VERSION 5.8 ;
BUSBITCHARS "[]" ;
DIVIDERCHAR "/" ;
UNITS
    DATABASE MICRONS 1000 ;
END UNITS

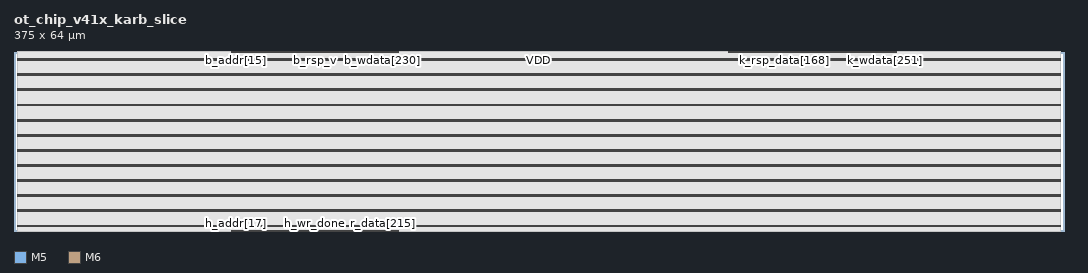
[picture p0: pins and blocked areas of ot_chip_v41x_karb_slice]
MACRO ot_chip_v41x_karb_slice
  FOREIGN ot_chip_v41x_karb_slice 0 0 ;
  CLASS BLOCK ;
  SIZE 375 BY 64 ;
  PIN b_addr[0]
    DIRECTION INPUT ;
    USE SIGNAL ;
    PORT
      LAYER M5 ;
        RECT  77.856 63.916 77.88 64 ;
    END
  END b_addr[0]
  PIN b_addr[10]
    DIRECTION INPUT ;
    USE SIGNAL ;
    PORT
      LAYER M5 ;
        RECT  78.816 63.916 78.84 64 ;
    END
  END b_addr[10]
  PIN b_addr[11]
    DIRECTION INPUT ;
    USE SIGNAL ;
    PORT
      LAYER M5 ;
        RECT  78.912 63.916 78.936 64 ;
    END
  END b_addr[11]
  PIN b_addr[12]
    DIRECTION INPUT ;
    USE SIGNAL ;
    PORT
      LAYER M5 ;
        RECT  79.008 63.916 79.032 64 ;
    END
  END b_addr[12]
  PIN b_addr[13]
    DIRECTION INPUT ;
    USE SIGNAL ;
    PORT
      LAYER M5 ;
        RECT  79.104 63.916 79.128 64 ;
    END
  END b_addr[13]
  PIN b_addr[14]
    DIRECTION INPUT ;
    USE SIGNAL ;
    PORT
      LAYER M5 ;
        RECT  79.2 63.916 79.224 64 ;
    END
  END b_addr[14]
  PIN b_addr[15]
    DIRECTION INPUT ;
    USE SIGNAL ;
    PORT
      LAYER M5 ;
        RECT  79.296 63.916 79.32 64 ;
    END
  END b_addr[15]
  PIN b_addr[16]
    DIRECTION INPUT ;
    USE SIGNAL ;
    PORT
      LAYER M5 ;
        RECT  79.392 63.916 79.416 64 ;
    END
  END b_addr[16]
  PIN b_addr[17]
    DIRECTION INPUT ;
    USE SIGNAL ;
    PORT
      LAYER M5 ;
        RECT  79.488 63.916 79.512 64 ;
    END
  END b_addr[17]
  PIN b_addr[18]
    DIRECTION INPUT ;
    USE SIGNAL ;
    PORT
      LAYER M5 ;
        RECT  79.584 63.916 79.608 64 ;
    END
  END b_addr[18]
  PIN b_addr[19]
    DIRECTION INPUT ;
    USE SIGNAL ;
    PORT
      LAYER M5 ;
        RECT  79.68 63.916 79.704 64 ;
    END
  END b_addr[19]
  PIN b_addr[1]
    DIRECTION INPUT ;
    USE SIGNAL ;
    PORT
      LAYER M5 ;
        RECT  77.952 63.916 77.976 64 ;
    END
  END b_addr[1]
  PIN b_addr[20]
    DIRECTION INPUT ;
    USE SIGNAL ;
    PORT
      LAYER M5 ;
        RECT  79.776 63.916 79.8 64 ;
    END
  END b_addr[20]
  PIN b_addr[21]
    DIRECTION INPUT ;
    USE SIGNAL ;
    PORT
      LAYER M5 ;
        RECT  79.872 63.916 79.896 64 ;
    END
  END b_addr[21]
  PIN b_addr[22]
    DIRECTION INPUT ;
    USE SIGNAL ;
    PORT
      LAYER M5 ;
        RECT  79.968 63.916 79.992 64 ;
    END
  END b_addr[22]
  PIN b_addr[23]
    DIRECTION INPUT ;
    USE SIGNAL ;
    PORT
      LAYER M5 ;
        RECT  80.064 63.916 80.088 64 ;
    END
  END b_addr[23]
  PIN b_addr[24]
    DIRECTION INPUT ;
    USE SIGNAL ;
    PORT
      LAYER M5 ;
        RECT  80.16 63.916 80.184 64 ;
    END
  END b_addr[24]
  PIN b_addr[25]
    DIRECTION INPUT ;
    USE SIGNAL ;
    PORT
      LAYER M5 ;
        RECT  80.256 63.916 80.28 64 ;
    END
  END b_addr[25]
  PIN b_addr[26]
    DIRECTION INPUT ;
    USE SIGNAL ;
    PORT
      LAYER M5 ;
        RECT  80.352 63.916 80.376 64 ;
    END
  END b_addr[26]
  PIN b_addr[27]
    DIRECTION INPUT ;
    USE SIGNAL ;
    PORT
      LAYER M5 ;
        RECT  80.448 63.916 80.472 64 ;
    END
  END b_addr[27]
  PIN b_addr[28]
    DIRECTION INPUT ;
    USE SIGNAL ;
    PORT
      LAYER M5 ;
        RECT  80.544 63.916 80.568 64 ;
    END
  END b_addr[28]
  PIN b_addr[29]
    DIRECTION INPUT ;
    USE SIGNAL ;
    PORT
      LAYER M5 ;
        RECT  80.64 63.916 80.664 64 ;
    END
  END b_addr[29]
  PIN b_addr[2]
    DIRECTION INPUT ;
    USE SIGNAL ;
    PORT
      LAYER M5 ;
        RECT  78.048 63.916 78.072 64 ;
    END
  END b_addr[2]
  PIN b_addr[3]
    DIRECTION INPUT ;
    USE SIGNAL ;
    PORT
      LAYER M5 ;
        RECT  78.144 63.916 78.168 64 ;
    END
  END b_addr[3]
  PIN b_addr[4]
    DIRECTION INPUT ;
    USE SIGNAL ;
    PORT
      LAYER M5 ;
        RECT  78.24 63.916 78.264 64 ;
    END
  END b_addr[4]
  PIN b_addr[5]
    DIRECTION INPUT ;
    USE SIGNAL ;
    PORT
      LAYER M5 ;
        RECT  78.336 63.916 78.36 64 ;
    END
  END b_addr[5]
  PIN b_addr[6]
    DIRECTION INPUT ;
    USE SIGNAL ;
    PORT
      LAYER M5 ;
        RECT  78.432 63.916 78.456 64 ;
    END
  END b_addr[6]
  PIN b_addr[7]
    DIRECTION INPUT ;
    USE SIGNAL ;
    PORT
      LAYER M5 ;
        RECT  78.528 63.916 78.552 64 ;
    END
  END b_addr[7]
  PIN b_addr[8]
    DIRECTION INPUT ;
    USE SIGNAL ;
    PORT
      LAYER M5 ;
        RECT  78.624 63.916 78.648 64 ;
    END
  END b_addr[8]
  PIN b_addr[9]
    DIRECTION INPUT ;
    USE SIGNAL ;
    PORT
      LAYER M5 ;
        RECT  78.72 63.916 78.744 64 ;
    END
  END b_addr[9]
  PIN b_grant
    DIRECTION OUTPUT ;
    USE SIGNAL ;
    PORT
      LAYER M5 ;
        RECT  255.168 63.916 255.192 64 ;
    END
  END b_grant
  PIN b_len[0]
    DIRECTION INPUT ;
    USE SIGNAL ;
    PORT
      LAYER M5 ;
        RECT  80.736 63.916 80.76 64 ;
    END
  END b_len[0]
  PIN b_len[1]
    DIRECTION INPUT ;
    USE SIGNAL ;
    PORT
      LAYER M5 ;
        RECT  80.832 63.916 80.856 64 ;
    END
  END b_len[1]
  PIN b_len[2]
    DIRECTION INPUT ;
    USE SIGNAL ;
    PORT
      LAYER M5 ;
        RECT  80.928 63.916 80.952 64 ;
    END
  END b_len[2]
  PIN b_len[3]
    DIRECTION INPUT ;
    USE SIGNAL ;
    PORT
      LAYER M5 ;
        RECT  81.024 63.916 81.048 64 ;
    END
  END b_len[3]
  PIN b_rdy
    DIRECTION OUTPUT ;
    USE SIGNAL ;
    PORT
      LAYER M5 ;
        RECT  81.12 63.916 81.144 64 ;
    END
  END b_rdy
  PIN b_rsp_beat[0]
    DIRECTION OUTPUT ;
    USE SIGNAL ;
    PORT
      LAYER M5 ;
        RECT  81.216 63.916 81.24 64 ;
    END
  END b_rsp_beat[0]
  PIN b_rsp_beat[1]
    DIRECTION OUTPUT ;
    USE SIGNAL ;
    PORT
      LAYER M5 ;
        RECT  81.312 63.916 81.336 64 ;
    END
  END b_rsp_beat[1]
  PIN b_rsp_beat[2]
    DIRECTION OUTPUT ;
    USE SIGNAL ;
    PORT
      LAYER M5 ;
        RECT  81.408 63.916 81.432 64 ;
    END
  END b_rsp_beat[2]
  PIN b_rsp_beat[3]
    DIRECTION OUTPUT ;
    USE SIGNAL ;
    PORT
      LAYER M5 ;
        RECT  81.504 63.916 81.528 64 ;
    END
  END b_rsp_beat[3]
  PIN b_rsp_data[0]
    DIRECTION OUTPUT ;
    USE SIGNAL ;
    PORT
      LAYER M5 ;
        RECT  81.6 63.916 81.624 64 ;
    END
  END b_rsp_data[0]
  PIN b_rsp_data[100]
    DIRECTION OUTPUT ;
    USE SIGNAL ;
    PORT
      LAYER M5 ;
        RECT  91.2 63.916 91.224 64 ;
    END
  END b_rsp_data[100]
  PIN b_rsp_data[101]
    DIRECTION OUTPUT ;
    USE SIGNAL ;
    PORT
      LAYER M5 ;
        RECT  91.296 63.916 91.32 64 ;
    END
  END b_rsp_data[101]
  PIN b_rsp_data[102]
    DIRECTION OUTPUT ;
    USE SIGNAL ;
    PORT
      LAYER M5 ;
        RECT  91.392 63.916 91.416 64 ;
    END
  END b_rsp_data[102]
  PIN b_rsp_data[103]
    DIRECTION OUTPUT ;
    USE SIGNAL ;
    PORT
      LAYER M5 ;
        RECT  91.488 63.916 91.512 64 ;
    END
  END b_rsp_data[103]
  PIN b_rsp_data[104]
    DIRECTION OUTPUT ;
    USE SIGNAL ;
    PORT
      LAYER M5 ;
        RECT  91.584 63.916 91.608 64 ;
    END
  END b_rsp_data[104]
  PIN b_rsp_data[105]
    DIRECTION OUTPUT ;
    USE SIGNAL ;
    PORT
      LAYER M5 ;
        RECT  91.68 63.916 91.704 64 ;
    END
  END b_rsp_data[105]
  PIN b_rsp_data[106]
    DIRECTION OUTPUT ;
    USE SIGNAL ;
    PORT
      LAYER M5 ;
        RECT  91.776 63.916 91.8 64 ;
    END
  END b_rsp_data[106]
  PIN b_rsp_data[107]
    DIRECTION OUTPUT ;
    USE SIGNAL ;
    PORT
      LAYER M5 ;
        RECT  91.872 63.916 91.896 64 ;
    END
  END b_rsp_data[107]
  PIN b_rsp_data[108]
    DIRECTION OUTPUT ;
    USE SIGNAL ;
    PORT
      LAYER M5 ;
        RECT  91.968 63.916 91.992 64 ;
    END
  END b_rsp_data[108]
  PIN b_rsp_data[109]
    DIRECTION OUTPUT ;
    USE SIGNAL ;
    PORT
      LAYER M5 ;
        RECT  92.064 63.916 92.088 64 ;
    END
  END b_rsp_data[109]
  PIN b_rsp_data[10]
    DIRECTION OUTPUT ;
    USE SIGNAL ;
    PORT
      LAYER M5 ;
        RECT  82.56 63.916 82.584 64 ;
    END
  END b_rsp_data[10]
  PIN b_rsp_data[110]
    DIRECTION OUTPUT ;
    USE SIGNAL ;
    PORT
      LAYER M5 ;
        RECT  92.16 63.916 92.184 64 ;
    END
  END b_rsp_data[110]
  PIN b_rsp_data[111]
    DIRECTION OUTPUT ;
    USE SIGNAL ;
    PORT
      LAYER M5 ;
        RECT  92.256 63.916 92.28 64 ;
    END
  END b_rsp_data[111]
  PIN b_rsp_data[112]
    DIRECTION OUTPUT ;
    USE SIGNAL ;
    PORT
      LAYER M5 ;
        RECT  92.352 63.916 92.376 64 ;
    END
  END b_rsp_data[112]
  PIN b_rsp_data[113]
    DIRECTION OUTPUT ;
    USE SIGNAL ;
    PORT
      LAYER M5 ;
        RECT  92.448 63.916 92.472 64 ;
    END
  END b_rsp_data[113]
  PIN b_rsp_data[114]
    DIRECTION OUTPUT ;
    USE SIGNAL ;
    PORT
      LAYER M5 ;
        RECT  92.544 63.916 92.568 64 ;
    END
  END b_rsp_data[114]
  PIN b_rsp_data[115]
    DIRECTION OUTPUT ;
    USE SIGNAL ;
    PORT
      LAYER M5 ;
        RECT  92.64 63.916 92.664 64 ;
    END
  END b_rsp_data[115]
  PIN b_rsp_data[116]
    DIRECTION OUTPUT ;
    USE SIGNAL ;
    PORT
      LAYER M5 ;
        RECT  92.736 63.916 92.76 64 ;
    END
  END b_rsp_data[116]
  PIN b_rsp_data[117]
    DIRECTION OUTPUT ;
    USE SIGNAL ;
    PORT
      LAYER M5 ;
        RECT  92.832 63.916 92.856 64 ;
    END
  END b_rsp_data[117]
  PIN b_rsp_data[118]
    DIRECTION OUTPUT ;
    USE SIGNAL ;
    PORT
      LAYER M5 ;
        RECT  92.928 63.916 92.952 64 ;
    END
  END b_rsp_data[118]
  PIN b_rsp_data[119]
    DIRECTION OUTPUT ;
    USE SIGNAL ;
    PORT
      LAYER M5 ;
        RECT  93.024 63.916 93.048 64 ;
    END
  END b_rsp_data[119]
  PIN b_rsp_data[11]
    DIRECTION OUTPUT ;
    USE SIGNAL ;
    PORT
      LAYER M5 ;
        RECT  82.656 63.916 82.68 64 ;
    END
  END b_rsp_data[11]
  PIN b_rsp_data[120]
    DIRECTION OUTPUT ;
    USE SIGNAL ;
    PORT
      LAYER M5 ;
        RECT  93.12 63.916 93.144 64 ;
    END
  END b_rsp_data[120]
  PIN b_rsp_data[121]
    DIRECTION OUTPUT ;
    USE SIGNAL ;
    PORT
      LAYER M5 ;
        RECT  93.216 63.916 93.24 64 ;
    END
  END b_rsp_data[121]
  PIN b_rsp_data[122]
    DIRECTION OUTPUT ;
    USE SIGNAL ;
    PORT
      LAYER M5 ;
        RECT  93.312 63.916 93.336 64 ;
    END
  END b_rsp_data[122]
  PIN b_rsp_data[123]
    DIRECTION OUTPUT ;
    USE SIGNAL ;
    PORT
      LAYER M5 ;
        RECT  93.408 63.916 93.432 64 ;
    END
  END b_rsp_data[123]
  PIN b_rsp_data[124]
    DIRECTION OUTPUT ;
    USE SIGNAL ;
    PORT
      LAYER M5 ;
        RECT  93.504 63.916 93.528 64 ;
    END
  END b_rsp_data[124]
  PIN b_rsp_data[125]
    DIRECTION OUTPUT ;
    USE SIGNAL ;
    PORT
      LAYER M5 ;
        RECT  93.6 63.916 93.624 64 ;
    END
  END b_rsp_data[125]
  PIN b_rsp_data[126]
    DIRECTION OUTPUT ;
    USE SIGNAL ;
    PORT
      LAYER M5 ;
        RECT  93.696 63.916 93.72 64 ;
    END
  END b_rsp_data[126]
  PIN b_rsp_data[127]
    DIRECTION OUTPUT ;
    USE SIGNAL ;
    PORT
      LAYER M5 ;
        RECT  93.792 63.916 93.816 64 ;
    END
  END b_rsp_data[127]
  PIN b_rsp_data[128]
    DIRECTION OUTPUT ;
    USE SIGNAL ;
    PORT
      LAYER M5 ;
        RECT  93.888 63.916 93.912 64 ;
    END
  END b_rsp_data[128]
  PIN b_rsp_data[129]
    DIRECTION OUTPUT ;
    USE SIGNAL ;
    PORT
      LAYER M5 ;
        RECT  93.984 63.916 94.008 64 ;
    END
  END b_rsp_data[129]
  PIN b_rsp_data[12]
    DIRECTION OUTPUT ;
    USE SIGNAL ;
    PORT
      LAYER M5 ;
        RECT  82.752 63.916 82.776 64 ;
    END
  END b_rsp_data[12]
  PIN b_rsp_data[130]
    DIRECTION OUTPUT ;
    USE SIGNAL ;
    PORT
      LAYER M5 ;
        RECT  94.08 63.916 94.104 64 ;
    END
  END b_rsp_data[130]
  PIN b_rsp_data[131]
    DIRECTION OUTPUT ;
    USE SIGNAL ;
    PORT
      LAYER M5 ;
        RECT  94.176 63.916 94.2 64 ;
    END
  END b_rsp_data[131]
  PIN b_rsp_data[132]
    DIRECTION OUTPUT ;
    USE SIGNAL ;
    PORT
      LAYER M5 ;
        RECT  94.272 63.916 94.296 64 ;
    END
  END b_rsp_data[132]
  PIN b_rsp_data[133]
    DIRECTION OUTPUT ;
    USE SIGNAL ;
    PORT
      LAYER M5 ;
        RECT  94.368 63.916 94.392 64 ;
    END
  END b_rsp_data[133]
  PIN b_rsp_data[134]
    DIRECTION OUTPUT ;
    USE SIGNAL ;
    PORT
      LAYER M5 ;
        RECT  94.464 63.916 94.488 64 ;
    END
  END b_rsp_data[134]
  PIN b_rsp_data[135]
    DIRECTION OUTPUT ;
    USE SIGNAL ;
    PORT
      LAYER M5 ;
        RECT  94.56 63.916 94.584 64 ;
    END
  END b_rsp_data[135]
  PIN b_rsp_data[136]
    DIRECTION OUTPUT ;
    USE SIGNAL ;
    PORT
      LAYER M5 ;
        RECT  94.656 63.916 94.68 64 ;
    END
  END b_rsp_data[136]
  PIN b_rsp_data[137]
    DIRECTION OUTPUT ;
    USE SIGNAL ;
    PORT
      LAYER M5 ;
        RECT  94.752 63.916 94.776 64 ;
    END
  END b_rsp_data[137]
  PIN b_rsp_data[138]
    DIRECTION OUTPUT ;
    USE SIGNAL ;
    PORT
      LAYER M5 ;
        RECT  94.848 63.916 94.872 64 ;
    END
  END b_rsp_data[138]
  PIN b_rsp_data[139]
    DIRECTION OUTPUT ;
    USE SIGNAL ;
    PORT
      LAYER M5 ;
        RECT  94.944 63.916 94.968 64 ;
    END
  END b_rsp_data[139]
  PIN b_rsp_data[13]
    DIRECTION OUTPUT ;
    USE SIGNAL ;
    PORT
      LAYER M5 ;
        RECT  82.848 63.916 82.872 64 ;
    END
  END b_rsp_data[13]
  PIN b_rsp_data[140]
    DIRECTION OUTPUT ;
    USE SIGNAL ;
    PORT
      LAYER M5 ;
        RECT  95.04 63.916 95.064 64 ;
    END
  END b_rsp_data[140]
  PIN b_rsp_data[141]
    DIRECTION OUTPUT ;
    USE SIGNAL ;
    PORT
      LAYER M5 ;
        RECT  95.136 63.916 95.16 64 ;
    END
  END b_rsp_data[141]
  PIN b_rsp_data[142]
    DIRECTION OUTPUT ;
    USE SIGNAL ;
    PORT
      LAYER M5 ;
        RECT  95.232 63.916 95.256 64 ;
    END
  END b_rsp_data[142]
  PIN b_rsp_data[143]
    DIRECTION OUTPUT ;
    USE SIGNAL ;
    PORT
      LAYER M5 ;
        RECT  95.328 63.916 95.352 64 ;
    END
  END b_rsp_data[143]
  PIN b_rsp_data[144]
    DIRECTION OUTPUT ;
    USE SIGNAL ;
    PORT
      LAYER M5 ;
        RECT  95.424 63.916 95.448 64 ;
    END
  END b_rsp_data[144]
  PIN b_rsp_data[145]
    DIRECTION OUTPUT ;
    USE SIGNAL ;
    PORT
      LAYER M5 ;
        RECT  95.52 63.916 95.544 64 ;
    END
  END b_rsp_data[145]
  PIN b_rsp_data[146]
    DIRECTION OUTPUT ;
    USE SIGNAL ;
    PORT
      LAYER M5 ;
        RECT  95.616 63.916 95.64 64 ;
    END
  END b_rsp_data[146]
  PIN b_rsp_data[147]
    DIRECTION OUTPUT ;
    USE SIGNAL ;
    PORT
      LAYER M5 ;
        RECT  95.712 63.916 95.736 64 ;
    END
  END b_rsp_data[147]
  PIN b_rsp_data[148]
    DIRECTION OUTPUT ;
    USE SIGNAL ;
    PORT
      LAYER M5 ;
        RECT  95.808 63.916 95.832 64 ;
    END
  END b_rsp_data[148]
  PIN b_rsp_data[149]
    DIRECTION OUTPUT ;
    USE SIGNAL ;
    PORT
      LAYER M5 ;
        RECT  95.904 63.916 95.928 64 ;
    END
  END b_rsp_data[149]
  PIN b_rsp_data[14]
    DIRECTION OUTPUT ;
    USE SIGNAL ;
    PORT
      LAYER M5 ;
        RECT  82.944 63.916 82.968 64 ;
    END
  END b_rsp_data[14]
  PIN b_rsp_data[150]
    DIRECTION OUTPUT ;
    USE SIGNAL ;
    PORT
      LAYER M5 ;
        RECT  96 63.916 96.024 64 ;
    END
  END b_rsp_data[150]
  PIN b_rsp_data[151]
    DIRECTION OUTPUT ;
    USE SIGNAL ;
    PORT
      LAYER M5 ;
        RECT  96.096 63.916 96.12 64 ;
    END
  END b_rsp_data[151]
  PIN b_rsp_data[152]
    DIRECTION OUTPUT ;
    USE SIGNAL ;
    PORT
      LAYER M5 ;
        RECT  96.192 63.916 96.216 64 ;
    END
  END b_rsp_data[152]
  PIN b_rsp_data[153]
    DIRECTION OUTPUT ;
    USE SIGNAL ;
    PORT
      LAYER M5 ;
        RECT  96.288 63.916 96.312 64 ;
    END
  END b_rsp_data[153]
  PIN b_rsp_data[154]
    DIRECTION OUTPUT ;
    USE SIGNAL ;
    PORT
      LAYER M5 ;
        RECT  96.384 63.916 96.408 64 ;
    END
  END b_rsp_data[154]
  PIN b_rsp_data[155]
    DIRECTION OUTPUT ;
    USE SIGNAL ;
    PORT
      LAYER M5 ;
        RECT  96.48 63.916 96.504 64 ;
    END
  END b_rsp_data[155]
  PIN b_rsp_data[156]
    DIRECTION OUTPUT ;
    USE SIGNAL ;
    PORT
      LAYER M5 ;
        RECT  96.576 63.916 96.6 64 ;
    END
  END b_rsp_data[156]
  PIN b_rsp_data[157]
    DIRECTION OUTPUT ;
    USE SIGNAL ;
    PORT
      LAYER M5 ;
        RECT  96.672 63.916 96.696 64 ;
    END
  END b_rsp_data[157]
  PIN b_rsp_data[158]
    DIRECTION OUTPUT ;
    USE SIGNAL ;
    PORT
      LAYER M5 ;
        RECT  96.768 63.916 96.792 64 ;
    END
  END b_rsp_data[158]
  PIN b_rsp_data[159]
    DIRECTION OUTPUT ;
    USE SIGNAL ;
    PORT
      LAYER M5 ;
        RECT  96.864 63.916 96.888 64 ;
    END
  END b_rsp_data[159]
  PIN b_rsp_data[15]
    DIRECTION OUTPUT ;
    USE SIGNAL ;
    PORT
      LAYER M5 ;
        RECT  83.04 63.916 83.064 64 ;
    END
  END b_rsp_data[15]
  PIN b_rsp_data[160]
    DIRECTION OUTPUT ;
    USE SIGNAL ;
    PORT
      LAYER M5 ;
        RECT  96.96 63.916 96.984 64 ;
    END
  END b_rsp_data[160]
  PIN b_rsp_data[161]
    DIRECTION OUTPUT ;
    USE SIGNAL ;
    PORT
      LAYER M5 ;
        RECT  97.056 63.916 97.08 64 ;
    END
  END b_rsp_data[161]
  PIN b_rsp_data[162]
    DIRECTION OUTPUT ;
    USE SIGNAL ;
    PORT
      LAYER M5 ;
        RECT  97.152 63.916 97.176 64 ;
    END
  END b_rsp_data[162]
  PIN b_rsp_data[163]
    DIRECTION OUTPUT ;
    USE SIGNAL ;
    PORT
      LAYER M5 ;
        RECT  97.248 63.916 97.272 64 ;
    END
  END b_rsp_data[163]
  PIN b_rsp_data[164]
    DIRECTION OUTPUT ;
    USE SIGNAL ;
    PORT
      LAYER M5 ;
        RECT  97.344 63.916 97.368 64 ;
    END
  END b_rsp_data[164]
  PIN b_rsp_data[165]
    DIRECTION OUTPUT ;
    USE SIGNAL ;
    PORT
      LAYER M5 ;
        RECT  97.44 63.916 97.464 64 ;
    END
  END b_rsp_data[165]
  PIN b_rsp_data[166]
    DIRECTION OUTPUT ;
    USE SIGNAL ;
    PORT
      LAYER M5 ;
        RECT  97.536 63.916 97.56 64 ;
    END
  END b_rsp_data[166]
  PIN b_rsp_data[167]
    DIRECTION OUTPUT ;
    USE SIGNAL ;
    PORT
      LAYER M5 ;
        RECT  97.632 63.916 97.656 64 ;
    END
  END b_rsp_data[167]
  PIN b_rsp_data[168]
    DIRECTION OUTPUT ;
    USE SIGNAL ;
    PORT
      LAYER M5 ;
        RECT  97.728 63.916 97.752 64 ;
    END
  END b_rsp_data[168]
  PIN b_rsp_data[169]
    DIRECTION OUTPUT ;
    USE SIGNAL ;
    PORT
      LAYER M5 ;
        RECT  97.824 63.916 97.848 64 ;
    END
  END b_rsp_data[169]
  PIN b_rsp_data[16]
    DIRECTION OUTPUT ;
    USE SIGNAL ;
    PORT
      LAYER M5 ;
        RECT  83.136 63.916 83.16 64 ;
    END
  END b_rsp_data[16]
  PIN b_rsp_data[170]
    DIRECTION OUTPUT ;
    USE SIGNAL ;
    PORT
      LAYER M5 ;
        RECT  97.92 63.916 97.944 64 ;
    END
  END b_rsp_data[170]
  PIN b_rsp_data[171]
    DIRECTION OUTPUT ;
    USE SIGNAL ;
    PORT
      LAYER M5 ;
        RECT  98.016 63.916 98.04 64 ;
    END
  END b_rsp_data[171]
  PIN b_rsp_data[172]
    DIRECTION OUTPUT ;
    USE SIGNAL ;
    PORT
      LAYER M5 ;
        RECT  98.112 63.916 98.136 64 ;
    END
  END b_rsp_data[172]
  PIN b_rsp_data[173]
    DIRECTION OUTPUT ;
    USE SIGNAL ;
    PORT
      LAYER M5 ;
        RECT  98.208 63.916 98.232 64 ;
    END
  END b_rsp_data[173]
  PIN b_rsp_data[174]
    DIRECTION OUTPUT ;
    USE SIGNAL ;
    PORT
      LAYER M5 ;
        RECT  98.304 63.916 98.328 64 ;
    END
  END b_rsp_data[174]
  PIN b_rsp_data[175]
    DIRECTION OUTPUT ;
    USE SIGNAL ;
    PORT
      LAYER M5 ;
        RECT  98.4 63.916 98.424 64 ;
    END
  END b_rsp_data[175]
  PIN b_rsp_data[176]
    DIRECTION OUTPUT ;
    USE SIGNAL ;
    PORT
      LAYER M5 ;
        RECT  98.496 63.916 98.52 64 ;
    END
  END b_rsp_data[176]
  PIN b_rsp_data[177]
    DIRECTION OUTPUT ;
    USE SIGNAL ;
    PORT
      LAYER M5 ;
        RECT  98.592 63.916 98.616 64 ;
    END
  END b_rsp_data[177]
  PIN b_rsp_data[178]
    DIRECTION OUTPUT ;
    USE SIGNAL ;
    PORT
      LAYER M5 ;
        RECT  98.688 63.916 98.712 64 ;
    END
  END b_rsp_data[178]
  PIN b_rsp_data[179]
    DIRECTION OUTPUT ;
    USE SIGNAL ;
    PORT
      LAYER M5 ;
        RECT  98.784 63.916 98.808 64 ;
    END
  END b_rsp_data[179]
  PIN b_rsp_data[17]
    DIRECTION OUTPUT ;
    USE SIGNAL ;
    PORT
      LAYER M5 ;
        RECT  83.232 63.916 83.256 64 ;
    END
  END b_rsp_data[17]
  PIN b_rsp_data[180]
    DIRECTION OUTPUT ;
    USE SIGNAL ;
    PORT
      LAYER M5 ;
        RECT  98.88 63.916 98.904 64 ;
    END
  END b_rsp_data[180]
  PIN b_rsp_data[181]
    DIRECTION OUTPUT ;
    USE SIGNAL ;
    PORT
      LAYER M5 ;
        RECT  98.976 63.916 99 64 ;
    END
  END b_rsp_data[181]
  PIN b_rsp_data[182]
    DIRECTION OUTPUT ;
    USE SIGNAL ;
    PORT
      LAYER M5 ;
        RECT  99.072 63.916 99.096 64 ;
    END
  END b_rsp_data[182]
  PIN b_rsp_data[183]
    DIRECTION OUTPUT ;
    USE SIGNAL ;
    PORT
      LAYER M5 ;
        RECT  99.168 63.916 99.192 64 ;
    END
  END b_rsp_data[183]
  PIN b_rsp_data[184]
    DIRECTION OUTPUT ;
    USE SIGNAL ;
    PORT
      LAYER M5 ;
        RECT  99.264 63.916 99.288 64 ;
    END
  END b_rsp_data[184]
  PIN b_rsp_data[185]
    DIRECTION OUTPUT ;
    USE SIGNAL ;
    PORT
      LAYER M5 ;
        RECT  99.36 63.916 99.384 64 ;
    END
  END b_rsp_data[185]
  PIN b_rsp_data[186]
    DIRECTION OUTPUT ;
    USE SIGNAL ;
    PORT
      LAYER M5 ;
        RECT  99.456 63.916 99.48 64 ;
    END
  END b_rsp_data[186]
  PIN b_rsp_data[187]
    DIRECTION OUTPUT ;
    USE SIGNAL ;
    PORT
      LAYER M5 ;
        RECT  99.552 63.916 99.576 64 ;
    END
  END b_rsp_data[187]
  PIN b_rsp_data[188]
    DIRECTION OUTPUT ;
    USE SIGNAL ;
    PORT
      LAYER M5 ;
        RECT  99.648 63.916 99.672 64 ;
    END
  END b_rsp_data[188]
  PIN b_rsp_data[189]
    DIRECTION OUTPUT ;
    USE SIGNAL ;
    PORT
      LAYER M5 ;
        RECT  99.744 63.916 99.768 64 ;
    END
  END b_rsp_data[189]
  PIN b_rsp_data[18]
    DIRECTION OUTPUT ;
    USE SIGNAL ;
    PORT
      LAYER M5 ;
        RECT  83.328 63.916 83.352 64 ;
    END
  END b_rsp_data[18]
  PIN b_rsp_data[190]
    DIRECTION OUTPUT ;
    USE SIGNAL ;
    PORT
      LAYER M5 ;
        RECT  99.84 63.916 99.864 64 ;
    END
  END b_rsp_data[190]
  PIN b_rsp_data[191]
    DIRECTION OUTPUT ;
    USE SIGNAL ;
    PORT
      LAYER M5 ;
        RECT  99.936 63.916 99.96 64 ;
    END
  END b_rsp_data[191]
  PIN b_rsp_data[192]
    DIRECTION OUTPUT ;
    USE SIGNAL ;
    PORT
      LAYER M5 ;
        RECT  100.032 63.916 100.056 64 ;
    END
  END b_rsp_data[192]
  PIN b_rsp_data[193]
    DIRECTION OUTPUT ;
    USE SIGNAL ;
    PORT
      LAYER M5 ;
        RECT  100.128 63.916 100.152 64 ;
    END
  END b_rsp_data[193]
  PIN b_rsp_data[194]
    DIRECTION OUTPUT ;
    USE SIGNAL ;
    PORT
      LAYER M5 ;
        RECT  100.224 63.916 100.248 64 ;
    END
  END b_rsp_data[194]
  PIN b_rsp_data[195]
    DIRECTION OUTPUT ;
    USE SIGNAL ;
    PORT
      LAYER M5 ;
        RECT  100.32 63.916 100.344 64 ;
    END
  END b_rsp_data[195]
  PIN b_rsp_data[196]
    DIRECTION OUTPUT ;
    USE SIGNAL ;
    PORT
      LAYER M5 ;
        RECT  100.416 63.916 100.44 64 ;
    END
  END b_rsp_data[196]
  PIN b_rsp_data[197]
    DIRECTION OUTPUT ;
    USE SIGNAL ;
    PORT
      LAYER M5 ;
        RECT  100.512 63.916 100.536 64 ;
    END
  END b_rsp_data[197]
  PIN b_rsp_data[198]
    DIRECTION OUTPUT ;
    USE SIGNAL ;
    PORT
      LAYER M5 ;
        RECT  100.608 63.916 100.632 64 ;
    END
  END b_rsp_data[198]
  PIN b_rsp_data[199]
    DIRECTION OUTPUT ;
    USE SIGNAL ;
    PORT
      LAYER M5 ;
        RECT  100.704 63.916 100.728 64 ;
    END
  END b_rsp_data[199]
  PIN b_rsp_data[19]
    DIRECTION OUTPUT ;
    USE SIGNAL ;
    PORT
      LAYER M5 ;
        RECT  83.424 63.916 83.448 64 ;
    END
  END b_rsp_data[19]
  PIN b_rsp_data[1]
    DIRECTION OUTPUT ;
    USE SIGNAL ;
    PORT
      LAYER M5 ;
        RECT  81.696 63.916 81.72 64 ;
    END
  END b_rsp_data[1]
  PIN b_rsp_data[200]
    DIRECTION OUTPUT ;
    USE SIGNAL ;
    PORT
      LAYER M5 ;
        RECT  100.8 63.916 100.824 64 ;
    END
  END b_rsp_data[200]
  PIN b_rsp_data[201]
    DIRECTION OUTPUT ;
    USE SIGNAL ;
    PORT
      LAYER M5 ;
        RECT  100.896 63.916 100.92 64 ;
    END
  END b_rsp_data[201]
  PIN b_rsp_data[202]
    DIRECTION OUTPUT ;
    USE SIGNAL ;
    PORT
      LAYER M5 ;
        RECT  100.992 63.916 101.016 64 ;
    END
  END b_rsp_data[202]
  PIN b_rsp_data[203]
    DIRECTION OUTPUT ;
    USE SIGNAL ;
    PORT
      LAYER M5 ;
        RECT  101.088 63.916 101.112 64 ;
    END
  END b_rsp_data[203]
  PIN b_rsp_data[204]
    DIRECTION OUTPUT ;
    USE SIGNAL ;
    PORT
      LAYER M5 ;
        RECT  101.184 63.916 101.208 64 ;
    END
  END b_rsp_data[204]
  PIN b_rsp_data[205]
    DIRECTION OUTPUT ;
    USE SIGNAL ;
    PORT
      LAYER M5 ;
        RECT  101.28 63.916 101.304 64 ;
    END
  END b_rsp_data[205]
  PIN b_rsp_data[206]
    DIRECTION OUTPUT ;
    USE SIGNAL ;
    PORT
      LAYER M5 ;
        RECT  101.376 63.916 101.4 64 ;
    END
  END b_rsp_data[206]
  PIN b_rsp_data[207]
    DIRECTION OUTPUT ;
    USE SIGNAL ;
    PORT
      LAYER M5 ;
        RECT  101.472 63.916 101.496 64 ;
    END
  END b_rsp_data[207]
  PIN b_rsp_data[208]
    DIRECTION OUTPUT ;
    USE SIGNAL ;
    PORT
      LAYER M5 ;
        RECT  101.568 63.916 101.592 64 ;
    END
  END b_rsp_data[208]
  PIN b_rsp_data[209]
    DIRECTION OUTPUT ;
    USE SIGNAL ;
    PORT
      LAYER M5 ;
        RECT  101.664 63.916 101.688 64 ;
    END
  END b_rsp_data[209]
  PIN b_rsp_data[20]
    DIRECTION OUTPUT ;
    USE SIGNAL ;
    PORT
      LAYER M5 ;
        RECT  83.52 63.916 83.544 64 ;
    END
  END b_rsp_data[20]
  PIN b_rsp_data[210]
    DIRECTION OUTPUT ;
    USE SIGNAL ;
    PORT
      LAYER M5 ;
        RECT  101.76 63.916 101.784 64 ;
    END
  END b_rsp_data[210]
  PIN b_rsp_data[211]
    DIRECTION OUTPUT ;
    USE SIGNAL ;
    PORT
      LAYER M5 ;
        RECT  101.856 63.916 101.88 64 ;
    END
  END b_rsp_data[211]
  PIN b_rsp_data[212]
    DIRECTION OUTPUT ;
    USE SIGNAL ;
    PORT
      LAYER M5 ;
        RECT  101.952 63.916 101.976 64 ;
    END
  END b_rsp_data[212]
  PIN b_rsp_data[213]
    DIRECTION OUTPUT ;
    USE SIGNAL ;
    PORT
      LAYER M5 ;
        RECT  102.048 63.916 102.072 64 ;
    END
  END b_rsp_data[213]
  PIN b_rsp_data[214]
    DIRECTION OUTPUT ;
    USE SIGNAL ;
    PORT
      LAYER M5 ;
        RECT  102.144 63.916 102.168 64 ;
    END
  END b_rsp_data[214]
  PIN b_rsp_data[215]
    DIRECTION OUTPUT ;
    USE SIGNAL ;
    PORT
      LAYER M5 ;
        RECT  102.24 63.916 102.264 64 ;
    END
  END b_rsp_data[215]
  PIN b_rsp_data[216]
    DIRECTION OUTPUT ;
    USE SIGNAL ;
    PORT
      LAYER M5 ;
        RECT  102.336 63.916 102.36 64 ;
    END
  END b_rsp_data[216]
  PIN b_rsp_data[217]
    DIRECTION OUTPUT ;
    USE SIGNAL ;
    PORT
      LAYER M5 ;
        RECT  102.432 63.916 102.456 64 ;
    END
  END b_rsp_data[217]
  PIN b_rsp_data[218]
    DIRECTION OUTPUT ;
    USE SIGNAL ;
    PORT
      LAYER M5 ;
        RECT  102.528 63.916 102.552 64 ;
    END
  END b_rsp_data[218]
  PIN b_rsp_data[219]
    DIRECTION OUTPUT ;
    USE SIGNAL ;
    PORT
      LAYER M5 ;
        RECT  102.624 63.916 102.648 64 ;
    END
  END b_rsp_data[219]
  PIN b_rsp_data[21]
    DIRECTION OUTPUT ;
    USE SIGNAL ;
    PORT
      LAYER M5 ;
        RECT  83.616 63.916 83.64 64 ;
    END
  END b_rsp_data[21]
  PIN b_rsp_data[220]
    DIRECTION OUTPUT ;
    USE SIGNAL ;
    PORT
      LAYER M5 ;
        RECT  102.72 63.916 102.744 64 ;
    END
  END b_rsp_data[220]
  PIN b_rsp_data[221]
    DIRECTION OUTPUT ;
    USE SIGNAL ;
    PORT
      LAYER M5 ;
        RECT  102.816 63.916 102.84 64 ;
    END
  END b_rsp_data[221]
  PIN b_rsp_data[222]
    DIRECTION OUTPUT ;
    USE SIGNAL ;
    PORT
      LAYER M5 ;
        RECT  102.912 63.916 102.936 64 ;
    END
  END b_rsp_data[222]
  PIN b_rsp_data[223]
    DIRECTION OUTPUT ;
    USE SIGNAL ;
    PORT
      LAYER M5 ;
        RECT  103.008 63.916 103.032 64 ;
    END
  END b_rsp_data[223]
  PIN b_rsp_data[224]
    DIRECTION OUTPUT ;
    USE SIGNAL ;
    PORT
      LAYER M5 ;
        RECT  103.104 63.916 103.128 64 ;
    END
  END b_rsp_data[224]
  PIN b_rsp_data[225]
    DIRECTION OUTPUT ;
    USE SIGNAL ;
    PORT
      LAYER M5 ;
        RECT  103.2 63.916 103.224 64 ;
    END
  END b_rsp_data[225]
  PIN b_rsp_data[226]
    DIRECTION OUTPUT ;
    USE SIGNAL ;
    PORT
      LAYER M5 ;
        RECT  103.296 63.916 103.32 64 ;
    END
  END b_rsp_data[226]
  PIN b_rsp_data[227]
    DIRECTION OUTPUT ;
    USE SIGNAL ;
    PORT
      LAYER M5 ;
        RECT  103.392 63.916 103.416 64 ;
    END
  END b_rsp_data[227]
  PIN b_rsp_data[228]
    DIRECTION OUTPUT ;
    USE SIGNAL ;
    PORT
      LAYER M5 ;
        RECT  103.488 63.916 103.512 64 ;
    END
  END b_rsp_data[228]
  PIN b_rsp_data[229]
    DIRECTION OUTPUT ;
    USE SIGNAL ;
    PORT
      LAYER M5 ;
        RECT  103.584 63.916 103.608 64 ;
    END
  END b_rsp_data[229]
  PIN b_rsp_data[22]
    DIRECTION OUTPUT ;
    USE SIGNAL ;
    PORT
      LAYER M5 ;
        RECT  83.712 63.916 83.736 64 ;
    END
  END b_rsp_data[22]
  PIN b_rsp_data[230]
    DIRECTION OUTPUT ;
    USE SIGNAL ;
    PORT
      LAYER M5 ;
        RECT  103.68 63.916 103.704 64 ;
    END
  END b_rsp_data[230]
  PIN b_rsp_data[231]
    DIRECTION OUTPUT ;
    USE SIGNAL ;
    PORT
      LAYER M5 ;
        RECT  103.776 63.916 103.8 64 ;
    END
  END b_rsp_data[231]
  PIN b_rsp_data[232]
    DIRECTION OUTPUT ;
    USE SIGNAL ;
    PORT
      LAYER M5 ;
        RECT  103.872 63.916 103.896 64 ;
    END
  END b_rsp_data[232]
  PIN b_rsp_data[233]
    DIRECTION OUTPUT ;
    USE SIGNAL ;
    PORT
      LAYER M5 ;
        RECT  103.968 63.916 103.992 64 ;
    END
  END b_rsp_data[233]
  PIN b_rsp_data[234]
    DIRECTION OUTPUT ;
    USE SIGNAL ;
    PORT
      LAYER M5 ;
        RECT  104.064 63.916 104.088 64 ;
    END
  END b_rsp_data[234]
  PIN b_rsp_data[235]
    DIRECTION OUTPUT ;
    USE SIGNAL ;
    PORT
      LAYER M5 ;
        RECT  104.16 63.916 104.184 64 ;
    END
  END b_rsp_data[235]
  PIN b_rsp_data[236]
    DIRECTION OUTPUT ;
    USE SIGNAL ;
    PORT
      LAYER M5 ;
        RECT  104.256 63.916 104.28 64 ;
    END
  END b_rsp_data[236]
  PIN b_rsp_data[237]
    DIRECTION OUTPUT ;
    USE SIGNAL ;
    PORT
      LAYER M5 ;
        RECT  104.352 63.916 104.376 64 ;
    END
  END b_rsp_data[237]
  PIN b_rsp_data[238]
    DIRECTION OUTPUT ;
    USE SIGNAL ;
    PORT
      LAYER M5 ;
        RECT  104.448 63.916 104.472 64 ;
    END
  END b_rsp_data[238]
  PIN b_rsp_data[239]
    DIRECTION OUTPUT ;
    USE SIGNAL ;
    PORT
      LAYER M5 ;
        RECT  104.544 63.916 104.568 64 ;
    END
  END b_rsp_data[239]
  PIN b_rsp_data[23]
    DIRECTION OUTPUT ;
    USE SIGNAL ;
    PORT
      LAYER M5 ;
        RECT  83.808 63.916 83.832 64 ;
    END
  END b_rsp_data[23]
  PIN b_rsp_data[240]
    DIRECTION OUTPUT ;
    USE SIGNAL ;
    PORT
      LAYER M5 ;
        RECT  104.64 63.916 104.664 64 ;
    END
  END b_rsp_data[240]
  PIN b_rsp_data[241]
    DIRECTION OUTPUT ;
    USE SIGNAL ;
    PORT
      LAYER M5 ;
        RECT  104.736 63.916 104.76 64 ;
    END
  END b_rsp_data[241]
  PIN b_rsp_data[242]
    DIRECTION OUTPUT ;
    USE SIGNAL ;
    PORT
      LAYER M5 ;
        RECT  104.832 63.916 104.856 64 ;
    END
  END b_rsp_data[242]
  PIN b_rsp_data[243]
    DIRECTION OUTPUT ;
    USE SIGNAL ;
    PORT
      LAYER M5 ;
        RECT  104.928 63.916 104.952 64 ;
    END
  END b_rsp_data[243]
  PIN b_rsp_data[244]
    DIRECTION OUTPUT ;
    USE SIGNAL ;
    PORT
      LAYER M5 ;
        RECT  105.024 63.916 105.048 64 ;
    END
  END b_rsp_data[244]
  PIN b_rsp_data[245]
    DIRECTION OUTPUT ;
    USE SIGNAL ;
    PORT
      LAYER M5 ;
        RECT  105.12 63.916 105.144 64 ;
    END
  END b_rsp_data[245]
  PIN b_rsp_data[246]
    DIRECTION OUTPUT ;
    USE SIGNAL ;
    PORT
      LAYER M5 ;
        RECT  105.216 63.916 105.24 64 ;
    END
  END b_rsp_data[246]
  PIN b_rsp_data[247]
    DIRECTION OUTPUT ;
    USE SIGNAL ;
    PORT
      LAYER M5 ;
        RECT  105.312 63.916 105.336 64 ;
    END
  END b_rsp_data[247]
  PIN b_rsp_data[248]
    DIRECTION OUTPUT ;
    USE SIGNAL ;
    PORT
      LAYER M5 ;
        RECT  105.408 63.916 105.432 64 ;
    END
  END b_rsp_data[248]
  PIN b_rsp_data[249]
    DIRECTION OUTPUT ;
    USE SIGNAL ;
    PORT
      LAYER M5 ;
        RECT  105.504 63.916 105.528 64 ;
    END
  END b_rsp_data[249]
  PIN b_rsp_data[24]
    DIRECTION OUTPUT ;
    USE SIGNAL ;
    PORT
      LAYER M5 ;
        RECT  83.904 63.916 83.928 64 ;
    END
  END b_rsp_data[24]
  PIN b_rsp_data[250]
    DIRECTION OUTPUT ;
    USE SIGNAL ;
    PORT
      LAYER M5 ;
        RECT  105.6 63.916 105.624 64 ;
    END
  END b_rsp_data[250]
  PIN b_rsp_data[251]
    DIRECTION OUTPUT ;
    USE SIGNAL ;
    PORT
      LAYER M5 ;
        RECT  105.696 63.916 105.72 64 ;
    END
  END b_rsp_data[251]
  PIN b_rsp_data[252]
    DIRECTION OUTPUT ;
    USE SIGNAL ;
    PORT
      LAYER M5 ;
        RECT  105.792 63.916 105.816 64 ;
    END
  END b_rsp_data[252]
  PIN b_rsp_data[253]
    DIRECTION OUTPUT ;
    USE SIGNAL ;
    PORT
      LAYER M5 ;
        RECT  105.888 63.916 105.912 64 ;
    END
  END b_rsp_data[253]
  PIN b_rsp_data[254]
    DIRECTION OUTPUT ;
    USE SIGNAL ;
    PORT
      LAYER M5 ;
        RECT  105.984 63.916 106.008 64 ;
    END
  END b_rsp_data[254]
  PIN b_rsp_data[255]
    DIRECTION OUTPUT ;
    USE SIGNAL ;
    PORT
      LAYER M5 ;
        RECT  106.08 63.916 106.104 64 ;
    END
  END b_rsp_data[255]
  PIN b_rsp_data[25]
    DIRECTION OUTPUT ;
    USE SIGNAL ;
    PORT
      LAYER M5 ;
        RECT  84 63.916 84.024 64 ;
    END
  END b_rsp_data[25]
  PIN b_rsp_data[26]
    DIRECTION OUTPUT ;
    USE SIGNAL ;
    PORT
      LAYER M5 ;
        RECT  84.096 63.916 84.12 64 ;
    END
  END b_rsp_data[26]
  PIN b_rsp_data[27]
    DIRECTION OUTPUT ;
    USE SIGNAL ;
    PORT
      LAYER M5 ;
        RECT  84.192 63.916 84.216 64 ;
    END
  END b_rsp_data[27]
  PIN b_rsp_data[28]
    DIRECTION OUTPUT ;
    USE SIGNAL ;
    PORT
      LAYER M5 ;
        RECT  84.288 63.916 84.312 64 ;
    END
  END b_rsp_data[28]
  PIN b_rsp_data[29]
    DIRECTION OUTPUT ;
    USE SIGNAL ;
    PORT
      LAYER M5 ;
        RECT  84.384 63.916 84.408 64 ;
    END
  END b_rsp_data[29]
  PIN b_rsp_data[2]
    DIRECTION OUTPUT ;
    USE SIGNAL ;
    PORT
      LAYER M5 ;
        RECT  81.792 63.916 81.816 64 ;
    END
  END b_rsp_data[2]
  PIN b_rsp_data[30]
    DIRECTION OUTPUT ;
    USE SIGNAL ;
    PORT
      LAYER M5 ;
        RECT  84.48 63.916 84.504 64 ;
    END
  END b_rsp_data[30]
  PIN b_rsp_data[31]
    DIRECTION OUTPUT ;
    USE SIGNAL ;
    PORT
      LAYER M5 ;
        RECT  84.576 63.916 84.6 64 ;
    END
  END b_rsp_data[31]
  PIN b_rsp_data[32]
    DIRECTION OUTPUT ;
    USE SIGNAL ;
    PORT
      LAYER M5 ;
        RECT  84.672 63.916 84.696 64 ;
    END
  END b_rsp_data[32]
  PIN b_rsp_data[33]
    DIRECTION OUTPUT ;
    USE SIGNAL ;
    PORT
      LAYER M5 ;
        RECT  84.768 63.916 84.792 64 ;
    END
  END b_rsp_data[33]
  PIN b_rsp_data[34]
    DIRECTION OUTPUT ;
    USE SIGNAL ;
    PORT
      LAYER M5 ;
        RECT  84.864 63.916 84.888 64 ;
    END
  END b_rsp_data[34]
  PIN b_rsp_data[35]
    DIRECTION OUTPUT ;
    USE SIGNAL ;
    PORT
      LAYER M5 ;
        RECT  84.96 63.916 84.984 64 ;
    END
  END b_rsp_data[35]
  PIN b_rsp_data[36]
    DIRECTION OUTPUT ;
    USE SIGNAL ;
    PORT
      LAYER M5 ;
        RECT  85.056 63.916 85.08 64 ;
    END
  END b_rsp_data[36]
  PIN b_rsp_data[37]
    DIRECTION OUTPUT ;
    USE SIGNAL ;
    PORT
      LAYER M5 ;
        RECT  85.152 63.916 85.176 64 ;
    END
  END b_rsp_data[37]
  PIN b_rsp_data[38]
    DIRECTION OUTPUT ;
    USE SIGNAL ;
    PORT
      LAYER M5 ;
        RECT  85.248 63.916 85.272 64 ;
    END
  END b_rsp_data[38]
  PIN b_rsp_data[39]
    DIRECTION OUTPUT ;
    USE SIGNAL ;
    PORT
      LAYER M5 ;
        RECT  85.344 63.916 85.368 64 ;
    END
  END b_rsp_data[39]
  PIN b_rsp_data[3]
    DIRECTION OUTPUT ;
    USE SIGNAL ;
    PORT
      LAYER M5 ;
        RECT  81.888 63.916 81.912 64 ;
    END
  END b_rsp_data[3]
  PIN b_rsp_data[40]
    DIRECTION OUTPUT ;
    USE SIGNAL ;
    PORT
      LAYER M5 ;
        RECT  85.44 63.916 85.464 64 ;
    END
  END b_rsp_data[40]
  PIN b_rsp_data[41]
    DIRECTION OUTPUT ;
    USE SIGNAL ;
    PORT
      LAYER M5 ;
        RECT  85.536 63.916 85.56 64 ;
    END
  END b_rsp_data[41]
  PIN b_rsp_data[42]
    DIRECTION OUTPUT ;
    USE SIGNAL ;
    PORT
      LAYER M5 ;
        RECT  85.632 63.916 85.656 64 ;
    END
  END b_rsp_data[42]
  PIN b_rsp_data[43]
    DIRECTION OUTPUT ;
    USE SIGNAL ;
    PORT
      LAYER M5 ;
        RECT  85.728 63.916 85.752 64 ;
    END
  END b_rsp_data[43]
  PIN b_rsp_data[44]
    DIRECTION OUTPUT ;
    USE SIGNAL ;
    PORT
      LAYER M5 ;
        RECT  85.824 63.916 85.848 64 ;
    END
  END b_rsp_data[44]
  PIN b_rsp_data[45]
    DIRECTION OUTPUT ;
    USE SIGNAL ;
    PORT
      LAYER M5 ;
        RECT  85.92 63.916 85.944 64 ;
    END
  END b_rsp_data[45]
  PIN b_rsp_data[46]
    DIRECTION OUTPUT ;
    USE SIGNAL ;
    PORT
      LAYER M5 ;
        RECT  86.016 63.916 86.04 64 ;
    END
  END b_rsp_data[46]
  PIN b_rsp_data[47]
    DIRECTION OUTPUT ;
    USE SIGNAL ;
    PORT
      LAYER M5 ;
        RECT  86.112 63.916 86.136 64 ;
    END
  END b_rsp_data[47]
  PIN b_rsp_data[48]
    DIRECTION OUTPUT ;
    USE SIGNAL ;
    PORT
      LAYER M5 ;
        RECT  86.208 63.916 86.232 64 ;
    END
  END b_rsp_data[48]
  PIN b_rsp_data[49]
    DIRECTION OUTPUT ;
    USE SIGNAL ;
    PORT
      LAYER M5 ;
        RECT  86.304 63.916 86.328 64 ;
    END
  END b_rsp_data[49]
  PIN b_rsp_data[4]
    DIRECTION OUTPUT ;
    USE SIGNAL ;
    PORT
      LAYER M5 ;
        RECT  81.984 63.916 82.008 64 ;
    END
  END b_rsp_data[4]
  PIN b_rsp_data[50]
    DIRECTION OUTPUT ;
    USE SIGNAL ;
    PORT
      LAYER M5 ;
        RECT  86.4 63.916 86.424 64 ;
    END
  END b_rsp_data[50]
  PIN b_rsp_data[51]
    DIRECTION OUTPUT ;
    USE SIGNAL ;
    PORT
      LAYER M5 ;
        RECT  86.496 63.916 86.52 64 ;
    END
  END b_rsp_data[51]
  PIN b_rsp_data[52]
    DIRECTION OUTPUT ;
    USE SIGNAL ;
    PORT
      LAYER M5 ;
        RECT  86.592 63.916 86.616 64 ;
    END
  END b_rsp_data[52]
  PIN b_rsp_data[53]
    DIRECTION OUTPUT ;
    USE SIGNAL ;
    PORT
      LAYER M5 ;
        RECT  86.688 63.916 86.712 64 ;
    END
  END b_rsp_data[53]
  PIN b_rsp_data[54]
    DIRECTION OUTPUT ;
    USE SIGNAL ;
    PORT
      LAYER M5 ;
        RECT  86.784 63.916 86.808 64 ;
    END
  END b_rsp_data[54]
  PIN b_rsp_data[55]
    DIRECTION OUTPUT ;
    USE SIGNAL ;
    PORT
      LAYER M5 ;
        RECT  86.88 63.916 86.904 64 ;
    END
  END b_rsp_data[55]
  PIN b_rsp_data[56]
    DIRECTION OUTPUT ;
    USE SIGNAL ;
    PORT
      LAYER M5 ;
        RECT  86.976 63.916 87 64 ;
    END
  END b_rsp_data[56]
  PIN b_rsp_data[57]
    DIRECTION OUTPUT ;
    USE SIGNAL ;
    PORT
      LAYER M5 ;
        RECT  87.072 63.916 87.096 64 ;
    END
  END b_rsp_data[57]
  PIN b_rsp_data[58]
    DIRECTION OUTPUT ;
    USE SIGNAL ;
    PORT
      LAYER M5 ;
        RECT  87.168 63.916 87.192 64 ;
    END
  END b_rsp_data[58]
  PIN b_rsp_data[59]
    DIRECTION OUTPUT ;
    USE SIGNAL ;
    PORT
      LAYER M5 ;
        RECT  87.264 63.916 87.288 64 ;
    END
  END b_rsp_data[59]
  PIN b_rsp_data[5]
    DIRECTION OUTPUT ;
    USE SIGNAL ;
    PORT
      LAYER M5 ;
        RECT  82.08 63.916 82.104 64 ;
    END
  END b_rsp_data[5]
  PIN b_rsp_data[60]
    DIRECTION OUTPUT ;
    USE SIGNAL ;
    PORT
      LAYER M5 ;
        RECT  87.36 63.916 87.384 64 ;
    END
  END b_rsp_data[60]
  PIN b_rsp_data[61]
    DIRECTION OUTPUT ;
    USE SIGNAL ;
    PORT
      LAYER M5 ;
        RECT  87.456 63.916 87.48 64 ;
    END
  END b_rsp_data[61]
  PIN b_rsp_data[62]
    DIRECTION OUTPUT ;
    USE SIGNAL ;
    PORT
      LAYER M5 ;
        RECT  87.552 63.916 87.576 64 ;
    END
  END b_rsp_data[62]
  PIN b_rsp_data[63]
    DIRECTION OUTPUT ;
    USE SIGNAL ;
    PORT
      LAYER M5 ;
        RECT  87.648 63.916 87.672 64 ;
    END
  END b_rsp_data[63]
  PIN b_rsp_data[64]
    DIRECTION OUTPUT ;
    USE SIGNAL ;
    PORT
      LAYER M5 ;
        RECT  87.744 63.916 87.768 64 ;
    END
  END b_rsp_data[64]
  PIN b_rsp_data[65]
    DIRECTION OUTPUT ;
    USE SIGNAL ;
    PORT
      LAYER M5 ;
        RECT  87.84 63.916 87.864 64 ;
    END
  END b_rsp_data[65]
  PIN b_rsp_data[66]
    DIRECTION OUTPUT ;
    USE SIGNAL ;
    PORT
      LAYER M5 ;
        RECT  87.936 63.916 87.96 64 ;
    END
  END b_rsp_data[66]
  PIN b_rsp_data[67]
    DIRECTION OUTPUT ;
    USE SIGNAL ;
    PORT
      LAYER M5 ;
        RECT  88.032 63.916 88.056 64 ;
    END
  END b_rsp_data[67]
  PIN b_rsp_data[68]
    DIRECTION OUTPUT ;
    USE SIGNAL ;
    PORT
      LAYER M5 ;
        RECT  88.128 63.916 88.152 64 ;
    END
  END b_rsp_data[68]
  PIN b_rsp_data[69]
    DIRECTION OUTPUT ;
    USE SIGNAL ;
    PORT
      LAYER M5 ;
        RECT  88.224 63.916 88.248 64 ;
    END
  END b_rsp_data[69]
  PIN b_rsp_data[6]
    DIRECTION OUTPUT ;
    USE SIGNAL ;
    PORT
      LAYER M5 ;
        RECT  82.176 63.916 82.2 64 ;
    END
  END b_rsp_data[6]
  PIN b_rsp_data[70]
    DIRECTION OUTPUT ;
    USE SIGNAL ;
    PORT
      LAYER M5 ;
        RECT  88.32 63.916 88.344 64 ;
    END
  END b_rsp_data[70]
  PIN b_rsp_data[71]
    DIRECTION OUTPUT ;
    USE SIGNAL ;
    PORT
      LAYER M5 ;
        RECT  88.416 63.916 88.44 64 ;
    END
  END b_rsp_data[71]
  PIN b_rsp_data[72]
    DIRECTION OUTPUT ;
    USE SIGNAL ;
    PORT
      LAYER M5 ;
        RECT  88.512 63.916 88.536 64 ;
    END
  END b_rsp_data[72]
  PIN b_rsp_data[73]
    DIRECTION OUTPUT ;
    USE SIGNAL ;
    PORT
      LAYER M5 ;
        RECT  88.608 63.916 88.632 64 ;
    END
  END b_rsp_data[73]
  PIN b_rsp_data[74]
    DIRECTION OUTPUT ;
    USE SIGNAL ;
    PORT
      LAYER M5 ;
        RECT  88.704 63.916 88.728 64 ;
    END
  END b_rsp_data[74]
  PIN b_rsp_data[75]
    DIRECTION OUTPUT ;
    USE SIGNAL ;
    PORT
      LAYER M5 ;
        RECT  88.8 63.916 88.824 64 ;
    END
  END b_rsp_data[75]
  PIN b_rsp_data[76]
    DIRECTION OUTPUT ;
    USE SIGNAL ;
    PORT
      LAYER M5 ;
        RECT  88.896 63.916 88.92 64 ;
    END
  END b_rsp_data[76]
  PIN b_rsp_data[77]
    DIRECTION OUTPUT ;
    USE SIGNAL ;
    PORT
      LAYER M5 ;
        RECT  88.992 63.916 89.016 64 ;
    END
  END b_rsp_data[77]
  PIN b_rsp_data[78]
    DIRECTION OUTPUT ;
    USE SIGNAL ;
    PORT
      LAYER M5 ;
        RECT  89.088 63.916 89.112 64 ;
    END
  END b_rsp_data[78]
  PIN b_rsp_data[79]
    DIRECTION OUTPUT ;
    USE SIGNAL ;
    PORT
      LAYER M5 ;
        RECT  89.184 63.916 89.208 64 ;
    END
  END b_rsp_data[79]
  PIN b_rsp_data[7]
    DIRECTION OUTPUT ;
    USE SIGNAL ;
    PORT
      LAYER M5 ;
        RECT  82.272 63.916 82.296 64 ;
    END
  END b_rsp_data[7]
  PIN b_rsp_data[80]
    DIRECTION OUTPUT ;
    USE SIGNAL ;
    PORT
      LAYER M5 ;
        RECT  89.28 63.916 89.304 64 ;
    END
  END b_rsp_data[80]
  PIN b_rsp_data[81]
    DIRECTION OUTPUT ;
    USE SIGNAL ;
    PORT
      LAYER M5 ;
        RECT  89.376 63.916 89.4 64 ;
    END
  END b_rsp_data[81]
  PIN b_rsp_data[82]
    DIRECTION OUTPUT ;
    USE SIGNAL ;
    PORT
      LAYER M5 ;
        RECT  89.472 63.916 89.496 64 ;
    END
  END b_rsp_data[82]
  PIN b_rsp_data[83]
    DIRECTION OUTPUT ;
    USE SIGNAL ;
    PORT
      LAYER M5 ;
        RECT  89.568 63.916 89.592 64 ;
    END
  END b_rsp_data[83]
  PIN b_rsp_data[84]
    DIRECTION OUTPUT ;
    USE SIGNAL ;
    PORT
      LAYER M5 ;
        RECT  89.664 63.916 89.688 64 ;
    END
  END b_rsp_data[84]
  PIN b_rsp_data[85]
    DIRECTION OUTPUT ;
    USE SIGNAL ;
    PORT
      LAYER M5 ;
        RECT  89.76 63.916 89.784 64 ;
    END
  END b_rsp_data[85]
  PIN b_rsp_data[86]
    DIRECTION OUTPUT ;
    USE SIGNAL ;
    PORT
      LAYER M5 ;
        RECT  89.856 63.916 89.88 64 ;
    END
  END b_rsp_data[86]
  PIN b_rsp_data[87]
    DIRECTION OUTPUT ;
    USE SIGNAL ;
    PORT
      LAYER M5 ;
        RECT  89.952 63.916 89.976 64 ;
    END
  END b_rsp_data[87]
  PIN b_rsp_data[88]
    DIRECTION OUTPUT ;
    USE SIGNAL ;
    PORT
      LAYER M5 ;
        RECT  90.048 63.916 90.072 64 ;
    END
  END b_rsp_data[88]
  PIN b_rsp_data[89]
    DIRECTION OUTPUT ;
    USE SIGNAL ;
    PORT
      LAYER M5 ;
        RECT  90.144 63.916 90.168 64 ;
    END
  END b_rsp_data[89]
  PIN b_rsp_data[8]
    DIRECTION OUTPUT ;
    USE SIGNAL ;
    PORT
      LAYER M5 ;
        RECT  82.368 63.916 82.392 64 ;
    END
  END b_rsp_data[8]
  PIN b_rsp_data[90]
    DIRECTION OUTPUT ;
    USE SIGNAL ;
    PORT
      LAYER M5 ;
        RECT  90.24 63.916 90.264 64 ;
    END
  END b_rsp_data[90]
  PIN b_rsp_data[91]
    DIRECTION OUTPUT ;
    USE SIGNAL ;
    PORT
      LAYER M5 ;
        RECT  90.336 63.916 90.36 64 ;
    END
  END b_rsp_data[91]
  PIN b_rsp_data[92]
    DIRECTION OUTPUT ;
    USE SIGNAL ;
    PORT
      LAYER M5 ;
        RECT  90.432 63.916 90.456 64 ;
    END
  END b_rsp_data[92]
  PIN b_rsp_data[93]
    DIRECTION OUTPUT ;
    USE SIGNAL ;
    PORT
      LAYER M5 ;
        RECT  90.528 63.916 90.552 64 ;
    END
  END b_rsp_data[93]
  PIN b_rsp_data[94]
    DIRECTION OUTPUT ;
    USE SIGNAL ;
    PORT
      LAYER M5 ;
        RECT  90.624 63.916 90.648 64 ;
    END
  END b_rsp_data[94]
  PIN b_rsp_data[95]
    DIRECTION OUTPUT ;
    USE SIGNAL ;
    PORT
      LAYER M5 ;
        RECT  90.72 63.916 90.744 64 ;
    END
  END b_rsp_data[95]
  PIN b_rsp_data[96]
    DIRECTION OUTPUT ;
    USE SIGNAL ;
    PORT
      LAYER M5 ;
        RECT  90.816 63.916 90.84 64 ;
    END
  END b_rsp_data[96]
  PIN b_rsp_data[97]
    DIRECTION OUTPUT ;
    USE SIGNAL ;
    PORT
      LAYER M5 ;
        RECT  90.912 63.916 90.936 64 ;
    END
  END b_rsp_data[97]
  PIN b_rsp_data[98]
    DIRECTION OUTPUT ;
    USE SIGNAL ;
    PORT
      LAYER M5 ;
        RECT  91.008 63.916 91.032 64 ;
    END
  END b_rsp_data[98]
  PIN b_rsp_data[99]
    DIRECTION OUTPUT ;
    USE SIGNAL ;
    PORT
      LAYER M5 ;
        RECT  91.104 63.916 91.128 64 ;
    END
  END b_rsp_data[99]
  PIN b_rsp_data[9]
    DIRECTION OUTPUT ;
    USE SIGNAL ;
    PORT
      LAYER M5 ;
        RECT  82.464 63.916 82.488 64 ;
    END
  END b_rsp_data[9]
  PIN b_rsp_rdy
    DIRECTION INPUT ;
    USE SIGNAL ;
    PORT
      LAYER M5 ;
        RECT  106.176 63.916 106.2 64 ;
    END
  END b_rsp_rdy
  PIN b_rsp_tag[0]
    DIRECTION OUTPUT ;
    USE SIGNAL ;
    PORT
      LAYER M5 ;
        RECT  106.272 63.916 106.296 64 ;
    END
  END b_rsp_tag[0]
  PIN b_rsp_tag[10]
    DIRECTION OUTPUT ;
    USE SIGNAL ;
    PORT
      LAYER M5 ;
        RECT  107.232 63.916 107.256 64 ;
    END
  END b_rsp_tag[10]
  PIN b_rsp_tag[11]
    DIRECTION OUTPUT ;
    USE SIGNAL ;
    PORT
      LAYER M5 ;
        RECT  107.328 63.916 107.352 64 ;
    END
  END b_rsp_tag[11]
  PIN b_rsp_tag[12]
    DIRECTION OUTPUT ;
    USE SIGNAL ;
    PORT
      LAYER M5 ;
        RECT  107.424 63.916 107.448 64 ;
    END
  END b_rsp_tag[12]
  PIN b_rsp_tag[13]
    DIRECTION OUTPUT ;
    USE SIGNAL ;
    PORT
      LAYER M5 ;
        RECT  107.52 63.916 107.544 64 ;
    END
  END b_rsp_tag[13]
  PIN b_rsp_tag[14]
    DIRECTION OUTPUT ;
    USE SIGNAL ;
    PORT
      LAYER M5 ;
        RECT  107.616 63.916 107.64 64 ;
    END
  END b_rsp_tag[14]
  PIN b_rsp_tag[15]
    DIRECTION OUTPUT ;
    USE SIGNAL ;
    PORT
      LAYER M5 ;
        RECT  107.712 63.916 107.736 64 ;
    END
  END b_rsp_tag[15]
  PIN b_rsp_tag[1]
    DIRECTION OUTPUT ;
    USE SIGNAL ;
    PORT
      LAYER M5 ;
        RECT  106.368 63.916 106.392 64 ;
    END
  END b_rsp_tag[1]
  PIN b_rsp_tag[2]
    DIRECTION OUTPUT ;
    USE SIGNAL ;
    PORT
      LAYER M5 ;
        RECT  106.464 63.916 106.488 64 ;
    END
  END b_rsp_tag[2]
  PIN b_rsp_tag[3]
    DIRECTION OUTPUT ;
    USE SIGNAL ;
    PORT
      LAYER M5 ;
        RECT  106.56 63.916 106.584 64 ;
    END
  END b_rsp_tag[3]
  PIN b_rsp_tag[4]
    DIRECTION OUTPUT ;
    USE SIGNAL ;
    PORT
      LAYER M5 ;
        RECT  106.656 63.916 106.68 64 ;
    END
  END b_rsp_tag[4]
  PIN b_rsp_tag[5]
    DIRECTION OUTPUT ;
    USE SIGNAL ;
    PORT
      LAYER M5 ;
        RECT  106.752 63.916 106.776 64 ;
    END
  END b_rsp_tag[5]
  PIN b_rsp_tag[6]
    DIRECTION OUTPUT ;
    USE SIGNAL ;
    PORT
      LAYER M5 ;
        RECT  106.848 63.916 106.872 64 ;
    END
  END b_rsp_tag[6]
  PIN b_rsp_tag[7]
    DIRECTION OUTPUT ;
    USE SIGNAL ;
    PORT
      LAYER M5 ;
        RECT  106.944 63.916 106.968 64 ;
    END
  END b_rsp_tag[7]
  PIN b_rsp_tag[8]
    DIRECTION OUTPUT ;
    USE SIGNAL ;
    PORT
      LAYER M5 ;
        RECT  107.04 63.916 107.064 64 ;
    END
  END b_rsp_tag[8]
  PIN b_rsp_tag[9]
    DIRECTION OUTPUT ;
    USE SIGNAL ;
    PORT
      LAYER M5 ;
        RECT  107.136 63.916 107.16 64 ;
    END
  END b_rsp_tag[9]
  PIN b_rsp_v
    DIRECTION OUTPUT ;
    USE SIGNAL ;
    PORT
      LAYER M5 ;
        RECT  107.808 63.916 107.832 64 ;
    END
  END b_rsp_v
  PIN b_tag[0]
    DIRECTION INPUT ;
    USE SIGNAL ;
    PORT
      LAYER M5 ;
        RECT  107.904 63.916 107.928 64 ;
    END
  END b_tag[0]
  PIN b_tag[10]
    DIRECTION INPUT ;
    USE SIGNAL ;
    PORT
      LAYER M5 ;
        RECT  108.864 63.916 108.888 64 ;
    END
  END b_tag[10]
  PIN b_tag[11]
    DIRECTION INPUT ;
    USE SIGNAL ;
    PORT
      LAYER M5 ;
        RECT  108.96 63.916 108.984 64 ;
    END
  END b_tag[11]
  PIN b_tag[12]
    DIRECTION INPUT ;
    USE SIGNAL ;
    PORT
      LAYER M5 ;
        RECT  109.056 63.916 109.08 64 ;
    END
  END b_tag[12]
  PIN b_tag[13]
    DIRECTION INPUT ;
    USE SIGNAL ;
    PORT
      LAYER M5 ;
        RECT  109.152 63.916 109.176 64 ;
    END
  END b_tag[13]
  PIN b_tag[14]
    DIRECTION INPUT ;
    USE SIGNAL ;
    PORT
      LAYER M5 ;
        RECT  109.248 63.916 109.272 64 ;
    END
  END b_tag[14]
  PIN b_tag[15]
    DIRECTION INPUT ;
    USE SIGNAL ;
    PORT
      LAYER M5 ;
        RECT  109.344 63.916 109.368 64 ;
    END
  END b_tag[15]
  PIN b_tag[1]
    DIRECTION INPUT ;
    USE SIGNAL ;
    PORT
      LAYER M5 ;
        RECT  108 63.916 108.024 64 ;
    END
  END b_tag[1]
  PIN b_tag[2]
    DIRECTION INPUT ;
    USE SIGNAL ;
    PORT
      LAYER M5 ;
        RECT  108.096 63.916 108.12 64 ;
    END
  END b_tag[2]
  PIN b_tag[3]
    DIRECTION INPUT ;
    USE SIGNAL ;
    PORT
      LAYER M5 ;
        RECT  108.192 63.916 108.216 64 ;
    END
  END b_tag[3]
  PIN b_tag[4]
    DIRECTION INPUT ;
    USE SIGNAL ;
    PORT
      LAYER M5 ;
        RECT  108.288 63.916 108.312 64 ;
    END
  END b_tag[4]
  PIN b_tag[5]
    DIRECTION INPUT ;
    USE SIGNAL ;
    PORT
      LAYER M5 ;
        RECT  108.384 63.916 108.408 64 ;
    END
  END b_tag[5]
  PIN b_tag[6]
    DIRECTION INPUT ;
    USE SIGNAL ;
    PORT
      LAYER M5 ;
        RECT  108.48 63.916 108.504 64 ;
    END
  END b_tag[6]
  PIN b_tag[7]
    DIRECTION INPUT ;
    USE SIGNAL ;
    PORT
      LAYER M5 ;
        RECT  108.576 63.916 108.6 64 ;
    END
  END b_tag[7]
  PIN b_tag[8]
    DIRECTION INPUT ;
    USE SIGNAL ;
    PORT
      LAYER M5 ;
        RECT  108.672 63.916 108.696 64 ;
    END
  END b_tag[8]
  PIN b_tag[9]
    DIRECTION INPUT ;
    USE SIGNAL ;
    PORT
      LAYER M5 ;
        RECT  108.768 63.916 108.792 64 ;
    END
  END b_tag[9]
  PIN b_v
    DIRECTION INPUT ;
    USE SIGNAL ;
    PORT
      LAYER M5 ;
        RECT  109.44 63.916 109.464 64 ;
    END
  END b_v
  PIN b_wdata[0]
    DIRECTION INPUT ;
    USE SIGNAL ;
    PORT
      LAYER M5 ;
        RECT  109.536 63.916 109.56 64 ;
    END
  END b_wdata[0]
  PIN b_wdata[100]
    DIRECTION INPUT ;
    USE SIGNAL ;
    PORT
      LAYER M5 ;
        RECT  119.136 63.916 119.16 64 ;
    END
  END b_wdata[100]
  PIN b_wdata[101]
    DIRECTION INPUT ;
    USE SIGNAL ;
    PORT
      LAYER M5 ;
        RECT  119.232 63.916 119.256 64 ;
    END
  END b_wdata[101]
  PIN b_wdata[102]
    DIRECTION INPUT ;
    USE SIGNAL ;
    PORT
      LAYER M5 ;
        RECT  119.328 63.916 119.352 64 ;
    END
  END b_wdata[102]
  PIN b_wdata[103]
    DIRECTION INPUT ;
    USE SIGNAL ;
    PORT
      LAYER M5 ;
        RECT  119.424 63.916 119.448 64 ;
    END
  END b_wdata[103]
  PIN b_wdata[104]
    DIRECTION INPUT ;
    USE SIGNAL ;
    PORT
      LAYER M5 ;
        RECT  119.52 63.916 119.544 64 ;
    END
  END b_wdata[104]
  PIN b_wdata[105]
    DIRECTION INPUT ;
    USE SIGNAL ;
    PORT
      LAYER M5 ;
        RECT  119.616 63.916 119.64 64 ;
    END
  END b_wdata[105]
  PIN b_wdata[106]
    DIRECTION INPUT ;
    USE SIGNAL ;
    PORT
      LAYER M5 ;
        RECT  119.712 63.916 119.736 64 ;
    END
  END b_wdata[106]
  PIN b_wdata[107]
    DIRECTION INPUT ;
    USE SIGNAL ;
    PORT
      LAYER M5 ;
        RECT  119.808 63.916 119.832 64 ;
    END
  END b_wdata[107]
  PIN b_wdata[108]
    DIRECTION INPUT ;
    USE SIGNAL ;
    PORT
      LAYER M5 ;
        RECT  119.904 63.916 119.928 64 ;
    END
  END b_wdata[108]
  PIN b_wdata[109]
    DIRECTION INPUT ;
    USE SIGNAL ;
    PORT
      LAYER M5 ;
        RECT  120 63.916 120.024 64 ;
    END
  END b_wdata[109]
  PIN b_wdata[10]
    DIRECTION INPUT ;
    USE SIGNAL ;
    PORT
      LAYER M5 ;
        RECT  110.496 63.916 110.52 64 ;
    END
  END b_wdata[10]
  PIN b_wdata[110]
    DIRECTION INPUT ;
    USE SIGNAL ;
    PORT
      LAYER M5 ;
        RECT  120.096 63.916 120.12 64 ;
    END
  END b_wdata[110]
  PIN b_wdata[111]
    DIRECTION INPUT ;
    USE SIGNAL ;
    PORT
      LAYER M5 ;
        RECT  120.192 63.916 120.216 64 ;
    END
  END b_wdata[111]
  PIN b_wdata[112]
    DIRECTION INPUT ;
    USE SIGNAL ;
    PORT
      LAYER M5 ;
        RECT  120.288 63.916 120.312 64 ;
    END
  END b_wdata[112]
  PIN b_wdata[113]
    DIRECTION INPUT ;
    USE SIGNAL ;
    PORT
      LAYER M5 ;
        RECT  120.384 63.916 120.408 64 ;
    END
  END b_wdata[113]
  PIN b_wdata[114]
    DIRECTION INPUT ;
    USE SIGNAL ;
    PORT
      LAYER M5 ;
        RECT  120.48 63.916 120.504 64 ;
    END
  END b_wdata[114]
  PIN b_wdata[115]
    DIRECTION INPUT ;
    USE SIGNAL ;
    PORT
      LAYER M5 ;
        RECT  120.576 63.916 120.6 64 ;
    END
  END b_wdata[115]
  PIN b_wdata[116]
    DIRECTION INPUT ;
    USE SIGNAL ;
    PORT
      LAYER M5 ;
        RECT  120.672 63.916 120.696 64 ;
    END
  END b_wdata[116]
  PIN b_wdata[117]
    DIRECTION INPUT ;
    USE SIGNAL ;
    PORT
      LAYER M5 ;
        RECT  120.768 63.916 120.792 64 ;
    END
  END b_wdata[117]
  PIN b_wdata[118]
    DIRECTION INPUT ;
    USE SIGNAL ;
    PORT
      LAYER M5 ;
        RECT  120.864 63.916 120.888 64 ;
    END
  END b_wdata[118]
  PIN b_wdata[119]
    DIRECTION INPUT ;
    USE SIGNAL ;
    PORT
      LAYER M5 ;
        RECT  120.96 63.916 120.984 64 ;
    END
  END b_wdata[119]
  PIN b_wdata[11]
    DIRECTION INPUT ;
    USE SIGNAL ;
    PORT
      LAYER M5 ;
        RECT  110.592 63.916 110.616 64 ;
    END
  END b_wdata[11]
  PIN b_wdata[120]
    DIRECTION INPUT ;
    USE SIGNAL ;
    PORT
      LAYER M5 ;
        RECT  121.056 63.916 121.08 64 ;
    END
  END b_wdata[120]
  PIN b_wdata[121]
    DIRECTION INPUT ;
    USE SIGNAL ;
    PORT
      LAYER M5 ;
        RECT  121.152 63.916 121.176 64 ;
    END
  END b_wdata[121]
  PIN b_wdata[122]
    DIRECTION INPUT ;
    USE SIGNAL ;
    PORT
      LAYER M5 ;
        RECT  121.248 63.916 121.272 64 ;
    END
  END b_wdata[122]
  PIN b_wdata[123]
    DIRECTION INPUT ;
    USE SIGNAL ;
    PORT
      LAYER M5 ;
        RECT  121.344 63.916 121.368 64 ;
    END
  END b_wdata[123]
  PIN b_wdata[124]
    DIRECTION INPUT ;
    USE SIGNAL ;
    PORT
      LAYER M5 ;
        RECT  121.44 63.916 121.464 64 ;
    END
  END b_wdata[124]
  PIN b_wdata[125]
    DIRECTION INPUT ;
    USE SIGNAL ;
    PORT
      LAYER M5 ;
        RECT  121.536 63.916 121.56 64 ;
    END
  END b_wdata[125]
  PIN b_wdata[126]
    DIRECTION INPUT ;
    USE SIGNAL ;
    PORT
      LAYER M5 ;
        RECT  121.632 63.916 121.656 64 ;
    END
  END b_wdata[126]
  PIN b_wdata[127]
    DIRECTION INPUT ;
    USE SIGNAL ;
    PORT
      LAYER M5 ;
        RECT  121.728 63.916 121.752 64 ;
    END
  END b_wdata[127]
  PIN b_wdata[128]
    DIRECTION INPUT ;
    USE SIGNAL ;
    PORT
      LAYER M5 ;
        RECT  121.824 63.916 121.848 64 ;
    END
  END b_wdata[128]
  PIN b_wdata[129]
    DIRECTION INPUT ;
    USE SIGNAL ;
    PORT
      LAYER M5 ;
        RECT  121.92 63.916 121.944 64 ;
    END
  END b_wdata[129]
  PIN b_wdata[12]
    DIRECTION INPUT ;
    USE SIGNAL ;
    PORT
      LAYER M5 ;
        RECT  110.688 63.916 110.712 64 ;
    END
  END b_wdata[12]
  PIN b_wdata[130]
    DIRECTION INPUT ;
    USE SIGNAL ;
    PORT
      LAYER M5 ;
        RECT  122.016 63.916 122.04 64 ;
    END
  END b_wdata[130]
  PIN b_wdata[131]
    DIRECTION INPUT ;
    USE SIGNAL ;
    PORT
      LAYER M5 ;
        RECT  122.112 63.916 122.136 64 ;
    END
  END b_wdata[131]
  PIN b_wdata[132]
    DIRECTION INPUT ;
    USE SIGNAL ;
    PORT
      LAYER M5 ;
        RECT  122.208 63.916 122.232 64 ;
    END
  END b_wdata[132]
  PIN b_wdata[133]
    DIRECTION INPUT ;
    USE SIGNAL ;
    PORT
      LAYER M5 ;
        RECT  122.304 63.916 122.328 64 ;
    END
  END b_wdata[133]
  PIN b_wdata[134]
    DIRECTION INPUT ;
    USE SIGNAL ;
    PORT
      LAYER M5 ;
        RECT  122.4 63.916 122.424 64 ;
    END
  END b_wdata[134]
  PIN b_wdata[135]
    DIRECTION INPUT ;
    USE SIGNAL ;
    PORT
      LAYER M5 ;
        RECT  122.496 63.916 122.52 64 ;
    END
  END b_wdata[135]
  PIN b_wdata[136]
    DIRECTION INPUT ;
    USE SIGNAL ;
    PORT
      LAYER M5 ;
        RECT  122.592 63.916 122.616 64 ;
    END
  END b_wdata[136]
  PIN b_wdata[137]
    DIRECTION INPUT ;
    USE SIGNAL ;
    PORT
      LAYER M5 ;
        RECT  122.688 63.916 122.712 64 ;
    END
  END b_wdata[137]
  PIN b_wdata[138]
    DIRECTION INPUT ;
    USE SIGNAL ;
    PORT
      LAYER M5 ;
        RECT  122.784 63.916 122.808 64 ;
    END
  END b_wdata[138]
  PIN b_wdata[139]
    DIRECTION INPUT ;
    USE SIGNAL ;
    PORT
      LAYER M5 ;
        RECT  122.88 63.916 122.904 64 ;
    END
  END b_wdata[139]
  PIN b_wdata[13]
    DIRECTION INPUT ;
    USE SIGNAL ;
    PORT
      LAYER M5 ;
        RECT  110.784 63.916 110.808 64 ;
    END
  END b_wdata[13]
  PIN b_wdata[140]
    DIRECTION INPUT ;
    USE SIGNAL ;
    PORT
      LAYER M5 ;
        RECT  122.976 63.916 123 64 ;
    END
  END b_wdata[140]
  PIN b_wdata[141]
    DIRECTION INPUT ;
    USE SIGNAL ;
    PORT
      LAYER M5 ;
        RECT  123.072 63.916 123.096 64 ;
    END
  END b_wdata[141]
  PIN b_wdata[142]
    DIRECTION INPUT ;
    USE SIGNAL ;
    PORT
      LAYER M5 ;
        RECT  123.168 63.916 123.192 64 ;
    END
  END b_wdata[142]
  PIN b_wdata[143]
    DIRECTION INPUT ;
    USE SIGNAL ;
    PORT
      LAYER M5 ;
        RECT  123.264 63.916 123.288 64 ;
    END
  END b_wdata[143]
  PIN b_wdata[144]
    DIRECTION INPUT ;
    USE SIGNAL ;
    PORT
      LAYER M5 ;
        RECT  123.36 63.916 123.384 64 ;
    END
  END b_wdata[144]
  PIN b_wdata[145]
    DIRECTION INPUT ;
    USE SIGNAL ;
    PORT
      LAYER M5 ;
        RECT  123.456 63.916 123.48 64 ;
    END
  END b_wdata[145]
  PIN b_wdata[146]
    DIRECTION INPUT ;
    USE SIGNAL ;
    PORT
      LAYER M5 ;
        RECT  123.552 63.916 123.576 64 ;
    END
  END b_wdata[146]
  PIN b_wdata[147]
    DIRECTION INPUT ;
    USE SIGNAL ;
    PORT
      LAYER M5 ;
        RECT  123.648 63.916 123.672 64 ;
    END
  END b_wdata[147]
  PIN b_wdata[148]
    DIRECTION INPUT ;
    USE SIGNAL ;
    PORT
      LAYER M5 ;
        RECT  123.744 63.916 123.768 64 ;
    END
  END b_wdata[148]
  PIN b_wdata[149]
    DIRECTION INPUT ;
    USE SIGNAL ;
    PORT
      LAYER M5 ;
        RECT  123.84 63.916 123.864 64 ;
    END
  END b_wdata[149]
  PIN b_wdata[14]
    DIRECTION INPUT ;
    USE SIGNAL ;
    PORT
      LAYER M5 ;
        RECT  110.88 63.916 110.904 64 ;
    END
  END b_wdata[14]
  PIN b_wdata[150]
    DIRECTION INPUT ;
    USE SIGNAL ;
    PORT
      LAYER M5 ;
        RECT  123.936 63.916 123.96 64 ;
    END
  END b_wdata[150]
  PIN b_wdata[151]
    DIRECTION INPUT ;
    USE SIGNAL ;
    PORT
      LAYER M5 ;
        RECT  124.032 63.916 124.056 64 ;
    END
  END b_wdata[151]
  PIN b_wdata[152]
    DIRECTION INPUT ;
    USE SIGNAL ;
    PORT
      LAYER M5 ;
        RECT  124.128 63.916 124.152 64 ;
    END
  END b_wdata[152]
  PIN b_wdata[153]
    DIRECTION INPUT ;
    USE SIGNAL ;
    PORT
      LAYER M5 ;
        RECT  124.224 63.916 124.248 64 ;
    END
  END b_wdata[153]
  PIN b_wdata[154]
    DIRECTION INPUT ;
    USE SIGNAL ;
    PORT
      LAYER M5 ;
        RECT  124.32 63.916 124.344 64 ;
    END
  END b_wdata[154]
  PIN b_wdata[155]
    DIRECTION INPUT ;
    USE SIGNAL ;
    PORT
      LAYER M5 ;
        RECT  124.416 63.916 124.44 64 ;
    END
  END b_wdata[155]
  PIN b_wdata[156]
    DIRECTION INPUT ;
    USE SIGNAL ;
    PORT
      LAYER M5 ;
        RECT  124.512 63.916 124.536 64 ;
    END
  END b_wdata[156]
  PIN b_wdata[157]
    DIRECTION INPUT ;
    USE SIGNAL ;
    PORT
      LAYER M5 ;
        RECT  124.608 63.916 124.632 64 ;
    END
  END b_wdata[157]
  PIN b_wdata[158]
    DIRECTION INPUT ;
    USE SIGNAL ;
    PORT
      LAYER M5 ;
        RECT  124.704 63.916 124.728 64 ;
    END
  END b_wdata[158]
  PIN b_wdata[159]
    DIRECTION INPUT ;
    USE SIGNAL ;
    PORT
      LAYER M5 ;
        RECT  124.8 63.916 124.824 64 ;
    END
  END b_wdata[159]
  PIN b_wdata[15]
    DIRECTION INPUT ;
    USE SIGNAL ;
    PORT
      LAYER M5 ;
        RECT  110.976 63.916 111 64 ;
    END
  END b_wdata[15]
  PIN b_wdata[160]
    DIRECTION INPUT ;
    USE SIGNAL ;
    PORT
      LAYER M5 ;
        RECT  124.896 63.916 124.92 64 ;
    END
  END b_wdata[160]
  PIN b_wdata[161]
    DIRECTION INPUT ;
    USE SIGNAL ;
    PORT
      LAYER M5 ;
        RECT  124.992 63.916 125.016 64 ;
    END
  END b_wdata[161]
  PIN b_wdata[162]
    DIRECTION INPUT ;
    USE SIGNAL ;
    PORT
      LAYER M5 ;
        RECT  125.088 63.916 125.112 64 ;
    END
  END b_wdata[162]
  PIN b_wdata[163]
    DIRECTION INPUT ;
    USE SIGNAL ;
    PORT
      LAYER M5 ;
        RECT  125.184 63.916 125.208 64 ;
    END
  END b_wdata[163]
  PIN b_wdata[164]
    DIRECTION INPUT ;
    USE SIGNAL ;
    PORT
      LAYER M5 ;
        RECT  125.28 63.916 125.304 64 ;
    END
  END b_wdata[164]
  PIN b_wdata[165]
    DIRECTION INPUT ;
    USE SIGNAL ;
    PORT
      LAYER M5 ;
        RECT  125.376 63.916 125.4 64 ;
    END
  END b_wdata[165]
  PIN b_wdata[166]
    DIRECTION INPUT ;
    USE SIGNAL ;
    PORT
      LAYER M5 ;
        RECT  125.472 63.916 125.496 64 ;
    END
  END b_wdata[166]
  PIN b_wdata[167]
    DIRECTION INPUT ;
    USE SIGNAL ;
    PORT
      LAYER M5 ;
        RECT  125.568 63.916 125.592 64 ;
    END
  END b_wdata[167]
  PIN b_wdata[168]
    DIRECTION INPUT ;
    USE SIGNAL ;
    PORT
      LAYER M5 ;
        RECT  125.664 63.916 125.688 64 ;
    END
  END b_wdata[168]
  PIN b_wdata[169]
    DIRECTION INPUT ;
    USE SIGNAL ;
    PORT
      LAYER M5 ;
        RECT  125.76 63.916 125.784 64 ;
    END
  END b_wdata[169]
  PIN b_wdata[16]
    DIRECTION INPUT ;
    USE SIGNAL ;
    PORT
      LAYER M5 ;
        RECT  111.072 63.916 111.096 64 ;
    END
  END b_wdata[16]
  PIN b_wdata[170]
    DIRECTION INPUT ;
    USE SIGNAL ;
    PORT
      LAYER M5 ;
        RECT  125.856 63.916 125.88 64 ;
    END
  END b_wdata[170]
  PIN b_wdata[171]
    DIRECTION INPUT ;
    USE SIGNAL ;
    PORT
      LAYER M5 ;
        RECT  125.952 63.916 125.976 64 ;
    END
  END b_wdata[171]
  PIN b_wdata[172]
    DIRECTION INPUT ;
    USE SIGNAL ;
    PORT
      LAYER M5 ;
        RECT  126.048 63.916 126.072 64 ;
    END
  END b_wdata[172]
  PIN b_wdata[173]
    DIRECTION INPUT ;
    USE SIGNAL ;
    PORT
      LAYER M5 ;
        RECT  126.144 63.916 126.168 64 ;
    END
  END b_wdata[173]
  PIN b_wdata[174]
    DIRECTION INPUT ;
    USE SIGNAL ;
    PORT
      LAYER M5 ;
        RECT  126.24 63.916 126.264 64 ;
    END
  END b_wdata[174]
  PIN b_wdata[175]
    DIRECTION INPUT ;
    USE SIGNAL ;
    PORT
      LAYER M5 ;
        RECT  126.336 63.916 126.36 64 ;
    END
  END b_wdata[175]
  PIN b_wdata[176]
    DIRECTION INPUT ;
    USE SIGNAL ;
    PORT
      LAYER M5 ;
        RECT  126.432 63.916 126.456 64 ;
    END
  END b_wdata[176]
  PIN b_wdata[177]
    DIRECTION INPUT ;
    USE SIGNAL ;
    PORT
      LAYER M5 ;
        RECT  126.528 63.916 126.552 64 ;
    END
  END b_wdata[177]
  PIN b_wdata[178]
    DIRECTION INPUT ;
    USE SIGNAL ;
    PORT
      LAYER M5 ;
        RECT  126.624 63.916 126.648 64 ;
    END
  END b_wdata[178]
  PIN b_wdata[179]
    DIRECTION INPUT ;
    USE SIGNAL ;
    PORT
      LAYER M5 ;
        RECT  126.72 63.916 126.744 64 ;
    END
  END b_wdata[179]
  PIN b_wdata[17]
    DIRECTION INPUT ;
    USE SIGNAL ;
    PORT
      LAYER M5 ;
        RECT  111.168 63.916 111.192 64 ;
    END
  END b_wdata[17]
  PIN b_wdata[180]
    DIRECTION INPUT ;
    USE SIGNAL ;
    PORT
      LAYER M5 ;
        RECT  126.816 63.916 126.84 64 ;
    END
  END b_wdata[180]
  PIN b_wdata[181]
    DIRECTION INPUT ;
    USE SIGNAL ;
    PORT
      LAYER M5 ;
        RECT  126.912 63.916 126.936 64 ;
    END
  END b_wdata[181]
  PIN b_wdata[182]
    DIRECTION INPUT ;
    USE SIGNAL ;
    PORT
      LAYER M5 ;
        RECT  127.008 63.916 127.032 64 ;
    END
  END b_wdata[182]
  PIN b_wdata[183]
    DIRECTION INPUT ;
    USE SIGNAL ;
    PORT
      LAYER M5 ;
        RECT  127.104 63.916 127.128 64 ;
    END
  END b_wdata[183]
  PIN b_wdata[184]
    DIRECTION INPUT ;
    USE SIGNAL ;
    PORT
      LAYER M5 ;
        RECT  127.2 63.916 127.224 64 ;
    END
  END b_wdata[184]
  PIN b_wdata[185]
    DIRECTION INPUT ;
    USE SIGNAL ;
    PORT
      LAYER M5 ;
        RECT  127.296 63.916 127.32 64 ;
    END
  END b_wdata[185]
  PIN b_wdata[186]
    DIRECTION INPUT ;
    USE SIGNAL ;
    PORT
      LAYER M5 ;
        RECT  127.392 63.916 127.416 64 ;
    END
  END b_wdata[186]
  PIN b_wdata[187]
    DIRECTION INPUT ;
    USE SIGNAL ;
    PORT
      LAYER M5 ;
        RECT  127.488 63.916 127.512 64 ;
    END
  END b_wdata[187]
  PIN b_wdata[188]
    DIRECTION INPUT ;
    USE SIGNAL ;
    PORT
      LAYER M5 ;
        RECT  127.584 63.916 127.608 64 ;
    END
  END b_wdata[188]
  PIN b_wdata[189]
    DIRECTION INPUT ;
    USE SIGNAL ;
    PORT
      LAYER M5 ;
        RECT  127.68 63.916 127.704 64 ;
    END
  END b_wdata[189]
  PIN b_wdata[18]
    DIRECTION INPUT ;
    USE SIGNAL ;
    PORT
      LAYER M5 ;
        RECT  111.264 63.916 111.288 64 ;
    END
  END b_wdata[18]
  PIN b_wdata[190]
    DIRECTION INPUT ;
    USE SIGNAL ;
    PORT
      LAYER M5 ;
        RECT  127.776 63.916 127.8 64 ;
    END
  END b_wdata[190]
  PIN b_wdata[191]
    DIRECTION INPUT ;
    USE SIGNAL ;
    PORT
      LAYER M5 ;
        RECT  127.872 63.916 127.896 64 ;
    END
  END b_wdata[191]
  PIN b_wdata[192]
    DIRECTION INPUT ;
    USE SIGNAL ;
    PORT
      LAYER M5 ;
        RECT  127.968 63.916 127.992 64 ;
    END
  END b_wdata[192]
  PIN b_wdata[193]
    DIRECTION INPUT ;
    USE SIGNAL ;
    PORT
      LAYER M5 ;
        RECT  128.064 63.916 128.088 64 ;
    END
  END b_wdata[193]
  PIN b_wdata[194]
    DIRECTION INPUT ;
    USE SIGNAL ;
    PORT
      LAYER M5 ;
        RECT  128.16 63.916 128.184 64 ;
    END
  END b_wdata[194]
  PIN b_wdata[195]
    DIRECTION INPUT ;
    USE SIGNAL ;
    PORT
      LAYER M5 ;
        RECT  128.256 63.916 128.28 64 ;
    END
  END b_wdata[195]
  PIN b_wdata[196]
    DIRECTION INPUT ;
    USE SIGNAL ;
    PORT
      LAYER M5 ;
        RECT  128.352 63.916 128.376 64 ;
    END
  END b_wdata[196]
  PIN b_wdata[197]
    DIRECTION INPUT ;
    USE SIGNAL ;
    PORT
      LAYER M5 ;
        RECT  128.448 63.916 128.472 64 ;
    END
  END b_wdata[197]
  PIN b_wdata[198]
    DIRECTION INPUT ;
    USE SIGNAL ;
    PORT
      LAYER M5 ;
        RECT  128.544 63.916 128.568 64 ;
    END
  END b_wdata[198]
  PIN b_wdata[199]
    DIRECTION INPUT ;
    USE SIGNAL ;
    PORT
      LAYER M5 ;
        RECT  128.64 63.916 128.664 64 ;
    END
  END b_wdata[199]
  PIN b_wdata[19]
    DIRECTION INPUT ;
    USE SIGNAL ;
    PORT
      LAYER M5 ;
        RECT  111.36 63.916 111.384 64 ;
    END
  END b_wdata[19]
  PIN b_wdata[1]
    DIRECTION INPUT ;
    USE SIGNAL ;
    PORT
      LAYER M5 ;
        RECT  109.632 63.916 109.656 64 ;
    END
  END b_wdata[1]
  PIN b_wdata[200]
    DIRECTION INPUT ;
    USE SIGNAL ;
    PORT
      LAYER M5 ;
        RECT  128.736 63.916 128.76 64 ;
    END
  END b_wdata[200]
  PIN b_wdata[201]
    DIRECTION INPUT ;
    USE SIGNAL ;
    PORT
      LAYER M5 ;
        RECT  128.832 63.916 128.856 64 ;
    END
  END b_wdata[201]
  PIN b_wdata[202]
    DIRECTION INPUT ;
    USE SIGNAL ;
    PORT
      LAYER M5 ;
        RECT  128.928 63.916 128.952 64 ;
    END
  END b_wdata[202]
  PIN b_wdata[203]
    DIRECTION INPUT ;
    USE SIGNAL ;
    PORT
      LAYER M5 ;
        RECT  129.024 63.916 129.048 64 ;
    END
  END b_wdata[203]
  PIN b_wdata[204]
    DIRECTION INPUT ;
    USE SIGNAL ;
    PORT
      LAYER M5 ;
        RECT  129.12 63.916 129.144 64 ;
    END
  END b_wdata[204]
  PIN b_wdata[205]
    DIRECTION INPUT ;
    USE SIGNAL ;
    PORT
      LAYER M5 ;
        RECT  129.216 63.916 129.24 64 ;
    END
  END b_wdata[205]
  PIN b_wdata[206]
    DIRECTION INPUT ;
    USE SIGNAL ;
    PORT
      LAYER M5 ;
        RECT  129.312 63.916 129.336 64 ;
    END
  END b_wdata[206]
  PIN b_wdata[207]
    DIRECTION INPUT ;
    USE SIGNAL ;
    PORT
      LAYER M5 ;
        RECT  129.408 63.916 129.432 64 ;
    END
  END b_wdata[207]
  PIN b_wdata[208]
    DIRECTION INPUT ;
    USE SIGNAL ;
    PORT
      LAYER M5 ;
        RECT  129.504 63.916 129.528 64 ;
    END
  END b_wdata[208]
  PIN b_wdata[209]
    DIRECTION INPUT ;
    USE SIGNAL ;
    PORT
      LAYER M5 ;
        RECT  129.6 63.916 129.624 64 ;
    END
  END b_wdata[209]
  PIN b_wdata[20]
    DIRECTION INPUT ;
    USE SIGNAL ;
    PORT
      LAYER M5 ;
        RECT  111.456 63.916 111.48 64 ;
    END
  END b_wdata[20]
  PIN b_wdata[210]
    DIRECTION INPUT ;
    USE SIGNAL ;
    PORT
      LAYER M5 ;
        RECT  129.696 63.916 129.72 64 ;
    END
  END b_wdata[210]
  PIN b_wdata[211]
    DIRECTION INPUT ;
    USE SIGNAL ;
    PORT
      LAYER M5 ;
        RECT  129.792 63.916 129.816 64 ;
    END
  END b_wdata[211]
  PIN b_wdata[212]
    DIRECTION INPUT ;
    USE SIGNAL ;
    PORT
      LAYER M5 ;
        RECT  129.888 63.916 129.912 64 ;
    END
  END b_wdata[212]
  PIN b_wdata[213]
    DIRECTION INPUT ;
    USE SIGNAL ;
    PORT
      LAYER M5 ;
        RECT  129.984 63.916 130.008 64 ;
    END
  END b_wdata[213]
  PIN b_wdata[214]
    DIRECTION INPUT ;
    USE SIGNAL ;
    PORT
      LAYER M5 ;
        RECT  130.08 63.916 130.104 64 ;
    END
  END b_wdata[214]
  PIN b_wdata[215]
    DIRECTION INPUT ;
    USE SIGNAL ;
    PORT
      LAYER M5 ;
        RECT  130.176 63.916 130.2 64 ;
    END
  END b_wdata[215]
  PIN b_wdata[216]
    DIRECTION INPUT ;
    USE SIGNAL ;
    PORT
      LAYER M5 ;
        RECT  130.272 63.916 130.296 64 ;
    END
  END b_wdata[216]
  PIN b_wdata[217]
    DIRECTION INPUT ;
    USE SIGNAL ;
    PORT
      LAYER M5 ;
        RECT  130.368 63.916 130.392 64 ;
    END
  END b_wdata[217]
  PIN b_wdata[218]
    DIRECTION INPUT ;
    USE SIGNAL ;
    PORT
      LAYER M5 ;
        RECT  130.464 63.916 130.488 64 ;
    END
  END b_wdata[218]
  PIN b_wdata[219]
    DIRECTION INPUT ;
    USE SIGNAL ;
    PORT
      LAYER M5 ;
        RECT  130.56 63.916 130.584 64 ;
    END
  END b_wdata[219]
  PIN b_wdata[21]
    DIRECTION INPUT ;
    USE SIGNAL ;
    PORT
      LAYER M5 ;
        RECT  111.552 63.916 111.576 64 ;
    END
  END b_wdata[21]
  PIN b_wdata[220]
    DIRECTION INPUT ;
    USE SIGNAL ;
    PORT
      LAYER M5 ;
        RECT  130.656 63.916 130.68 64 ;
    END
  END b_wdata[220]
  PIN b_wdata[221]
    DIRECTION INPUT ;
    USE SIGNAL ;
    PORT
      LAYER M5 ;
        RECT  130.752 63.916 130.776 64 ;
    END
  END b_wdata[221]
  PIN b_wdata[222]
    DIRECTION INPUT ;
    USE SIGNAL ;
    PORT
      LAYER M5 ;
        RECT  130.848 63.916 130.872 64 ;
    END
  END b_wdata[222]
  PIN b_wdata[223]
    DIRECTION INPUT ;
    USE SIGNAL ;
    PORT
      LAYER M5 ;
        RECT  130.944 63.916 130.968 64 ;
    END
  END b_wdata[223]
  PIN b_wdata[224]
    DIRECTION INPUT ;
    USE SIGNAL ;
    PORT
      LAYER M5 ;
        RECT  131.04 63.916 131.064 64 ;
    END
  END b_wdata[224]
  PIN b_wdata[225]
    DIRECTION INPUT ;
    USE SIGNAL ;
    PORT
      LAYER M5 ;
        RECT  131.136 63.916 131.16 64 ;
    END
  END b_wdata[225]
  PIN b_wdata[226]
    DIRECTION INPUT ;
    USE SIGNAL ;
    PORT
      LAYER M5 ;
        RECT  131.232 63.916 131.256 64 ;
    END
  END b_wdata[226]
  PIN b_wdata[227]
    DIRECTION INPUT ;
    USE SIGNAL ;
    PORT
      LAYER M5 ;
        RECT  131.328 63.916 131.352 64 ;
    END
  END b_wdata[227]
  PIN b_wdata[228]
    DIRECTION INPUT ;
    USE SIGNAL ;
    PORT
      LAYER M5 ;
        RECT  131.424 63.916 131.448 64 ;
    END
  END b_wdata[228]
  PIN b_wdata[229]
    DIRECTION INPUT ;
    USE SIGNAL ;
    PORT
      LAYER M5 ;
        RECT  131.52 63.916 131.544 64 ;
    END
  END b_wdata[229]
  PIN b_wdata[22]
    DIRECTION INPUT ;
    USE SIGNAL ;
    PORT
      LAYER M5 ;
        RECT  111.648 63.916 111.672 64 ;
    END
  END b_wdata[22]
  PIN b_wdata[230]
    DIRECTION INPUT ;
    USE SIGNAL ;
    PORT
      LAYER M5 ;
        RECT  131.616 63.916 131.64 64 ;
    END
  END b_wdata[230]
  PIN b_wdata[231]
    DIRECTION INPUT ;
    USE SIGNAL ;
    PORT
      LAYER M5 ;
        RECT  131.712 63.916 131.736 64 ;
    END
  END b_wdata[231]
  PIN b_wdata[232]
    DIRECTION INPUT ;
    USE SIGNAL ;
    PORT
      LAYER M5 ;
        RECT  131.808 63.916 131.832 64 ;
    END
  END b_wdata[232]
  PIN b_wdata[233]
    DIRECTION INPUT ;
    USE SIGNAL ;
    PORT
      LAYER M5 ;
        RECT  131.904 63.916 131.928 64 ;
    END
  END b_wdata[233]
  PIN b_wdata[234]
    DIRECTION INPUT ;
    USE SIGNAL ;
    PORT
      LAYER M5 ;
        RECT  132 63.916 132.024 64 ;
    END
  END b_wdata[234]
  PIN b_wdata[235]
    DIRECTION INPUT ;
    USE SIGNAL ;
    PORT
      LAYER M5 ;
        RECT  132.096 63.916 132.12 64 ;
    END
  END b_wdata[235]
  PIN b_wdata[236]
    DIRECTION INPUT ;
    USE SIGNAL ;
    PORT
      LAYER M5 ;
        RECT  132.192 63.916 132.216 64 ;
    END
  END b_wdata[236]
  PIN b_wdata[237]
    DIRECTION INPUT ;
    USE SIGNAL ;
    PORT
      LAYER M5 ;
        RECT  132.288 63.916 132.312 64 ;
    END
  END b_wdata[237]
  PIN b_wdata[238]
    DIRECTION INPUT ;
    USE SIGNAL ;
    PORT
      LAYER M5 ;
        RECT  132.384 63.916 132.408 64 ;
    END
  END b_wdata[238]
  PIN b_wdata[239]
    DIRECTION INPUT ;
    USE SIGNAL ;
    PORT
      LAYER M5 ;
        RECT  132.48 63.916 132.504 64 ;
    END
  END b_wdata[239]
  PIN b_wdata[23]
    DIRECTION INPUT ;
    USE SIGNAL ;
    PORT
      LAYER M5 ;
        RECT  111.744 63.916 111.768 64 ;
    END
  END b_wdata[23]
  PIN b_wdata[240]
    DIRECTION INPUT ;
    USE SIGNAL ;
    PORT
      LAYER M5 ;
        RECT  132.576 63.916 132.6 64 ;
    END
  END b_wdata[240]
  PIN b_wdata[241]
    DIRECTION INPUT ;
    USE SIGNAL ;
    PORT
      LAYER M5 ;
        RECT  132.672 63.916 132.696 64 ;
    END
  END b_wdata[241]
  PIN b_wdata[242]
    DIRECTION INPUT ;
    USE SIGNAL ;
    PORT
      LAYER M5 ;
        RECT  132.768 63.916 132.792 64 ;
    END
  END b_wdata[242]
  PIN b_wdata[243]
    DIRECTION INPUT ;
    USE SIGNAL ;
    PORT
      LAYER M5 ;
        RECT  132.864 63.916 132.888 64 ;
    END
  END b_wdata[243]
  PIN b_wdata[244]
    DIRECTION INPUT ;
    USE SIGNAL ;
    PORT
      LAYER M5 ;
        RECT  132.96 63.916 132.984 64 ;
    END
  END b_wdata[244]
  PIN b_wdata[245]
    DIRECTION INPUT ;
    USE SIGNAL ;
    PORT
      LAYER M5 ;
        RECT  133.056 63.916 133.08 64 ;
    END
  END b_wdata[245]
  PIN b_wdata[246]
    DIRECTION INPUT ;
    USE SIGNAL ;
    PORT
      LAYER M5 ;
        RECT  133.152 63.916 133.176 64 ;
    END
  END b_wdata[246]
  PIN b_wdata[247]
    DIRECTION INPUT ;
    USE SIGNAL ;
    PORT
      LAYER M5 ;
        RECT  133.248 63.916 133.272 64 ;
    END
  END b_wdata[247]
  PIN b_wdata[248]
    DIRECTION INPUT ;
    USE SIGNAL ;
    PORT
      LAYER M5 ;
        RECT  133.344 63.916 133.368 64 ;
    END
  END b_wdata[248]
  PIN b_wdata[249]
    DIRECTION INPUT ;
    USE SIGNAL ;
    PORT
      LAYER M5 ;
        RECT  133.44 63.916 133.464 64 ;
    END
  END b_wdata[249]
  PIN b_wdata[24]
    DIRECTION INPUT ;
    USE SIGNAL ;
    PORT
      LAYER M5 ;
        RECT  111.84 63.916 111.864 64 ;
    END
  END b_wdata[24]
  PIN b_wdata[250]
    DIRECTION INPUT ;
    USE SIGNAL ;
    PORT
      LAYER M5 ;
        RECT  133.536 63.916 133.56 64 ;
    END
  END b_wdata[250]
  PIN b_wdata[251]
    DIRECTION INPUT ;
    USE SIGNAL ;
    PORT
      LAYER M5 ;
        RECT  133.632 63.916 133.656 64 ;
    END
  END b_wdata[251]
  PIN b_wdata[252]
    DIRECTION INPUT ;
    USE SIGNAL ;
    PORT
      LAYER M5 ;
        RECT  133.728 63.916 133.752 64 ;
    END
  END b_wdata[252]
  PIN b_wdata[253]
    DIRECTION INPUT ;
    USE SIGNAL ;
    PORT
      LAYER M5 ;
        RECT  133.824 63.916 133.848 64 ;
    END
  END b_wdata[253]
  PIN b_wdata[254]
    DIRECTION INPUT ;
    USE SIGNAL ;
    PORT
      LAYER M5 ;
        RECT  133.92 63.916 133.944 64 ;
    END
  END b_wdata[254]
  PIN b_wdata[255]
    DIRECTION INPUT ;
    USE SIGNAL ;
    PORT
      LAYER M5 ;
        RECT  134.016 63.916 134.04 64 ;
    END
  END b_wdata[255]
  PIN b_wdata[25]
    DIRECTION INPUT ;
    USE SIGNAL ;
    PORT
      LAYER M5 ;
        RECT  111.936 63.916 111.96 64 ;
    END
  END b_wdata[25]
  PIN b_wdata[26]
    DIRECTION INPUT ;
    USE SIGNAL ;
    PORT
      LAYER M5 ;
        RECT  112.032 63.916 112.056 64 ;
    END
  END b_wdata[26]
  PIN b_wdata[27]
    DIRECTION INPUT ;
    USE SIGNAL ;
    PORT
      LAYER M5 ;
        RECT  112.128 63.916 112.152 64 ;
    END
  END b_wdata[27]
  PIN b_wdata[28]
    DIRECTION INPUT ;
    USE SIGNAL ;
    PORT
      LAYER M5 ;
        RECT  112.224 63.916 112.248 64 ;
    END
  END b_wdata[28]
  PIN b_wdata[29]
    DIRECTION INPUT ;
    USE SIGNAL ;
    PORT
      LAYER M5 ;
        RECT  112.32 63.916 112.344 64 ;
    END
  END b_wdata[29]
  PIN b_wdata[2]
    DIRECTION INPUT ;
    USE SIGNAL ;
    PORT
      LAYER M5 ;
        RECT  109.728 63.916 109.752 64 ;
    END
  END b_wdata[2]
  PIN b_wdata[30]
    DIRECTION INPUT ;
    USE SIGNAL ;
    PORT
      LAYER M5 ;
        RECT  112.416 63.916 112.44 64 ;
    END
  END b_wdata[30]
  PIN b_wdata[31]
    DIRECTION INPUT ;
    USE SIGNAL ;
    PORT
      LAYER M5 ;
        RECT  112.512 63.916 112.536 64 ;
    END
  END b_wdata[31]
  PIN b_wdata[32]
    DIRECTION INPUT ;
    USE SIGNAL ;
    PORT
      LAYER M5 ;
        RECT  112.608 63.916 112.632 64 ;
    END
  END b_wdata[32]
  PIN b_wdata[33]
    DIRECTION INPUT ;
    USE SIGNAL ;
    PORT
      LAYER M5 ;
        RECT  112.704 63.916 112.728 64 ;
    END
  END b_wdata[33]
  PIN b_wdata[34]
    DIRECTION INPUT ;
    USE SIGNAL ;
    PORT
      LAYER M5 ;
        RECT  112.8 63.916 112.824 64 ;
    END
  END b_wdata[34]
  PIN b_wdata[35]
    DIRECTION INPUT ;
    USE SIGNAL ;
    PORT
      LAYER M5 ;
        RECT  112.896 63.916 112.92 64 ;
    END
  END b_wdata[35]
  PIN b_wdata[36]
    DIRECTION INPUT ;
    USE SIGNAL ;
    PORT
      LAYER M5 ;
        RECT  112.992 63.916 113.016 64 ;
    END
  END b_wdata[36]
  PIN b_wdata[37]
    DIRECTION INPUT ;
    USE SIGNAL ;
    PORT
      LAYER M5 ;
        RECT  113.088 63.916 113.112 64 ;
    END
  END b_wdata[37]
  PIN b_wdata[38]
    DIRECTION INPUT ;
    USE SIGNAL ;
    PORT
      LAYER M5 ;
        RECT  113.184 63.916 113.208 64 ;
    END
  END b_wdata[38]
  PIN b_wdata[39]
    DIRECTION INPUT ;
    USE SIGNAL ;
    PORT
      LAYER M5 ;
        RECT  113.28 63.916 113.304 64 ;
    END
  END b_wdata[39]
  PIN b_wdata[3]
    DIRECTION INPUT ;
    USE SIGNAL ;
    PORT
      LAYER M5 ;
        RECT  109.824 63.916 109.848 64 ;
    END
  END b_wdata[3]
  PIN b_wdata[40]
    DIRECTION INPUT ;
    USE SIGNAL ;
    PORT
      LAYER M5 ;
        RECT  113.376 63.916 113.4 64 ;
    END
  END b_wdata[40]
  PIN b_wdata[41]
    DIRECTION INPUT ;
    USE SIGNAL ;
    PORT
      LAYER M5 ;
        RECT  113.472 63.916 113.496 64 ;
    END
  END b_wdata[41]
  PIN b_wdata[42]
    DIRECTION INPUT ;
    USE SIGNAL ;
    PORT
      LAYER M5 ;
        RECT  113.568 63.916 113.592 64 ;
    END
  END b_wdata[42]
  PIN b_wdata[43]
    DIRECTION INPUT ;
    USE SIGNAL ;
    PORT
      LAYER M5 ;
        RECT  113.664 63.916 113.688 64 ;
    END
  END b_wdata[43]
  PIN b_wdata[44]
    DIRECTION INPUT ;
    USE SIGNAL ;
    PORT
      LAYER M5 ;
        RECT  113.76 63.916 113.784 64 ;
    END
  END b_wdata[44]
  PIN b_wdata[45]
    DIRECTION INPUT ;
    USE SIGNAL ;
    PORT
      LAYER M5 ;
        RECT  113.856 63.916 113.88 64 ;
    END
  END b_wdata[45]
  PIN b_wdata[46]
    DIRECTION INPUT ;
    USE SIGNAL ;
    PORT
      LAYER M5 ;
        RECT  113.952 63.916 113.976 64 ;
    END
  END b_wdata[46]
  PIN b_wdata[47]
    DIRECTION INPUT ;
    USE SIGNAL ;
    PORT
      LAYER M5 ;
        RECT  114.048 63.916 114.072 64 ;
    END
  END b_wdata[47]
  PIN b_wdata[48]
    DIRECTION INPUT ;
    USE SIGNAL ;
    PORT
      LAYER M5 ;
        RECT  114.144 63.916 114.168 64 ;
    END
  END b_wdata[48]
  PIN b_wdata[49]
    DIRECTION INPUT ;
    USE SIGNAL ;
    PORT
      LAYER M5 ;
        RECT  114.24 63.916 114.264 64 ;
    END
  END b_wdata[49]
  PIN b_wdata[4]
    DIRECTION INPUT ;
    USE SIGNAL ;
    PORT
      LAYER M5 ;
        RECT  109.92 63.916 109.944 64 ;
    END
  END b_wdata[4]
  PIN b_wdata[50]
    DIRECTION INPUT ;
    USE SIGNAL ;
    PORT
      LAYER M5 ;
        RECT  114.336 63.916 114.36 64 ;
    END
  END b_wdata[50]
  PIN b_wdata[51]
    DIRECTION INPUT ;
    USE SIGNAL ;
    PORT
      LAYER M5 ;
        RECT  114.432 63.916 114.456 64 ;
    END
  END b_wdata[51]
  PIN b_wdata[52]
    DIRECTION INPUT ;
    USE SIGNAL ;
    PORT
      LAYER M5 ;
        RECT  114.528 63.916 114.552 64 ;
    END
  END b_wdata[52]
  PIN b_wdata[53]
    DIRECTION INPUT ;
    USE SIGNAL ;
    PORT
      LAYER M5 ;
        RECT  114.624 63.916 114.648 64 ;
    END
  END b_wdata[53]
  PIN b_wdata[54]
    DIRECTION INPUT ;
    USE SIGNAL ;
    PORT
      LAYER M5 ;
        RECT  114.72 63.916 114.744 64 ;
    END
  END b_wdata[54]
  PIN b_wdata[55]
    DIRECTION INPUT ;
    USE SIGNAL ;
    PORT
      LAYER M5 ;
        RECT  114.816 63.916 114.84 64 ;
    END
  END b_wdata[55]
  PIN b_wdata[56]
    DIRECTION INPUT ;
    USE SIGNAL ;
    PORT
      LAYER M5 ;
        RECT  114.912 63.916 114.936 64 ;
    END
  END b_wdata[56]
  PIN b_wdata[57]
    DIRECTION INPUT ;
    USE SIGNAL ;
    PORT
      LAYER M5 ;
        RECT  115.008 63.916 115.032 64 ;
    END
  END b_wdata[57]
  PIN b_wdata[58]
    DIRECTION INPUT ;
    USE SIGNAL ;
    PORT
      LAYER M5 ;
        RECT  115.104 63.916 115.128 64 ;
    END
  END b_wdata[58]
  PIN b_wdata[59]
    DIRECTION INPUT ;
    USE SIGNAL ;
    PORT
      LAYER M5 ;
        RECT  115.2 63.916 115.224 64 ;
    END
  END b_wdata[59]
  PIN b_wdata[5]
    DIRECTION INPUT ;
    USE SIGNAL ;
    PORT
      LAYER M5 ;
        RECT  110.016 63.916 110.04 64 ;
    END
  END b_wdata[5]
  PIN b_wdata[60]
    DIRECTION INPUT ;
    USE SIGNAL ;
    PORT
      LAYER M5 ;
        RECT  115.296 63.916 115.32 64 ;
    END
  END b_wdata[60]
  PIN b_wdata[61]
    DIRECTION INPUT ;
    USE SIGNAL ;
    PORT
      LAYER M5 ;
        RECT  115.392 63.916 115.416 64 ;
    END
  END b_wdata[61]
  PIN b_wdata[62]
    DIRECTION INPUT ;
    USE SIGNAL ;
    PORT
      LAYER M5 ;
        RECT  115.488 63.916 115.512 64 ;
    END
  END b_wdata[62]
  PIN b_wdata[63]
    DIRECTION INPUT ;
    USE SIGNAL ;
    PORT
      LAYER M5 ;
        RECT  115.584 63.916 115.608 64 ;
    END
  END b_wdata[63]
  PIN b_wdata[64]
    DIRECTION INPUT ;
    USE SIGNAL ;
    PORT
      LAYER M5 ;
        RECT  115.68 63.916 115.704 64 ;
    END
  END b_wdata[64]
  PIN b_wdata[65]
    DIRECTION INPUT ;
    USE SIGNAL ;
    PORT
      LAYER M5 ;
        RECT  115.776 63.916 115.8 64 ;
    END
  END b_wdata[65]
  PIN b_wdata[66]
    DIRECTION INPUT ;
    USE SIGNAL ;
    PORT
      LAYER M5 ;
        RECT  115.872 63.916 115.896 64 ;
    END
  END b_wdata[66]
  PIN b_wdata[67]
    DIRECTION INPUT ;
    USE SIGNAL ;
    PORT
      LAYER M5 ;
        RECT  115.968 63.916 115.992 64 ;
    END
  END b_wdata[67]
  PIN b_wdata[68]
    DIRECTION INPUT ;
    USE SIGNAL ;
    PORT
      LAYER M5 ;
        RECT  116.064 63.916 116.088 64 ;
    END
  END b_wdata[68]
  PIN b_wdata[69]
    DIRECTION INPUT ;
    USE SIGNAL ;
    PORT
      LAYER M5 ;
        RECT  116.16 63.916 116.184 64 ;
    END
  END b_wdata[69]
  PIN b_wdata[6]
    DIRECTION INPUT ;
    USE SIGNAL ;
    PORT
      LAYER M5 ;
        RECT  110.112 63.916 110.136 64 ;
    END
  END b_wdata[6]
  PIN b_wdata[70]
    DIRECTION INPUT ;
    USE SIGNAL ;
    PORT
      LAYER M5 ;
        RECT  116.256 63.916 116.28 64 ;
    END
  END b_wdata[70]
  PIN b_wdata[71]
    DIRECTION INPUT ;
    USE SIGNAL ;
    PORT
      LAYER M5 ;
        RECT  116.352 63.916 116.376 64 ;
    END
  END b_wdata[71]
  PIN b_wdata[72]
    DIRECTION INPUT ;
    USE SIGNAL ;
    PORT
      LAYER M5 ;
        RECT  116.448 63.916 116.472 64 ;
    END
  END b_wdata[72]
  PIN b_wdata[73]
    DIRECTION INPUT ;
    USE SIGNAL ;
    PORT
      LAYER M5 ;
        RECT  116.544 63.916 116.568 64 ;
    END
  END b_wdata[73]
  PIN b_wdata[74]
    DIRECTION INPUT ;
    USE SIGNAL ;
    PORT
      LAYER M5 ;
        RECT  116.64 63.916 116.664 64 ;
    END
  END b_wdata[74]
  PIN b_wdata[75]
    DIRECTION INPUT ;
    USE SIGNAL ;
    PORT
      LAYER M5 ;
        RECT  116.736 63.916 116.76 64 ;
    END
  END b_wdata[75]
  PIN b_wdata[76]
    DIRECTION INPUT ;
    USE SIGNAL ;
    PORT
      LAYER M5 ;
        RECT  116.832 63.916 116.856 64 ;
    END
  END b_wdata[76]
  PIN b_wdata[77]
    DIRECTION INPUT ;
    USE SIGNAL ;
    PORT
      LAYER M5 ;
        RECT  116.928 63.916 116.952 64 ;
    END
  END b_wdata[77]
  PIN b_wdata[78]
    DIRECTION INPUT ;
    USE SIGNAL ;
    PORT
      LAYER M5 ;
        RECT  117.024 63.916 117.048 64 ;
    END
  END b_wdata[78]
  PIN b_wdata[79]
    DIRECTION INPUT ;
    USE SIGNAL ;
    PORT
      LAYER M5 ;
        RECT  117.12 63.916 117.144 64 ;
    END
  END b_wdata[79]
  PIN b_wdata[7]
    DIRECTION INPUT ;
    USE SIGNAL ;
    PORT
      LAYER M5 ;
        RECT  110.208 63.916 110.232 64 ;
    END
  END b_wdata[7]
  PIN b_wdata[80]
    DIRECTION INPUT ;
    USE SIGNAL ;
    PORT
      LAYER M5 ;
        RECT  117.216 63.916 117.24 64 ;
    END
  END b_wdata[80]
  PIN b_wdata[81]
    DIRECTION INPUT ;
    USE SIGNAL ;
    PORT
      LAYER M5 ;
        RECT  117.312 63.916 117.336 64 ;
    END
  END b_wdata[81]
  PIN b_wdata[82]
    DIRECTION INPUT ;
    USE SIGNAL ;
    PORT
      LAYER M5 ;
        RECT  117.408 63.916 117.432 64 ;
    END
  END b_wdata[82]
  PIN b_wdata[83]
    DIRECTION INPUT ;
    USE SIGNAL ;
    PORT
      LAYER M5 ;
        RECT  117.504 63.916 117.528 64 ;
    END
  END b_wdata[83]
  PIN b_wdata[84]
    DIRECTION INPUT ;
    USE SIGNAL ;
    PORT
      LAYER M5 ;
        RECT  117.6 63.916 117.624 64 ;
    END
  END b_wdata[84]
  PIN b_wdata[85]
    DIRECTION INPUT ;
    USE SIGNAL ;
    PORT
      LAYER M5 ;
        RECT  117.696 63.916 117.72 64 ;
    END
  END b_wdata[85]
  PIN b_wdata[86]
    DIRECTION INPUT ;
    USE SIGNAL ;
    PORT
      LAYER M5 ;
        RECT  117.792 63.916 117.816 64 ;
    END
  END b_wdata[86]
  PIN b_wdata[87]
    DIRECTION INPUT ;
    USE SIGNAL ;
    PORT
      LAYER M5 ;
        RECT  117.888 63.916 117.912 64 ;
    END
  END b_wdata[87]
  PIN b_wdata[88]
    DIRECTION INPUT ;
    USE SIGNAL ;
    PORT
      LAYER M5 ;
        RECT  117.984 63.916 118.008 64 ;
    END
  END b_wdata[88]
  PIN b_wdata[89]
    DIRECTION INPUT ;
    USE SIGNAL ;
    PORT
      LAYER M5 ;
        RECT  118.08 63.916 118.104 64 ;
    END
  END b_wdata[89]
  PIN b_wdata[8]
    DIRECTION INPUT ;
    USE SIGNAL ;
    PORT
      LAYER M5 ;
        RECT  110.304 63.916 110.328 64 ;
    END
  END b_wdata[8]
  PIN b_wdata[90]
    DIRECTION INPUT ;
    USE SIGNAL ;
    PORT
      LAYER M5 ;
        RECT  118.176 63.916 118.2 64 ;
    END
  END b_wdata[90]
  PIN b_wdata[91]
    DIRECTION INPUT ;
    USE SIGNAL ;
    PORT
      LAYER M5 ;
        RECT  118.272 63.916 118.296 64 ;
    END
  END b_wdata[91]
  PIN b_wdata[92]
    DIRECTION INPUT ;
    USE SIGNAL ;
    PORT
      LAYER M5 ;
        RECT  118.368 63.916 118.392 64 ;
    END
  END b_wdata[92]
  PIN b_wdata[93]
    DIRECTION INPUT ;
    USE SIGNAL ;
    PORT
      LAYER M5 ;
        RECT  118.464 63.916 118.488 64 ;
    END
  END b_wdata[93]
  PIN b_wdata[94]
    DIRECTION INPUT ;
    USE SIGNAL ;
    PORT
      LAYER M5 ;
        RECT  118.56 63.916 118.584 64 ;
    END
  END b_wdata[94]
  PIN b_wdata[95]
    DIRECTION INPUT ;
    USE SIGNAL ;
    PORT
      LAYER M5 ;
        RECT  118.656 63.916 118.68 64 ;
    END
  END b_wdata[95]
  PIN b_wdata[96]
    DIRECTION INPUT ;
    USE SIGNAL ;
    PORT
      LAYER M5 ;
        RECT  118.752 63.916 118.776 64 ;
    END
  END b_wdata[96]
  PIN b_wdata[97]
    DIRECTION INPUT ;
    USE SIGNAL ;
    PORT
      LAYER M5 ;
        RECT  118.848 63.916 118.872 64 ;
    END
  END b_wdata[97]
  PIN b_wdata[98]
    DIRECTION INPUT ;
    USE SIGNAL ;
    PORT
      LAYER M5 ;
        RECT  118.944 63.916 118.968 64 ;
    END
  END b_wdata[98]
  PIN b_wdata[99]
    DIRECTION INPUT ;
    USE SIGNAL ;
    PORT
      LAYER M5 ;
        RECT  119.04 63.916 119.064 64 ;
    END
  END b_wdata[99]
  PIN b_wdata[9]
    DIRECTION INPUT ;
    USE SIGNAL ;
    PORT
      LAYER M5 ;
        RECT  110.4 63.916 110.424 64 ;
    END
  END b_wdata[9]
  PIN b_we
    DIRECTION INPUT ;
    USE SIGNAL ;
    PORT
      LAYER M5 ;
        RECT  134.112 63.916 134.136 64 ;
    END
  END b_we
  PIN b_wr_done
    DIRECTION OUTPUT ;
    USE SIGNAL ;
    PORT
      LAYER M5 ;
        RECT  134.208 63.916 134.232 64 ;
    END
  END b_wr_done
  PIN b_wstrb[0]
    DIRECTION INPUT ;
    USE SIGNAL ;
    PORT
      LAYER M5 ;
        RECT  134.304 63.916 134.328 64 ;
    END
  END b_wstrb[0]
  PIN b_wstrb[10]
    DIRECTION INPUT ;
    USE SIGNAL ;
    PORT
      LAYER M5 ;
        RECT  135.264 63.916 135.288 64 ;
    END
  END b_wstrb[10]
  PIN b_wstrb[11]
    DIRECTION INPUT ;
    USE SIGNAL ;
    PORT
      LAYER M5 ;
        RECT  135.36 63.916 135.384 64 ;
    END
  END b_wstrb[11]
  PIN b_wstrb[12]
    DIRECTION INPUT ;
    USE SIGNAL ;
    PORT
      LAYER M5 ;
        RECT  135.456 63.916 135.48 64 ;
    END
  END b_wstrb[12]
  PIN b_wstrb[13]
    DIRECTION INPUT ;
    USE SIGNAL ;
    PORT
      LAYER M5 ;
        RECT  135.552 63.916 135.576 64 ;
    END
  END b_wstrb[13]
  PIN b_wstrb[14]
    DIRECTION INPUT ;
    USE SIGNAL ;
    PORT
      LAYER M5 ;
        RECT  135.648 63.916 135.672 64 ;
    END
  END b_wstrb[14]
  PIN b_wstrb[15]
    DIRECTION INPUT ;
    USE SIGNAL ;
    PORT
      LAYER M5 ;
        RECT  135.744 63.916 135.768 64 ;
    END
  END b_wstrb[15]
  PIN b_wstrb[16]
    DIRECTION INPUT ;
    USE SIGNAL ;
    PORT
      LAYER M5 ;
        RECT  135.84 63.916 135.864 64 ;
    END
  END b_wstrb[16]
  PIN b_wstrb[17]
    DIRECTION INPUT ;
    USE SIGNAL ;
    PORT
      LAYER M5 ;
        RECT  135.936 63.916 135.96 64 ;
    END
  END b_wstrb[17]
  PIN b_wstrb[18]
    DIRECTION INPUT ;
    USE SIGNAL ;
    PORT
      LAYER M5 ;
        RECT  136.032 63.916 136.056 64 ;
    END
  END b_wstrb[18]
  PIN b_wstrb[19]
    DIRECTION INPUT ;
    USE SIGNAL ;
    PORT
      LAYER M5 ;
        RECT  136.128 63.916 136.152 64 ;
    END
  END b_wstrb[19]
  PIN b_wstrb[1]
    DIRECTION INPUT ;
    USE SIGNAL ;
    PORT
      LAYER M5 ;
        RECT  134.4 63.916 134.424 64 ;
    END
  END b_wstrb[1]
  PIN b_wstrb[20]
    DIRECTION INPUT ;
    USE SIGNAL ;
    PORT
      LAYER M5 ;
        RECT  136.224 63.916 136.248 64 ;
    END
  END b_wstrb[20]
  PIN b_wstrb[21]
    DIRECTION INPUT ;
    USE SIGNAL ;
    PORT
      LAYER M5 ;
        RECT  136.32 63.916 136.344 64 ;
    END
  END b_wstrb[21]
  PIN b_wstrb[22]
    DIRECTION INPUT ;
    USE SIGNAL ;
    PORT
      LAYER M5 ;
        RECT  136.416 63.916 136.44 64 ;
    END
  END b_wstrb[22]
  PIN b_wstrb[23]
    DIRECTION INPUT ;
    USE SIGNAL ;
    PORT
      LAYER M5 ;
        RECT  136.512 63.916 136.536 64 ;
    END
  END b_wstrb[23]
  PIN b_wstrb[24]
    DIRECTION INPUT ;
    USE SIGNAL ;
    PORT
      LAYER M5 ;
        RECT  136.608 63.916 136.632 64 ;
    END
  END b_wstrb[24]
  PIN b_wstrb[25]
    DIRECTION INPUT ;
    USE SIGNAL ;
    PORT
      LAYER M5 ;
        RECT  136.704 63.916 136.728 64 ;
    END
  END b_wstrb[25]
  PIN b_wstrb[26]
    DIRECTION INPUT ;
    USE SIGNAL ;
    PORT
      LAYER M5 ;
        RECT  136.8 63.916 136.824 64 ;
    END
  END b_wstrb[26]
  PIN b_wstrb[27]
    DIRECTION INPUT ;
    USE SIGNAL ;
    PORT
      LAYER M5 ;
        RECT  136.896 63.916 136.92 64 ;
    END
  END b_wstrb[27]
  PIN b_wstrb[28]
    DIRECTION INPUT ;
    USE SIGNAL ;
    PORT
      LAYER M5 ;
        RECT  136.992 63.916 137.016 64 ;
    END
  END b_wstrb[28]
  PIN b_wstrb[29]
    DIRECTION INPUT ;
    USE SIGNAL ;
    PORT
      LAYER M5 ;
        RECT  137.088 63.916 137.112 64 ;
    END
  END b_wstrb[29]
  PIN b_wstrb[2]
    DIRECTION INPUT ;
    USE SIGNAL ;
    PORT
      LAYER M5 ;
        RECT  134.496 63.916 134.52 64 ;
    END
  END b_wstrb[2]
  PIN b_wstrb[30]
    DIRECTION INPUT ;
    USE SIGNAL ;
    PORT
      LAYER M5 ;
        RECT  137.184 63.916 137.208 64 ;
    END
  END b_wstrb[30]
  PIN b_wstrb[31]
    DIRECTION INPUT ;
    USE SIGNAL ;
    PORT
      LAYER M5 ;
        RECT  137.28 63.916 137.304 64 ;
    END
  END b_wstrb[31]
  PIN b_wstrb[3]
    DIRECTION INPUT ;
    USE SIGNAL ;
    PORT
      LAYER M5 ;
        RECT  134.592 63.916 134.616 64 ;
    END
  END b_wstrb[3]
  PIN b_wstrb[4]
    DIRECTION INPUT ;
    USE SIGNAL ;
    PORT
      LAYER M5 ;
        RECT  134.688 63.916 134.712 64 ;
    END
  END b_wstrb[4]
  PIN b_wstrb[5]
    DIRECTION INPUT ;
    USE SIGNAL ;
    PORT
      LAYER M5 ;
        RECT  134.784 63.916 134.808 64 ;
    END
  END b_wstrb[5]
  PIN b_wstrb[6]
    DIRECTION INPUT ;
    USE SIGNAL ;
    PORT
      LAYER M5 ;
        RECT  134.88 63.916 134.904 64 ;
    END
  END b_wstrb[6]
  PIN b_wstrb[7]
    DIRECTION INPUT ;
    USE SIGNAL ;
    PORT
      LAYER M5 ;
        RECT  134.976 63.916 135 64 ;
    END
  END b_wstrb[7]
  PIN b_wstrb[8]
    DIRECTION INPUT ;
    USE SIGNAL ;
    PORT
      LAYER M5 ;
        RECT  135.072 63.916 135.096 64 ;
    END
  END b_wstrb[8]
  PIN b_wstrb[9]
    DIRECTION INPUT ;
    USE SIGNAL ;
    PORT
      LAYER M5 ;
        RECT  135.168 63.916 135.192 64 ;
    END
  END b_wstrb[9]
  PIN clk
    DIRECTION INPUT ;
    USE SIGNAL ;
    PORT
      LAYER M5 ;
        RECT  255.264 63.916 255.288 64 ;
    END
  END clk
  PIN contend
    DIRECTION OUTPUT ;
    USE SIGNAL ;
    PORT
      LAYER M5 ;
        RECT  255.36 63.916 255.384 64 ;
    END
  END contend
  PIN h_addr[0]
    DIRECTION OUTPUT ;
    USE SIGNAL ;
    PORT
      LAYER M5 ;
        RECT  77.664 0 77.688 0.084 ;
    END
  END h_addr[0]
  PIN h_addr[10]
    DIRECTION OUTPUT ;
    USE SIGNAL ;
    PORT
      LAYER M5 ;
        RECT  78.624 0 78.648 0.084 ;
    END
  END h_addr[10]
  PIN h_addr[11]
    DIRECTION OUTPUT ;
    USE SIGNAL ;
    PORT
      LAYER M5 ;
        RECT  78.72 0 78.744 0.084 ;
    END
  END h_addr[11]
  PIN h_addr[12]
    DIRECTION OUTPUT ;
    USE SIGNAL ;
    PORT
      LAYER M5 ;
        RECT  78.816 0 78.84 0.084 ;
    END
  END h_addr[12]
  PIN h_addr[13]
    DIRECTION OUTPUT ;
    USE SIGNAL ;
    PORT
      LAYER M5 ;
        RECT  78.912 0 78.936 0.084 ;
    END
  END h_addr[13]
  PIN h_addr[14]
    DIRECTION OUTPUT ;
    USE SIGNAL ;
    PORT
      LAYER M5 ;
        RECT  79.008 0 79.032 0.084 ;
    END
  END h_addr[14]
  PIN h_addr[15]
    DIRECTION OUTPUT ;
    USE SIGNAL ;
    PORT
      LAYER M5 ;
        RECT  79.104 0 79.128 0.084 ;
    END
  END h_addr[15]
  PIN h_addr[16]
    DIRECTION OUTPUT ;
    USE SIGNAL ;
    PORT
      LAYER M5 ;
        RECT  79.2 0 79.224 0.084 ;
    END
  END h_addr[16]
  PIN h_addr[17]
    DIRECTION OUTPUT ;
    USE SIGNAL ;
    PORT
      LAYER M5 ;
        RECT  79.296 0 79.32 0.084 ;
    END
  END h_addr[17]
  PIN h_addr[18]
    DIRECTION OUTPUT ;
    USE SIGNAL ;
    PORT
      LAYER M5 ;
        RECT  79.392 0 79.416 0.084 ;
    END
  END h_addr[18]
  PIN h_addr[19]
    DIRECTION OUTPUT ;
    USE SIGNAL ;
    PORT
      LAYER M5 ;
        RECT  79.488 0 79.512 0.084 ;
    END
  END h_addr[19]
  PIN h_addr[1]
    DIRECTION OUTPUT ;
    USE SIGNAL ;
    PORT
      LAYER M5 ;
        RECT  77.76 0 77.784 0.084 ;
    END
  END h_addr[1]
  PIN h_addr[20]
    DIRECTION OUTPUT ;
    USE SIGNAL ;
    PORT
      LAYER M5 ;
        RECT  79.584 0 79.608 0.084 ;
    END
  END h_addr[20]
  PIN h_addr[21]
    DIRECTION OUTPUT ;
    USE SIGNAL ;
    PORT
      LAYER M5 ;
        RECT  79.68 0 79.704 0.084 ;
    END
  END h_addr[21]
  PIN h_addr[22]
    DIRECTION OUTPUT ;
    USE SIGNAL ;
    PORT
      LAYER M5 ;
        RECT  79.776 0 79.8 0.084 ;
    END
  END h_addr[22]
  PIN h_addr[23]
    DIRECTION OUTPUT ;
    USE SIGNAL ;
    PORT
      LAYER M5 ;
        RECT  79.872 0 79.896 0.084 ;
    END
  END h_addr[23]
  PIN h_addr[24]
    DIRECTION OUTPUT ;
    USE SIGNAL ;
    PORT
      LAYER M5 ;
        RECT  79.968 0 79.992 0.084 ;
    END
  END h_addr[24]
  PIN h_addr[25]
    DIRECTION OUTPUT ;
    USE SIGNAL ;
    PORT
      LAYER M5 ;
        RECT  80.064 0 80.088 0.084 ;
    END
  END h_addr[25]
  PIN h_addr[26]
    DIRECTION OUTPUT ;
    USE SIGNAL ;
    PORT
      LAYER M5 ;
        RECT  80.16 0 80.184 0.084 ;
    END
  END h_addr[26]
  PIN h_addr[27]
    DIRECTION OUTPUT ;
    USE SIGNAL ;
    PORT
      LAYER M5 ;
        RECT  80.256 0 80.28 0.084 ;
    END
  END h_addr[27]
  PIN h_addr[28]
    DIRECTION OUTPUT ;
    USE SIGNAL ;
    PORT
      LAYER M5 ;
        RECT  80.352 0 80.376 0.084 ;
    END
  END h_addr[28]
  PIN h_addr[29]
    DIRECTION OUTPUT ;
    USE SIGNAL ;
    PORT
      LAYER M5 ;
        RECT  80.448 0 80.472 0.084 ;
    END
  END h_addr[29]
  PIN h_addr[2]
    DIRECTION OUTPUT ;
    USE SIGNAL ;
    PORT
      LAYER M5 ;
        RECT  77.856 0 77.88 0.084 ;
    END
  END h_addr[2]
  PIN h_addr[3]
    DIRECTION OUTPUT ;
    USE SIGNAL ;
    PORT
      LAYER M5 ;
        RECT  77.952 0 77.976 0.084 ;
    END
  END h_addr[3]
  PIN h_addr[4]
    DIRECTION OUTPUT ;
    USE SIGNAL ;
    PORT
      LAYER M5 ;
        RECT  78.048 0 78.072 0.084 ;
    END
  END h_addr[4]
  PIN h_addr[5]
    DIRECTION OUTPUT ;
    USE SIGNAL ;
    PORT
      LAYER M5 ;
        RECT  78.144 0 78.168 0.084 ;
    END
  END h_addr[5]
  PIN h_addr[6]
    DIRECTION OUTPUT ;
    USE SIGNAL ;
    PORT
      LAYER M5 ;
        RECT  78.24 0 78.264 0.084 ;
    END
  END h_addr[6]
  PIN h_addr[7]
    DIRECTION OUTPUT ;
    USE SIGNAL ;
    PORT
      LAYER M5 ;
        RECT  78.336 0 78.36 0.084 ;
    END
  END h_addr[7]
  PIN h_addr[8]
    DIRECTION OUTPUT ;
    USE SIGNAL ;
    PORT
      LAYER M5 ;
        RECT  78.432 0 78.456 0.084 ;
    END
  END h_addr[8]
  PIN h_addr[9]
    DIRECTION OUTPUT ;
    USE SIGNAL ;
    PORT
      LAYER M5 ;
        RECT  78.528 0 78.552 0.084 ;
    END
  END h_addr[9]
  PIN h_len[0]
    DIRECTION OUTPUT ;
    USE SIGNAL ;
    PORT
      LAYER M5 ;
        RECT  80.544 0 80.568 0.084 ;
    END
  END h_len[0]
  PIN h_len[1]
    DIRECTION OUTPUT ;
    USE SIGNAL ;
    PORT
      LAYER M5 ;
        RECT  80.64 0 80.664 0.084 ;
    END
  END h_len[1]
  PIN h_len[2]
    DIRECTION OUTPUT ;
    USE SIGNAL ;
    PORT
      LAYER M5 ;
        RECT  80.736 0 80.76 0.084 ;
    END
  END h_len[2]
  PIN h_len[3]
    DIRECTION OUTPUT ;
    USE SIGNAL ;
    PORT
      LAYER M5 ;
        RECT  80.832 0 80.856 0.084 ;
    END
  END h_len[3]
  PIN h_rdy
    DIRECTION INPUT ;
    USE SIGNAL ;
    PORT
      LAYER M5 ;
        RECT  80.928 0 80.952 0.084 ;
    END
  END h_rdy
  PIN h_tag[0]
    DIRECTION OUTPUT ;
    USE SIGNAL ;
    PORT
      LAYER M5 ;
        RECT  81.024 0 81.048 0.084 ;
    END
  END h_tag[0]
  PIN h_tag[10]
    DIRECTION OUTPUT ;
    USE SIGNAL ;
    PORT
      LAYER M5 ;
        RECT  81.984 0 82.008 0.084 ;
    END
  END h_tag[10]
  PIN h_tag[11]
    DIRECTION OUTPUT ;
    USE SIGNAL ;
    PORT
      LAYER M5 ;
        RECT  82.08 0 82.104 0.084 ;
    END
  END h_tag[11]
  PIN h_tag[12]
    DIRECTION OUTPUT ;
    USE SIGNAL ;
    PORT
      LAYER M5 ;
        RECT  82.176 0 82.2 0.084 ;
    END
  END h_tag[12]
  PIN h_tag[13]
    DIRECTION OUTPUT ;
    USE SIGNAL ;
    PORT
      LAYER M5 ;
        RECT  82.272 0 82.296 0.084 ;
    END
  END h_tag[13]
  PIN h_tag[14]
    DIRECTION OUTPUT ;
    USE SIGNAL ;
    PORT
      LAYER M5 ;
        RECT  82.368 0 82.392 0.084 ;
    END
  END h_tag[14]
  PIN h_tag[15]
    DIRECTION OUTPUT ;
    USE SIGNAL ;
    PORT
      LAYER M5 ;
        RECT  82.464 0 82.488 0.084 ;
    END
  END h_tag[15]
  PIN h_tag[16]
    DIRECTION OUTPUT ;
    USE SIGNAL ;
    PORT
      LAYER M5 ;
        RECT  82.56 0 82.584 0.084 ;
    END
  END h_tag[16]
  PIN h_tag[1]
    DIRECTION OUTPUT ;
    USE SIGNAL ;
    PORT
      LAYER M5 ;
        RECT  81.12 0 81.144 0.084 ;
    END
  END h_tag[1]
  PIN h_tag[2]
    DIRECTION OUTPUT ;
    USE SIGNAL ;
    PORT
      LAYER M5 ;
        RECT  81.216 0 81.24 0.084 ;
    END
  END h_tag[2]
  PIN h_tag[3]
    DIRECTION OUTPUT ;
    USE SIGNAL ;
    PORT
      LAYER M5 ;
        RECT  81.312 0 81.336 0.084 ;
    END
  END h_tag[3]
  PIN h_tag[4]
    DIRECTION OUTPUT ;
    USE SIGNAL ;
    PORT
      LAYER M5 ;
        RECT  81.408 0 81.432 0.084 ;
    END
  END h_tag[4]
  PIN h_tag[5]
    DIRECTION OUTPUT ;
    USE SIGNAL ;
    PORT
      LAYER M5 ;
        RECT  81.504 0 81.528 0.084 ;
    END
  END h_tag[5]
  PIN h_tag[6]
    DIRECTION OUTPUT ;
    USE SIGNAL ;
    PORT
      LAYER M5 ;
        RECT  81.6 0 81.624 0.084 ;
    END
  END h_tag[6]
  PIN h_tag[7]
    DIRECTION OUTPUT ;
    USE SIGNAL ;
    PORT
      LAYER M5 ;
        RECT  81.696 0 81.72 0.084 ;
    END
  END h_tag[7]
  PIN h_tag[8]
    DIRECTION OUTPUT ;
    USE SIGNAL ;
    PORT
      LAYER M5 ;
        RECT  81.792 0 81.816 0.084 ;
    END
  END h_tag[8]
  PIN h_tag[9]
    DIRECTION OUTPUT ;
    USE SIGNAL ;
    PORT
      LAYER M5 ;
        RECT  81.888 0 81.912 0.084 ;
    END
  END h_tag[9]
  PIN h_v
    DIRECTION OUTPUT ;
    USE SIGNAL ;
    PORT
      LAYER M5 ;
        RECT  82.656 0 82.68 0.084 ;
    END
  END h_v
  PIN h_wdata[0]
    DIRECTION OUTPUT ;
    USE SIGNAL ;
    PORT
      LAYER M5 ;
        RECT  82.752 0 82.776 0.084 ;
    END
  END h_wdata[0]
  PIN h_wdata[100]
    DIRECTION OUTPUT ;
    USE SIGNAL ;
    PORT
      LAYER M5 ;
        RECT  92.352 0 92.376 0.084 ;
    END
  END h_wdata[100]
  PIN h_wdata[101]
    DIRECTION OUTPUT ;
    USE SIGNAL ;
    PORT
      LAYER M5 ;
        RECT  92.448 0 92.472 0.084 ;
    END
  END h_wdata[101]
  PIN h_wdata[102]
    DIRECTION OUTPUT ;
    USE SIGNAL ;
    PORT
      LAYER M5 ;
        RECT  92.544 0 92.568 0.084 ;
    END
  END h_wdata[102]
  PIN h_wdata[103]
    DIRECTION OUTPUT ;
    USE SIGNAL ;
    PORT
      LAYER M5 ;
        RECT  92.64 0 92.664 0.084 ;
    END
  END h_wdata[103]
  PIN h_wdata[104]
    DIRECTION OUTPUT ;
    USE SIGNAL ;
    PORT
      LAYER M5 ;
        RECT  92.736 0 92.76 0.084 ;
    END
  END h_wdata[104]
  PIN h_wdata[105]
    DIRECTION OUTPUT ;
    USE SIGNAL ;
    PORT
      LAYER M5 ;
        RECT  92.832 0 92.856 0.084 ;
    END
  END h_wdata[105]
  PIN h_wdata[106]
    DIRECTION OUTPUT ;
    USE SIGNAL ;
    PORT
      LAYER M5 ;
        RECT  92.928 0 92.952 0.084 ;
    END
  END h_wdata[106]
  PIN h_wdata[107]
    DIRECTION OUTPUT ;
    USE SIGNAL ;
    PORT
      LAYER M5 ;
        RECT  93.024 0 93.048 0.084 ;
    END
  END h_wdata[107]
  PIN h_wdata[108]
    DIRECTION OUTPUT ;
    USE SIGNAL ;
    PORT
      LAYER M5 ;
        RECT  93.12 0 93.144 0.084 ;
    END
  END h_wdata[108]
  PIN h_wdata[109]
    DIRECTION OUTPUT ;
    USE SIGNAL ;
    PORT
      LAYER M5 ;
        RECT  93.216 0 93.24 0.084 ;
    END
  END h_wdata[109]
  PIN h_wdata[10]
    DIRECTION OUTPUT ;
    USE SIGNAL ;
    PORT
      LAYER M5 ;
        RECT  83.712 0 83.736 0.084 ;
    END
  END h_wdata[10]
  PIN h_wdata[110]
    DIRECTION OUTPUT ;
    USE SIGNAL ;
    PORT
      LAYER M5 ;
        RECT  93.312 0 93.336 0.084 ;
    END
  END h_wdata[110]
  PIN h_wdata[111]
    DIRECTION OUTPUT ;
    USE SIGNAL ;
    PORT
      LAYER M5 ;
        RECT  93.408 0 93.432 0.084 ;
    END
  END h_wdata[111]
  PIN h_wdata[112]
    DIRECTION OUTPUT ;
    USE SIGNAL ;
    PORT
      LAYER M5 ;
        RECT  93.504 0 93.528 0.084 ;
    END
  END h_wdata[112]
  PIN h_wdata[113]
    DIRECTION OUTPUT ;
    USE SIGNAL ;
    PORT
      LAYER M5 ;
        RECT  93.6 0 93.624 0.084 ;
    END
  END h_wdata[113]
  PIN h_wdata[114]
    DIRECTION OUTPUT ;
    USE SIGNAL ;
    PORT
      LAYER M5 ;
        RECT  93.696 0 93.72 0.084 ;
    END
  END h_wdata[114]
  PIN h_wdata[115]
    DIRECTION OUTPUT ;
    USE SIGNAL ;
    PORT
      LAYER M5 ;
        RECT  93.792 0 93.816 0.084 ;
    END
  END h_wdata[115]
  PIN h_wdata[116]
    DIRECTION OUTPUT ;
    USE SIGNAL ;
    PORT
      LAYER M5 ;
        RECT  93.888 0 93.912 0.084 ;
    END
  END h_wdata[116]
  PIN h_wdata[117]
    DIRECTION OUTPUT ;
    USE SIGNAL ;
    PORT
      LAYER M5 ;
        RECT  93.984 0 94.008 0.084 ;
    END
  END h_wdata[117]
  PIN h_wdata[118]
    DIRECTION OUTPUT ;
    USE SIGNAL ;
    PORT
      LAYER M5 ;
        RECT  94.08 0 94.104 0.084 ;
    END
  END h_wdata[118]
  PIN h_wdata[119]
    DIRECTION OUTPUT ;
    USE SIGNAL ;
    PORT
      LAYER M5 ;
        RECT  94.176 0 94.2 0.084 ;
    END
  END h_wdata[119]
  PIN h_wdata[11]
    DIRECTION OUTPUT ;
    USE SIGNAL ;
    PORT
      LAYER M5 ;
        RECT  83.808 0 83.832 0.084 ;
    END
  END h_wdata[11]
  PIN h_wdata[120]
    DIRECTION OUTPUT ;
    USE SIGNAL ;
    PORT
      LAYER M5 ;
        RECT  94.272 0 94.296 0.084 ;
    END
  END h_wdata[120]
  PIN h_wdata[121]
    DIRECTION OUTPUT ;
    USE SIGNAL ;
    PORT
      LAYER M5 ;
        RECT  94.368 0 94.392 0.084 ;
    END
  END h_wdata[121]
  PIN h_wdata[122]
    DIRECTION OUTPUT ;
    USE SIGNAL ;
    PORT
      LAYER M5 ;
        RECT  94.464 0 94.488 0.084 ;
    END
  END h_wdata[122]
  PIN h_wdata[123]
    DIRECTION OUTPUT ;
    USE SIGNAL ;
    PORT
      LAYER M5 ;
        RECT  94.56 0 94.584 0.084 ;
    END
  END h_wdata[123]
  PIN h_wdata[124]
    DIRECTION OUTPUT ;
    USE SIGNAL ;
    PORT
      LAYER M5 ;
        RECT  94.656 0 94.68 0.084 ;
    END
  END h_wdata[124]
  PIN h_wdata[125]
    DIRECTION OUTPUT ;
    USE SIGNAL ;
    PORT
      LAYER M5 ;
        RECT  94.752 0 94.776 0.084 ;
    END
  END h_wdata[125]
  PIN h_wdata[126]
    DIRECTION OUTPUT ;
    USE SIGNAL ;
    PORT
      LAYER M5 ;
        RECT  94.848 0 94.872 0.084 ;
    END
  END h_wdata[126]
  PIN h_wdata[127]
    DIRECTION OUTPUT ;
    USE SIGNAL ;
    PORT
      LAYER M5 ;
        RECT  94.944 0 94.968 0.084 ;
    END
  END h_wdata[127]
  PIN h_wdata[128]
    DIRECTION OUTPUT ;
    USE SIGNAL ;
    PORT
      LAYER M5 ;
        RECT  95.04 0 95.064 0.084 ;
    END
  END h_wdata[128]
  PIN h_wdata[129]
    DIRECTION OUTPUT ;
    USE SIGNAL ;
    PORT
      LAYER M5 ;
        RECT  95.136 0 95.16 0.084 ;
    END
  END h_wdata[129]
  PIN h_wdata[12]
    DIRECTION OUTPUT ;
    USE SIGNAL ;
    PORT
      LAYER M5 ;
        RECT  83.904 0 83.928 0.084 ;
    END
  END h_wdata[12]
  PIN h_wdata[130]
    DIRECTION OUTPUT ;
    USE SIGNAL ;
    PORT
      LAYER M5 ;
        RECT  95.232 0 95.256 0.084 ;
    END
  END h_wdata[130]
  PIN h_wdata[131]
    DIRECTION OUTPUT ;
    USE SIGNAL ;
    PORT
      LAYER M5 ;
        RECT  95.328 0 95.352 0.084 ;
    END
  END h_wdata[131]
  PIN h_wdata[132]
    DIRECTION OUTPUT ;
    USE SIGNAL ;
    PORT
      LAYER M5 ;
        RECT  95.424 0 95.448 0.084 ;
    END
  END h_wdata[132]
  PIN h_wdata[133]
    DIRECTION OUTPUT ;
    USE SIGNAL ;
    PORT
      LAYER M5 ;
        RECT  95.52 0 95.544 0.084 ;
    END
  END h_wdata[133]
  PIN h_wdata[134]
    DIRECTION OUTPUT ;
    USE SIGNAL ;
    PORT
      LAYER M5 ;
        RECT  95.616 0 95.64 0.084 ;
    END
  END h_wdata[134]
  PIN h_wdata[135]
    DIRECTION OUTPUT ;
    USE SIGNAL ;
    PORT
      LAYER M5 ;
        RECT  95.712 0 95.736 0.084 ;
    END
  END h_wdata[135]
  PIN h_wdata[136]
    DIRECTION OUTPUT ;
    USE SIGNAL ;
    PORT
      LAYER M5 ;
        RECT  95.808 0 95.832 0.084 ;
    END
  END h_wdata[136]
  PIN h_wdata[137]
    DIRECTION OUTPUT ;
    USE SIGNAL ;
    PORT
      LAYER M5 ;
        RECT  95.904 0 95.928 0.084 ;
    END
  END h_wdata[137]
  PIN h_wdata[138]
    DIRECTION OUTPUT ;
    USE SIGNAL ;
    PORT
      LAYER M5 ;
        RECT  96 0 96.024 0.084 ;
    END
  END h_wdata[138]
  PIN h_wdata[139]
    DIRECTION OUTPUT ;
    USE SIGNAL ;
    PORT
      LAYER M5 ;
        RECT  96.096 0 96.12 0.084 ;
    END
  END h_wdata[139]
  PIN h_wdata[13]
    DIRECTION OUTPUT ;
    USE SIGNAL ;
    PORT
      LAYER M5 ;
        RECT  84 0 84.024 0.084 ;
    END
  END h_wdata[13]
  PIN h_wdata[140]
    DIRECTION OUTPUT ;
    USE SIGNAL ;
    PORT
      LAYER M5 ;
        RECT  96.192 0 96.216 0.084 ;
    END
  END h_wdata[140]
  PIN h_wdata[141]
    DIRECTION OUTPUT ;
    USE SIGNAL ;
    PORT
      LAYER M5 ;
        RECT  96.288 0 96.312 0.084 ;
    END
  END h_wdata[141]
  PIN h_wdata[142]
    DIRECTION OUTPUT ;
    USE SIGNAL ;
    PORT
      LAYER M5 ;
        RECT  96.384 0 96.408 0.084 ;
    END
  END h_wdata[142]
  PIN h_wdata[143]
    DIRECTION OUTPUT ;
    USE SIGNAL ;
    PORT
      LAYER M5 ;
        RECT  96.48 0 96.504 0.084 ;
    END
  END h_wdata[143]
  PIN h_wdata[144]
    DIRECTION OUTPUT ;
    USE SIGNAL ;
    PORT
      LAYER M5 ;
        RECT  96.576 0 96.6 0.084 ;
    END
  END h_wdata[144]
  PIN h_wdata[145]
    DIRECTION OUTPUT ;
    USE SIGNAL ;
    PORT
      LAYER M5 ;
        RECT  96.672 0 96.696 0.084 ;
    END
  END h_wdata[145]
  PIN h_wdata[146]
    DIRECTION OUTPUT ;
    USE SIGNAL ;
    PORT
      LAYER M5 ;
        RECT  96.768 0 96.792 0.084 ;
    END
  END h_wdata[146]
  PIN h_wdata[147]
    DIRECTION OUTPUT ;
    USE SIGNAL ;
    PORT
      LAYER M5 ;
        RECT  96.864 0 96.888 0.084 ;
    END
  END h_wdata[147]
  PIN h_wdata[148]
    DIRECTION OUTPUT ;
    USE SIGNAL ;
    PORT
      LAYER M5 ;
        RECT  96.96 0 96.984 0.084 ;
    END
  END h_wdata[148]
  PIN h_wdata[149]
    DIRECTION OUTPUT ;
    USE SIGNAL ;
    PORT
      LAYER M5 ;
        RECT  97.056 0 97.08 0.084 ;
    END
  END h_wdata[149]
  PIN h_wdata[14]
    DIRECTION OUTPUT ;
    USE SIGNAL ;
    PORT
      LAYER M5 ;
        RECT  84.096 0 84.12 0.084 ;
    END
  END h_wdata[14]
  PIN h_wdata[150]
    DIRECTION OUTPUT ;
    USE SIGNAL ;
    PORT
      LAYER M5 ;
        RECT  97.152 0 97.176 0.084 ;
    END
  END h_wdata[150]
  PIN h_wdata[151]
    DIRECTION OUTPUT ;
    USE SIGNAL ;
    PORT
      LAYER M5 ;
        RECT  97.248 0 97.272 0.084 ;
    END
  END h_wdata[151]
  PIN h_wdata[152]
    DIRECTION OUTPUT ;
    USE SIGNAL ;
    PORT
      LAYER M5 ;
        RECT  97.344 0 97.368 0.084 ;
    END
  END h_wdata[152]
  PIN h_wdata[153]
    DIRECTION OUTPUT ;
    USE SIGNAL ;
    PORT
      LAYER M5 ;
        RECT  97.44 0 97.464 0.084 ;
    END
  END h_wdata[153]
  PIN h_wdata[154]
    DIRECTION OUTPUT ;
    USE SIGNAL ;
    PORT
      LAYER M5 ;
        RECT  97.536 0 97.56 0.084 ;
    END
  END h_wdata[154]
  PIN h_wdata[155]
    DIRECTION OUTPUT ;
    USE SIGNAL ;
    PORT
      LAYER M5 ;
        RECT  97.632 0 97.656 0.084 ;
    END
  END h_wdata[155]
  PIN h_wdata[156]
    DIRECTION OUTPUT ;
    USE SIGNAL ;
    PORT
      LAYER M5 ;
        RECT  97.728 0 97.752 0.084 ;
    END
  END h_wdata[156]
  PIN h_wdata[157]
    DIRECTION OUTPUT ;
    USE SIGNAL ;
    PORT
      LAYER M5 ;
        RECT  97.824 0 97.848 0.084 ;
    END
  END h_wdata[157]
  PIN h_wdata[158]
    DIRECTION OUTPUT ;
    USE SIGNAL ;
    PORT
      LAYER M5 ;
        RECT  97.92 0 97.944 0.084 ;
    END
  END h_wdata[158]
  PIN h_wdata[159]
    DIRECTION OUTPUT ;
    USE SIGNAL ;
    PORT
      LAYER M5 ;
        RECT  98.016 0 98.04 0.084 ;
    END
  END h_wdata[159]
  PIN h_wdata[15]
    DIRECTION OUTPUT ;
    USE SIGNAL ;
    PORT
      LAYER M5 ;
        RECT  84.192 0 84.216 0.084 ;
    END
  END h_wdata[15]
  PIN h_wdata[160]
    DIRECTION OUTPUT ;
    USE SIGNAL ;
    PORT
      LAYER M5 ;
        RECT  98.112 0 98.136 0.084 ;
    END
  END h_wdata[160]
  PIN h_wdata[161]
    DIRECTION OUTPUT ;
    USE SIGNAL ;
    PORT
      LAYER M5 ;
        RECT  98.208 0 98.232 0.084 ;
    END
  END h_wdata[161]
  PIN h_wdata[162]
    DIRECTION OUTPUT ;
    USE SIGNAL ;
    PORT
      LAYER M5 ;
        RECT  98.304 0 98.328 0.084 ;
    END
  END h_wdata[162]
  PIN h_wdata[163]
    DIRECTION OUTPUT ;
    USE SIGNAL ;
    PORT
      LAYER M5 ;
        RECT  98.4 0 98.424 0.084 ;
    END
  END h_wdata[163]
  PIN h_wdata[164]
    DIRECTION OUTPUT ;
    USE SIGNAL ;
    PORT
      LAYER M5 ;
        RECT  98.496 0 98.52 0.084 ;
    END
  END h_wdata[164]
  PIN h_wdata[165]
    DIRECTION OUTPUT ;
    USE SIGNAL ;
    PORT
      LAYER M5 ;
        RECT  98.592 0 98.616 0.084 ;
    END
  END h_wdata[165]
  PIN h_wdata[166]
    DIRECTION OUTPUT ;
    USE SIGNAL ;
    PORT
      LAYER M5 ;
        RECT  98.688 0 98.712 0.084 ;
    END
  END h_wdata[166]
  PIN h_wdata[167]
    DIRECTION OUTPUT ;
    USE SIGNAL ;
    PORT
      LAYER M5 ;
        RECT  98.784 0 98.808 0.084 ;
    END
  END h_wdata[167]
  PIN h_wdata[168]
    DIRECTION OUTPUT ;
    USE SIGNAL ;
    PORT
      LAYER M5 ;
        RECT  98.88 0 98.904 0.084 ;
    END
  END h_wdata[168]
  PIN h_wdata[169]
    DIRECTION OUTPUT ;
    USE SIGNAL ;
    PORT
      LAYER M5 ;
        RECT  98.976 0 99 0.084 ;
    END
  END h_wdata[169]
  PIN h_wdata[16]
    DIRECTION OUTPUT ;
    USE SIGNAL ;
    PORT
      LAYER M5 ;
        RECT  84.288 0 84.312 0.084 ;
    END
  END h_wdata[16]
  PIN h_wdata[170]
    DIRECTION OUTPUT ;
    USE SIGNAL ;
    PORT
      LAYER M5 ;
        RECT  99.072 0 99.096 0.084 ;
    END
  END h_wdata[170]
  PIN h_wdata[171]
    DIRECTION OUTPUT ;
    USE SIGNAL ;
    PORT
      LAYER M5 ;
        RECT  99.168 0 99.192 0.084 ;
    END
  END h_wdata[171]
  PIN h_wdata[172]
    DIRECTION OUTPUT ;
    USE SIGNAL ;
    PORT
      LAYER M5 ;
        RECT  99.264 0 99.288 0.084 ;
    END
  END h_wdata[172]
  PIN h_wdata[173]
    DIRECTION OUTPUT ;
    USE SIGNAL ;
    PORT
      LAYER M5 ;
        RECT  99.36 0 99.384 0.084 ;
    END
  END h_wdata[173]
  PIN h_wdata[174]
    DIRECTION OUTPUT ;
    USE SIGNAL ;
    PORT
      LAYER M5 ;
        RECT  99.456 0 99.48 0.084 ;
    END
  END h_wdata[174]
  PIN h_wdata[175]
    DIRECTION OUTPUT ;
    USE SIGNAL ;
    PORT
      LAYER M5 ;
        RECT  99.552 0 99.576 0.084 ;
    END
  END h_wdata[175]
  PIN h_wdata[176]
    DIRECTION OUTPUT ;
    USE SIGNAL ;
    PORT
      LAYER M5 ;
        RECT  99.648 0 99.672 0.084 ;
    END
  END h_wdata[176]
  PIN h_wdata[177]
    DIRECTION OUTPUT ;
    USE SIGNAL ;
    PORT
      LAYER M5 ;
        RECT  99.744 0 99.768 0.084 ;
    END
  END h_wdata[177]
  PIN h_wdata[178]
    DIRECTION OUTPUT ;
    USE SIGNAL ;
    PORT
      LAYER M5 ;
        RECT  99.84 0 99.864 0.084 ;
    END
  END h_wdata[178]
  PIN h_wdata[179]
    DIRECTION OUTPUT ;
    USE SIGNAL ;
    PORT
      LAYER M5 ;
        RECT  99.936 0 99.96 0.084 ;
    END
  END h_wdata[179]
  PIN h_wdata[17]
    DIRECTION OUTPUT ;
    USE SIGNAL ;
    PORT
      LAYER M5 ;
        RECT  84.384 0 84.408 0.084 ;
    END
  END h_wdata[17]
  PIN h_wdata[180]
    DIRECTION OUTPUT ;
    USE SIGNAL ;
    PORT
      LAYER M5 ;
        RECT  100.032 0 100.056 0.084 ;
    END
  END h_wdata[180]
  PIN h_wdata[181]
    DIRECTION OUTPUT ;
    USE SIGNAL ;
    PORT
      LAYER M5 ;
        RECT  100.128 0 100.152 0.084 ;
    END
  END h_wdata[181]
  PIN h_wdata[182]
    DIRECTION OUTPUT ;
    USE SIGNAL ;
    PORT
      LAYER M5 ;
        RECT  100.224 0 100.248 0.084 ;
    END
  END h_wdata[182]
  PIN h_wdata[183]
    DIRECTION OUTPUT ;
    USE SIGNAL ;
    PORT
      LAYER M5 ;
        RECT  100.32 0 100.344 0.084 ;
    END
  END h_wdata[183]
  PIN h_wdata[184]
    DIRECTION OUTPUT ;
    USE SIGNAL ;
    PORT
      LAYER M5 ;
        RECT  100.416 0 100.44 0.084 ;
    END
  END h_wdata[184]
  PIN h_wdata[185]
    DIRECTION OUTPUT ;
    USE SIGNAL ;
    PORT
      LAYER M5 ;
        RECT  100.512 0 100.536 0.084 ;
    END
  END h_wdata[185]
  PIN h_wdata[186]
    DIRECTION OUTPUT ;
    USE SIGNAL ;
    PORT
      LAYER M5 ;
        RECT  100.608 0 100.632 0.084 ;
    END
  END h_wdata[186]
  PIN h_wdata[187]
    DIRECTION OUTPUT ;
    USE SIGNAL ;
    PORT
      LAYER M5 ;
        RECT  100.704 0 100.728 0.084 ;
    END
  END h_wdata[187]
  PIN h_wdata[188]
    DIRECTION OUTPUT ;
    USE SIGNAL ;
    PORT
      LAYER M5 ;
        RECT  100.8 0 100.824 0.084 ;
    END
  END h_wdata[188]
  PIN h_wdata[189]
    DIRECTION OUTPUT ;
    USE SIGNAL ;
    PORT
      LAYER M5 ;
        RECT  100.896 0 100.92 0.084 ;
    END
  END h_wdata[189]
  PIN h_wdata[18]
    DIRECTION OUTPUT ;
    USE SIGNAL ;
    PORT
      LAYER M5 ;
        RECT  84.48 0 84.504 0.084 ;
    END
  END h_wdata[18]
  PIN h_wdata[190]
    DIRECTION OUTPUT ;
    USE SIGNAL ;
    PORT
      LAYER M5 ;
        RECT  100.992 0 101.016 0.084 ;
    END
  END h_wdata[190]
  PIN h_wdata[191]
    DIRECTION OUTPUT ;
    USE SIGNAL ;
    PORT
      LAYER M5 ;
        RECT  101.088 0 101.112 0.084 ;
    END
  END h_wdata[191]
  PIN h_wdata[192]
    DIRECTION OUTPUT ;
    USE SIGNAL ;
    PORT
      LAYER M5 ;
        RECT  101.184 0 101.208 0.084 ;
    END
  END h_wdata[192]
  PIN h_wdata[193]
    DIRECTION OUTPUT ;
    USE SIGNAL ;
    PORT
      LAYER M5 ;
        RECT  101.28 0 101.304 0.084 ;
    END
  END h_wdata[193]
  PIN h_wdata[194]
    DIRECTION OUTPUT ;
    USE SIGNAL ;
    PORT
      LAYER M5 ;
        RECT  101.376 0 101.4 0.084 ;
    END
  END h_wdata[194]
  PIN h_wdata[195]
    DIRECTION OUTPUT ;
    USE SIGNAL ;
    PORT
      LAYER M5 ;
        RECT  101.472 0 101.496 0.084 ;
    END
  END h_wdata[195]
  PIN h_wdata[196]
    DIRECTION OUTPUT ;
    USE SIGNAL ;
    PORT
      LAYER M5 ;
        RECT  101.568 0 101.592 0.084 ;
    END
  END h_wdata[196]
  PIN h_wdata[197]
    DIRECTION OUTPUT ;
    USE SIGNAL ;
    PORT
      LAYER M5 ;
        RECT  101.664 0 101.688 0.084 ;
    END
  END h_wdata[197]
  PIN h_wdata[198]
    DIRECTION OUTPUT ;
    USE SIGNAL ;
    PORT
      LAYER M5 ;
        RECT  101.76 0 101.784 0.084 ;
    END
  END h_wdata[198]
  PIN h_wdata[199]
    DIRECTION OUTPUT ;
    USE SIGNAL ;
    PORT
      LAYER M5 ;
        RECT  101.856 0 101.88 0.084 ;
    END
  END h_wdata[199]
  PIN h_wdata[19]
    DIRECTION OUTPUT ;
    USE SIGNAL ;
    PORT
      LAYER M5 ;
        RECT  84.576 0 84.6 0.084 ;
    END
  END h_wdata[19]
  PIN h_wdata[1]
    DIRECTION OUTPUT ;
    USE SIGNAL ;
    PORT
      LAYER M5 ;
        RECT  82.848 0 82.872 0.084 ;
    END
  END h_wdata[1]
  PIN h_wdata[200]
    DIRECTION OUTPUT ;
    USE SIGNAL ;
    PORT
      LAYER M5 ;
        RECT  101.952 0 101.976 0.084 ;
    END
  END h_wdata[200]
  PIN h_wdata[201]
    DIRECTION OUTPUT ;
    USE SIGNAL ;
    PORT
      LAYER M5 ;
        RECT  102.048 0 102.072 0.084 ;
    END
  END h_wdata[201]
  PIN h_wdata[202]
    DIRECTION OUTPUT ;
    USE SIGNAL ;
    PORT
      LAYER M5 ;
        RECT  102.144 0 102.168 0.084 ;
    END
  END h_wdata[202]
  PIN h_wdata[203]
    DIRECTION OUTPUT ;
    USE SIGNAL ;
    PORT
      LAYER M5 ;
        RECT  102.24 0 102.264 0.084 ;
    END
  END h_wdata[203]
  PIN h_wdata[204]
    DIRECTION OUTPUT ;
    USE SIGNAL ;
    PORT
      LAYER M5 ;
        RECT  102.336 0 102.36 0.084 ;
    END
  END h_wdata[204]
  PIN h_wdata[205]
    DIRECTION OUTPUT ;
    USE SIGNAL ;
    PORT
      LAYER M5 ;
        RECT  102.432 0 102.456 0.084 ;
    END
  END h_wdata[205]
  PIN h_wdata[206]
    DIRECTION OUTPUT ;
    USE SIGNAL ;
    PORT
      LAYER M5 ;
        RECT  102.528 0 102.552 0.084 ;
    END
  END h_wdata[206]
  PIN h_wdata[207]
    DIRECTION OUTPUT ;
    USE SIGNAL ;
    PORT
      LAYER M5 ;
        RECT  102.624 0 102.648 0.084 ;
    END
  END h_wdata[207]
  PIN h_wdata[208]
    DIRECTION OUTPUT ;
    USE SIGNAL ;
    PORT
      LAYER M5 ;
        RECT  102.72 0 102.744 0.084 ;
    END
  END h_wdata[208]
  PIN h_wdata[209]
    DIRECTION OUTPUT ;
    USE SIGNAL ;
    PORT
      LAYER M5 ;
        RECT  102.816 0 102.84 0.084 ;
    END
  END h_wdata[209]
  PIN h_wdata[20]
    DIRECTION OUTPUT ;
    USE SIGNAL ;
    PORT
      LAYER M5 ;
        RECT  84.672 0 84.696 0.084 ;
    END
  END h_wdata[20]
  PIN h_wdata[210]
    DIRECTION OUTPUT ;
    USE SIGNAL ;
    PORT
      LAYER M5 ;
        RECT  102.912 0 102.936 0.084 ;
    END
  END h_wdata[210]
  PIN h_wdata[211]
    DIRECTION OUTPUT ;
    USE SIGNAL ;
    PORT
      LAYER M5 ;
        RECT  103.008 0 103.032 0.084 ;
    END
  END h_wdata[211]
  PIN h_wdata[212]
    DIRECTION OUTPUT ;
    USE SIGNAL ;
    PORT
      LAYER M5 ;
        RECT  103.104 0 103.128 0.084 ;
    END
  END h_wdata[212]
  PIN h_wdata[213]
    DIRECTION OUTPUT ;
    USE SIGNAL ;
    PORT
      LAYER M5 ;
        RECT  103.2 0 103.224 0.084 ;
    END
  END h_wdata[213]
  PIN h_wdata[214]
    DIRECTION OUTPUT ;
    USE SIGNAL ;
    PORT
      LAYER M5 ;
        RECT  103.296 0 103.32 0.084 ;
    END
  END h_wdata[214]
  PIN h_wdata[215]
    DIRECTION OUTPUT ;
    USE SIGNAL ;
    PORT
      LAYER M5 ;
        RECT  103.392 0 103.416 0.084 ;
    END
  END h_wdata[215]
  PIN h_wdata[216]
    DIRECTION OUTPUT ;
    USE SIGNAL ;
    PORT
      LAYER M5 ;
        RECT  103.488 0 103.512 0.084 ;
    END
  END h_wdata[216]
  PIN h_wdata[217]
    DIRECTION OUTPUT ;
    USE SIGNAL ;
    PORT
      LAYER M5 ;
        RECT  103.584 0 103.608 0.084 ;
    END
  END h_wdata[217]
  PIN h_wdata[218]
    DIRECTION OUTPUT ;
    USE SIGNAL ;
    PORT
      LAYER M5 ;
        RECT  103.68 0 103.704 0.084 ;
    END
  END h_wdata[218]
  PIN h_wdata[219]
    DIRECTION OUTPUT ;
    USE SIGNAL ;
    PORT
      LAYER M5 ;
        RECT  103.776 0 103.8 0.084 ;
    END
  END h_wdata[219]
  PIN h_wdata[21]
    DIRECTION OUTPUT ;
    USE SIGNAL ;
    PORT
      LAYER M5 ;
        RECT  84.768 0 84.792 0.084 ;
    END
  END h_wdata[21]
  PIN h_wdata[220]
    DIRECTION OUTPUT ;
    USE SIGNAL ;
    PORT
      LAYER M5 ;
        RECT  103.872 0 103.896 0.084 ;
    END
  END h_wdata[220]
  PIN h_wdata[221]
    DIRECTION OUTPUT ;
    USE SIGNAL ;
    PORT
      LAYER M5 ;
        RECT  103.968 0 103.992 0.084 ;
    END
  END h_wdata[221]
  PIN h_wdata[222]
    DIRECTION OUTPUT ;
    USE SIGNAL ;
    PORT
      LAYER M5 ;
        RECT  104.064 0 104.088 0.084 ;
    END
  END h_wdata[222]
  PIN h_wdata[223]
    DIRECTION OUTPUT ;
    USE SIGNAL ;
    PORT
      LAYER M5 ;
        RECT  104.16 0 104.184 0.084 ;
    END
  END h_wdata[223]
  PIN h_wdata[224]
    DIRECTION OUTPUT ;
    USE SIGNAL ;
    PORT
      LAYER M5 ;
        RECT  104.256 0 104.28 0.084 ;
    END
  END h_wdata[224]
  PIN h_wdata[225]
    DIRECTION OUTPUT ;
    USE SIGNAL ;
    PORT
      LAYER M5 ;
        RECT  104.352 0 104.376 0.084 ;
    END
  END h_wdata[225]
  PIN h_wdata[226]
    DIRECTION OUTPUT ;
    USE SIGNAL ;
    PORT
      LAYER M5 ;
        RECT  104.448 0 104.472 0.084 ;
    END
  END h_wdata[226]
  PIN h_wdata[227]
    DIRECTION OUTPUT ;
    USE SIGNAL ;
    PORT
      LAYER M5 ;
        RECT  104.544 0 104.568 0.084 ;
    END
  END h_wdata[227]
  PIN h_wdata[228]
    DIRECTION OUTPUT ;
    USE SIGNAL ;
    PORT
      LAYER M5 ;
        RECT  104.64 0 104.664 0.084 ;
    END
  END h_wdata[228]
  PIN h_wdata[229]
    DIRECTION OUTPUT ;
    USE SIGNAL ;
    PORT
      LAYER M5 ;
        RECT  104.736 0 104.76 0.084 ;
    END
  END h_wdata[229]
  PIN h_wdata[22]
    DIRECTION OUTPUT ;
    USE SIGNAL ;
    PORT
      LAYER M5 ;
        RECT  84.864 0 84.888 0.084 ;
    END
  END h_wdata[22]
  PIN h_wdata[230]
    DIRECTION OUTPUT ;
    USE SIGNAL ;
    PORT
      LAYER M5 ;
        RECT  104.832 0 104.856 0.084 ;
    END
  END h_wdata[230]
  PIN h_wdata[231]
    DIRECTION OUTPUT ;
    USE SIGNAL ;
    PORT
      LAYER M5 ;
        RECT  104.928 0 104.952 0.084 ;
    END
  END h_wdata[231]
  PIN h_wdata[232]
    DIRECTION OUTPUT ;
    USE SIGNAL ;
    PORT
      LAYER M5 ;
        RECT  105.024 0 105.048 0.084 ;
    END
  END h_wdata[232]
  PIN h_wdata[233]
    DIRECTION OUTPUT ;
    USE SIGNAL ;
    PORT
      LAYER M5 ;
        RECT  105.12 0 105.144 0.084 ;
    END
  END h_wdata[233]
  PIN h_wdata[234]
    DIRECTION OUTPUT ;
    USE SIGNAL ;
    PORT
      LAYER M5 ;
        RECT  105.216 0 105.24 0.084 ;
    END
  END h_wdata[234]
  PIN h_wdata[235]
    DIRECTION OUTPUT ;
    USE SIGNAL ;
    PORT
      LAYER M5 ;
        RECT  105.312 0 105.336 0.084 ;
    END
  END h_wdata[235]
  PIN h_wdata[236]
    DIRECTION OUTPUT ;
    USE SIGNAL ;
    PORT
      LAYER M5 ;
        RECT  105.408 0 105.432 0.084 ;
    END
  END h_wdata[236]
  PIN h_wdata[237]
    DIRECTION OUTPUT ;
    USE SIGNAL ;
    PORT
      LAYER M5 ;
        RECT  105.504 0 105.528 0.084 ;
    END
  END h_wdata[237]
  PIN h_wdata[238]
    DIRECTION OUTPUT ;
    USE SIGNAL ;
    PORT
      LAYER M5 ;
        RECT  105.6 0 105.624 0.084 ;
    END
  END h_wdata[238]
  PIN h_wdata[239]
    DIRECTION OUTPUT ;
    USE SIGNAL ;
    PORT
      LAYER M5 ;
        RECT  105.696 0 105.72 0.084 ;
    END
  END h_wdata[239]
  PIN h_wdata[23]
    DIRECTION OUTPUT ;
    USE SIGNAL ;
    PORT
      LAYER M5 ;
        RECT  84.96 0 84.984 0.084 ;
    END
  END h_wdata[23]
  PIN h_wdata[240]
    DIRECTION OUTPUT ;
    USE SIGNAL ;
    PORT
      LAYER M5 ;
        RECT  105.792 0 105.816 0.084 ;
    END
  END h_wdata[240]
  PIN h_wdata[241]
    DIRECTION OUTPUT ;
    USE SIGNAL ;
    PORT
      LAYER M5 ;
        RECT  105.888 0 105.912 0.084 ;
    END
  END h_wdata[241]
  PIN h_wdata[242]
    DIRECTION OUTPUT ;
    USE SIGNAL ;
    PORT
      LAYER M5 ;
        RECT  105.984 0 106.008 0.084 ;
    END
  END h_wdata[242]
  PIN h_wdata[243]
    DIRECTION OUTPUT ;
    USE SIGNAL ;
    PORT
      LAYER M5 ;
        RECT  106.08 0 106.104 0.084 ;
    END
  END h_wdata[243]
  PIN h_wdata[244]
    DIRECTION OUTPUT ;
    USE SIGNAL ;
    PORT
      LAYER M5 ;
        RECT  106.176 0 106.2 0.084 ;
    END
  END h_wdata[244]
  PIN h_wdata[245]
    DIRECTION OUTPUT ;
    USE SIGNAL ;
    PORT
      LAYER M5 ;
        RECT  106.272 0 106.296 0.084 ;
    END
  END h_wdata[245]
  PIN h_wdata[246]
    DIRECTION OUTPUT ;
    USE SIGNAL ;
    PORT
      LAYER M5 ;
        RECT  106.368 0 106.392 0.084 ;
    END
  END h_wdata[246]
  PIN h_wdata[247]
    DIRECTION OUTPUT ;
    USE SIGNAL ;
    PORT
      LAYER M5 ;
        RECT  106.464 0 106.488 0.084 ;
    END
  END h_wdata[247]
  PIN h_wdata[248]
    DIRECTION OUTPUT ;
    USE SIGNAL ;
    PORT
      LAYER M5 ;
        RECT  106.56 0 106.584 0.084 ;
    END
  END h_wdata[248]
  PIN h_wdata[249]
    DIRECTION OUTPUT ;
    USE SIGNAL ;
    PORT
      LAYER M5 ;
        RECT  106.656 0 106.68 0.084 ;
    END
  END h_wdata[249]
  PIN h_wdata[24]
    DIRECTION OUTPUT ;
    USE SIGNAL ;
    PORT
      LAYER M5 ;
        RECT  85.056 0 85.08 0.084 ;
    END
  END h_wdata[24]
  PIN h_wdata[250]
    DIRECTION OUTPUT ;
    USE SIGNAL ;
    PORT
      LAYER M5 ;
        RECT  106.752 0 106.776 0.084 ;
    END
  END h_wdata[250]
  PIN h_wdata[251]
    DIRECTION OUTPUT ;
    USE SIGNAL ;
    PORT
      LAYER M5 ;
        RECT  106.848 0 106.872 0.084 ;
    END
  END h_wdata[251]
  PIN h_wdata[252]
    DIRECTION OUTPUT ;
    USE SIGNAL ;
    PORT
      LAYER M5 ;
        RECT  106.944 0 106.968 0.084 ;
    END
  END h_wdata[252]
  PIN h_wdata[253]
    DIRECTION OUTPUT ;
    USE SIGNAL ;
    PORT
      LAYER M5 ;
        RECT  107.04 0 107.064 0.084 ;
    END
  END h_wdata[253]
  PIN h_wdata[254]
    DIRECTION OUTPUT ;
    USE SIGNAL ;
    PORT
      LAYER M5 ;
        RECT  107.136 0 107.16 0.084 ;
    END
  END h_wdata[254]
  PIN h_wdata[255]
    DIRECTION OUTPUT ;
    USE SIGNAL ;
    PORT
      LAYER M5 ;
        RECT  107.232 0 107.256 0.084 ;
    END
  END h_wdata[255]
  PIN h_wdata[25]
    DIRECTION OUTPUT ;
    USE SIGNAL ;
    PORT
      LAYER M5 ;
        RECT  85.152 0 85.176 0.084 ;
    END
  END h_wdata[25]
  PIN h_wdata[26]
    DIRECTION OUTPUT ;
    USE SIGNAL ;
    PORT
      LAYER M5 ;
        RECT  85.248 0 85.272 0.084 ;
    END
  END h_wdata[26]
  PIN h_wdata[27]
    DIRECTION OUTPUT ;
    USE SIGNAL ;
    PORT
      LAYER M5 ;
        RECT  85.344 0 85.368 0.084 ;
    END
  END h_wdata[27]
  PIN h_wdata[28]
    DIRECTION OUTPUT ;
    USE SIGNAL ;
    PORT
      LAYER M5 ;
        RECT  85.44 0 85.464 0.084 ;
    END
  END h_wdata[28]
  PIN h_wdata[29]
    DIRECTION OUTPUT ;
    USE SIGNAL ;
    PORT
      LAYER M5 ;
        RECT  85.536 0 85.56 0.084 ;
    END
  END h_wdata[29]
  PIN h_wdata[2]
    DIRECTION OUTPUT ;
    USE SIGNAL ;
    PORT
      LAYER M5 ;
        RECT  82.944 0 82.968 0.084 ;
    END
  END h_wdata[2]
  PIN h_wdata[30]
    DIRECTION OUTPUT ;
    USE SIGNAL ;
    PORT
      LAYER M5 ;
        RECT  85.632 0 85.656 0.084 ;
    END
  END h_wdata[30]
  PIN h_wdata[31]
    DIRECTION OUTPUT ;
    USE SIGNAL ;
    PORT
      LAYER M5 ;
        RECT  85.728 0 85.752 0.084 ;
    END
  END h_wdata[31]
  PIN h_wdata[32]
    DIRECTION OUTPUT ;
    USE SIGNAL ;
    PORT
      LAYER M5 ;
        RECT  85.824 0 85.848 0.084 ;
    END
  END h_wdata[32]
  PIN h_wdata[33]
    DIRECTION OUTPUT ;
    USE SIGNAL ;
    PORT
      LAYER M5 ;
        RECT  85.92 0 85.944 0.084 ;
    END
  END h_wdata[33]
  PIN h_wdata[34]
    DIRECTION OUTPUT ;
    USE SIGNAL ;
    PORT
      LAYER M5 ;
        RECT  86.016 0 86.04 0.084 ;
    END
  END h_wdata[34]
  PIN h_wdata[35]
    DIRECTION OUTPUT ;
    USE SIGNAL ;
    PORT
      LAYER M5 ;
        RECT  86.112 0 86.136 0.084 ;
    END
  END h_wdata[35]
  PIN h_wdata[36]
    DIRECTION OUTPUT ;
    USE SIGNAL ;
    PORT
      LAYER M5 ;
        RECT  86.208 0 86.232 0.084 ;
    END
  END h_wdata[36]
  PIN h_wdata[37]
    DIRECTION OUTPUT ;
    USE SIGNAL ;
    PORT
      LAYER M5 ;
        RECT  86.304 0 86.328 0.084 ;
    END
  END h_wdata[37]
  PIN h_wdata[38]
    DIRECTION OUTPUT ;
    USE SIGNAL ;
    PORT
      LAYER M5 ;
        RECT  86.4 0 86.424 0.084 ;
    END
  END h_wdata[38]
  PIN h_wdata[39]
    DIRECTION OUTPUT ;
    USE SIGNAL ;
    PORT
      LAYER M5 ;
        RECT  86.496 0 86.52 0.084 ;
    END
  END h_wdata[39]
  PIN h_wdata[3]
    DIRECTION OUTPUT ;
    USE SIGNAL ;
    PORT
      LAYER M5 ;
        RECT  83.04 0 83.064 0.084 ;
    END
  END h_wdata[3]
  PIN h_wdata[40]
    DIRECTION OUTPUT ;
    USE SIGNAL ;
    PORT
      LAYER M5 ;
        RECT  86.592 0 86.616 0.084 ;
    END
  END h_wdata[40]
  PIN h_wdata[41]
    DIRECTION OUTPUT ;
    USE SIGNAL ;
    PORT
      LAYER M5 ;
        RECT  86.688 0 86.712 0.084 ;
    END
  END h_wdata[41]
  PIN h_wdata[42]
    DIRECTION OUTPUT ;
    USE SIGNAL ;
    PORT
      LAYER M5 ;
        RECT  86.784 0 86.808 0.084 ;
    END
  END h_wdata[42]
  PIN h_wdata[43]
    DIRECTION OUTPUT ;
    USE SIGNAL ;
    PORT
      LAYER M5 ;
        RECT  86.88 0 86.904 0.084 ;
    END
  END h_wdata[43]
  PIN h_wdata[44]
    DIRECTION OUTPUT ;
    USE SIGNAL ;
    PORT
      LAYER M5 ;
        RECT  86.976 0 87 0.084 ;
    END
  END h_wdata[44]
  PIN h_wdata[45]
    DIRECTION OUTPUT ;
    USE SIGNAL ;
    PORT
      LAYER M5 ;
        RECT  87.072 0 87.096 0.084 ;
    END
  END h_wdata[45]
  PIN h_wdata[46]
    DIRECTION OUTPUT ;
    USE SIGNAL ;
    PORT
      LAYER M5 ;
        RECT  87.168 0 87.192 0.084 ;
    END
  END h_wdata[46]
  PIN h_wdata[47]
    DIRECTION OUTPUT ;
    USE SIGNAL ;
    PORT
      LAYER M5 ;
        RECT  87.264 0 87.288 0.084 ;
    END
  END h_wdata[47]
  PIN h_wdata[48]
    DIRECTION OUTPUT ;
    USE SIGNAL ;
    PORT
      LAYER M5 ;
        RECT  87.36 0 87.384 0.084 ;
    END
  END h_wdata[48]
  PIN h_wdata[49]
    DIRECTION OUTPUT ;
    USE SIGNAL ;
    PORT
      LAYER M5 ;
        RECT  87.456 0 87.48 0.084 ;
    END
  END h_wdata[49]
  PIN h_wdata[4]
    DIRECTION OUTPUT ;
    USE SIGNAL ;
    PORT
      LAYER M5 ;
        RECT  83.136 0 83.16 0.084 ;
    END
  END h_wdata[4]
  PIN h_wdata[50]
    DIRECTION OUTPUT ;
    USE SIGNAL ;
    PORT
      LAYER M5 ;
        RECT  87.552 0 87.576 0.084 ;
    END
  END h_wdata[50]
  PIN h_wdata[51]
    DIRECTION OUTPUT ;
    USE SIGNAL ;
    PORT
      LAYER M5 ;
        RECT  87.648 0 87.672 0.084 ;
    END
  END h_wdata[51]
  PIN h_wdata[52]
    DIRECTION OUTPUT ;
    USE SIGNAL ;
    PORT
      LAYER M5 ;
        RECT  87.744 0 87.768 0.084 ;
    END
  END h_wdata[52]
  PIN h_wdata[53]
    DIRECTION OUTPUT ;
    USE SIGNAL ;
    PORT
      LAYER M5 ;
        RECT  87.84 0 87.864 0.084 ;
    END
  END h_wdata[53]
  PIN h_wdata[54]
    DIRECTION OUTPUT ;
    USE SIGNAL ;
    PORT
      LAYER M5 ;
        RECT  87.936 0 87.96 0.084 ;
    END
  END h_wdata[54]
  PIN h_wdata[55]
    DIRECTION OUTPUT ;
    USE SIGNAL ;
    PORT
      LAYER M5 ;
        RECT  88.032 0 88.056 0.084 ;
    END
  END h_wdata[55]
  PIN h_wdata[56]
    DIRECTION OUTPUT ;
    USE SIGNAL ;
    PORT
      LAYER M5 ;
        RECT  88.128 0 88.152 0.084 ;
    END
  END h_wdata[56]
  PIN h_wdata[57]
    DIRECTION OUTPUT ;
    USE SIGNAL ;
    PORT
      LAYER M5 ;
        RECT  88.224 0 88.248 0.084 ;
    END
  END h_wdata[57]
  PIN h_wdata[58]
    DIRECTION OUTPUT ;
    USE SIGNAL ;
    PORT
      LAYER M5 ;
        RECT  88.32 0 88.344 0.084 ;
    END
  END h_wdata[58]
  PIN h_wdata[59]
    DIRECTION OUTPUT ;
    USE SIGNAL ;
    PORT
      LAYER M5 ;
        RECT  88.416 0 88.44 0.084 ;
    END
  END h_wdata[59]
  PIN h_wdata[5]
    DIRECTION OUTPUT ;
    USE SIGNAL ;
    PORT
      LAYER M5 ;
        RECT  83.232 0 83.256 0.084 ;
    END
  END h_wdata[5]
  PIN h_wdata[60]
    DIRECTION OUTPUT ;
    USE SIGNAL ;
    PORT
      LAYER M5 ;
        RECT  88.512 0 88.536 0.084 ;
    END
  END h_wdata[60]
  PIN h_wdata[61]
    DIRECTION OUTPUT ;
    USE SIGNAL ;
    PORT
      LAYER M5 ;
        RECT  88.608 0 88.632 0.084 ;
    END
  END h_wdata[61]
  PIN h_wdata[62]
    DIRECTION OUTPUT ;
    USE SIGNAL ;
    PORT
      LAYER M5 ;
        RECT  88.704 0 88.728 0.084 ;
    END
  END h_wdata[62]
  PIN h_wdata[63]
    DIRECTION OUTPUT ;
    USE SIGNAL ;
    PORT
      LAYER M5 ;
        RECT  88.8 0 88.824 0.084 ;
    END
  END h_wdata[63]
  PIN h_wdata[64]
    DIRECTION OUTPUT ;
    USE SIGNAL ;
    PORT
      LAYER M5 ;
        RECT  88.896 0 88.92 0.084 ;
    END
  END h_wdata[64]
  PIN h_wdata[65]
    DIRECTION OUTPUT ;
    USE SIGNAL ;
    PORT
      LAYER M5 ;
        RECT  88.992 0 89.016 0.084 ;
    END
  END h_wdata[65]
  PIN h_wdata[66]
    DIRECTION OUTPUT ;
    USE SIGNAL ;
    PORT
      LAYER M5 ;
        RECT  89.088 0 89.112 0.084 ;
    END
  END h_wdata[66]
  PIN h_wdata[67]
    DIRECTION OUTPUT ;
    USE SIGNAL ;
    PORT
      LAYER M5 ;
        RECT  89.184 0 89.208 0.084 ;
    END
  END h_wdata[67]
  PIN h_wdata[68]
    DIRECTION OUTPUT ;
    USE SIGNAL ;
    PORT
      LAYER M5 ;
        RECT  89.28 0 89.304 0.084 ;
    END
  END h_wdata[68]
  PIN h_wdata[69]
    DIRECTION OUTPUT ;
    USE SIGNAL ;
    PORT
      LAYER M5 ;
        RECT  89.376 0 89.4 0.084 ;
    END
  END h_wdata[69]
  PIN h_wdata[6]
    DIRECTION OUTPUT ;
    USE SIGNAL ;
    PORT
      LAYER M5 ;
        RECT  83.328 0 83.352 0.084 ;
    END
  END h_wdata[6]
  PIN h_wdata[70]
    DIRECTION OUTPUT ;
    USE SIGNAL ;
    PORT
      LAYER M5 ;
        RECT  89.472 0 89.496 0.084 ;
    END
  END h_wdata[70]
  PIN h_wdata[71]
    DIRECTION OUTPUT ;
    USE SIGNAL ;
    PORT
      LAYER M5 ;
        RECT  89.568 0 89.592 0.084 ;
    END
  END h_wdata[71]
  PIN h_wdata[72]
    DIRECTION OUTPUT ;
    USE SIGNAL ;
    PORT
      LAYER M5 ;
        RECT  89.664 0 89.688 0.084 ;
    END
  END h_wdata[72]
  PIN h_wdata[73]
    DIRECTION OUTPUT ;
    USE SIGNAL ;
    PORT
      LAYER M5 ;
        RECT  89.76 0 89.784 0.084 ;
    END
  END h_wdata[73]
  PIN h_wdata[74]
    DIRECTION OUTPUT ;
    USE SIGNAL ;
    PORT
      LAYER M5 ;
        RECT  89.856 0 89.88 0.084 ;
    END
  END h_wdata[74]
  PIN h_wdata[75]
    DIRECTION OUTPUT ;
    USE SIGNAL ;
    PORT
      LAYER M5 ;
        RECT  89.952 0 89.976 0.084 ;
    END
  END h_wdata[75]
  PIN h_wdata[76]
    DIRECTION OUTPUT ;
    USE SIGNAL ;
    PORT
      LAYER M5 ;
        RECT  90.048 0 90.072 0.084 ;
    END
  END h_wdata[76]
  PIN h_wdata[77]
    DIRECTION OUTPUT ;
    USE SIGNAL ;
    PORT
      LAYER M5 ;
        RECT  90.144 0 90.168 0.084 ;
    END
  END h_wdata[77]
  PIN h_wdata[78]
    DIRECTION OUTPUT ;
    USE SIGNAL ;
    PORT
      LAYER M5 ;
        RECT  90.24 0 90.264 0.084 ;
    END
  END h_wdata[78]
  PIN h_wdata[79]
    DIRECTION OUTPUT ;
    USE SIGNAL ;
    PORT
      LAYER M5 ;
        RECT  90.336 0 90.36 0.084 ;
    END
  END h_wdata[79]
  PIN h_wdata[7]
    DIRECTION OUTPUT ;
    USE SIGNAL ;
    PORT
      LAYER M5 ;
        RECT  83.424 0 83.448 0.084 ;
    END
  END h_wdata[7]
  PIN h_wdata[80]
    DIRECTION OUTPUT ;
    USE SIGNAL ;
    PORT
      LAYER M5 ;
        RECT  90.432 0 90.456 0.084 ;
    END
  END h_wdata[80]
  PIN h_wdata[81]
    DIRECTION OUTPUT ;
    USE SIGNAL ;
    PORT
      LAYER M5 ;
        RECT  90.528 0 90.552 0.084 ;
    END
  END h_wdata[81]
  PIN h_wdata[82]
    DIRECTION OUTPUT ;
    USE SIGNAL ;
    PORT
      LAYER M5 ;
        RECT  90.624 0 90.648 0.084 ;
    END
  END h_wdata[82]
  PIN h_wdata[83]
    DIRECTION OUTPUT ;
    USE SIGNAL ;
    PORT
      LAYER M5 ;
        RECT  90.72 0 90.744 0.084 ;
    END
  END h_wdata[83]
  PIN h_wdata[84]
    DIRECTION OUTPUT ;
    USE SIGNAL ;
    PORT
      LAYER M5 ;
        RECT  90.816 0 90.84 0.084 ;
    END
  END h_wdata[84]
  PIN h_wdata[85]
    DIRECTION OUTPUT ;
    USE SIGNAL ;
    PORT
      LAYER M5 ;
        RECT  90.912 0 90.936 0.084 ;
    END
  END h_wdata[85]
  PIN h_wdata[86]
    DIRECTION OUTPUT ;
    USE SIGNAL ;
    PORT
      LAYER M5 ;
        RECT  91.008 0 91.032 0.084 ;
    END
  END h_wdata[86]
  PIN h_wdata[87]
    DIRECTION OUTPUT ;
    USE SIGNAL ;
    PORT
      LAYER M5 ;
        RECT  91.104 0 91.128 0.084 ;
    END
  END h_wdata[87]
  PIN h_wdata[88]
    DIRECTION OUTPUT ;
    USE SIGNAL ;
    PORT
      LAYER M5 ;
        RECT  91.2 0 91.224 0.084 ;
    END
  END h_wdata[88]
  PIN h_wdata[89]
    DIRECTION OUTPUT ;
    USE SIGNAL ;
    PORT
      LAYER M5 ;
        RECT  91.296 0 91.32 0.084 ;
    END
  END h_wdata[89]
  PIN h_wdata[8]
    DIRECTION OUTPUT ;
    USE SIGNAL ;
    PORT
      LAYER M5 ;
        RECT  83.52 0 83.544 0.084 ;
    END
  END h_wdata[8]
  PIN h_wdata[90]
    DIRECTION OUTPUT ;
    USE SIGNAL ;
    PORT
      LAYER M5 ;
        RECT  91.392 0 91.416 0.084 ;
    END
  END h_wdata[90]
  PIN h_wdata[91]
    DIRECTION OUTPUT ;
    USE SIGNAL ;
    PORT
      LAYER M5 ;
        RECT  91.488 0 91.512 0.084 ;
    END
  END h_wdata[91]
  PIN h_wdata[92]
    DIRECTION OUTPUT ;
    USE SIGNAL ;
    PORT
      LAYER M5 ;
        RECT  91.584 0 91.608 0.084 ;
    END
  END h_wdata[92]
  PIN h_wdata[93]
    DIRECTION OUTPUT ;
    USE SIGNAL ;
    PORT
      LAYER M5 ;
        RECT  91.68 0 91.704 0.084 ;
    END
  END h_wdata[93]
  PIN h_wdata[94]
    DIRECTION OUTPUT ;
    USE SIGNAL ;
    PORT
      LAYER M5 ;
        RECT  91.776 0 91.8 0.084 ;
    END
  END h_wdata[94]
  PIN h_wdata[95]
    DIRECTION OUTPUT ;
    USE SIGNAL ;
    PORT
      LAYER M5 ;
        RECT  91.872 0 91.896 0.084 ;
    END
  END h_wdata[95]
  PIN h_wdata[96]
    DIRECTION OUTPUT ;
    USE SIGNAL ;
    PORT
      LAYER M5 ;
        RECT  91.968 0 91.992 0.084 ;
    END
  END h_wdata[96]
  PIN h_wdata[97]
    DIRECTION OUTPUT ;
    USE SIGNAL ;
    PORT
      LAYER M5 ;
        RECT  92.064 0 92.088 0.084 ;
    END
  END h_wdata[97]
  PIN h_wdata[98]
    DIRECTION OUTPUT ;
    USE SIGNAL ;
    PORT
      LAYER M5 ;
        RECT  92.16 0 92.184 0.084 ;
    END
  END h_wdata[98]
  PIN h_wdata[99]
    DIRECTION OUTPUT ;
    USE SIGNAL ;
    PORT
      LAYER M5 ;
        RECT  92.256 0 92.28 0.084 ;
    END
  END h_wdata[99]
  PIN h_wdata[9]
    DIRECTION OUTPUT ;
    USE SIGNAL ;
    PORT
      LAYER M5 ;
        RECT  83.616 0 83.64 0.084 ;
    END
  END h_wdata[9]
  PIN h_we
    DIRECTION OUTPUT ;
    USE SIGNAL ;
    PORT
      LAYER M5 ;
        RECT  107.328 0 107.352 0.084 ;
    END
  END h_we
  PIN h_wr_done
    DIRECTION INPUT ;
    USE SIGNAL ;
    PORT
      LAYER M5 ;
        RECT  107.424 0 107.448 0.084 ;
    END
  END h_wr_done
  PIN h_wstrb[0]
    DIRECTION OUTPUT ;
    USE SIGNAL ;
    PORT
      LAYER M5 ;
        RECT  107.52 0 107.544 0.084 ;
    END
  END h_wstrb[0]
  PIN h_wstrb[10]
    DIRECTION OUTPUT ;
    USE SIGNAL ;
    PORT
      LAYER M5 ;
        RECT  108.48 0 108.504 0.084 ;
    END
  END h_wstrb[10]
  PIN h_wstrb[11]
    DIRECTION OUTPUT ;
    USE SIGNAL ;
    PORT
      LAYER M5 ;
        RECT  108.576 0 108.6 0.084 ;
    END
  END h_wstrb[11]
  PIN h_wstrb[12]
    DIRECTION OUTPUT ;
    USE SIGNAL ;
    PORT
      LAYER M5 ;
        RECT  108.672 0 108.696 0.084 ;
    END
  END h_wstrb[12]
  PIN h_wstrb[13]
    DIRECTION OUTPUT ;
    USE SIGNAL ;
    PORT
      LAYER M5 ;
        RECT  108.768 0 108.792 0.084 ;
    END
  END h_wstrb[13]
  PIN h_wstrb[14]
    DIRECTION OUTPUT ;
    USE SIGNAL ;
    PORT
      LAYER M5 ;
        RECT  108.864 0 108.888 0.084 ;
    END
  END h_wstrb[14]
  PIN h_wstrb[15]
    DIRECTION OUTPUT ;
    USE SIGNAL ;
    PORT
      LAYER M5 ;
        RECT  108.96 0 108.984 0.084 ;
    END
  END h_wstrb[15]
  PIN h_wstrb[16]
    DIRECTION OUTPUT ;
    USE SIGNAL ;
    PORT
      LAYER M5 ;
        RECT  109.056 0 109.08 0.084 ;
    END
  END h_wstrb[16]
  PIN h_wstrb[17]
    DIRECTION OUTPUT ;
    USE SIGNAL ;
    PORT
      LAYER M5 ;
        RECT  109.152 0 109.176 0.084 ;
    END
  END h_wstrb[17]
  PIN h_wstrb[18]
    DIRECTION OUTPUT ;
    USE SIGNAL ;
    PORT
      LAYER M5 ;
        RECT  109.248 0 109.272 0.084 ;
    END
  END h_wstrb[18]
  PIN h_wstrb[19]
    DIRECTION OUTPUT ;
    USE SIGNAL ;
    PORT
      LAYER M5 ;
        RECT  109.344 0 109.368 0.084 ;
    END
  END h_wstrb[19]
  PIN h_wstrb[1]
    DIRECTION OUTPUT ;
    USE SIGNAL ;
    PORT
      LAYER M5 ;
        RECT  107.616 0 107.64 0.084 ;
    END
  END h_wstrb[1]
  PIN h_wstrb[20]
    DIRECTION OUTPUT ;
    USE SIGNAL ;
    PORT
      LAYER M5 ;
        RECT  109.44 0 109.464 0.084 ;
    END
  END h_wstrb[20]
  PIN h_wstrb[21]
    DIRECTION OUTPUT ;
    USE SIGNAL ;
    PORT
      LAYER M5 ;
        RECT  109.536 0 109.56 0.084 ;
    END
  END h_wstrb[21]
  PIN h_wstrb[22]
    DIRECTION OUTPUT ;
    USE SIGNAL ;
    PORT
      LAYER M5 ;
        RECT  109.632 0 109.656 0.084 ;
    END
  END h_wstrb[22]
  PIN h_wstrb[23]
    DIRECTION OUTPUT ;
    USE SIGNAL ;
    PORT
      LAYER M5 ;
        RECT  109.728 0 109.752 0.084 ;
    END
  END h_wstrb[23]
  PIN h_wstrb[24]
    DIRECTION OUTPUT ;
    USE SIGNAL ;
    PORT
      LAYER M5 ;
        RECT  109.824 0 109.848 0.084 ;
    END
  END h_wstrb[24]
  PIN h_wstrb[25]
    DIRECTION OUTPUT ;
    USE SIGNAL ;
    PORT
      LAYER M5 ;
        RECT  109.92 0 109.944 0.084 ;
    END
  END h_wstrb[25]
  PIN h_wstrb[26]
    DIRECTION OUTPUT ;
    USE SIGNAL ;
    PORT
      LAYER M5 ;
        RECT  110.016 0 110.04 0.084 ;
    END
  END h_wstrb[26]
  PIN h_wstrb[27]
    DIRECTION OUTPUT ;
    USE SIGNAL ;
    PORT
      LAYER M5 ;
        RECT  110.112 0 110.136 0.084 ;
    END
  END h_wstrb[27]
  PIN h_wstrb[28]
    DIRECTION OUTPUT ;
    USE SIGNAL ;
    PORT
      LAYER M5 ;
        RECT  110.208 0 110.232 0.084 ;
    END
  END h_wstrb[28]
  PIN h_wstrb[29]
    DIRECTION OUTPUT ;
    USE SIGNAL ;
    PORT
      LAYER M5 ;
        RECT  110.304 0 110.328 0.084 ;
    END
  END h_wstrb[29]
  PIN h_wstrb[2]
    DIRECTION OUTPUT ;
    USE SIGNAL ;
    PORT
      LAYER M5 ;
        RECT  107.712 0 107.736 0.084 ;
    END
  END h_wstrb[2]
  PIN h_wstrb[30]
    DIRECTION OUTPUT ;
    USE SIGNAL ;
    PORT
      LAYER M5 ;
        RECT  110.4 0 110.424 0.084 ;
    END
  END h_wstrb[30]
  PIN h_wstrb[31]
    DIRECTION OUTPUT ;
    USE SIGNAL ;
    PORT
      LAYER M5 ;
        RECT  110.496 0 110.52 0.084 ;
    END
  END h_wstrb[31]
  PIN h_wstrb[3]
    DIRECTION OUTPUT ;
    USE SIGNAL ;
    PORT
      LAYER M5 ;
        RECT  107.808 0 107.832 0.084 ;
    END
  END h_wstrb[3]
  PIN h_wstrb[4]
    DIRECTION OUTPUT ;
    USE SIGNAL ;
    PORT
      LAYER M5 ;
        RECT  107.904 0 107.928 0.084 ;
    END
  END h_wstrb[4]
  PIN h_wstrb[5]
    DIRECTION OUTPUT ;
    USE SIGNAL ;
    PORT
      LAYER M5 ;
        RECT  108 0 108.024 0.084 ;
    END
  END h_wstrb[5]
  PIN h_wstrb[6]
    DIRECTION OUTPUT ;
    USE SIGNAL ;
    PORT
      LAYER M5 ;
        RECT  108.096 0 108.12 0.084 ;
    END
  END h_wstrb[6]
  PIN h_wstrb[7]
    DIRECTION OUTPUT ;
    USE SIGNAL ;
    PORT
      LAYER M5 ;
        RECT  108.192 0 108.216 0.084 ;
    END
  END h_wstrb[7]
  PIN h_wstrb[8]
    DIRECTION OUTPUT ;
    USE SIGNAL ;
    PORT
      LAYER M5 ;
        RECT  108.288 0 108.312 0.084 ;
    END
  END h_wstrb[8]
  PIN h_wstrb[9]
    DIRECTION OUTPUT ;
    USE SIGNAL ;
    PORT
      LAYER M5 ;
        RECT  108.384 0 108.408 0.084 ;
    END
  END h_wstrb[9]
  PIN k_addr[0]
    DIRECTION INPUT ;
    USE SIGNAL ;
    PORT
      LAYER M5 ;
        RECT  255.456 63.916 255.48 64 ;
    END
  END k_addr[0]
  PIN k_addr[10]
    DIRECTION INPUT ;
    USE SIGNAL ;
    PORT
      LAYER M5 ;
        RECT  256.416 63.916 256.44 64 ;
    END
  END k_addr[10]
  PIN k_addr[11]
    DIRECTION INPUT ;
    USE SIGNAL ;
    PORT
      LAYER M5 ;
        RECT  256.512 63.916 256.536 64 ;
    END
  END k_addr[11]
  PIN k_addr[12]
    DIRECTION INPUT ;
    USE SIGNAL ;
    PORT
      LAYER M5 ;
        RECT  256.608 63.916 256.632 64 ;
    END
  END k_addr[12]
  PIN k_addr[13]
    DIRECTION INPUT ;
    USE SIGNAL ;
    PORT
      LAYER M5 ;
        RECT  256.704 63.916 256.728 64 ;
    END
  END k_addr[13]
  PIN k_addr[14]
    DIRECTION INPUT ;
    USE SIGNAL ;
    PORT
      LAYER M5 ;
        RECT  256.8 63.916 256.824 64 ;
    END
  END k_addr[14]
  PIN k_addr[15]
    DIRECTION INPUT ;
    USE SIGNAL ;
    PORT
      LAYER M5 ;
        RECT  256.896 63.916 256.92 64 ;
    END
  END k_addr[15]
  PIN k_addr[16]
    DIRECTION INPUT ;
    USE SIGNAL ;
    PORT
      LAYER M5 ;
        RECT  256.992 63.916 257.016 64 ;
    END
  END k_addr[16]
  PIN k_addr[17]
    DIRECTION INPUT ;
    USE SIGNAL ;
    PORT
      LAYER M5 ;
        RECT  257.088 63.916 257.112 64 ;
    END
  END k_addr[17]
  PIN k_addr[18]
    DIRECTION INPUT ;
    USE SIGNAL ;
    PORT
      LAYER M5 ;
        RECT  257.184 63.916 257.208 64 ;
    END
  END k_addr[18]
  PIN k_addr[19]
    DIRECTION INPUT ;
    USE SIGNAL ;
    PORT
      LAYER M5 ;
        RECT  257.28 63.916 257.304 64 ;
    END
  END k_addr[19]
  PIN k_addr[1]
    DIRECTION INPUT ;
    USE SIGNAL ;
    PORT
      LAYER M5 ;
        RECT  255.552 63.916 255.576 64 ;
    END
  END k_addr[1]
  PIN k_addr[20]
    DIRECTION INPUT ;
    USE SIGNAL ;
    PORT
      LAYER M5 ;
        RECT  257.376 63.916 257.4 64 ;
    END
  END k_addr[20]
  PIN k_addr[21]
    DIRECTION INPUT ;
    USE SIGNAL ;
    PORT
      LAYER M5 ;
        RECT  257.472 63.916 257.496 64 ;
    END
  END k_addr[21]
  PIN k_addr[22]
    DIRECTION INPUT ;
    USE SIGNAL ;
    PORT
      LAYER M5 ;
        RECT  257.568 63.916 257.592 64 ;
    END
  END k_addr[22]
  PIN k_addr[23]
    DIRECTION INPUT ;
    USE SIGNAL ;
    PORT
      LAYER M5 ;
        RECT  257.664 63.916 257.688 64 ;
    END
  END k_addr[23]
  PIN k_addr[24]
    DIRECTION INPUT ;
    USE SIGNAL ;
    PORT
      LAYER M5 ;
        RECT  257.76 63.916 257.784 64 ;
    END
  END k_addr[24]
  PIN k_addr[25]
    DIRECTION INPUT ;
    USE SIGNAL ;
    PORT
      LAYER M5 ;
        RECT  257.856 63.916 257.88 64 ;
    END
  END k_addr[25]
  PIN k_addr[26]
    DIRECTION INPUT ;
    USE SIGNAL ;
    PORT
      LAYER M5 ;
        RECT  257.952 63.916 257.976 64 ;
    END
  END k_addr[26]
  PIN k_addr[27]
    DIRECTION INPUT ;
    USE SIGNAL ;
    PORT
      LAYER M5 ;
        RECT  258.048 63.916 258.072 64 ;
    END
  END k_addr[27]
  PIN k_addr[28]
    DIRECTION INPUT ;
    USE SIGNAL ;
    PORT
      LAYER M5 ;
        RECT  258.144 63.916 258.168 64 ;
    END
  END k_addr[28]
  PIN k_addr[29]
    DIRECTION INPUT ;
    USE SIGNAL ;
    PORT
      LAYER M5 ;
        RECT  258.24 63.916 258.264 64 ;
    END
  END k_addr[29]
  PIN k_addr[2]
    DIRECTION INPUT ;
    USE SIGNAL ;
    PORT
      LAYER M5 ;
        RECT  255.648 63.916 255.672 64 ;
    END
  END k_addr[2]
  PIN k_addr[3]
    DIRECTION INPUT ;
    USE SIGNAL ;
    PORT
      LAYER M5 ;
        RECT  255.744 63.916 255.768 64 ;
    END
  END k_addr[3]
  PIN k_addr[4]
    DIRECTION INPUT ;
    USE SIGNAL ;
    PORT
      LAYER M5 ;
        RECT  255.84 63.916 255.864 64 ;
    END
  END k_addr[4]
  PIN k_addr[5]
    DIRECTION INPUT ;
    USE SIGNAL ;
    PORT
      LAYER M5 ;
        RECT  255.936 63.916 255.96 64 ;
    END
  END k_addr[5]
  PIN k_addr[6]
    DIRECTION INPUT ;
    USE SIGNAL ;
    PORT
      LAYER M5 ;
        RECT  256.032 63.916 256.056 64 ;
    END
  END k_addr[6]
  PIN k_addr[7]
    DIRECTION INPUT ;
    USE SIGNAL ;
    PORT
      LAYER M5 ;
        RECT  256.128 63.916 256.152 64 ;
    END
  END k_addr[7]
  PIN k_addr[8]
    DIRECTION INPUT ;
    USE SIGNAL ;
    PORT
      LAYER M5 ;
        RECT  256.224 63.916 256.248 64 ;
    END
  END k_addr[8]
  PIN k_addr[9]
    DIRECTION INPUT ;
    USE SIGNAL ;
    PORT
      LAYER M5 ;
        RECT  256.32 63.916 256.344 64 ;
    END
  END k_addr[9]
  PIN k_len[0]
    DIRECTION INPUT ;
    USE SIGNAL ;
    PORT
      LAYER M5 ;
        RECT  258.336 63.916 258.36 64 ;
    END
  END k_len[0]
  PIN k_len[1]
    DIRECTION INPUT ;
    USE SIGNAL ;
    PORT
      LAYER M5 ;
        RECT  258.432 63.916 258.456 64 ;
    END
  END k_len[1]
  PIN k_len[2]
    DIRECTION INPUT ;
    USE SIGNAL ;
    PORT
      LAYER M5 ;
        RECT  258.528 63.916 258.552 64 ;
    END
  END k_len[2]
  PIN k_len[3]
    DIRECTION INPUT ;
    USE SIGNAL ;
    PORT
      LAYER M5 ;
        RECT  258.624 63.916 258.648 64 ;
    END
  END k_len[3]
  PIN k_rsp_beat[0]
    DIRECTION OUTPUT ;
    USE SIGNAL ;
    PORT
      LAYER M5 ;
        RECT  258.72 63.916 258.744 64 ;
    END
  END k_rsp_beat[0]
  PIN k_rsp_beat[1]
    DIRECTION OUTPUT ;
    USE SIGNAL ;
    PORT
      LAYER M5 ;
        RECT  258.816 63.916 258.84 64 ;
    END
  END k_rsp_beat[1]
  PIN k_rsp_beat[2]
    DIRECTION OUTPUT ;
    USE SIGNAL ;
    PORT
      LAYER M5 ;
        RECT  258.912 63.916 258.936 64 ;
    END
  END k_rsp_beat[2]
  PIN k_rsp_beat[3]
    DIRECTION OUTPUT ;
    USE SIGNAL ;
    PORT
      LAYER M5 ;
        RECT  259.008 63.916 259.032 64 ;
    END
  END k_rsp_beat[3]
  PIN k_rsp_data[0]
    DIRECTION OUTPUT ;
    USE SIGNAL ;
    PORT
      LAYER M5 ;
        RECT  259.104 63.916 259.128 64 ;
    END
  END k_rsp_data[0]
  PIN k_rsp_data[100]
    DIRECTION OUTPUT ;
    USE SIGNAL ;
    PORT
      LAYER M5 ;
        RECT  268.704 63.916 268.728 64 ;
    END
  END k_rsp_data[100]
  PIN k_rsp_data[101]
    DIRECTION OUTPUT ;
    USE SIGNAL ;
    PORT
      LAYER M5 ;
        RECT  268.8 63.916 268.824 64 ;
    END
  END k_rsp_data[101]
  PIN k_rsp_data[102]
    DIRECTION OUTPUT ;
    USE SIGNAL ;
    PORT
      LAYER M5 ;
        RECT  268.896 63.916 268.92 64 ;
    END
  END k_rsp_data[102]
  PIN k_rsp_data[103]
    DIRECTION OUTPUT ;
    USE SIGNAL ;
    PORT
      LAYER M5 ;
        RECT  268.992 63.916 269.016 64 ;
    END
  END k_rsp_data[103]
  PIN k_rsp_data[104]
    DIRECTION OUTPUT ;
    USE SIGNAL ;
    PORT
      LAYER M5 ;
        RECT  269.088 63.916 269.112 64 ;
    END
  END k_rsp_data[104]
  PIN k_rsp_data[105]
    DIRECTION OUTPUT ;
    USE SIGNAL ;
    PORT
      LAYER M5 ;
        RECT  269.184 63.916 269.208 64 ;
    END
  END k_rsp_data[105]
  PIN k_rsp_data[106]
    DIRECTION OUTPUT ;
    USE SIGNAL ;
    PORT
      LAYER M5 ;
        RECT  269.28 63.916 269.304 64 ;
    END
  END k_rsp_data[106]
  PIN k_rsp_data[107]
    DIRECTION OUTPUT ;
    USE SIGNAL ;
    PORT
      LAYER M5 ;
        RECT  269.376 63.916 269.4 64 ;
    END
  END k_rsp_data[107]
  PIN k_rsp_data[108]
    DIRECTION OUTPUT ;
    USE SIGNAL ;
    PORT
      LAYER M5 ;
        RECT  269.472 63.916 269.496 64 ;
    END
  END k_rsp_data[108]
  PIN k_rsp_data[109]
    DIRECTION OUTPUT ;
    USE SIGNAL ;
    PORT
      LAYER M5 ;
        RECT  269.568 63.916 269.592 64 ;
    END
  END k_rsp_data[109]
  PIN k_rsp_data[10]
    DIRECTION OUTPUT ;
    USE SIGNAL ;
    PORT
      LAYER M5 ;
        RECT  260.064 63.916 260.088 64 ;
    END
  END k_rsp_data[10]
  PIN k_rsp_data[110]
    DIRECTION OUTPUT ;
    USE SIGNAL ;
    PORT
      LAYER M5 ;
        RECT  269.664 63.916 269.688 64 ;
    END
  END k_rsp_data[110]
  PIN k_rsp_data[111]
    DIRECTION OUTPUT ;
    USE SIGNAL ;
    PORT
      LAYER M5 ;
        RECT  269.76 63.916 269.784 64 ;
    END
  END k_rsp_data[111]
  PIN k_rsp_data[112]
    DIRECTION OUTPUT ;
    USE SIGNAL ;
    PORT
      LAYER M5 ;
        RECT  269.856 63.916 269.88 64 ;
    END
  END k_rsp_data[112]
  PIN k_rsp_data[113]
    DIRECTION OUTPUT ;
    USE SIGNAL ;
    PORT
      LAYER M5 ;
        RECT  269.952 63.916 269.976 64 ;
    END
  END k_rsp_data[113]
  PIN k_rsp_data[114]
    DIRECTION OUTPUT ;
    USE SIGNAL ;
    PORT
      LAYER M5 ;
        RECT  270.048 63.916 270.072 64 ;
    END
  END k_rsp_data[114]
  PIN k_rsp_data[115]
    DIRECTION OUTPUT ;
    USE SIGNAL ;
    PORT
      LAYER M5 ;
        RECT  270.144 63.916 270.168 64 ;
    END
  END k_rsp_data[115]
  PIN k_rsp_data[116]
    DIRECTION OUTPUT ;
    USE SIGNAL ;
    PORT
      LAYER M5 ;
        RECT  270.24 63.916 270.264 64 ;
    END
  END k_rsp_data[116]
  PIN k_rsp_data[117]
    DIRECTION OUTPUT ;
    USE SIGNAL ;
    PORT
      LAYER M5 ;
        RECT  270.336 63.916 270.36 64 ;
    END
  END k_rsp_data[117]
  PIN k_rsp_data[118]
    DIRECTION OUTPUT ;
    USE SIGNAL ;
    PORT
      LAYER M5 ;
        RECT  270.432 63.916 270.456 64 ;
    END
  END k_rsp_data[118]
  PIN k_rsp_data[119]
    DIRECTION OUTPUT ;
    USE SIGNAL ;
    PORT
      LAYER M5 ;
        RECT  270.528 63.916 270.552 64 ;
    END
  END k_rsp_data[119]
  PIN k_rsp_data[11]
    DIRECTION OUTPUT ;
    USE SIGNAL ;
    PORT
      LAYER M5 ;
        RECT  260.16 63.916 260.184 64 ;
    END
  END k_rsp_data[11]
  PIN k_rsp_data[120]
    DIRECTION OUTPUT ;
    USE SIGNAL ;
    PORT
      LAYER M5 ;
        RECT  270.624 63.916 270.648 64 ;
    END
  END k_rsp_data[120]
  PIN k_rsp_data[121]
    DIRECTION OUTPUT ;
    USE SIGNAL ;
    PORT
      LAYER M5 ;
        RECT  270.72 63.916 270.744 64 ;
    END
  END k_rsp_data[121]
  PIN k_rsp_data[122]
    DIRECTION OUTPUT ;
    USE SIGNAL ;
    PORT
      LAYER M5 ;
        RECT  270.816 63.916 270.84 64 ;
    END
  END k_rsp_data[122]
  PIN k_rsp_data[123]
    DIRECTION OUTPUT ;
    USE SIGNAL ;
    PORT
      LAYER M5 ;
        RECT  270.912 63.916 270.936 64 ;
    END
  END k_rsp_data[123]
  PIN k_rsp_data[124]
    DIRECTION OUTPUT ;
    USE SIGNAL ;
    PORT
      LAYER M5 ;
        RECT  271.008 63.916 271.032 64 ;
    END
  END k_rsp_data[124]
  PIN k_rsp_data[125]
    DIRECTION OUTPUT ;
    USE SIGNAL ;
    PORT
      LAYER M5 ;
        RECT  271.104 63.916 271.128 64 ;
    END
  END k_rsp_data[125]
  PIN k_rsp_data[126]
    DIRECTION OUTPUT ;
    USE SIGNAL ;
    PORT
      LAYER M5 ;
        RECT  271.2 63.916 271.224 64 ;
    END
  END k_rsp_data[126]
  PIN k_rsp_data[127]
    DIRECTION OUTPUT ;
    USE SIGNAL ;
    PORT
      LAYER M5 ;
        RECT  271.296 63.916 271.32 64 ;
    END
  END k_rsp_data[127]
  PIN k_rsp_data[128]
    DIRECTION OUTPUT ;
    USE SIGNAL ;
    PORT
      LAYER M5 ;
        RECT  271.392 63.916 271.416 64 ;
    END
  END k_rsp_data[128]
  PIN k_rsp_data[129]
    DIRECTION OUTPUT ;
    USE SIGNAL ;
    PORT
      LAYER M5 ;
        RECT  271.488 63.916 271.512 64 ;
    END
  END k_rsp_data[129]
  PIN k_rsp_data[12]
    DIRECTION OUTPUT ;
    USE SIGNAL ;
    PORT
      LAYER M5 ;
        RECT  260.256 63.916 260.28 64 ;
    END
  END k_rsp_data[12]
  PIN k_rsp_data[130]
    DIRECTION OUTPUT ;
    USE SIGNAL ;
    PORT
      LAYER M5 ;
        RECT  271.584 63.916 271.608 64 ;
    END
  END k_rsp_data[130]
  PIN k_rsp_data[131]
    DIRECTION OUTPUT ;
    USE SIGNAL ;
    PORT
      LAYER M5 ;
        RECT  271.68 63.916 271.704 64 ;
    END
  END k_rsp_data[131]
  PIN k_rsp_data[132]
    DIRECTION OUTPUT ;
    USE SIGNAL ;
    PORT
      LAYER M5 ;
        RECT  271.776 63.916 271.8 64 ;
    END
  END k_rsp_data[132]
  PIN k_rsp_data[133]
    DIRECTION OUTPUT ;
    USE SIGNAL ;
    PORT
      LAYER M5 ;
        RECT  271.872 63.916 271.896 64 ;
    END
  END k_rsp_data[133]
  PIN k_rsp_data[134]
    DIRECTION OUTPUT ;
    USE SIGNAL ;
    PORT
      LAYER M5 ;
        RECT  271.968 63.916 271.992 64 ;
    END
  END k_rsp_data[134]
  PIN k_rsp_data[135]
    DIRECTION OUTPUT ;
    USE SIGNAL ;
    PORT
      LAYER M5 ;
        RECT  272.064 63.916 272.088 64 ;
    END
  END k_rsp_data[135]
  PIN k_rsp_data[136]
    DIRECTION OUTPUT ;
    USE SIGNAL ;
    PORT
      LAYER M5 ;
        RECT  272.16 63.916 272.184 64 ;
    END
  END k_rsp_data[136]
  PIN k_rsp_data[137]
    DIRECTION OUTPUT ;
    USE SIGNAL ;
    PORT
      LAYER M5 ;
        RECT  272.256 63.916 272.28 64 ;
    END
  END k_rsp_data[137]
  PIN k_rsp_data[138]
    DIRECTION OUTPUT ;
    USE SIGNAL ;
    PORT
      LAYER M5 ;
        RECT  272.352 63.916 272.376 64 ;
    END
  END k_rsp_data[138]
  PIN k_rsp_data[139]
    DIRECTION OUTPUT ;
    USE SIGNAL ;
    PORT
      LAYER M5 ;
        RECT  272.448 63.916 272.472 64 ;
    END
  END k_rsp_data[139]
  PIN k_rsp_data[13]
    DIRECTION OUTPUT ;
    USE SIGNAL ;
    PORT
      LAYER M5 ;
        RECT  260.352 63.916 260.376 64 ;
    END
  END k_rsp_data[13]
  PIN k_rsp_data[140]
    DIRECTION OUTPUT ;
    USE SIGNAL ;
    PORT
      LAYER M5 ;
        RECT  272.544 63.916 272.568 64 ;
    END
  END k_rsp_data[140]
  PIN k_rsp_data[141]
    DIRECTION OUTPUT ;
    USE SIGNAL ;
    PORT
      LAYER M5 ;
        RECT  272.64 63.916 272.664 64 ;
    END
  END k_rsp_data[141]
  PIN k_rsp_data[142]
    DIRECTION OUTPUT ;
    USE SIGNAL ;
    PORT
      LAYER M5 ;
        RECT  272.736 63.916 272.76 64 ;
    END
  END k_rsp_data[142]
  PIN k_rsp_data[143]
    DIRECTION OUTPUT ;
    USE SIGNAL ;
    PORT
      LAYER M5 ;
        RECT  272.832 63.916 272.856 64 ;
    END
  END k_rsp_data[143]
  PIN k_rsp_data[144]
    DIRECTION OUTPUT ;
    USE SIGNAL ;
    PORT
      LAYER M5 ;
        RECT  272.928 63.916 272.952 64 ;
    END
  END k_rsp_data[144]
  PIN k_rsp_data[145]
    DIRECTION OUTPUT ;
    USE SIGNAL ;
    PORT
      LAYER M5 ;
        RECT  273.024 63.916 273.048 64 ;
    END
  END k_rsp_data[145]
  PIN k_rsp_data[146]
    DIRECTION OUTPUT ;
    USE SIGNAL ;
    PORT
      LAYER M5 ;
        RECT  273.12 63.916 273.144 64 ;
    END
  END k_rsp_data[146]
  PIN k_rsp_data[147]
    DIRECTION OUTPUT ;
    USE SIGNAL ;
    PORT
      LAYER M5 ;
        RECT  273.216 63.916 273.24 64 ;
    END
  END k_rsp_data[147]
  PIN k_rsp_data[148]
    DIRECTION OUTPUT ;
    USE SIGNAL ;
    PORT
      LAYER M5 ;
        RECT  273.312 63.916 273.336 64 ;
    END
  END k_rsp_data[148]
  PIN k_rsp_data[149]
    DIRECTION OUTPUT ;
    USE SIGNAL ;
    PORT
      LAYER M5 ;
        RECT  273.408 63.916 273.432 64 ;
    END
  END k_rsp_data[149]
  PIN k_rsp_data[14]
    DIRECTION OUTPUT ;
    USE SIGNAL ;
    PORT
      LAYER M5 ;
        RECT  260.448 63.916 260.472 64 ;
    END
  END k_rsp_data[14]
  PIN k_rsp_data[150]
    DIRECTION OUTPUT ;
    USE SIGNAL ;
    PORT
      LAYER M5 ;
        RECT  273.504 63.916 273.528 64 ;
    END
  END k_rsp_data[150]
  PIN k_rsp_data[151]
    DIRECTION OUTPUT ;
    USE SIGNAL ;
    PORT
      LAYER M5 ;
        RECT  273.6 63.916 273.624 64 ;
    END
  END k_rsp_data[151]
  PIN k_rsp_data[152]
    DIRECTION OUTPUT ;
    USE SIGNAL ;
    PORT
      LAYER M5 ;
        RECT  273.696 63.916 273.72 64 ;
    END
  END k_rsp_data[152]
  PIN k_rsp_data[153]
    DIRECTION OUTPUT ;
    USE SIGNAL ;
    PORT
      LAYER M5 ;
        RECT  273.792 63.916 273.816 64 ;
    END
  END k_rsp_data[153]
  PIN k_rsp_data[154]
    DIRECTION OUTPUT ;
    USE SIGNAL ;
    PORT
      LAYER M5 ;
        RECT  273.888 63.916 273.912 64 ;
    END
  END k_rsp_data[154]
  PIN k_rsp_data[155]
    DIRECTION OUTPUT ;
    USE SIGNAL ;
    PORT
      LAYER M5 ;
        RECT  273.984 63.916 274.008 64 ;
    END
  END k_rsp_data[155]
  PIN k_rsp_data[156]
    DIRECTION OUTPUT ;
    USE SIGNAL ;
    PORT
      LAYER M5 ;
        RECT  274.08 63.916 274.104 64 ;
    END
  END k_rsp_data[156]
  PIN k_rsp_data[157]
    DIRECTION OUTPUT ;
    USE SIGNAL ;
    PORT
      LAYER M5 ;
        RECT  274.176 63.916 274.2 64 ;
    END
  END k_rsp_data[157]
  PIN k_rsp_data[158]
    DIRECTION OUTPUT ;
    USE SIGNAL ;
    PORT
      LAYER M5 ;
        RECT  274.272 63.916 274.296 64 ;
    END
  END k_rsp_data[158]
  PIN k_rsp_data[159]
    DIRECTION OUTPUT ;
    USE SIGNAL ;
    PORT
      LAYER M5 ;
        RECT  274.368 63.916 274.392 64 ;
    END
  END k_rsp_data[159]
  PIN k_rsp_data[15]
    DIRECTION OUTPUT ;
    USE SIGNAL ;
    PORT
      LAYER M5 ;
        RECT  260.544 63.916 260.568 64 ;
    END
  END k_rsp_data[15]
  PIN k_rsp_data[160]
    DIRECTION OUTPUT ;
    USE SIGNAL ;
    PORT
      LAYER M5 ;
        RECT  274.464 63.916 274.488 64 ;
    END
  END k_rsp_data[160]
  PIN k_rsp_data[161]
    DIRECTION OUTPUT ;
    USE SIGNAL ;
    PORT
      LAYER M5 ;
        RECT  274.56 63.916 274.584 64 ;
    END
  END k_rsp_data[161]
  PIN k_rsp_data[162]
    DIRECTION OUTPUT ;
    USE SIGNAL ;
    PORT
      LAYER M5 ;
        RECT  274.656 63.916 274.68 64 ;
    END
  END k_rsp_data[162]
  PIN k_rsp_data[163]
    DIRECTION OUTPUT ;
    USE SIGNAL ;
    PORT
      LAYER M5 ;
        RECT  274.752 63.916 274.776 64 ;
    END
  END k_rsp_data[163]
  PIN k_rsp_data[164]
    DIRECTION OUTPUT ;
    USE SIGNAL ;
    PORT
      LAYER M5 ;
        RECT  274.848 63.916 274.872 64 ;
    END
  END k_rsp_data[164]
  PIN k_rsp_data[165]
    DIRECTION OUTPUT ;
    USE SIGNAL ;
    PORT
      LAYER M5 ;
        RECT  274.944 63.916 274.968 64 ;
    END
  END k_rsp_data[165]
  PIN k_rsp_data[166]
    DIRECTION OUTPUT ;
    USE SIGNAL ;
    PORT
      LAYER M5 ;
        RECT  275.04 63.916 275.064 64 ;
    END
  END k_rsp_data[166]
  PIN k_rsp_data[167]
    DIRECTION OUTPUT ;
    USE SIGNAL ;
    PORT
      LAYER M5 ;
        RECT  275.136 63.916 275.16 64 ;
    END
  END k_rsp_data[167]
  PIN k_rsp_data[168]
    DIRECTION OUTPUT ;
    USE SIGNAL ;
    PORT
      LAYER M5 ;
        RECT  275.232 63.916 275.256 64 ;
    END
  END k_rsp_data[168]
  PIN k_rsp_data[169]
    DIRECTION OUTPUT ;
    USE SIGNAL ;
    PORT
      LAYER M5 ;
        RECT  275.328 63.916 275.352 64 ;
    END
  END k_rsp_data[169]
  PIN k_rsp_data[16]
    DIRECTION OUTPUT ;
    USE SIGNAL ;
    PORT
      LAYER M5 ;
        RECT  260.64 63.916 260.664 64 ;
    END
  END k_rsp_data[16]
  PIN k_rsp_data[170]
    DIRECTION OUTPUT ;
    USE SIGNAL ;
    PORT
      LAYER M5 ;
        RECT  275.424 63.916 275.448 64 ;
    END
  END k_rsp_data[170]
  PIN k_rsp_data[171]
    DIRECTION OUTPUT ;
    USE SIGNAL ;
    PORT
      LAYER M5 ;
        RECT  275.52 63.916 275.544 64 ;
    END
  END k_rsp_data[171]
  PIN k_rsp_data[172]
    DIRECTION OUTPUT ;
    USE SIGNAL ;
    PORT
      LAYER M5 ;
        RECT  275.616 63.916 275.64 64 ;
    END
  END k_rsp_data[172]
  PIN k_rsp_data[173]
    DIRECTION OUTPUT ;
    USE SIGNAL ;
    PORT
      LAYER M5 ;
        RECT  275.712 63.916 275.736 64 ;
    END
  END k_rsp_data[173]
  PIN k_rsp_data[174]
    DIRECTION OUTPUT ;
    USE SIGNAL ;
    PORT
      LAYER M5 ;
        RECT  275.808 63.916 275.832 64 ;
    END
  END k_rsp_data[174]
  PIN k_rsp_data[175]
    DIRECTION OUTPUT ;
    USE SIGNAL ;
    PORT
      LAYER M5 ;
        RECT  275.904 63.916 275.928 64 ;
    END
  END k_rsp_data[175]
  PIN k_rsp_data[176]
    DIRECTION OUTPUT ;
    USE SIGNAL ;
    PORT
      LAYER M5 ;
        RECT  276 63.916 276.024 64 ;
    END
  END k_rsp_data[176]
  PIN k_rsp_data[177]
    DIRECTION OUTPUT ;
    USE SIGNAL ;
    PORT
      LAYER M5 ;
        RECT  276.096 63.916 276.12 64 ;
    END
  END k_rsp_data[177]
  PIN k_rsp_data[178]
    DIRECTION OUTPUT ;
    USE SIGNAL ;
    PORT
      LAYER M5 ;
        RECT  276.192 63.916 276.216 64 ;
    END
  END k_rsp_data[178]
  PIN k_rsp_data[179]
    DIRECTION OUTPUT ;
    USE SIGNAL ;
    PORT
      LAYER M5 ;
        RECT  276.288 63.916 276.312 64 ;
    END
  END k_rsp_data[179]
  PIN k_rsp_data[17]
    DIRECTION OUTPUT ;
    USE SIGNAL ;
    PORT
      LAYER M5 ;
        RECT  260.736 63.916 260.76 64 ;
    END
  END k_rsp_data[17]
  PIN k_rsp_data[180]
    DIRECTION OUTPUT ;
    USE SIGNAL ;
    PORT
      LAYER M5 ;
        RECT  276.384 63.916 276.408 64 ;
    END
  END k_rsp_data[180]
  PIN k_rsp_data[181]
    DIRECTION OUTPUT ;
    USE SIGNAL ;
    PORT
      LAYER M5 ;
        RECT  276.48 63.916 276.504 64 ;
    END
  END k_rsp_data[181]
  PIN k_rsp_data[182]
    DIRECTION OUTPUT ;
    USE SIGNAL ;
    PORT
      LAYER M5 ;
        RECT  276.576 63.916 276.6 64 ;
    END
  END k_rsp_data[182]
  PIN k_rsp_data[183]
    DIRECTION OUTPUT ;
    USE SIGNAL ;
    PORT
      LAYER M5 ;
        RECT  276.672 63.916 276.696 64 ;
    END
  END k_rsp_data[183]
  PIN k_rsp_data[184]
    DIRECTION OUTPUT ;
    USE SIGNAL ;
    PORT
      LAYER M5 ;
        RECT  276.768 63.916 276.792 64 ;
    END
  END k_rsp_data[184]
  PIN k_rsp_data[185]
    DIRECTION OUTPUT ;
    USE SIGNAL ;
    PORT
      LAYER M5 ;
        RECT  276.864 63.916 276.888 64 ;
    END
  END k_rsp_data[185]
  PIN k_rsp_data[186]
    DIRECTION OUTPUT ;
    USE SIGNAL ;
    PORT
      LAYER M5 ;
        RECT  276.96 63.916 276.984 64 ;
    END
  END k_rsp_data[186]
  PIN k_rsp_data[187]
    DIRECTION OUTPUT ;
    USE SIGNAL ;
    PORT
      LAYER M5 ;
        RECT  277.056 63.916 277.08 64 ;
    END
  END k_rsp_data[187]
  PIN k_rsp_data[188]
    DIRECTION OUTPUT ;
    USE SIGNAL ;
    PORT
      LAYER M5 ;
        RECT  277.152 63.916 277.176 64 ;
    END
  END k_rsp_data[188]
  PIN k_rsp_data[189]
    DIRECTION OUTPUT ;
    USE SIGNAL ;
    PORT
      LAYER M5 ;
        RECT  277.248 63.916 277.272 64 ;
    END
  END k_rsp_data[189]
  PIN k_rsp_data[18]
    DIRECTION OUTPUT ;
    USE SIGNAL ;
    PORT
      LAYER M5 ;
        RECT  260.832 63.916 260.856 64 ;
    END
  END k_rsp_data[18]
  PIN k_rsp_data[190]
    DIRECTION OUTPUT ;
    USE SIGNAL ;
    PORT
      LAYER M5 ;
        RECT  277.344 63.916 277.368 64 ;
    END
  END k_rsp_data[190]
  PIN k_rsp_data[191]
    DIRECTION OUTPUT ;
    USE SIGNAL ;
    PORT
      LAYER M5 ;
        RECT  277.44 63.916 277.464 64 ;
    END
  END k_rsp_data[191]
  PIN k_rsp_data[192]
    DIRECTION OUTPUT ;
    USE SIGNAL ;
    PORT
      LAYER M5 ;
        RECT  277.536 63.916 277.56 64 ;
    END
  END k_rsp_data[192]
  PIN k_rsp_data[193]
    DIRECTION OUTPUT ;
    USE SIGNAL ;
    PORT
      LAYER M5 ;
        RECT  277.632 63.916 277.656 64 ;
    END
  END k_rsp_data[193]
  PIN k_rsp_data[194]
    DIRECTION OUTPUT ;
    USE SIGNAL ;
    PORT
      LAYER M5 ;
        RECT  277.728 63.916 277.752 64 ;
    END
  END k_rsp_data[194]
  PIN k_rsp_data[195]
    DIRECTION OUTPUT ;
    USE SIGNAL ;
    PORT
      LAYER M5 ;
        RECT  277.824 63.916 277.848 64 ;
    END
  END k_rsp_data[195]
  PIN k_rsp_data[196]
    DIRECTION OUTPUT ;
    USE SIGNAL ;
    PORT
      LAYER M5 ;
        RECT  277.92 63.916 277.944 64 ;
    END
  END k_rsp_data[196]
  PIN k_rsp_data[197]
    DIRECTION OUTPUT ;
    USE SIGNAL ;
    PORT
      LAYER M5 ;
        RECT  278.016 63.916 278.04 64 ;
    END
  END k_rsp_data[197]
  PIN k_rsp_data[198]
    DIRECTION OUTPUT ;
    USE SIGNAL ;
    PORT
      LAYER M5 ;
        RECT  278.112 63.916 278.136 64 ;
    END
  END k_rsp_data[198]
  PIN k_rsp_data[199]
    DIRECTION OUTPUT ;
    USE SIGNAL ;
    PORT
      LAYER M5 ;
        RECT  278.208 63.916 278.232 64 ;
    END
  END k_rsp_data[199]
  PIN k_rsp_data[19]
    DIRECTION OUTPUT ;
    USE SIGNAL ;
    PORT
      LAYER M5 ;
        RECT  260.928 63.916 260.952 64 ;
    END
  END k_rsp_data[19]
  PIN k_rsp_data[1]
    DIRECTION OUTPUT ;
    USE SIGNAL ;
    PORT
      LAYER M5 ;
        RECT  259.2 63.916 259.224 64 ;
    END
  END k_rsp_data[1]
  PIN k_rsp_data[200]
    DIRECTION OUTPUT ;
    USE SIGNAL ;
    PORT
      LAYER M5 ;
        RECT  278.304 63.916 278.328 64 ;
    END
  END k_rsp_data[200]
  PIN k_rsp_data[201]
    DIRECTION OUTPUT ;
    USE SIGNAL ;
    PORT
      LAYER M5 ;
        RECT  278.4 63.916 278.424 64 ;
    END
  END k_rsp_data[201]
  PIN k_rsp_data[202]
    DIRECTION OUTPUT ;
    USE SIGNAL ;
    PORT
      LAYER M5 ;
        RECT  278.496 63.916 278.52 64 ;
    END
  END k_rsp_data[202]
  PIN k_rsp_data[203]
    DIRECTION OUTPUT ;
    USE SIGNAL ;
    PORT
      LAYER M5 ;
        RECT  278.592 63.916 278.616 64 ;
    END
  END k_rsp_data[203]
  PIN k_rsp_data[204]
    DIRECTION OUTPUT ;
    USE SIGNAL ;
    PORT
      LAYER M5 ;
        RECT  278.688 63.916 278.712 64 ;
    END
  END k_rsp_data[204]
  PIN k_rsp_data[205]
    DIRECTION OUTPUT ;
    USE SIGNAL ;
    PORT
      LAYER M5 ;
        RECT  278.784 63.916 278.808 64 ;
    END
  END k_rsp_data[205]
  PIN k_rsp_data[206]
    DIRECTION OUTPUT ;
    USE SIGNAL ;
    PORT
      LAYER M5 ;
        RECT  278.88 63.916 278.904 64 ;
    END
  END k_rsp_data[206]
  PIN k_rsp_data[207]
    DIRECTION OUTPUT ;
    USE SIGNAL ;
    PORT
      LAYER M5 ;
        RECT  278.976 63.916 279 64 ;
    END
  END k_rsp_data[207]
  PIN k_rsp_data[208]
    DIRECTION OUTPUT ;
    USE SIGNAL ;
    PORT
      LAYER M5 ;
        RECT  279.072 63.916 279.096 64 ;
    END
  END k_rsp_data[208]
  PIN k_rsp_data[209]
    DIRECTION OUTPUT ;
    USE SIGNAL ;
    PORT
      LAYER M5 ;
        RECT  279.168 63.916 279.192 64 ;
    END
  END k_rsp_data[209]
  PIN k_rsp_data[20]
    DIRECTION OUTPUT ;
    USE SIGNAL ;
    PORT
      LAYER M5 ;
        RECT  261.024 63.916 261.048 64 ;
    END
  END k_rsp_data[20]
  PIN k_rsp_data[210]
    DIRECTION OUTPUT ;
    USE SIGNAL ;
    PORT
      LAYER M5 ;
        RECT  279.264 63.916 279.288 64 ;
    END
  END k_rsp_data[210]
  PIN k_rsp_data[211]
    DIRECTION OUTPUT ;
    USE SIGNAL ;
    PORT
      LAYER M5 ;
        RECT  279.36 63.916 279.384 64 ;
    END
  END k_rsp_data[211]
  PIN k_rsp_data[212]
    DIRECTION OUTPUT ;
    USE SIGNAL ;
    PORT
      LAYER M5 ;
        RECT  279.456 63.916 279.48 64 ;
    END
  END k_rsp_data[212]
  PIN k_rsp_data[213]
    DIRECTION OUTPUT ;
    USE SIGNAL ;
    PORT
      LAYER M5 ;
        RECT  279.552 63.916 279.576 64 ;
    END
  END k_rsp_data[213]
  PIN k_rsp_data[214]
    DIRECTION OUTPUT ;
    USE SIGNAL ;
    PORT
      LAYER M5 ;
        RECT  279.648 63.916 279.672 64 ;
    END
  END k_rsp_data[214]
  PIN k_rsp_data[215]
    DIRECTION OUTPUT ;
    USE SIGNAL ;
    PORT
      LAYER M5 ;
        RECT  279.744 63.916 279.768 64 ;
    END
  END k_rsp_data[215]
  PIN k_rsp_data[216]
    DIRECTION OUTPUT ;
    USE SIGNAL ;
    PORT
      LAYER M5 ;
        RECT  279.84 63.916 279.864 64 ;
    END
  END k_rsp_data[216]
  PIN k_rsp_data[217]
    DIRECTION OUTPUT ;
    USE SIGNAL ;
    PORT
      LAYER M5 ;
        RECT  279.936 63.916 279.96 64 ;
    END
  END k_rsp_data[217]
  PIN k_rsp_data[218]
    DIRECTION OUTPUT ;
    USE SIGNAL ;
    PORT
      LAYER M5 ;
        RECT  280.032 63.916 280.056 64 ;
    END
  END k_rsp_data[218]
  PIN k_rsp_data[219]
    DIRECTION OUTPUT ;
    USE SIGNAL ;
    PORT
      LAYER M5 ;
        RECT  280.128 63.916 280.152 64 ;
    END
  END k_rsp_data[219]
  PIN k_rsp_data[21]
    DIRECTION OUTPUT ;
    USE SIGNAL ;
    PORT
      LAYER M5 ;
        RECT  261.12 63.916 261.144 64 ;
    END
  END k_rsp_data[21]
  PIN k_rsp_data[220]
    DIRECTION OUTPUT ;
    USE SIGNAL ;
    PORT
      LAYER M5 ;
        RECT  280.224 63.916 280.248 64 ;
    END
  END k_rsp_data[220]
  PIN k_rsp_data[221]
    DIRECTION OUTPUT ;
    USE SIGNAL ;
    PORT
      LAYER M5 ;
        RECT  280.32 63.916 280.344 64 ;
    END
  END k_rsp_data[221]
  PIN k_rsp_data[222]
    DIRECTION OUTPUT ;
    USE SIGNAL ;
    PORT
      LAYER M5 ;
        RECT  280.416 63.916 280.44 64 ;
    END
  END k_rsp_data[222]
  PIN k_rsp_data[223]
    DIRECTION OUTPUT ;
    USE SIGNAL ;
    PORT
      LAYER M5 ;
        RECT  280.512 63.916 280.536 64 ;
    END
  END k_rsp_data[223]
  PIN k_rsp_data[224]
    DIRECTION OUTPUT ;
    USE SIGNAL ;
    PORT
      LAYER M5 ;
        RECT  280.608 63.916 280.632 64 ;
    END
  END k_rsp_data[224]
  PIN k_rsp_data[225]
    DIRECTION OUTPUT ;
    USE SIGNAL ;
    PORT
      LAYER M5 ;
        RECT  280.704 63.916 280.728 64 ;
    END
  END k_rsp_data[225]
  PIN k_rsp_data[226]
    DIRECTION OUTPUT ;
    USE SIGNAL ;
    PORT
      LAYER M5 ;
        RECT  280.8 63.916 280.824 64 ;
    END
  END k_rsp_data[226]
  PIN k_rsp_data[227]
    DIRECTION OUTPUT ;
    USE SIGNAL ;
    PORT
      LAYER M5 ;
        RECT  280.896 63.916 280.92 64 ;
    END
  END k_rsp_data[227]
  PIN k_rsp_data[228]
    DIRECTION OUTPUT ;
    USE SIGNAL ;
    PORT
      LAYER M5 ;
        RECT  280.992 63.916 281.016 64 ;
    END
  END k_rsp_data[228]
  PIN k_rsp_data[229]
    DIRECTION OUTPUT ;
    USE SIGNAL ;
    PORT
      LAYER M5 ;
        RECT  281.088 63.916 281.112 64 ;
    END
  END k_rsp_data[229]
  PIN k_rsp_data[22]
    DIRECTION OUTPUT ;
    USE SIGNAL ;
    PORT
      LAYER M5 ;
        RECT  261.216 63.916 261.24 64 ;
    END
  END k_rsp_data[22]
  PIN k_rsp_data[230]
    DIRECTION OUTPUT ;
    USE SIGNAL ;
    PORT
      LAYER M5 ;
        RECT  281.184 63.916 281.208 64 ;
    END
  END k_rsp_data[230]
  PIN k_rsp_data[231]
    DIRECTION OUTPUT ;
    USE SIGNAL ;
    PORT
      LAYER M5 ;
        RECT  281.28 63.916 281.304 64 ;
    END
  END k_rsp_data[231]
  PIN k_rsp_data[232]
    DIRECTION OUTPUT ;
    USE SIGNAL ;
    PORT
      LAYER M5 ;
        RECT  281.376 63.916 281.4 64 ;
    END
  END k_rsp_data[232]
  PIN k_rsp_data[233]
    DIRECTION OUTPUT ;
    USE SIGNAL ;
    PORT
      LAYER M5 ;
        RECT  281.472 63.916 281.496 64 ;
    END
  END k_rsp_data[233]
  PIN k_rsp_data[234]
    DIRECTION OUTPUT ;
    USE SIGNAL ;
    PORT
      LAYER M5 ;
        RECT  281.568 63.916 281.592 64 ;
    END
  END k_rsp_data[234]
  PIN k_rsp_data[235]
    DIRECTION OUTPUT ;
    USE SIGNAL ;
    PORT
      LAYER M5 ;
        RECT  281.664 63.916 281.688 64 ;
    END
  END k_rsp_data[235]
  PIN k_rsp_data[236]
    DIRECTION OUTPUT ;
    USE SIGNAL ;
    PORT
      LAYER M5 ;
        RECT  281.76 63.916 281.784 64 ;
    END
  END k_rsp_data[236]
  PIN k_rsp_data[237]
    DIRECTION OUTPUT ;
    USE SIGNAL ;
    PORT
      LAYER M5 ;
        RECT  281.856 63.916 281.88 64 ;
    END
  END k_rsp_data[237]
  PIN k_rsp_data[238]
    DIRECTION OUTPUT ;
    USE SIGNAL ;
    PORT
      LAYER M5 ;
        RECT  281.952 63.916 281.976 64 ;
    END
  END k_rsp_data[238]
  PIN k_rsp_data[239]
    DIRECTION OUTPUT ;
    USE SIGNAL ;
    PORT
      LAYER M5 ;
        RECT  282.048 63.916 282.072 64 ;
    END
  END k_rsp_data[239]
  PIN k_rsp_data[23]
    DIRECTION OUTPUT ;
    USE SIGNAL ;
    PORT
      LAYER M5 ;
        RECT  261.312 63.916 261.336 64 ;
    END
  END k_rsp_data[23]
  PIN k_rsp_data[240]
    DIRECTION OUTPUT ;
    USE SIGNAL ;
    PORT
      LAYER M5 ;
        RECT  282.144 63.916 282.168 64 ;
    END
  END k_rsp_data[240]
  PIN k_rsp_data[241]
    DIRECTION OUTPUT ;
    USE SIGNAL ;
    PORT
      LAYER M5 ;
        RECT  282.24 63.916 282.264 64 ;
    END
  END k_rsp_data[241]
  PIN k_rsp_data[242]
    DIRECTION OUTPUT ;
    USE SIGNAL ;
    PORT
      LAYER M5 ;
        RECT  282.336 63.916 282.36 64 ;
    END
  END k_rsp_data[242]
  PIN k_rsp_data[243]
    DIRECTION OUTPUT ;
    USE SIGNAL ;
    PORT
      LAYER M5 ;
        RECT  282.432 63.916 282.456 64 ;
    END
  END k_rsp_data[243]
  PIN k_rsp_data[244]
    DIRECTION OUTPUT ;
    USE SIGNAL ;
    PORT
      LAYER M5 ;
        RECT  282.528 63.916 282.552 64 ;
    END
  END k_rsp_data[244]
  PIN k_rsp_data[245]
    DIRECTION OUTPUT ;
    USE SIGNAL ;
    PORT
      LAYER M5 ;
        RECT  282.624 63.916 282.648 64 ;
    END
  END k_rsp_data[245]
  PIN k_rsp_data[246]
    DIRECTION OUTPUT ;
    USE SIGNAL ;
    PORT
      LAYER M5 ;
        RECT  282.72 63.916 282.744 64 ;
    END
  END k_rsp_data[246]
  PIN k_rsp_data[247]
    DIRECTION OUTPUT ;
    USE SIGNAL ;
    PORT
      LAYER M5 ;
        RECT  282.816 63.916 282.84 64 ;
    END
  END k_rsp_data[247]
  PIN k_rsp_data[248]
    DIRECTION OUTPUT ;
    USE SIGNAL ;
    PORT
      LAYER M5 ;
        RECT  282.912 63.916 282.936 64 ;
    END
  END k_rsp_data[248]
  PIN k_rsp_data[249]
    DIRECTION OUTPUT ;
    USE SIGNAL ;
    PORT
      LAYER M5 ;
        RECT  283.008 63.916 283.032 64 ;
    END
  END k_rsp_data[249]
  PIN k_rsp_data[24]
    DIRECTION OUTPUT ;
    USE SIGNAL ;
    PORT
      LAYER M5 ;
        RECT  261.408 63.916 261.432 64 ;
    END
  END k_rsp_data[24]
  PIN k_rsp_data[250]
    DIRECTION OUTPUT ;
    USE SIGNAL ;
    PORT
      LAYER M5 ;
        RECT  283.104 63.916 283.128 64 ;
    END
  END k_rsp_data[250]
  PIN k_rsp_data[251]
    DIRECTION OUTPUT ;
    USE SIGNAL ;
    PORT
      LAYER M5 ;
        RECT  283.2 63.916 283.224 64 ;
    END
  END k_rsp_data[251]
  PIN k_rsp_data[252]
    DIRECTION OUTPUT ;
    USE SIGNAL ;
    PORT
      LAYER M5 ;
        RECT  283.296 63.916 283.32 64 ;
    END
  END k_rsp_data[252]
  PIN k_rsp_data[253]
    DIRECTION OUTPUT ;
    USE SIGNAL ;
    PORT
      LAYER M5 ;
        RECT  283.392 63.916 283.416 64 ;
    END
  END k_rsp_data[253]
  PIN k_rsp_data[254]
    DIRECTION OUTPUT ;
    USE SIGNAL ;
    PORT
      LAYER M5 ;
        RECT  283.488 63.916 283.512 64 ;
    END
  END k_rsp_data[254]
  PIN k_rsp_data[255]
    DIRECTION OUTPUT ;
    USE SIGNAL ;
    PORT
      LAYER M5 ;
        RECT  283.584 63.916 283.608 64 ;
    END
  END k_rsp_data[255]
  PIN k_rsp_data[25]
    DIRECTION OUTPUT ;
    USE SIGNAL ;
    PORT
      LAYER M5 ;
        RECT  261.504 63.916 261.528 64 ;
    END
  END k_rsp_data[25]
  PIN k_rsp_data[26]
    DIRECTION OUTPUT ;
    USE SIGNAL ;
    PORT
      LAYER M5 ;
        RECT  261.6 63.916 261.624 64 ;
    END
  END k_rsp_data[26]
  PIN k_rsp_data[27]
    DIRECTION OUTPUT ;
    USE SIGNAL ;
    PORT
      LAYER M5 ;
        RECT  261.696 63.916 261.72 64 ;
    END
  END k_rsp_data[27]
  PIN k_rsp_data[28]
    DIRECTION OUTPUT ;
    USE SIGNAL ;
    PORT
      LAYER M5 ;
        RECT  261.792 63.916 261.816 64 ;
    END
  END k_rsp_data[28]
  PIN k_rsp_data[29]
    DIRECTION OUTPUT ;
    USE SIGNAL ;
    PORT
      LAYER M5 ;
        RECT  261.888 63.916 261.912 64 ;
    END
  END k_rsp_data[29]
  PIN k_rsp_data[2]
    DIRECTION OUTPUT ;
    USE SIGNAL ;
    PORT
      LAYER M5 ;
        RECT  259.296 63.916 259.32 64 ;
    END
  END k_rsp_data[2]
  PIN k_rsp_data[30]
    DIRECTION OUTPUT ;
    USE SIGNAL ;
    PORT
      LAYER M5 ;
        RECT  261.984 63.916 262.008 64 ;
    END
  END k_rsp_data[30]
  PIN k_rsp_data[31]
    DIRECTION OUTPUT ;
    USE SIGNAL ;
    PORT
      LAYER M5 ;
        RECT  262.08 63.916 262.104 64 ;
    END
  END k_rsp_data[31]
  PIN k_rsp_data[32]
    DIRECTION OUTPUT ;
    USE SIGNAL ;
    PORT
      LAYER M5 ;
        RECT  262.176 63.916 262.2 64 ;
    END
  END k_rsp_data[32]
  PIN k_rsp_data[33]
    DIRECTION OUTPUT ;
    USE SIGNAL ;
    PORT
      LAYER M5 ;
        RECT  262.272 63.916 262.296 64 ;
    END
  END k_rsp_data[33]
  PIN k_rsp_data[34]
    DIRECTION OUTPUT ;
    USE SIGNAL ;
    PORT
      LAYER M5 ;
        RECT  262.368 63.916 262.392 64 ;
    END
  END k_rsp_data[34]
  PIN k_rsp_data[35]
    DIRECTION OUTPUT ;
    USE SIGNAL ;
    PORT
      LAYER M5 ;
        RECT  262.464 63.916 262.488 64 ;
    END
  END k_rsp_data[35]
  PIN k_rsp_data[36]
    DIRECTION OUTPUT ;
    USE SIGNAL ;
    PORT
      LAYER M5 ;
        RECT  262.56 63.916 262.584 64 ;
    END
  END k_rsp_data[36]
  PIN k_rsp_data[37]
    DIRECTION OUTPUT ;
    USE SIGNAL ;
    PORT
      LAYER M5 ;
        RECT  262.656 63.916 262.68 64 ;
    END
  END k_rsp_data[37]
  PIN k_rsp_data[38]
    DIRECTION OUTPUT ;
    USE SIGNAL ;
    PORT
      LAYER M5 ;
        RECT  262.752 63.916 262.776 64 ;
    END
  END k_rsp_data[38]
  PIN k_rsp_data[39]
    DIRECTION OUTPUT ;
    USE SIGNAL ;
    PORT
      LAYER M5 ;
        RECT  262.848 63.916 262.872 64 ;
    END
  END k_rsp_data[39]
  PIN k_rsp_data[3]
    DIRECTION OUTPUT ;
    USE SIGNAL ;
    PORT
      LAYER M5 ;
        RECT  259.392 63.916 259.416 64 ;
    END
  END k_rsp_data[3]
  PIN k_rsp_data[40]
    DIRECTION OUTPUT ;
    USE SIGNAL ;
    PORT
      LAYER M5 ;
        RECT  262.944 63.916 262.968 64 ;
    END
  END k_rsp_data[40]
  PIN k_rsp_data[41]
    DIRECTION OUTPUT ;
    USE SIGNAL ;
    PORT
      LAYER M5 ;
        RECT  263.04 63.916 263.064 64 ;
    END
  END k_rsp_data[41]
  PIN k_rsp_data[42]
    DIRECTION OUTPUT ;
    USE SIGNAL ;
    PORT
      LAYER M5 ;
        RECT  263.136 63.916 263.16 64 ;
    END
  END k_rsp_data[42]
  PIN k_rsp_data[43]
    DIRECTION OUTPUT ;
    USE SIGNAL ;
    PORT
      LAYER M5 ;
        RECT  263.232 63.916 263.256 64 ;
    END
  END k_rsp_data[43]
  PIN k_rsp_data[44]
    DIRECTION OUTPUT ;
    USE SIGNAL ;
    PORT
      LAYER M5 ;
        RECT  263.328 63.916 263.352 64 ;
    END
  END k_rsp_data[44]
  PIN k_rsp_data[45]
    DIRECTION OUTPUT ;
    USE SIGNAL ;
    PORT
      LAYER M5 ;
        RECT  263.424 63.916 263.448 64 ;
    END
  END k_rsp_data[45]
  PIN k_rsp_data[46]
    DIRECTION OUTPUT ;
    USE SIGNAL ;
    PORT
      LAYER M5 ;
        RECT  263.52 63.916 263.544 64 ;
    END
  END k_rsp_data[46]
  PIN k_rsp_data[47]
    DIRECTION OUTPUT ;
    USE SIGNAL ;
    PORT
      LAYER M5 ;
        RECT  263.616 63.916 263.64 64 ;
    END
  END k_rsp_data[47]
  PIN k_rsp_data[48]
    DIRECTION OUTPUT ;
    USE SIGNAL ;
    PORT
      LAYER M5 ;
        RECT  263.712 63.916 263.736 64 ;
    END
  END k_rsp_data[48]
  PIN k_rsp_data[49]
    DIRECTION OUTPUT ;
    USE SIGNAL ;
    PORT
      LAYER M5 ;
        RECT  263.808 63.916 263.832 64 ;
    END
  END k_rsp_data[49]
  PIN k_rsp_data[4]
    DIRECTION OUTPUT ;
    USE SIGNAL ;
    PORT
      LAYER M5 ;
        RECT  259.488 63.916 259.512 64 ;
    END
  END k_rsp_data[4]
  PIN k_rsp_data[50]
    DIRECTION OUTPUT ;
    USE SIGNAL ;
    PORT
      LAYER M5 ;
        RECT  263.904 63.916 263.928 64 ;
    END
  END k_rsp_data[50]
  PIN k_rsp_data[51]
    DIRECTION OUTPUT ;
    USE SIGNAL ;
    PORT
      LAYER M5 ;
        RECT  264 63.916 264.024 64 ;
    END
  END k_rsp_data[51]
  PIN k_rsp_data[52]
    DIRECTION OUTPUT ;
    USE SIGNAL ;
    PORT
      LAYER M5 ;
        RECT  264.096 63.916 264.12 64 ;
    END
  END k_rsp_data[52]
  PIN k_rsp_data[53]
    DIRECTION OUTPUT ;
    USE SIGNAL ;
    PORT
      LAYER M5 ;
        RECT  264.192 63.916 264.216 64 ;
    END
  END k_rsp_data[53]
  PIN k_rsp_data[54]
    DIRECTION OUTPUT ;
    USE SIGNAL ;
    PORT
      LAYER M5 ;
        RECT  264.288 63.916 264.312 64 ;
    END
  END k_rsp_data[54]
  PIN k_rsp_data[55]
    DIRECTION OUTPUT ;
    USE SIGNAL ;
    PORT
      LAYER M5 ;
        RECT  264.384 63.916 264.408 64 ;
    END
  END k_rsp_data[55]
  PIN k_rsp_data[56]
    DIRECTION OUTPUT ;
    USE SIGNAL ;
    PORT
      LAYER M5 ;
        RECT  264.48 63.916 264.504 64 ;
    END
  END k_rsp_data[56]
  PIN k_rsp_data[57]
    DIRECTION OUTPUT ;
    USE SIGNAL ;
    PORT
      LAYER M5 ;
        RECT  264.576 63.916 264.6 64 ;
    END
  END k_rsp_data[57]
  PIN k_rsp_data[58]
    DIRECTION OUTPUT ;
    USE SIGNAL ;
    PORT
      LAYER M5 ;
        RECT  264.672 63.916 264.696 64 ;
    END
  END k_rsp_data[58]
  PIN k_rsp_data[59]
    DIRECTION OUTPUT ;
    USE SIGNAL ;
    PORT
      LAYER M5 ;
        RECT  264.768 63.916 264.792 64 ;
    END
  END k_rsp_data[59]
  PIN k_rsp_data[5]
    DIRECTION OUTPUT ;
    USE SIGNAL ;
    PORT
      LAYER M5 ;
        RECT  259.584 63.916 259.608 64 ;
    END
  END k_rsp_data[5]
  PIN k_rsp_data[60]
    DIRECTION OUTPUT ;
    USE SIGNAL ;
    PORT
      LAYER M5 ;
        RECT  264.864 63.916 264.888 64 ;
    END
  END k_rsp_data[60]
  PIN k_rsp_data[61]
    DIRECTION OUTPUT ;
    USE SIGNAL ;
    PORT
      LAYER M5 ;
        RECT  264.96 63.916 264.984 64 ;
    END
  END k_rsp_data[61]
  PIN k_rsp_data[62]
    DIRECTION OUTPUT ;
    USE SIGNAL ;
    PORT
      LAYER M5 ;
        RECT  265.056 63.916 265.08 64 ;
    END
  END k_rsp_data[62]
  PIN k_rsp_data[63]
    DIRECTION OUTPUT ;
    USE SIGNAL ;
    PORT
      LAYER M5 ;
        RECT  265.152 63.916 265.176 64 ;
    END
  END k_rsp_data[63]
  PIN k_rsp_data[64]
    DIRECTION OUTPUT ;
    USE SIGNAL ;
    PORT
      LAYER M5 ;
        RECT  265.248 63.916 265.272 64 ;
    END
  END k_rsp_data[64]
  PIN k_rsp_data[65]
    DIRECTION OUTPUT ;
    USE SIGNAL ;
    PORT
      LAYER M5 ;
        RECT  265.344 63.916 265.368 64 ;
    END
  END k_rsp_data[65]
  PIN k_rsp_data[66]
    DIRECTION OUTPUT ;
    USE SIGNAL ;
    PORT
      LAYER M5 ;
        RECT  265.44 63.916 265.464 64 ;
    END
  END k_rsp_data[66]
  PIN k_rsp_data[67]
    DIRECTION OUTPUT ;
    USE SIGNAL ;
    PORT
      LAYER M5 ;
        RECT  265.536 63.916 265.56 64 ;
    END
  END k_rsp_data[67]
  PIN k_rsp_data[68]
    DIRECTION OUTPUT ;
    USE SIGNAL ;
    PORT
      LAYER M5 ;
        RECT  265.632 63.916 265.656 64 ;
    END
  END k_rsp_data[68]
  PIN k_rsp_data[69]
    DIRECTION OUTPUT ;
    USE SIGNAL ;
    PORT
      LAYER M5 ;
        RECT  265.728 63.916 265.752 64 ;
    END
  END k_rsp_data[69]
  PIN k_rsp_data[6]
    DIRECTION OUTPUT ;
    USE SIGNAL ;
    PORT
      LAYER M5 ;
        RECT  259.68 63.916 259.704 64 ;
    END
  END k_rsp_data[6]
  PIN k_rsp_data[70]
    DIRECTION OUTPUT ;
    USE SIGNAL ;
    PORT
      LAYER M5 ;
        RECT  265.824 63.916 265.848 64 ;
    END
  END k_rsp_data[70]
  PIN k_rsp_data[71]
    DIRECTION OUTPUT ;
    USE SIGNAL ;
    PORT
      LAYER M5 ;
        RECT  265.92 63.916 265.944 64 ;
    END
  END k_rsp_data[71]
  PIN k_rsp_data[72]
    DIRECTION OUTPUT ;
    USE SIGNAL ;
    PORT
      LAYER M5 ;
        RECT  266.016 63.916 266.04 64 ;
    END
  END k_rsp_data[72]
  PIN k_rsp_data[73]
    DIRECTION OUTPUT ;
    USE SIGNAL ;
    PORT
      LAYER M5 ;
        RECT  266.112 63.916 266.136 64 ;
    END
  END k_rsp_data[73]
  PIN k_rsp_data[74]
    DIRECTION OUTPUT ;
    USE SIGNAL ;
    PORT
      LAYER M5 ;
        RECT  266.208 63.916 266.232 64 ;
    END
  END k_rsp_data[74]
  PIN k_rsp_data[75]
    DIRECTION OUTPUT ;
    USE SIGNAL ;
    PORT
      LAYER M5 ;
        RECT  266.304 63.916 266.328 64 ;
    END
  END k_rsp_data[75]
  PIN k_rsp_data[76]
    DIRECTION OUTPUT ;
    USE SIGNAL ;
    PORT
      LAYER M5 ;
        RECT  266.4 63.916 266.424 64 ;
    END
  END k_rsp_data[76]
  PIN k_rsp_data[77]
    DIRECTION OUTPUT ;
    USE SIGNAL ;
    PORT
      LAYER M5 ;
        RECT  266.496 63.916 266.52 64 ;
    END
  END k_rsp_data[77]
  PIN k_rsp_data[78]
    DIRECTION OUTPUT ;
    USE SIGNAL ;
    PORT
      LAYER M5 ;
        RECT  266.592 63.916 266.616 64 ;
    END
  END k_rsp_data[78]
  PIN k_rsp_data[79]
    DIRECTION OUTPUT ;
    USE SIGNAL ;
    PORT
      LAYER M5 ;
        RECT  266.688 63.916 266.712 64 ;
    END
  END k_rsp_data[79]
  PIN k_rsp_data[7]
    DIRECTION OUTPUT ;
    USE SIGNAL ;
    PORT
      LAYER M5 ;
        RECT  259.776 63.916 259.8 64 ;
    END
  END k_rsp_data[7]
  PIN k_rsp_data[80]
    DIRECTION OUTPUT ;
    USE SIGNAL ;
    PORT
      LAYER M5 ;
        RECT  266.784 63.916 266.808 64 ;
    END
  END k_rsp_data[80]
  PIN k_rsp_data[81]
    DIRECTION OUTPUT ;
    USE SIGNAL ;
    PORT
      LAYER M5 ;
        RECT  266.88 63.916 266.904 64 ;
    END
  END k_rsp_data[81]
  PIN k_rsp_data[82]
    DIRECTION OUTPUT ;
    USE SIGNAL ;
    PORT
      LAYER M5 ;
        RECT  266.976 63.916 267 64 ;
    END
  END k_rsp_data[82]
  PIN k_rsp_data[83]
    DIRECTION OUTPUT ;
    USE SIGNAL ;
    PORT
      LAYER M5 ;
        RECT  267.072 63.916 267.096 64 ;
    END
  END k_rsp_data[83]
  PIN k_rsp_data[84]
    DIRECTION OUTPUT ;
    USE SIGNAL ;
    PORT
      LAYER M5 ;
        RECT  267.168 63.916 267.192 64 ;
    END
  END k_rsp_data[84]
  PIN k_rsp_data[85]
    DIRECTION OUTPUT ;
    USE SIGNAL ;
    PORT
      LAYER M5 ;
        RECT  267.264 63.916 267.288 64 ;
    END
  END k_rsp_data[85]
  PIN k_rsp_data[86]
    DIRECTION OUTPUT ;
    USE SIGNAL ;
    PORT
      LAYER M5 ;
        RECT  267.36 63.916 267.384 64 ;
    END
  END k_rsp_data[86]
  PIN k_rsp_data[87]
    DIRECTION OUTPUT ;
    USE SIGNAL ;
    PORT
      LAYER M5 ;
        RECT  267.456 63.916 267.48 64 ;
    END
  END k_rsp_data[87]
  PIN k_rsp_data[88]
    DIRECTION OUTPUT ;
    USE SIGNAL ;
    PORT
      LAYER M5 ;
        RECT  267.552 63.916 267.576 64 ;
    END
  END k_rsp_data[88]
  PIN k_rsp_data[89]
    DIRECTION OUTPUT ;
    USE SIGNAL ;
    PORT
      LAYER M5 ;
        RECT  267.648 63.916 267.672 64 ;
    END
  END k_rsp_data[89]
  PIN k_rsp_data[8]
    DIRECTION OUTPUT ;
    USE SIGNAL ;
    PORT
      LAYER M5 ;
        RECT  259.872 63.916 259.896 64 ;
    END
  END k_rsp_data[8]
  PIN k_rsp_data[90]
    DIRECTION OUTPUT ;
    USE SIGNAL ;
    PORT
      LAYER M5 ;
        RECT  267.744 63.916 267.768 64 ;
    END
  END k_rsp_data[90]
  PIN k_rsp_data[91]
    DIRECTION OUTPUT ;
    USE SIGNAL ;
    PORT
      LAYER M5 ;
        RECT  267.84 63.916 267.864 64 ;
    END
  END k_rsp_data[91]
  PIN k_rsp_data[92]
    DIRECTION OUTPUT ;
    USE SIGNAL ;
    PORT
      LAYER M5 ;
        RECT  267.936 63.916 267.96 64 ;
    END
  END k_rsp_data[92]
  PIN k_rsp_data[93]
    DIRECTION OUTPUT ;
    USE SIGNAL ;
    PORT
      LAYER M5 ;
        RECT  268.032 63.916 268.056 64 ;
    END
  END k_rsp_data[93]
  PIN k_rsp_data[94]
    DIRECTION OUTPUT ;
    USE SIGNAL ;
    PORT
      LAYER M5 ;
        RECT  268.128 63.916 268.152 64 ;
    END
  END k_rsp_data[94]
  PIN k_rsp_data[95]
    DIRECTION OUTPUT ;
    USE SIGNAL ;
    PORT
      LAYER M5 ;
        RECT  268.224 63.916 268.248 64 ;
    END
  END k_rsp_data[95]
  PIN k_rsp_data[96]
    DIRECTION OUTPUT ;
    USE SIGNAL ;
    PORT
      LAYER M5 ;
        RECT  268.32 63.916 268.344 64 ;
    END
  END k_rsp_data[96]
  PIN k_rsp_data[97]
    DIRECTION OUTPUT ;
    USE SIGNAL ;
    PORT
      LAYER M5 ;
        RECT  268.416 63.916 268.44 64 ;
    END
  END k_rsp_data[97]
  PIN k_rsp_data[98]
    DIRECTION OUTPUT ;
    USE SIGNAL ;
    PORT
      LAYER M5 ;
        RECT  268.512 63.916 268.536 64 ;
    END
  END k_rsp_data[98]
  PIN k_rsp_data[99]
    DIRECTION OUTPUT ;
    USE SIGNAL ;
    PORT
      LAYER M5 ;
        RECT  268.608 63.916 268.632 64 ;
    END
  END k_rsp_data[99]
  PIN k_rsp_data[9]
    DIRECTION OUTPUT ;
    USE SIGNAL ;
    PORT
      LAYER M5 ;
        RECT  259.968 63.916 259.992 64 ;
    END
  END k_rsp_data[9]
  PIN k_rsp_rdy
    DIRECTION INPUT ;
    USE SIGNAL ;
    PORT
      LAYER M5 ;
        RECT  283.68 63.916 283.704 64 ;
    END
  END k_rsp_rdy
  PIN k_rsp_tag[0]
    DIRECTION OUTPUT ;
    USE SIGNAL ;
    PORT
      LAYER M5 ;
        RECT  283.776 63.916 283.8 64 ;
    END
  END k_rsp_tag[0]
  PIN k_rsp_tag[10]
    DIRECTION OUTPUT ;
    USE SIGNAL ;
    PORT
      LAYER M5 ;
        RECT  284.736 63.916 284.76 64 ;
    END
  END k_rsp_tag[10]
  PIN k_rsp_tag[11]
    DIRECTION OUTPUT ;
    USE SIGNAL ;
    PORT
      LAYER M5 ;
        RECT  284.832 63.916 284.856 64 ;
    END
  END k_rsp_tag[11]
  PIN k_rsp_tag[12]
    DIRECTION OUTPUT ;
    USE SIGNAL ;
    PORT
      LAYER M5 ;
        RECT  284.928 63.916 284.952 64 ;
    END
  END k_rsp_tag[12]
  PIN k_rsp_tag[13]
    DIRECTION OUTPUT ;
    USE SIGNAL ;
    PORT
      LAYER M5 ;
        RECT  285.024 63.916 285.048 64 ;
    END
  END k_rsp_tag[13]
  PIN k_rsp_tag[14]
    DIRECTION OUTPUT ;
    USE SIGNAL ;
    PORT
      LAYER M5 ;
        RECT  285.12 63.916 285.144 64 ;
    END
  END k_rsp_tag[14]
  PIN k_rsp_tag[15]
    DIRECTION OUTPUT ;
    USE SIGNAL ;
    PORT
      LAYER M5 ;
        RECT  285.216 63.916 285.24 64 ;
    END
  END k_rsp_tag[15]
  PIN k_rsp_tag[1]
    DIRECTION OUTPUT ;
    USE SIGNAL ;
    PORT
      LAYER M5 ;
        RECT  283.872 63.916 283.896 64 ;
    END
  END k_rsp_tag[1]
  PIN k_rsp_tag[2]
    DIRECTION OUTPUT ;
    USE SIGNAL ;
    PORT
      LAYER M5 ;
        RECT  283.968 63.916 283.992 64 ;
    END
  END k_rsp_tag[2]
  PIN k_rsp_tag[3]
    DIRECTION OUTPUT ;
    USE SIGNAL ;
    PORT
      LAYER M5 ;
        RECT  284.064 63.916 284.088 64 ;
    END
  END k_rsp_tag[3]
  PIN k_rsp_tag[4]
    DIRECTION OUTPUT ;
    USE SIGNAL ;
    PORT
      LAYER M5 ;
        RECT  284.16 63.916 284.184 64 ;
    END
  END k_rsp_tag[4]
  PIN k_rsp_tag[5]
    DIRECTION OUTPUT ;
    USE SIGNAL ;
    PORT
      LAYER M5 ;
        RECT  284.256 63.916 284.28 64 ;
    END
  END k_rsp_tag[5]
  PIN k_rsp_tag[6]
    DIRECTION OUTPUT ;
    USE SIGNAL ;
    PORT
      LAYER M5 ;
        RECT  284.352 63.916 284.376 64 ;
    END
  END k_rsp_tag[6]
  PIN k_rsp_tag[7]
    DIRECTION OUTPUT ;
    USE SIGNAL ;
    PORT
      LAYER M5 ;
        RECT  284.448 63.916 284.472 64 ;
    END
  END k_rsp_tag[7]
  PIN k_rsp_tag[8]
    DIRECTION OUTPUT ;
    USE SIGNAL ;
    PORT
      LAYER M5 ;
        RECT  284.544 63.916 284.568 64 ;
    END
  END k_rsp_tag[8]
  PIN k_rsp_tag[9]
    DIRECTION OUTPUT ;
    USE SIGNAL ;
    PORT
      LAYER M5 ;
        RECT  284.64 63.916 284.664 64 ;
    END
  END k_rsp_tag[9]
  PIN k_rsp_v
    DIRECTION OUTPUT ;
    USE SIGNAL ;
    PORT
      LAYER M5 ;
        RECT  285.312 63.916 285.336 64 ;
    END
  END k_rsp_v
  PIN k_tag[0]
    DIRECTION INPUT ;
    USE SIGNAL ;
    PORT
      LAYER M5 ;
        RECT  285.408 63.916 285.432 64 ;
    END
  END k_tag[0]
  PIN k_tag[10]
    DIRECTION INPUT ;
    USE SIGNAL ;
    PORT
      LAYER M5 ;
        RECT  286.368 63.916 286.392 64 ;
    END
  END k_tag[10]
  PIN k_tag[11]
    DIRECTION INPUT ;
    USE SIGNAL ;
    PORT
      LAYER M5 ;
        RECT  286.464 63.916 286.488 64 ;
    END
  END k_tag[11]
  PIN k_tag[12]
    DIRECTION INPUT ;
    USE SIGNAL ;
    PORT
      LAYER M5 ;
        RECT  286.56 63.916 286.584 64 ;
    END
  END k_tag[12]
  PIN k_tag[13]
    DIRECTION INPUT ;
    USE SIGNAL ;
    PORT
      LAYER M5 ;
        RECT  286.656 63.916 286.68 64 ;
    END
  END k_tag[13]
  PIN k_tag[14]
    DIRECTION INPUT ;
    USE SIGNAL ;
    PORT
      LAYER M5 ;
        RECT  286.752 63.916 286.776 64 ;
    END
  END k_tag[14]
  PIN k_tag[15]
    DIRECTION INPUT ;
    USE SIGNAL ;
    PORT
      LAYER M5 ;
        RECT  286.848 63.916 286.872 64 ;
    END
  END k_tag[15]
  PIN k_tag[1]
    DIRECTION INPUT ;
    USE SIGNAL ;
    PORT
      LAYER M5 ;
        RECT  285.504 63.916 285.528 64 ;
    END
  END k_tag[1]
  PIN k_tag[2]
    DIRECTION INPUT ;
    USE SIGNAL ;
    PORT
      LAYER M5 ;
        RECT  285.6 63.916 285.624 64 ;
    END
  END k_tag[2]
  PIN k_tag[3]
    DIRECTION INPUT ;
    USE SIGNAL ;
    PORT
      LAYER M5 ;
        RECT  285.696 63.916 285.72 64 ;
    END
  END k_tag[3]
  PIN k_tag[4]
    DIRECTION INPUT ;
    USE SIGNAL ;
    PORT
      LAYER M5 ;
        RECT  285.792 63.916 285.816 64 ;
    END
  END k_tag[4]
  PIN k_tag[5]
    DIRECTION INPUT ;
    USE SIGNAL ;
    PORT
      LAYER M5 ;
        RECT  285.888 63.916 285.912 64 ;
    END
  END k_tag[5]
  PIN k_tag[6]
    DIRECTION INPUT ;
    USE SIGNAL ;
    PORT
      LAYER M5 ;
        RECT  285.984 63.916 286.008 64 ;
    END
  END k_tag[6]
  PIN k_tag[7]
    DIRECTION INPUT ;
    USE SIGNAL ;
    PORT
      LAYER M5 ;
        RECT  286.08 63.916 286.104 64 ;
    END
  END k_tag[7]
  PIN k_tag[8]
    DIRECTION INPUT ;
    USE SIGNAL ;
    PORT
      LAYER M5 ;
        RECT  286.176 63.916 286.2 64 ;
    END
  END k_tag[8]
  PIN k_tag[9]
    DIRECTION INPUT ;
    USE SIGNAL ;
    PORT
      LAYER M5 ;
        RECT  286.272 63.916 286.296 64 ;
    END
  END k_tag[9]
  PIN k_take
    DIRECTION OUTPUT ;
    USE SIGNAL ;
    PORT
      LAYER M5 ;
        RECT  286.944 63.916 286.968 64 ;
    END
  END k_take
  PIN k_v
    DIRECTION INPUT ;
    USE SIGNAL ;
    PORT
      LAYER M5 ;
        RECT  287.04 63.916 287.064 64 ;
    END
  END k_v
  PIN k_wdata[0]
    DIRECTION INPUT ;
    USE SIGNAL ;
    PORT
      LAYER M5 ;
        RECT  287.136 63.916 287.16 64 ;
    END
  END k_wdata[0]
  PIN k_wdata[100]
    DIRECTION INPUT ;
    USE SIGNAL ;
    PORT
      LAYER M5 ;
        RECT  296.736 63.916 296.76 64 ;
    END
  END k_wdata[100]
  PIN k_wdata[101]
    DIRECTION INPUT ;
    USE SIGNAL ;
    PORT
      LAYER M5 ;
        RECT  296.832 63.916 296.856 64 ;
    END
  END k_wdata[101]
  PIN k_wdata[102]
    DIRECTION INPUT ;
    USE SIGNAL ;
    PORT
      LAYER M5 ;
        RECT  296.928 63.916 296.952 64 ;
    END
  END k_wdata[102]
  PIN k_wdata[103]
    DIRECTION INPUT ;
    USE SIGNAL ;
    PORT
      LAYER M5 ;
        RECT  297.024 63.916 297.048 64 ;
    END
  END k_wdata[103]
  PIN k_wdata[104]
    DIRECTION INPUT ;
    USE SIGNAL ;
    PORT
      LAYER M5 ;
        RECT  297.12 63.916 297.144 64 ;
    END
  END k_wdata[104]
  PIN k_wdata[105]
    DIRECTION INPUT ;
    USE SIGNAL ;
    PORT
      LAYER M5 ;
        RECT  297.216 63.916 297.24 64 ;
    END
  END k_wdata[105]
  PIN k_wdata[106]
    DIRECTION INPUT ;
    USE SIGNAL ;
    PORT
      LAYER M5 ;
        RECT  297.312 63.916 297.336 64 ;
    END
  END k_wdata[106]
  PIN k_wdata[107]
    DIRECTION INPUT ;
    USE SIGNAL ;
    PORT
      LAYER M5 ;
        RECT  297.408 63.916 297.432 64 ;
    END
  END k_wdata[107]
  PIN k_wdata[108]
    DIRECTION INPUT ;
    USE SIGNAL ;
    PORT
      LAYER M5 ;
        RECT  297.504 63.916 297.528 64 ;
    END
  END k_wdata[108]
  PIN k_wdata[109]
    DIRECTION INPUT ;
    USE SIGNAL ;
    PORT
      LAYER M5 ;
        RECT  297.6 63.916 297.624 64 ;
    END
  END k_wdata[109]
  PIN k_wdata[10]
    DIRECTION INPUT ;
    USE SIGNAL ;
    PORT
      LAYER M5 ;
        RECT  288.096 63.916 288.12 64 ;
    END
  END k_wdata[10]
  PIN k_wdata[110]
    DIRECTION INPUT ;
    USE SIGNAL ;
    PORT
      LAYER M5 ;
        RECT  297.696 63.916 297.72 64 ;
    END
  END k_wdata[110]
  PIN k_wdata[111]
    DIRECTION INPUT ;
    USE SIGNAL ;
    PORT
      LAYER M5 ;
        RECT  297.792 63.916 297.816 64 ;
    END
  END k_wdata[111]
  PIN k_wdata[112]
    DIRECTION INPUT ;
    USE SIGNAL ;
    PORT
      LAYER M5 ;
        RECT  297.888 63.916 297.912 64 ;
    END
  END k_wdata[112]
  PIN k_wdata[113]
    DIRECTION INPUT ;
    USE SIGNAL ;
    PORT
      LAYER M5 ;
        RECT  297.984 63.916 298.008 64 ;
    END
  END k_wdata[113]
  PIN k_wdata[114]
    DIRECTION INPUT ;
    USE SIGNAL ;
    PORT
      LAYER M5 ;
        RECT  298.08 63.916 298.104 64 ;
    END
  END k_wdata[114]
  PIN k_wdata[115]
    DIRECTION INPUT ;
    USE SIGNAL ;
    PORT
      LAYER M5 ;
        RECT  298.176 63.916 298.2 64 ;
    END
  END k_wdata[115]
  PIN k_wdata[116]
    DIRECTION INPUT ;
    USE SIGNAL ;
    PORT
      LAYER M5 ;
        RECT  298.272 63.916 298.296 64 ;
    END
  END k_wdata[116]
  PIN k_wdata[117]
    DIRECTION INPUT ;
    USE SIGNAL ;
    PORT
      LAYER M5 ;
        RECT  298.368 63.916 298.392 64 ;
    END
  END k_wdata[117]
  PIN k_wdata[118]
    DIRECTION INPUT ;
    USE SIGNAL ;
    PORT
      LAYER M5 ;
        RECT  298.464 63.916 298.488 64 ;
    END
  END k_wdata[118]
  PIN k_wdata[119]
    DIRECTION INPUT ;
    USE SIGNAL ;
    PORT
      LAYER M5 ;
        RECT  298.56 63.916 298.584 64 ;
    END
  END k_wdata[119]
  PIN k_wdata[11]
    DIRECTION INPUT ;
    USE SIGNAL ;
    PORT
      LAYER M5 ;
        RECT  288.192 63.916 288.216 64 ;
    END
  END k_wdata[11]
  PIN k_wdata[120]
    DIRECTION INPUT ;
    USE SIGNAL ;
    PORT
      LAYER M5 ;
        RECT  298.656 63.916 298.68 64 ;
    END
  END k_wdata[120]
  PIN k_wdata[121]
    DIRECTION INPUT ;
    USE SIGNAL ;
    PORT
      LAYER M5 ;
        RECT  298.752 63.916 298.776 64 ;
    END
  END k_wdata[121]
  PIN k_wdata[122]
    DIRECTION INPUT ;
    USE SIGNAL ;
    PORT
      LAYER M5 ;
        RECT  298.848 63.916 298.872 64 ;
    END
  END k_wdata[122]
  PIN k_wdata[123]
    DIRECTION INPUT ;
    USE SIGNAL ;
    PORT
      LAYER M5 ;
        RECT  298.944 63.916 298.968 64 ;
    END
  END k_wdata[123]
  PIN k_wdata[124]
    DIRECTION INPUT ;
    USE SIGNAL ;
    PORT
      LAYER M5 ;
        RECT  299.04 63.916 299.064 64 ;
    END
  END k_wdata[124]
  PIN k_wdata[125]
    DIRECTION INPUT ;
    USE SIGNAL ;
    PORT
      LAYER M5 ;
        RECT  299.136 63.916 299.16 64 ;
    END
  END k_wdata[125]
  PIN k_wdata[126]
    DIRECTION INPUT ;
    USE SIGNAL ;
    PORT
      LAYER M5 ;
        RECT  299.232 63.916 299.256 64 ;
    END
  END k_wdata[126]
  PIN k_wdata[127]
    DIRECTION INPUT ;
    USE SIGNAL ;
    PORT
      LAYER M5 ;
        RECT  299.328 63.916 299.352 64 ;
    END
  END k_wdata[127]
  PIN k_wdata[128]
    DIRECTION INPUT ;
    USE SIGNAL ;
    PORT
      LAYER M5 ;
        RECT  299.424 63.916 299.448 64 ;
    END
  END k_wdata[128]
  PIN k_wdata[129]
    DIRECTION INPUT ;
    USE SIGNAL ;
    PORT
      LAYER M5 ;
        RECT  299.52 63.916 299.544 64 ;
    END
  END k_wdata[129]
  PIN k_wdata[12]
    DIRECTION INPUT ;
    USE SIGNAL ;
    PORT
      LAYER M5 ;
        RECT  288.288 63.916 288.312 64 ;
    END
  END k_wdata[12]
  PIN k_wdata[130]
    DIRECTION INPUT ;
    USE SIGNAL ;
    PORT
      LAYER M5 ;
        RECT  299.616 63.916 299.64 64 ;
    END
  END k_wdata[130]
  PIN k_wdata[131]
    DIRECTION INPUT ;
    USE SIGNAL ;
    PORT
      LAYER M5 ;
        RECT  299.712 63.916 299.736 64 ;
    END
  END k_wdata[131]
  PIN k_wdata[132]
    DIRECTION INPUT ;
    USE SIGNAL ;
    PORT
      LAYER M5 ;
        RECT  299.808 63.916 299.832 64 ;
    END
  END k_wdata[132]
  PIN k_wdata[133]
    DIRECTION INPUT ;
    USE SIGNAL ;
    PORT
      LAYER M5 ;
        RECT  299.904 63.916 299.928 64 ;
    END
  END k_wdata[133]
  PIN k_wdata[134]
    DIRECTION INPUT ;
    USE SIGNAL ;
    PORT
      LAYER M5 ;
        RECT  300 63.916 300.024 64 ;
    END
  END k_wdata[134]
  PIN k_wdata[135]
    DIRECTION INPUT ;
    USE SIGNAL ;
    PORT
      LAYER M5 ;
        RECT  300.096 63.916 300.12 64 ;
    END
  END k_wdata[135]
  PIN k_wdata[136]
    DIRECTION INPUT ;
    USE SIGNAL ;
    PORT
      LAYER M5 ;
        RECT  300.192 63.916 300.216 64 ;
    END
  END k_wdata[136]
  PIN k_wdata[137]
    DIRECTION INPUT ;
    USE SIGNAL ;
    PORT
      LAYER M5 ;
        RECT  300.288 63.916 300.312 64 ;
    END
  END k_wdata[137]
  PIN k_wdata[138]
    DIRECTION INPUT ;
    USE SIGNAL ;
    PORT
      LAYER M5 ;
        RECT  300.384 63.916 300.408 64 ;
    END
  END k_wdata[138]
  PIN k_wdata[139]
    DIRECTION INPUT ;
    USE SIGNAL ;
    PORT
      LAYER M5 ;
        RECT  300.48 63.916 300.504 64 ;
    END
  END k_wdata[139]
  PIN k_wdata[13]
    DIRECTION INPUT ;
    USE SIGNAL ;
    PORT
      LAYER M5 ;
        RECT  288.384 63.916 288.408 64 ;
    END
  END k_wdata[13]
  PIN k_wdata[140]
    DIRECTION INPUT ;
    USE SIGNAL ;
    PORT
      LAYER M5 ;
        RECT  300.576 63.916 300.6 64 ;
    END
  END k_wdata[140]
  PIN k_wdata[141]
    DIRECTION INPUT ;
    USE SIGNAL ;
    PORT
      LAYER M5 ;
        RECT  300.672 63.916 300.696 64 ;
    END
  END k_wdata[141]
  PIN k_wdata[142]
    DIRECTION INPUT ;
    USE SIGNAL ;
    PORT
      LAYER M5 ;
        RECT  300.768 63.916 300.792 64 ;
    END
  END k_wdata[142]
  PIN k_wdata[143]
    DIRECTION INPUT ;
    USE SIGNAL ;
    PORT
      LAYER M5 ;
        RECT  300.864 63.916 300.888 64 ;
    END
  END k_wdata[143]
  PIN k_wdata[144]
    DIRECTION INPUT ;
    USE SIGNAL ;
    PORT
      LAYER M5 ;
        RECT  300.96 63.916 300.984 64 ;
    END
  END k_wdata[144]
  PIN k_wdata[145]
    DIRECTION INPUT ;
    USE SIGNAL ;
    PORT
      LAYER M5 ;
        RECT  301.056 63.916 301.08 64 ;
    END
  END k_wdata[145]
  PIN k_wdata[146]
    DIRECTION INPUT ;
    USE SIGNAL ;
    PORT
      LAYER M5 ;
        RECT  301.152 63.916 301.176 64 ;
    END
  END k_wdata[146]
  PIN k_wdata[147]
    DIRECTION INPUT ;
    USE SIGNAL ;
    PORT
      LAYER M5 ;
        RECT  301.248 63.916 301.272 64 ;
    END
  END k_wdata[147]
  PIN k_wdata[148]
    DIRECTION INPUT ;
    USE SIGNAL ;
    PORT
      LAYER M5 ;
        RECT  301.344 63.916 301.368 64 ;
    END
  END k_wdata[148]
  PIN k_wdata[149]
    DIRECTION INPUT ;
    USE SIGNAL ;
    PORT
      LAYER M5 ;
        RECT  301.44 63.916 301.464 64 ;
    END
  END k_wdata[149]
  PIN k_wdata[14]
    DIRECTION INPUT ;
    USE SIGNAL ;
    PORT
      LAYER M5 ;
        RECT  288.48 63.916 288.504 64 ;
    END
  END k_wdata[14]
  PIN k_wdata[150]
    DIRECTION INPUT ;
    USE SIGNAL ;
    PORT
      LAYER M5 ;
        RECT  301.536 63.916 301.56 64 ;
    END
  END k_wdata[150]
  PIN k_wdata[151]
    DIRECTION INPUT ;
    USE SIGNAL ;
    PORT
      LAYER M5 ;
        RECT  301.632 63.916 301.656 64 ;
    END
  END k_wdata[151]
  PIN k_wdata[152]
    DIRECTION INPUT ;
    USE SIGNAL ;
    PORT
      LAYER M5 ;
        RECT  301.728 63.916 301.752 64 ;
    END
  END k_wdata[152]
  PIN k_wdata[153]
    DIRECTION INPUT ;
    USE SIGNAL ;
    PORT
      LAYER M5 ;
        RECT  301.824 63.916 301.848 64 ;
    END
  END k_wdata[153]
  PIN k_wdata[154]
    DIRECTION INPUT ;
    USE SIGNAL ;
    PORT
      LAYER M5 ;
        RECT  301.92 63.916 301.944 64 ;
    END
  END k_wdata[154]
  PIN k_wdata[155]
    DIRECTION INPUT ;
    USE SIGNAL ;
    PORT
      LAYER M5 ;
        RECT  302.016 63.916 302.04 64 ;
    END
  END k_wdata[155]
  PIN k_wdata[156]
    DIRECTION INPUT ;
    USE SIGNAL ;
    PORT
      LAYER M5 ;
        RECT  302.112 63.916 302.136 64 ;
    END
  END k_wdata[156]
  PIN k_wdata[157]
    DIRECTION INPUT ;
    USE SIGNAL ;
    PORT
      LAYER M5 ;
        RECT  302.208 63.916 302.232 64 ;
    END
  END k_wdata[157]
  PIN k_wdata[158]
    DIRECTION INPUT ;
    USE SIGNAL ;
    PORT
      LAYER M5 ;
        RECT  302.304 63.916 302.328 64 ;
    END
  END k_wdata[158]
  PIN k_wdata[159]
    DIRECTION INPUT ;
    USE SIGNAL ;
    PORT
      LAYER M5 ;
        RECT  302.4 63.916 302.424 64 ;
    END
  END k_wdata[159]
  PIN k_wdata[15]
    DIRECTION INPUT ;
    USE SIGNAL ;
    PORT
      LAYER M5 ;
        RECT  288.576 63.916 288.6 64 ;
    END
  END k_wdata[15]
  PIN k_wdata[160]
    DIRECTION INPUT ;
    USE SIGNAL ;
    PORT
      LAYER M5 ;
        RECT  302.496 63.916 302.52 64 ;
    END
  END k_wdata[160]
  PIN k_wdata[161]
    DIRECTION INPUT ;
    USE SIGNAL ;
    PORT
      LAYER M5 ;
        RECT  302.592 63.916 302.616 64 ;
    END
  END k_wdata[161]
  PIN k_wdata[162]
    DIRECTION INPUT ;
    USE SIGNAL ;
    PORT
      LAYER M5 ;
        RECT  302.688 63.916 302.712 64 ;
    END
  END k_wdata[162]
  PIN k_wdata[163]
    DIRECTION INPUT ;
    USE SIGNAL ;
    PORT
      LAYER M5 ;
        RECT  302.784 63.916 302.808 64 ;
    END
  END k_wdata[163]
  PIN k_wdata[164]
    DIRECTION INPUT ;
    USE SIGNAL ;
    PORT
      LAYER M5 ;
        RECT  302.88 63.916 302.904 64 ;
    END
  END k_wdata[164]
  PIN k_wdata[165]
    DIRECTION INPUT ;
    USE SIGNAL ;
    PORT
      LAYER M5 ;
        RECT  302.976 63.916 303 64 ;
    END
  END k_wdata[165]
  PIN k_wdata[166]
    DIRECTION INPUT ;
    USE SIGNAL ;
    PORT
      LAYER M5 ;
        RECT  303.072 63.916 303.096 64 ;
    END
  END k_wdata[166]
  PIN k_wdata[167]
    DIRECTION INPUT ;
    USE SIGNAL ;
    PORT
      LAYER M5 ;
        RECT  303.168 63.916 303.192 64 ;
    END
  END k_wdata[167]
  PIN k_wdata[168]
    DIRECTION INPUT ;
    USE SIGNAL ;
    PORT
      LAYER M5 ;
        RECT  303.264 63.916 303.288 64 ;
    END
  END k_wdata[168]
  PIN k_wdata[169]
    DIRECTION INPUT ;
    USE SIGNAL ;
    PORT
      LAYER M5 ;
        RECT  303.36 63.916 303.384 64 ;
    END
  END k_wdata[169]
  PIN k_wdata[16]
    DIRECTION INPUT ;
    USE SIGNAL ;
    PORT
      LAYER M5 ;
        RECT  288.672 63.916 288.696 64 ;
    END
  END k_wdata[16]
  PIN k_wdata[170]
    DIRECTION INPUT ;
    USE SIGNAL ;
    PORT
      LAYER M5 ;
        RECT  303.456 63.916 303.48 64 ;
    END
  END k_wdata[170]
  PIN k_wdata[171]
    DIRECTION INPUT ;
    USE SIGNAL ;
    PORT
      LAYER M5 ;
        RECT  303.552 63.916 303.576 64 ;
    END
  END k_wdata[171]
  PIN k_wdata[172]
    DIRECTION INPUT ;
    USE SIGNAL ;
    PORT
      LAYER M5 ;
        RECT  303.648 63.916 303.672 64 ;
    END
  END k_wdata[172]
  PIN k_wdata[173]
    DIRECTION INPUT ;
    USE SIGNAL ;
    PORT
      LAYER M5 ;
        RECT  303.744 63.916 303.768 64 ;
    END
  END k_wdata[173]
  PIN k_wdata[174]
    DIRECTION INPUT ;
    USE SIGNAL ;
    PORT
      LAYER M5 ;
        RECT  303.84 63.916 303.864 64 ;
    END
  END k_wdata[174]
  PIN k_wdata[175]
    DIRECTION INPUT ;
    USE SIGNAL ;
    PORT
      LAYER M5 ;
        RECT  303.936 63.916 303.96 64 ;
    END
  END k_wdata[175]
  PIN k_wdata[176]
    DIRECTION INPUT ;
    USE SIGNAL ;
    PORT
      LAYER M5 ;
        RECT  304.032 63.916 304.056 64 ;
    END
  END k_wdata[176]
  PIN k_wdata[177]
    DIRECTION INPUT ;
    USE SIGNAL ;
    PORT
      LAYER M5 ;
        RECT  304.128 63.916 304.152 64 ;
    END
  END k_wdata[177]
  PIN k_wdata[178]
    DIRECTION INPUT ;
    USE SIGNAL ;
    PORT
      LAYER M5 ;
        RECT  304.224 63.916 304.248 64 ;
    END
  END k_wdata[178]
  PIN k_wdata[179]
    DIRECTION INPUT ;
    USE SIGNAL ;
    PORT
      LAYER M5 ;
        RECT  304.32 63.916 304.344 64 ;
    END
  END k_wdata[179]
  PIN k_wdata[17]
    DIRECTION INPUT ;
    USE SIGNAL ;
    PORT
      LAYER M5 ;
        RECT  288.768 63.916 288.792 64 ;
    END
  END k_wdata[17]
  PIN k_wdata[180]
    DIRECTION INPUT ;
    USE SIGNAL ;
    PORT
      LAYER M5 ;
        RECT  304.416 63.916 304.44 64 ;
    END
  END k_wdata[180]
  PIN k_wdata[181]
    DIRECTION INPUT ;
    USE SIGNAL ;
    PORT
      LAYER M5 ;
        RECT  304.512 63.916 304.536 64 ;
    END
  END k_wdata[181]
  PIN k_wdata[182]
    DIRECTION INPUT ;
    USE SIGNAL ;
    PORT
      LAYER M5 ;
        RECT  304.608 63.916 304.632 64 ;
    END
  END k_wdata[182]
  PIN k_wdata[183]
    DIRECTION INPUT ;
    USE SIGNAL ;
    PORT
      LAYER M5 ;
        RECT  304.704 63.916 304.728 64 ;
    END
  END k_wdata[183]
  PIN k_wdata[184]
    DIRECTION INPUT ;
    USE SIGNAL ;
    PORT
      LAYER M5 ;
        RECT  304.8 63.916 304.824 64 ;
    END
  END k_wdata[184]
  PIN k_wdata[185]
    DIRECTION INPUT ;
    USE SIGNAL ;
    PORT
      LAYER M5 ;
        RECT  304.896 63.916 304.92 64 ;
    END
  END k_wdata[185]
  PIN k_wdata[186]
    DIRECTION INPUT ;
    USE SIGNAL ;
    PORT
      LAYER M5 ;
        RECT  304.992 63.916 305.016 64 ;
    END
  END k_wdata[186]
  PIN k_wdata[187]
    DIRECTION INPUT ;
    USE SIGNAL ;
    PORT
      LAYER M5 ;
        RECT  305.088 63.916 305.112 64 ;
    END
  END k_wdata[187]
  PIN k_wdata[188]
    DIRECTION INPUT ;
    USE SIGNAL ;
    PORT
      LAYER M5 ;
        RECT  305.184 63.916 305.208 64 ;
    END
  END k_wdata[188]
  PIN k_wdata[189]
    DIRECTION INPUT ;
    USE SIGNAL ;
    PORT
      LAYER M5 ;
        RECT  305.28 63.916 305.304 64 ;
    END
  END k_wdata[189]
  PIN k_wdata[18]
    DIRECTION INPUT ;
    USE SIGNAL ;
    PORT
      LAYER M5 ;
        RECT  288.864 63.916 288.888 64 ;
    END
  END k_wdata[18]
  PIN k_wdata[190]
    DIRECTION INPUT ;
    USE SIGNAL ;
    PORT
      LAYER M5 ;
        RECT  305.376 63.916 305.4 64 ;
    END
  END k_wdata[190]
  PIN k_wdata[191]
    DIRECTION INPUT ;
    USE SIGNAL ;
    PORT
      LAYER M5 ;
        RECT  305.472 63.916 305.496 64 ;
    END
  END k_wdata[191]
  PIN k_wdata[192]
    DIRECTION INPUT ;
    USE SIGNAL ;
    PORT
      LAYER M5 ;
        RECT  305.568 63.916 305.592 64 ;
    END
  END k_wdata[192]
  PIN k_wdata[193]
    DIRECTION INPUT ;
    USE SIGNAL ;
    PORT
      LAYER M5 ;
        RECT  305.664 63.916 305.688 64 ;
    END
  END k_wdata[193]
  PIN k_wdata[194]
    DIRECTION INPUT ;
    USE SIGNAL ;
    PORT
      LAYER M5 ;
        RECT  305.76 63.916 305.784 64 ;
    END
  END k_wdata[194]
  PIN k_wdata[195]
    DIRECTION INPUT ;
    USE SIGNAL ;
    PORT
      LAYER M5 ;
        RECT  305.856 63.916 305.88 64 ;
    END
  END k_wdata[195]
  PIN k_wdata[196]
    DIRECTION INPUT ;
    USE SIGNAL ;
    PORT
      LAYER M5 ;
        RECT  305.952 63.916 305.976 64 ;
    END
  END k_wdata[196]
  PIN k_wdata[197]
    DIRECTION INPUT ;
    USE SIGNAL ;
    PORT
      LAYER M5 ;
        RECT  306.048 63.916 306.072 64 ;
    END
  END k_wdata[197]
  PIN k_wdata[198]
    DIRECTION INPUT ;
    USE SIGNAL ;
    PORT
      LAYER M5 ;
        RECT  306.144 63.916 306.168 64 ;
    END
  END k_wdata[198]
  PIN k_wdata[199]
    DIRECTION INPUT ;
    USE SIGNAL ;
    PORT
      LAYER M5 ;
        RECT  306.24 63.916 306.264 64 ;
    END
  END k_wdata[199]
  PIN k_wdata[19]
    DIRECTION INPUT ;
    USE SIGNAL ;
    PORT
      LAYER M5 ;
        RECT  288.96 63.916 288.984 64 ;
    END
  END k_wdata[19]
  PIN k_wdata[1]
    DIRECTION INPUT ;
    USE SIGNAL ;
    PORT
      LAYER M5 ;
        RECT  287.232 63.916 287.256 64 ;
    END
  END k_wdata[1]
  PIN k_wdata[200]
    DIRECTION INPUT ;
    USE SIGNAL ;
    PORT
      LAYER M5 ;
        RECT  306.336 63.916 306.36 64 ;
    END
  END k_wdata[200]
  PIN k_wdata[201]
    DIRECTION INPUT ;
    USE SIGNAL ;
    PORT
      LAYER M5 ;
        RECT  306.432 63.916 306.456 64 ;
    END
  END k_wdata[201]
  PIN k_wdata[202]
    DIRECTION INPUT ;
    USE SIGNAL ;
    PORT
      LAYER M5 ;
        RECT  306.528 63.916 306.552 64 ;
    END
  END k_wdata[202]
  PIN k_wdata[203]
    DIRECTION INPUT ;
    USE SIGNAL ;
    PORT
      LAYER M5 ;
        RECT  306.624 63.916 306.648 64 ;
    END
  END k_wdata[203]
  PIN k_wdata[204]
    DIRECTION INPUT ;
    USE SIGNAL ;
    PORT
      LAYER M5 ;
        RECT  306.72 63.916 306.744 64 ;
    END
  END k_wdata[204]
  PIN k_wdata[205]
    DIRECTION INPUT ;
    USE SIGNAL ;
    PORT
      LAYER M5 ;
        RECT  306.816 63.916 306.84 64 ;
    END
  END k_wdata[205]
  PIN k_wdata[206]
    DIRECTION INPUT ;
    USE SIGNAL ;
    PORT
      LAYER M5 ;
        RECT  306.912 63.916 306.936 64 ;
    END
  END k_wdata[206]
  PIN k_wdata[207]
    DIRECTION INPUT ;
    USE SIGNAL ;
    PORT
      LAYER M5 ;
        RECT  307.008 63.916 307.032 64 ;
    END
  END k_wdata[207]
  PIN k_wdata[208]
    DIRECTION INPUT ;
    USE SIGNAL ;
    PORT
      LAYER M5 ;
        RECT  307.104 63.916 307.128 64 ;
    END
  END k_wdata[208]
  PIN k_wdata[209]
    DIRECTION INPUT ;
    USE SIGNAL ;
    PORT
      LAYER M5 ;
        RECT  307.2 63.916 307.224 64 ;
    END
  END k_wdata[209]
  PIN k_wdata[20]
    DIRECTION INPUT ;
    USE SIGNAL ;
    PORT
      LAYER M5 ;
        RECT  289.056 63.916 289.08 64 ;
    END
  END k_wdata[20]
  PIN k_wdata[210]
    DIRECTION INPUT ;
    USE SIGNAL ;
    PORT
      LAYER M5 ;
        RECT  307.296 63.916 307.32 64 ;
    END
  END k_wdata[210]
  PIN k_wdata[211]
    DIRECTION INPUT ;
    USE SIGNAL ;
    PORT
      LAYER M5 ;
        RECT  307.392 63.916 307.416 64 ;
    END
  END k_wdata[211]
  PIN k_wdata[212]
    DIRECTION INPUT ;
    USE SIGNAL ;
    PORT
      LAYER M5 ;
        RECT  307.488 63.916 307.512 64 ;
    END
  END k_wdata[212]
  PIN k_wdata[213]
    DIRECTION INPUT ;
    USE SIGNAL ;
    PORT
      LAYER M5 ;
        RECT  307.584 63.916 307.608 64 ;
    END
  END k_wdata[213]
  PIN k_wdata[214]
    DIRECTION INPUT ;
    USE SIGNAL ;
    PORT
      LAYER M5 ;
        RECT  307.68 63.916 307.704 64 ;
    END
  END k_wdata[214]
  PIN k_wdata[215]
    DIRECTION INPUT ;
    USE SIGNAL ;
    PORT
      LAYER M5 ;
        RECT  307.776 63.916 307.8 64 ;
    END
  END k_wdata[215]
  PIN k_wdata[216]
    DIRECTION INPUT ;
    USE SIGNAL ;
    PORT
      LAYER M5 ;
        RECT  307.872 63.916 307.896 64 ;
    END
  END k_wdata[216]
  PIN k_wdata[217]
    DIRECTION INPUT ;
    USE SIGNAL ;
    PORT
      LAYER M5 ;
        RECT  307.968 63.916 307.992 64 ;
    END
  END k_wdata[217]
  PIN k_wdata[218]
    DIRECTION INPUT ;
    USE SIGNAL ;
    PORT
      LAYER M5 ;
        RECT  308.064 63.916 308.088 64 ;
    END
  END k_wdata[218]
  PIN k_wdata[219]
    DIRECTION INPUT ;
    USE SIGNAL ;
    PORT
      LAYER M5 ;
        RECT  308.16 63.916 308.184 64 ;
    END
  END k_wdata[219]
  PIN k_wdata[21]
    DIRECTION INPUT ;
    USE SIGNAL ;
    PORT
      LAYER M5 ;
        RECT  289.152 63.916 289.176 64 ;
    END
  END k_wdata[21]
  PIN k_wdata[220]
    DIRECTION INPUT ;
    USE SIGNAL ;
    PORT
      LAYER M5 ;
        RECT  308.256 63.916 308.28 64 ;
    END
  END k_wdata[220]
  PIN k_wdata[221]
    DIRECTION INPUT ;
    USE SIGNAL ;
    PORT
      LAYER M5 ;
        RECT  308.352 63.916 308.376 64 ;
    END
  END k_wdata[221]
  PIN k_wdata[222]
    DIRECTION INPUT ;
    USE SIGNAL ;
    PORT
      LAYER M5 ;
        RECT  308.448 63.916 308.472 64 ;
    END
  END k_wdata[222]
  PIN k_wdata[223]
    DIRECTION INPUT ;
    USE SIGNAL ;
    PORT
      LAYER M5 ;
        RECT  308.544 63.916 308.568 64 ;
    END
  END k_wdata[223]
  PIN k_wdata[224]
    DIRECTION INPUT ;
    USE SIGNAL ;
    PORT
      LAYER M5 ;
        RECT  308.64 63.916 308.664 64 ;
    END
  END k_wdata[224]
  PIN k_wdata[225]
    DIRECTION INPUT ;
    USE SIGNAL ;
    PORT
      LAYER M5 ;
        RECT  308.736 63.916 308.76 64 ;
    END
  END k_wdata[225]
  PIN k_wdata[226]
    DIRECTION INPUT ;
    USE SIGNAL ;
    PORT
      LAYER M5 ;
        RECT  308.832 63.916 308.856 64 ;
    END
  END k_wdata[226]
  PIN k_wdata[227]
    DIRECTION INPUT ;
    USE SIGNAL ;
    PORT
      LAYER M5 ;
        RECT  308.928 63.916 308.952 64 ;
    END
  END k_wdata[227]
  PIN k_wdata[228]
    DIRECTION INPUT ;
    USE SIGNAL ;
    PORT
      LAYER M5 ;
        RECT  309.024 63.916 309.048 64 ;
    END
  END k_wdata[228]
  PIN k_wdata[229]
    DIRECTION INPUT ;
    USE SIGNAL ;
    PORT
      LAYER M5 ;
        RECT  309.12 63.916 309.144 64 ;
    END
  END k_wdata[229]
  PIN k_wdata[22]
    DIRECTION INPUT ;
    USE SIGNAL ;
    PORT
      LAYER M5 ;
        RECT  289.248 63.916 289.272 64 ;
    END
  END k_wdata[22]
  PIN k_wdata[230]
    DIRECTION INPUT ;
    USE SIGNAL ;
    PORT
      LAYER M5 ;
        RECT  309.216 63.916 309.24 64 ;
    END
  END k_wdata[230]
  PIN k_wdata[231]
    DIRECTION INPUT ;
    USE SIGNAL ;
    PORT
      LAYER M5 ;
        RECT  309.312 63.916 309.336 64 ;
    END
  END k_wdata[231]
  PIN k_wdata[232]
    DIRECTION INPUT ;
    USE SIGNAL ;
    PORT
      LAYER M5 ;
        RECT  309.408 63.916 309.432 64 ;
    END
  END k_wdata[232]
  PIN k_wdata[233]
    DIRECTION INPUT ;
    USE SIGNAL ;
    PORT
      LAYER M5 ;
        RECT  309.504 63.916 309.528 64 ;
    END
  END k_wdata[233]
  PIN k_wdata[234]
    DIRECTION INPUT ;
    USE SIGNAL ;
    PORT
      LAYER M5 ;
        RECT  309.6 63.916 309.624 64 ;
    END
  END k_wdata[234]
  PIN k_wdata[235]
    DIRECTION INPUT ;
    USE SIGNAL ;
    PORT
      LAYER M5 ;
        RECT  309.696 63.916 309.72 64 ;
    END
  END k_wdata[235]
  PIN k_wdata[236]
    DIRECTION INPUT ;
    USE SIGNAL ;
    PORT
      LAYER M5 ;
        RECT  309.792 63.916 309.816 64 ;
    END
  END k_wdata[236]
  PIN k_wdata[237]
    DIRECTION INPUT ;
    USE SIGNAL ;
    PORT
      LAYER M5 ;
        RECT  309.888 63.916 309.912 64 ;
    END
  END k_wdata[237]
  PIN k_wdata[238]
    DIRECTION INPUT ;
    USE SIGNAL ;
    PORT
      LAYER M5 ;
        RECT  309.984 63.916 310.008 64 ;
    END
  END k_wdata[238]
  PIN k_wdata[239]
    DIRECTION INPUT ;
    USE SIGNAL ;
    PORT
      LAYER M5 ;
        RECT  310.08 63.916 310.104 64 ;
    END
  END k_wdata[239]
  PIN k_wdata[23]
    DIRECTION INPUT ;
    USE SIGNAL ;
    PORT
      LAYER M5 ;
        RECT  289.344 63.916 289.368 64 ;
    END
  END k_wdata[23]
  PIN k_wdata[240]
    DIRECTION INPUT ;
    USE SIGNAL ;
    PORT
      LAYER M5 ;
        RECT  310.176 63.916 310.2 64 ;
    END
  END k_wdata[240]
  PIN k_wdata[241]
    DIRECTION INPUT ;
    USE SIGNAL ;
    PORT
      LAYER M5 ;
        RECT  310.272 63.916 310.296 64 ;
    END
  END k_wdata[241]
  PIN k_wdata[242]
    DIRECTION INPUT ;
    USE SIGNAL ;
    PORT
      LAYER M5 ;
        RECT  310.368 63.916 310.392 64 ;
    END
  END k_wdata[242]
  PIN k_wdata[243]
    DIRECTION INPUT ;
    USE SIGNAL ;
    PORT
      LAYER M5 ;
        RECT  310.464 63.916 310.488 64 ;
    END
  END k_wdata[243]
  PIN k_wdata[244]
    DIRECTION INPUT ;
    USE SIGNAL ;
    PORT
      LAYER M5 ;
        RECT  310.56 63.916 310.584 64 ;
    END
  END k_wdata[244]
  PIN k_wdata[245]
    DIRECTION INPUT ;
    USE SIGNAL ;
    PORT
      LAYER M5 ;
        RECT  310.656 63.916 310.68 64 ;
    END
  END k_wdata[245]
  PIN k_wdata[246]
    DIRECTION INPUT ;
    USE SIGNAL ;
    PORT
      LAYER M5 ;
        RECT  310.752 63.916 310.776 64 ;
    END
  END k_wdata[246]
  PIN k_wdata[247]
    DIRECTION INPUT ;
    USE SIGNAL ;
    PORT
      LAYER M5 ;
        RECT  310.848 63.916 310.872 64 ;
    END
  END k_wdata[247]
  PIN k_wdata[248]
    DIRECTION INPUT ;
    USE SIGNAL ;
    PORT
      LAYER M5 ;
        RECT  310.944 63.916 310.968 64 ;
    END
  END k_wdata[248]
  PIN k_wdata[249]
    DIRECTION INPUT ;
    USE SIGNAL ;
    PORT
      LAYER M5 ;
        RECT  311.04 63.916 311.064 64 ;
    END
  END k_wdata[249]
  PIN k_wdata[24]
    DIRECTION INPUT ;
    USE SIGNAL ;
    PORT
      LAYER M5 ;
        RECT  289.44 63.916 289.464 64 ;
    END
  END k_wdata[24]
  PIN k_wdata[250]
    DIRECTION INPUT ;
    USE SIGNAL ;
    PORT
      LAYER M5 ;
        RECT  311.136 63.916 311.16 64 ;
    END
  END k_wdata[250]
  PIN k_wdata[251]
    DIRECTION INPUT ;
    USE SIGNAL ;
    PORT
      LAYER M5 ;
        RECT  311.232 63.916 311.256 64 ;
    END
  END k_wdata[251]
  PIN k_wdata[252]
    DIRECTION INPUT ;
    USE SIGNAL ;
    PORT
      LAYER M5 ;
        RECT  311.328 63.916 311.352 64 ;
    END
  END k_wdata[252]
  PIN k_wdata[253]
    DIRECTION INPUT ;
    USE SIGNAL ;
    PORT
      LAYER M5 ;
        RECT  311.424 63.916 311.448 64 ;
    END
  END k_wdata[253]
  PIN k_wdata[254]
    DIRECTION INPUT ;
    USE SIGNAL ;
    PORT
      LAYER M5 ;
        RECT  311.52 63.916 311.544 64 ;
    END
  END k_wdata[254]
  PIN k_wdata[255]
    DIRECTION INPUT ;
    USE SIGNAL ;
    PORT
      LAYER M5 ;
        RECT  311.616 63.916 311.64 64 ;
    END
  END k_wdata[255]
  PIN k_wdata[25]
    DIRECTION INPUT ;
    USE SIGNAL ;
    PORT
      LAYER M5 ;
        RECT  289.536 63.916 289.56 64 ;
    END
  END k_wdata[25]
  PIN k_wdata[26]
    DIRECTION INPUT ;
    USE SIGNAL ;
    PORT
      LAYER M5 ;
        RECT  289.632 63.916 289.656 64 ;
    END
  END k_wdata[26]
  PIN k_wdata[27]
    DIRECTION INPUT ;
    USE SIGNAL ;
    PORT
      LAYER M5 ;
        RECT  289.728 63.916 289.752 64 ;
    END
  END k_wdata[27]
  PIN k_wdata[28]
    DIRECTION INPUT ;
    USE SIGNAL ;
    PORT
      LAYER M5 ;
        RECT  289.824 63.916 289.848 64 ;
    END
  END k_wdata[28]
  PIN k_wdata[29]
    DIRECTION INPUT ;
    USE SIGNAL ;
    PORT
      LAYER M5 ;
        RECT  289.92 63.916 289.944 64 ;
    END
  END k_wdata[29]
  PIN k_wdata[2]
    DIRECTION INPUT ;
    USE SIGNAL ;
    PORT
      LAYER M5 ;
        RECT  287.328 63.916 287.352 64 ;
    END
  END k_wdata[2]
  PIN k_wdata[30]
    DIRECTION INPUT ;
    USE SIGNAL ;
    PORT
      LAYER M5 ;
        RECT  290.016 63.916 290.04 64 ;
    END
  END k_wdata[30]
  PIN k_wdata[31]
    DIRECTION INPUT ;
    USE SIGNAL ;
    PORT
      LAYER M5 ;
        RECT  290.112 63.916 290.136 64 ;
    END
  END k_wdata[31]
  PIN k_wdata[32]
    DIRECTION INPUT ;
    USE SIGNAL ;
    PORT
      LAYER M5 ;
        RECT  290.208 63.916 290.232 64 ;
    END
  END k_wdata[32]
  PIN k_wdata[33]
    DIRECTION INPUT ;
    USE SIGNAL ;
    PORT
      LAYER M5 ;
        RECT  290.304 63.916 290.328 64 ;
    END
  END k_wdata[33]
  PIN k_wdata[34]
    DIRECTION INPUT ;
    USE SIGNAL ;
    PORT
      LAYER M5 ;
        RECT  290.4 63.916 290.424 64 ;
    END
  END k_wdata[34]
  PIN k_wdata[35]
    DIRECTION INPUT ;
    USE SIGNAL ;
    PORT
      LAYER M5 ;
        RECT  290.496 63.916 290.52 64 ;
    END
  END k_wdata[35]
  PIN k_wdata[36]
    DIRECTION INPUT ;
    USE SIGNAL ;
    PORT
      LAYER M5 ;
        RECT  290.592 63.916 290.616 64 ;
    END
  END k_wdata[36]
  PIN k_wdata[37]
    DIRECTION INPUT ;
    USE SIGNAL ;
    PORT
      LAYER M5 ;
        RECT  290.688 63.916 290.712 64 ;
    END
  END k_wdata[37]
  PIN k_wdata[38]
    DIRECTION INPUT ;
    USE SIGNAL ;
    PORT
      LAYER M5 ;
        RECT  290.784 63.916 290.808 64 ;
    END
  END k_wdata[38]
  PIN k_wdata[39]
    DIRECTION INPUT ;
    USE SIGNAL ;
    PORT
      LAYER M5 ;
        RECT  290.88 63.916 290.904 64 ;
    END
  END k_wdata[39]
  PIN k_wdata[3]
    DIRECTION INPUT ;
    USE SIGNAL ;
    PORT
      LAYER M5 ;
        RECT  287.424 63.916 287.448 64 ;
    END
  END k_wdata[3]
  PIN k_wdata[40]
    DIRECTION INPUT ;
    USE SIGNAL ;
    PORT
      LAYER M5 ;
        RECT  290.976 63.916 291 64 ;
    END
  END k_wdata[40]
  PIN k_wdata[41]
    DIRECTION INPUT ;
    USE SIGNAL ;
    PORT
      LAYER M5 ;
        RECT  291.072 63.916 291.096 64 ;
    END
  END k_wdata[41]
  PIN k_wdata[42]
    DIRECTION INPUT ;
    USE SIGNAL ;
    PORT
      LAYER M5 ;
        RECT  291.168 63.916 291.192 64 ;
    END
  END k_wdata[42]
  PIN k_wdata[43]
    DIRECTION INPUT ;
    USE SIGNAL ;
    PORT
      LAYER M5 ;
        RECT  291.264 63.916 291.288 64 ;
    END
  END k_wdata[43]
  PIN k_wdata[44]
    DIRECTION INPUT ;
    USE SIGNAL ;
    PORT
      LAYER M5 ;
        RECT  291.36 63.916 291.384 64 ;
    END
  END k_wdata[44]
  PIN k_wdata[45]
    DIRECTION INPUT ;
    USE SIGNAL ;
    PORT
      LAYER M5 ;
        RECT  291.456 63.916 291.48 64 ;
    END
  END k_wdata[45]
  PIN k_wdata[46]
    DIRECTION INPUT ;
    USE SIGNAL ;
    PORT
      LAYER M5 ;
        RECT  291.552 63.916 291.576 64 ;
    END
  END k_wdata[46]
  PIN k_wdata[47]
    DIRECTION INPUT ;
    USE SIGNAL ;
    PORT
      LAYER M5 ;
        RECT  291.648 63.916 291.672 64 ;
    END
  END k_wdata[47]
  PIN k_wdata[48]
    DIRECTION INPUT ;
    USE SIGNAL ;
    PORT
      LAYER M5 ;
        RECT  291.744 63.916 291.768 64 ;
    END
  END k_wdata[48]
  PIN k_wdata[49]
    DIRECTION INPUT ;
    USE SIGNAL ;
    PORT
      LAYER M5 ;
        RECT  291.84 63.916 291.864 64 ;
    END
  END k_wdata[49]
  PIN k_wdata[4]
    DIRECTION INPUT ;
    USE SIGNAL ;
    PORT
      LAYER M5 ;
        RECT  287.52 63.916 287.544 64 ;
    END
  END k_wdata[4]
  PIN k_wdata[50]
    DIRECTION INPUT ;
    USE SIGNAL ;
    PORT
      LAYER M5 ;
        RECT  291.936 63.916 291.96 64 ;
    END
  END k_wdata[50]
  PIN k_wdata[51]
    DIRECTION INPUT ;
    USE SIGNAL ;
    PORT
      LAYER M5 ;
        RECT  292.032 63.916 292.056 64 ;
    END
  END k_wdata[51]
  PIN k_wdata[52]
    DIRECTION INPUT ;
    USE SIGNAL ;
    PORT
      LAYER M5 ;
        RECT  292.128 63.916 292.152 64 ;
    END
  END k_wdata[52]
  PIN k_wdata[53]
    DIRECTION INPUT ;
    USE SIGNAL ;
    PORT
      LAYER M5 ;
        RECT  292.224 63.916 292.248 64 ;
    END
  END k_wdata[53]
  PIN k_wdata[54]
    DIRECTION INPUT ;
    USE SIGNAL ;
    PORT
      LAYER M5 ;
        RECT  292.32 63.916 292.344 64 ;
    END
  END k_wdata[54]
  PIN k_wdata[55]
    DIRECTION INPUT ;
    USE SIGNAL ;
    PORT
      LAYER M5 ;
        RECT  292.416 63.916 292.44 64 ;
    END
  END k_wdata[55]
  PIN k_wdata[56]
    DIRECTION INPUT ;
    USE SIGNAL ;
    PORT
      LAYER M5 ;
        RECT  292.512 63.916 292.536 64 ;
    END
  END k_wdata[56]
  PIN k_wdata[57]
    DIRECTION INPUT ;
    USE SIGNAL ;
    PORT
      LAYER M5 ;
        RECT  292.608 63.916 292.632 64 ;
    END
  END k_wdata[57]
  PIN k_wdata[58]
    DIRECTION INPUT ;
    USE SIGNAL ;
    PORT
      LAYER M5 ;
        RECT  292.704 63.916 292.728 64 ;
    END
  END k_wdata[58]
  PIN k_wdata[59]
    DIRECTION INPUT ;
    USE SIGNAL ;
    PORT
      LAYER M5 ;
        RECT  292.8 63.916 292.824 64 ;
    END
  END k_wdata[59]
  PIN k_wdata[5]
    DIRECTION INPUT ;
    USE SIGNAL ;
    PORT
      LAYER M5 ;
        RECT  287.616 63.916 287.64 64 ;
    END
  END k_wdata[5]
  PIN k_wdata[60]
    DIRECTION INPUT ;
    USE SIGNAL ;
    PORT
      LAYER M5 ;
        RECT  292.896 63.916 292.92 64 ;
    END
  END k_wdata[60]
  PIN k_wdata[61]
    DIRECTION INPUT ;
    USE SIGNAL ;
    PORT
      LAYER M5 ;
        RECT  292.992 63.916 293.016 64 ;
    END
  END k_wdata[61]
  PIN k_wdata[62]
    DIRECTION INPUT ;
    USE SIGNAL ;
    PORT
      LAYER M5 ;
        RECT  293.088 63.916 293.112 64 ;
    END
  END k_wdata[62]
  PIN k_wdata[63]
    DIRECTION INPUT ;
    USE SIGNAL ;
    PORT
      LAYER M5 ;
        RECT  293.184 63.916 293.208 64 ;
    END
  END k_wdata[63]
  PIN k_wdata[64]
    DIRECTION INPUT ;
    USE SIGNAL ;
    PORT
      LAYER M5 ;
        RECT  293.28 63.916 293.304 64 ;
    END
  END k_wdata[64]
  PIN k_wdata[65]
    DIRECTION INPUT ;
    USE SIGNAL ;
    PORT
      LAYER M5 ;
        RECT  293.376 63.916 293.4 64 ;
    END
  END k_wdata[65]
  PIN k_wdata[66]
    DIRECTION INPUT ;
    USE SIGNAL ;
    PORT
      LAYER M5 ;
        RECT  293.472 63.916 293.496 64 ;
    END
  END k_wdata[66]
  PIN k_wdata[67]
    DIRECTION INPUT ;
    USE SIGNAL ;
    PORT
      LAYER M5 ;
        RECT  293.568 63.916 293.592 64 ;
    END
  END k_wdata[67]
  PIN k_wdata[68]
    DIRECTION INPUT ;
    USE SIGNAL ;
    PORT
      LAYER M5 ;
        RECT  293.664 63.916 293.688 64 ;
    END
  END k_wdata[68]
  PIN k_wdata[69]
    DIRECTION INPUT ;
    USE SIGNAL ;
    PORT
      LAYER M5 ;
        RECT  293.76 63.916 293.784 64 ;
    END
  END k_wdata[69]
  PIN k_wdata[6]
    DIRECTION INPUT ;
    USE SIGNAL ;
    PORT
      LAYER M5 ;
        RECT  287.712 63.916 287.736 64 ;
    END
  END k_wdata[6]
  PIN k_wdata[70]
    DIRECTION INPUT ;
    USE SIGNAL ;
    PORT
      LAYER M5 ;
        RECT  293.856 63.916 293.88 64 ;
    END
  END k_wdata[70]
  PIN k_wdata[71]
    DIRECTION INPUT ;
    USE SIGNAL ;
    PORT
      LAYER M5 ;
        RECT  293.952 63.916 293.976 64 ;
    END
  END k_wdata[71]
  PIN k_wdata[72]
    DIRECTION INPUT ;
    USE SIGNAL ;
    PORT
      LAYER M5 ;
        RECT  294.048 63.916 294.072 64 ;
    END
  END k_wdata[72]
  PIN k_wdata[73]
    DIRECTION INPUT ;
    USE SIGNAL ;
    PORT
      LAYER M5 ;
        RECT  294.144 63.916 294.168 64 ;
    END
  END k_wdata[73]
  PIN k_wdata[74]
    DIRECTION INPUT ;
    USE SIGNAL ;
    PORT
      LAYER M5 ;
        RECT  294.24 63.916 294.264 64 ;
    END
  END k_wdata[74]
  PIN k_wdata[75]
    DIRECTION INPUT ;
    USE SIGNAL ;
    PORT
      LAYER M5 ;
        RECT  294.336 63.916 294.36 64 ;
    END
  END k_wdata[75]
  PIN k_wdata[76]
    DIRECTION INPUT ;
    USE SIGNAL ;
    PORT
      LAYER M5 ;
        RECT  294.432 63.916 294.456 64 ;
    END
  END k_wdata[76]
  PIN k_wdata[77]
    DIRECTION INPUT ;
    USE SIGNAL ;
    PORT
      LAYER M5 ;
        RECT  294.528 63.916 294.552 64 ;
    END
  END k_wdata[77]
  PIN k_wdata[78]
    DIRECTION INPUT ;
    USE SIGNAL ;
    PORT
      LAYER M5 ;
        RECT  294.624 63.916 294.648 64 ;
    END
  END k_wdata[78]
  PIN k_wdata[79]
    DIRECTION INPUT ;
    USE SIGNAL ;
    PORT
      LAYER M5 ;
        RECT  294.72 63.916 294.744 64 ;
    END
  END k_wdata[79]
  PIN k_wdata[7]
    DIRECTION INPUT ;
    USE SIGNAL ;
    PORT
      LAYER M5 ;
        RECT  287.808 63.916 287.832 64 ;
    END
  END k_wdata[7]
  PIN k_wdata[80]
    DIRECTION INPUT ;
    USE SIGNAL ;
    PORT
      LAYER M5 ;
        RECT  294.816 63.916 294.84 64 ;
    END
  END k_wdata[80]
  PIN k_wdata[81]
    DIRECTION INPUT ;
    USE SIGNAL ;
    PORT
      LAYER M5 ;
        RECT  294.912 63.916 294.936 64 ;
    END
  END k_wdata[81]
  PIN k_wdata[82]
    DIRECTION INPUT ;
    USE SIGNAL ;
    PORT
      LAYER M5 ;
        RECT  295.008 63.916 295.032 64 ;
    END
  END k_wdata[82]
  PIN k_wdata[83]
    DIRECTION INPUT ;
    USE SIGNAL ;
    PORT
      LAYER M5 ;
        RECT  295.104 63.916 295.128 64 ;
    END
  END k_wdata[83]
  PIN k_wdata[84]
    DIRECTION INPUT ;
    USE SIGNAL ;
    PORT
      LAYER M5 ;
        RECT  295.2 63.916 295.224 64 ;
    END
  END k_wdata[84]
  PIN k_wdata[85]
    DIRECTION INPUT ;
    USE SIGNAL ;
    PORT
      LAYER M5 ;
        RECT  295.296 63.916 295.32 64 ;
    END
  END k_wdata[85]
  PIN k_wdata[86]
    DIRECTION INPUT ;
    USE SIGNAL ;
    PORT
      LAYER M5 ;
        RECT  295.392 63.916 295.416 64 ;
    END
  END k_wdata[86]
  PIN k_wdata[87]
    DIRECTION INPUT ;
    USE SIGNAL ;
    PORT
      LAYER M5 ;
        RECT  295.488 63.916 295.512 64 ;
    END
  END k_wdata[87]
  PIN k_wdata[88]
    DIRECTION INPUT ;
    USE SIGNAL ;
    PORT
      LAYER M5 ;
        RECT  295.584 63.916 295.608 64 ;
    END
  END k_wdata[88]
  PIN k_wdata[89]
    DIRECTION INPUT ;
    USE SIGNAL ;
    PORT
      LAYER M5 ;
        RECT  295.68 63.916 295.704 64 ;
    END
  END k_wdata[89]
  PIN k_wdata[8]
    DIRECTION INPUT ;
    USE SIGNAL ;
    PORT
      LAYER M5 ;
        RECT  287.904 63.916 287.928 64 ;
    END
  END k_wdata[8]
  PIN k_wdata[90]
    DIRECTION INPUT ;
    USE SIGNAL ;
    PORT
      LAYER M5 ;
        RECT  295.776 63.916 295.8 64 ;
    END
  END k_wdata[90]
  PIN k_wdata[91]
    DIRECTION INPUT ;
    USE SIGNAL ;
    PORT
      LAYER M5 ;
        RECT  295.872 63.916 295.896 64 ;
    END
  END k_wdata[91]
  PIN k_wdata[92]
    DIRECTION INPUT ;
    USE SIGNAL ;
    PORT
      LAYER M5 ;
        RECT  295.968 63.916 295.992 64 ;
    END
  END k_wdata[92]
  PIN k_wdata[93]
    DIRECTION INPUT ;
    USE SIGNAL ;
    PORT
      LAYER M5 ;
        RECT  296.064 63.916 296.088 64 ;
    END
  END k_wdata[93]
  PIN k_wdata[94]
    DIRECTION INPUT ;
    USE SIGNAL ;
    PORT
      LAYER M5 ;
        RECT  296.16 63.916 296.184 64 ;
    END
  END k_wdata[94]
  PIN k_wdata[95]
    DIRECTION INPUT ;
    USE SIGNAL ;
    PORT
      LAYER M5 ;
        RECT  296.256 63.916 296.28 64 ;
    END
  END k_wdata[95]
  PIN k_wdata[96]
    DIRECTION INPUT ;
    USE SIGNAL ;
    PORT
      LAYER M5 ;
        RECT  296.352 63.916 296.376 64 ;
    END
  END k_wdata[96]
  PIN k_wdata[97]
    DIRECTION INPUT ;
    USE SIGNAL ;
    PORT
      LAYER M5 ;
        RECT  296.448 63.916 296.472 64 ;
    END
  END k_wdata[97]
  PIN k_wdata[98]
    DIRECTION INPUT ;
    USE SIGNAL ;
    PORT
      LAYER M5 ;
        RECT  296.544 63.916 296.568 64 ;
    END
  END k_wdata[98]
  PIN k_wdata[99]
    DIRECTION INPUT ;
    USE SIGNAL ;
    PORT
      LAYER M5 ;
        RECT  296.64 63.916 296.664 64 ;
    END
  END k_wdata[99]
  PIN k_wdata[9]
    DIRECTION INPUT ;
    USE SIGNAL ;
    PORT
      LAYER M5 ;
        RECT  288 63.916 288.024 64 ;
    END
  END k_wdata[9]
  PIN k_we
    DIRECTION INPUT ;
    USE SIGNAL ;
    PORT
      LAYER M5 ;
        RECT  311.712 63.916 311.736 64 ;
    END
  END k_we
  PIN k_wr_done
    DIRECTION OUTPUT ;
    USE SIGNAL ;
    PORT
      LAYER M5 ;
        RECT  311.808 63.916 311.832 64 ;
    END
  END k_wr_done
  PIN k_wstrb[0]
    DIRECTION INPUT ;
    USE SIGNAL ;
    PORT
      LAYER M5 ;
        RECT  311.904 63.916 311.928 64 ;
    END
  END k_wstrb[0]
  PIN k_wstrb[10]
    DIRECTION INPUT ;
    USE SIGNAL ;
    PORT
      LAYER M5 ;
        RECT  312.864 63.916 312.888 64 ;
    END
  END k_wstrb[10]
  PIN k_wstrb[11]
    DIRECTION INPUT ;
    USE SIGNAL ;
    PORT
      LAYER M5 ;
        RECT  312.96 63.916 312.984 64 ;
    END
  END k_wstrb[11]
  PIN k_wstrb[12]
    DIRECTION INPUT ;
    USE SIGNAL ;
    PORT
      LAYER M5 ;
        RECT  313.056 63.916 313.08 64 ;
    END
  END k_wstrb[12]
  PIN k_wstrb[13]
    DIRECTION INPUT ;
    USE SIGNAL ;
    PORT
      LAYER M5 ;
        RECT  313.152 63.916 313.176 64 ;
    END
  END k_wstrb[13]
  PIN k_wstrb[14]
    DIRECTION INPUT ;
    USE SIGNAL ;
    PORT
      LAYER M5 ;
        RECT  313.248 63.916 313.272 64 ;
    END
  END k_wstrb[14]
  PIN k_wstrb[15]
    DIRECTION INPUT ;
    USE SIGNAL ;
    PORT
      LAYER M5 ;
        RECT  313.344 63.916 313.368 64 ;
    END
  END k_wstrb[15]
  PIN k_wstrb[16]
    DIRECTION INPUT ;
    USE SIGNAL ;
    PORT
      LAYER M5 ;
        RECT  313.44 63.916 313.464 64 ;
    END
  END k_wstrb[16]
  PIN k_wstrb[17]
    DIRECTION INPUT ;
    USE SIGNAL ;
    PORT
      LAYER M5 ;
        RECT  313.536 63.916 313.56 64 ;
    END
  END k_wstrb[17]
  PIN k_wstrb[18]
    DIRECTION INPUT ;
    USE SIGNAL ;
    PORT
      LAYER M5 ;
        RECT  313.632 63.916 313.656 64 ;
    END
  END k_wstrb[18]
  PIN k_wstrb[19]
    DIRECTION INPUT ;
    USE SIGNAL ;
    PORT
      LAYER M5 ;
        RECT  313.728 63.916 313.752 64 ;
    END
  END k_wstrb[19]
  PIN k_wstrb[1]
    DIRECTION INPUT ;
    USE SIGNAL ;
    PORT
      LAYER M5 ;
        RECT  312 63.916 312.024 64 ;
    END
  END k_wstrb[1]
  PIN k_wstrb[20]
    DIRECTION INPUT ;
    USE SIGNAL ;
    PORT
      LAYER M5 ;
        RECT  313.824 63.916 313.848 64 ;
    END
  END k_wstrb[20]
  PIN k_wstrb[21]
    DIRECTION INPUT ;
    USE SIGNAL ;
    PORT
      LAYER M5 ;
        RECT  313.92 63.916 313.944 64 ;
    END
  END k_wstrb[21]
  PIN k_wstrb[22]
    DIRECTION INPUT ;
    USE SIGNAL ;
    PORT
      LAYER M5 ;
        RECT  314.016 63.916 314.04 64 ;
    END
  END k_wstrb[22]
  PIN k_wstrb[23]
    DIRECTION INPUT ;
    USE SIGNAL ;
    PORT
      LAYER M5 ;
        RECT  314.112 63.916 314.136 64 ;
    END
  END k_wstrb[23]
  PIN k_wstrb[24]
    DIRECTION INPUT ;
    USE SIGNAL ;
    PORT
      LAYER M5 ;
        RECT  314.208 63.916 314.232 64 ;
    END
  END k_wstrb[24]
  PIN k_wstrb[25]
    DIRECTION INPUT ;
    USE SIGNAL ;
    PORT
      LAYER M5 ;
        RECT  314.304 63.916 314.328 64 ;
    END
  END k_wstrb[25]
  PIN k_wstrb[26]
    DIRECTION INPUT ;
    USE SIGNAL ;
    PORT
      LAYER M5 ;
        RECT  314.4 63.916 314.424 64 ;
    END
  END k_wstrb[26]
  PIN k_wstrb[27]
    DIRECTION INPUT ;
    USE SIGNAL ;
    PORT
      LAYER M5 ;
        RECT  314.496 63.916 314.52 64 ;
    END
  END k_wstrb[27]
  PIN k_wstrb[28]
    DIRECTION INPUT ;
    USE SIGNAL ;
    PORT
      LAYER M5 ;
        RECT  314.592 63.916 314.616 64 ;
    END
  END k_wstrb[28]
  PIN k_wstrb[29]
    DIRECTION INPUT ;
    USE SIGNAL ;
    PORT
      LAYER M5 ;
        RECT  314.688 63.916 314.712 64 ;
    END
  END k_wstrb[29]
  PIN k_wstrb[2]
    DIRECTION INPUT ;
    USE SIGNAL ;
    PORT
      LAYER M5 ;
        RECT  312.096 63.916 312.12 64 ;
    END
  END k_wstrb[2]
  PIN k_wstrb[30]
    DIRECTION INPUT ;
    USE SIGNAL ;
    PORT
      LAYER M5 ;
        RECT  314.784 63.916 314.808 64 ;
    END
  END k_wstrb[30]
  PIN k_wstrb[31]
    DIRECTION INPUT ;
    USE SIGNAL ;
    PORT
      LAYER M5 ;
        RECT  314.88 63.916 314.904 64 ;
    END
  END k_wstrb[31]
  PIN k_wstrb[3]
    DIRECTION INPUT ;
    USE SIGNAL ;
    PORT
      LAYER M5 ;
        RECT  312.192 63.916 312.216 64 ;
    END
  END k_wstrb[3]
  PIN k_wstrb[4]
    DIRECTION INPUT ;
    USE SIGNAL ;
    PORT
      LAYER M5 ;
        RECT  312.288 63.916 312.312 64 ;
    END
  END k_wstrb[4]
  PIN k_wstrb[5]
    DIRECTION INPUT ;
    USE SIGNAL ;
    PORT
      LAYER M5 ;
        RECT  312.384 63.916 312.408 64 ;
    END
  END k_wstrb[5]
  PIN k_wstrb[6]
    DIRECTION INPUT ;
    USE SIGNAL ;
    PORT
      LAYER M5 ;
        RECT  312.48 63.916 312.504 64 ;
    END
  END k_wstrb[6]
  PIN k_wstrb[7]
    DIRECTION INPUT ;
    USE SIGNAL ;
    PORT
      LAYER M5 ;
        RECT  312.576 63.916 312.6 64 ;
    END
  END k_wstrb[7]
  PIN k_wstrb[8]
    DIRECTION INPUT ;
    USE SIGNAL ;
    PORT
      LAYER M5 ;
        RECT  312.672 63.916 312.696 64 ;
    END
  END k_wstrb[8]
  PIN k_wstrb[9]
    DIRECTION INPUT ;
    USE SIGNAL ;
    PORT
      LAYER M5 ;
        RECT  312.768 63.916 312.792 64 ;
    END
  END k_wstrb[9]
  PIN r_beat[0]
    DIRECTION INPUT ;
    USE SIGNAL ;
    PORT
      LAYER M5 ;
        RECT  110.592 0 110.616 0.084 ;
    END
  END r_beat[0]
  PIN r_beat[1]
    DIRECTION INPUT ;
    USE SIGNAL ;
    PORT
      LAYER M5 ;
        RECT  110.688 0 110.712 0.084 ;
    END
  END r_beat[1]
  PIN r_beat[2]
    DIRECTION INPUT ;
    USE SIGNAL ;
    PORT
      LAYER M5 ;
        RECT  110.784 0 110.808 0.084 ;
    END
  END r_beat[2]
  PIN r_beat[3]
    DIRECTION INPUT ;
    USE SIGNAL ;
    PORT
      LAYER M5 ;
        RECT  110.88 0 110.904 0.084 ;
    END
  END r_beat[3]
  PIN r_data[0]
    DIRECTION INPUT ;
    USE SIGNAL ;
    PORT
      LAYER M5 ;
        RECT  110.976 0 111 0.084 ;
    END
  END r_data[0]
  PIN r_data[100]
    DIRECTION INPUT ;
    USE SIGNAL ;
    PORT
      LAYER M5 ;
        RECT  120.576 0 120.6 0.084 ;
    END
  END r_data[100]
  PIN r_data[101]
    DIRECTION INPUT ;
    USE SIGNAL ;
    PORT
      LAYER M5 ;
        RECT  120.672 0 120.696 0.084 ;
    END
  END r_data[101]
  PIN r_data[102]
    DIRECTION INPUT ;
    USE SIGNAL ;
    PORT
      LAYER M5 ;
        RECT  120.768 0 120.792 0.084 ;
    END
  END r_data[102]
  PIN r_data[103]
    DIRECTION INPUT ;
    USE SIGNAL ;
    PORT
      LAYER M5 ;
        RECT  120.864 0 120.888 0.084 ;
    END
  END r_data[103]
  PIN r_data[104]
    DIRECTION INPUT ;
    USE SIGNAL ;
    PORT
      LAYER M5 ;
        RECT  120.96 0 120.984 0.084 ;
    END
  END r_data[104]
  PIN r_data[105]
    DIRECTION INPUT ;
    USE SIGNAL ;
    PORT
      LAYER M5 ;
        RECT  121.056 0 121.08 0.084 ;
    END
  END r_data[105]
  PIN r_data[106]
    DIRECTION INPUT ;
    USE SIGNAL ;
    PORT
      LAYER M5 ;
        RECT  121.152 0 121.176 0.084 ;
    END
  END r_data[106]
  PIN r_data[107]
    DIRECTION INPUT ;
    USE SIGNAL ;
    PORT
      LAYER M5 ;
        RECT  121.248 0 121.272 0.084 ;
    END
  END r_data[107]
  PIN r_data[108]
    DIRECTION INPUT ;
    USE SIGNAL ;
    PORT
      LAYER M5 ;
        RECT  121.344 0 121.368 0.084 ;
    END
  END r_data[108]
  PIN r_data[109]
    DIRECTION INPUT ;
    USE SIGNAL ;
    PORT
      LAYER M5 ;
        RECT  121.44 0 121.464 0.084 ;
    END
  END r_data[109]
  PIN r_data[10]
    DIRECTION INPUT ;
    USE SIGNAL ;
    PORT
      LAYER M5 ;
        RECT  111.936 0 111.96 0.084 ;
    END
  END r_data[10]
  PIN r_data[110]
    DIRECTION INPUT ;
    USE SIGNAL ;
    PORT
      LAYER M5 ;
        RECT  121.536 0 121.56 0.084 ;
    END
  END r_data[110]
  PIN r_data[111]
    DIRECTION INPUT ;
    USE SIGNAL ;
    PORT
      LAYER M5 ;
        RECT  121.632 0 121.656 0.084 ;
    END
  END r_data[111]
  PIN r_data[112]
    DIRECTION INPUT ;
    USE SIGNAL ;
    PORT
      LAYER M5 ;
        RECT  121.728 0 121.752 0.084 ;
    END
  END r_data[112]
  PIN r_data[113]
    DIRECTION INPUT ;
    USE SIGNAL ;
    PORT
      LAYER M5 ;
        RECT  121.824 0 121.848 0.084 ;
    END
  END r_data[113]
  PIN r_data[114]
    DIRECTION INPUT ;
    USE SIGNAL ;
    PORT
      LAYER M5 ;
        RECT  121.92 0 121.944 0.084 ;
    END
  END r_data[114]
  PIN r_data[115]
    DIRECTION INPUT ;
    USE SIGNAL ;
    PORT
      LAYER M5 ;
        RECT  122.016 0 122.04 0.084 ;
    END
  END r_data[115]
  PIN r_data[116]
    DIRECTION INPUT ;
    USE SIGNAL ;
    PORT
      LAYER M5 ;
        RECT  122.112 0 122.136 0.084 ;
    END
  END r_data[116]
  PIN r_data[117]
    DIRECTION INPUT ;
    USE SIGNAL ;
    PORT
      LAYER M5 ;
        RECT  122.208 0 122.232 0.084 ;
    END
  END r_data[117]
  PIN r_data[118]
    DIRECTION INPUT ;
    USE SIGNAL ;
    PORT
      LAYER M5 ;
        RECT  122.304 0 122.328 0.084 ;
    END
  END r_data[118]
  PIN r_data[119]
    DIRECTION INPUT ;
    USE SIGNAL ;
    PORT
      LAYER M5 ;
        RECT  122.4 0 122.424 0.084 ;
    END
  END r_data[119]
  PIN r_data[11]
    DIRECTION INPUT ;
    USE SIGNAL ;
    PORT
      LAYER M5 ;
        RECT  112.032 0 112.056 0.084 ;
    END
  END r_data[11]
  PIN r_data[120]
    DIRECTION INPUT ;
    USE SIGNAL ;
    PORT
      LAYER M5 ;
        RECT  122.496 0 122.52 0.084 ;
    END
  END r_data[120]
  PIN r_data[121]
    DIRECTION INPUT ;
    USE SIGNAL ;
    PORT
      LAYER M5 ;
        RECT  122.592 0 122.616 0.084 ;
    END
  END r_data[121]
  PIN r_data[122]
    DIRECTION INPUT ;
    USE SIGNAL ;
    PORT
      LAYER M5 ;
        RECT  122.688 0 122.712 0.084 ;
    END
  END r_data[122]
  PIN r_data[123]
    DIRECTION INPUT ;
    USE SIGNAL ;
    PORT
      LAYER M5 ;
        RECT  122.784 0 122.808 0.084 ;
    END
  END r_data[123]
  PIN r_data[124]
    DIRECTION INPUT ;
    USE SIGNAL ;
    PORT
      LAYER M5 ;
        RECT  122.88 0 122.904 0.084 ;
    END
  END r_data[124]
  PIN r_data[125]
    DIRECTION INPUT ;
    USE SIGNAL ;
    PORT
      LAYER M5 ;
        RECT  122.976 0 123 0.084 ;
    END
  END r_data[125]
  PIN r_data[126]
    DIRECTION INPUT ;
    USE SIGNAL ;
    PORT
      LAYER M5 ;
        RECT  123.072 0 123.096 0.084 ;
    END
  END r_data[126]
  PIN r_data[127]
    DIRECTION INPUT ;
    USE SIGNAL ;
    PORT
      LAYER M5 ;
        RECT  123.168 0 123.192 0.084 ;
    END
  END r_data[127]
  PIN r_data[128]
    DIRECTION INPUT ;
    USE SIGNAL ;
    PORT
      LAYER M5 ;
        RECT  123.264 0 123.288 0.084 ;
    END
  END r_data[128]
  PIN r_data[129]
    DIRECTION INPUT ;
    USE SIGNAL ;
    PORT
      LAYER M5 ;
        RECT  123.36 0 123.384 0.084 ;
    END
  END r_data[129]
  PIN r_data[12]
    DIRECTION INPUT ;
    USE SIGNAL ;
    PORT
      LAYER M5 ;
        RECT  112.128 0 112.152 0.084 ;
    END
  END r_data[12]
  PIN r_data[130]
    DIRECTION INPUT ;
    USE SIGNAL ;
    PORT
      LAYER M5 ;
        RECT  123.456 0 123.48 0.084 ;
    END
  END r_data[130]
  PIN r_data[131]
    DIRECTION INPUT ;
    USE SIGNAL ;
    PORT
      LAYER M5 ;
        RECT  123.552 0 123.576 0.084 ;
    END
  END r_data[131]
  PIN r_data[132]
    DIRECTION INPUT ;
    USE SIGNAL ;
    PORT
      LAYER M5 ;
        RECT  123.648 0 123.672 0.084 ;
    END
  END r_data[132]
  PIN r_data[133]
    DIRECTION INPUT ;
    USE SIGNAL ;
    PORT
      LAYER M5 ;
        RECT  123.744 0 123.768 0.084 ;
    END
  END r_data[133]
  PIN r_data[134]
    DIRECTION INPUT ;
    USE SIGNAL ;
    PORT
      LAYER M5 ;
        RECT  123.84 0 123.864 0.084 ;
    END
  END r_data[134]
  PIN r_data[135]
    DIRECTION INPUT ;
    USE SIGNAL ;
    PORT
      LAYER M5 ;
        RECT  123.936 0 123.96 0.084 ;
    END
  END r_data[135]
  PIN r_data[136]
    DIRECTION INPUT ;
    USE SIGNAL ;
    PORT
      LAYER M5 ;
        RECT  124.032 0 124.056 0.084 ;
    END
  END r_data[136]
  PIN r_data[137]
    DIRECTION INPUT ;
    USE SIGNAL ;
    PORT
      LAYER M5 ;
        RECT  124.128 0 124.152 0.084 ;
    END
  END r_data[137]
  PIN r_data[138]
    DIRECTION INPUT ;
    USE SIGNAL ;
    PORT
      LAYER M5 ;
        RECT  124.224 0 124.248 0.084 ;
    END
  END r_data[138]
  PIN r_data[139]
    DIRECTION INPUT ;
    USE SIGNAL ;
    PORT
      LAYER M5 ;
        RECT  124.32 0 124.344 0.084 ;
    END
  END r_data[139]
  PIN r_data[13]
    DIRECTION INPUT ;
    USE SIGNAL ;
    PORT
      LAYER M5 ;
        RECT  112.224 0 112.248 0.084 ;
    END
  END r_data[13]
  PIN r_data[140]
    DIRECTION INPUT ;
    USE SIGNAL ;
    PORT
      LAYER M5 ;
        RECT  124.416 0 124.44 0.084 ;
    END
  END r_data[140]
  PIN r_data[141]
    DIRECTION INPUT ;
    USE SIGNAL ;
    PORT
      LAYER M5 ;
        RECT  124.512 0 124.536 0.084 ;
    END
  END r_data[141]
  PIN r_data[142]
    DIRECTION INPUT ;
    USE SIGNAL ;
    PORT
      LAYER M5 ;
        RECT  124.608 0 124.632 0.084 ;
    END
  END r_data[142]
  PIN r_data[143]
    DIRECTION INPUT ;
    USE SIGNAL ;
    PORT
      LAYER M5 ;
        RECT  124.704 0 124.728 0.084 ;
    END
  END r_data[143]
  PIN r_data[144]
    DIRECTION INPUT ;
    USE SIGNAL ;
    PORT
      LAYER M5 ;
        RECT  124.8 0 124.824 0.084 ;
    END
  END r_data[144]
  PIN r_data[145]
    DIRECTION INPUT ;
    USE SIGNAL ;
    PORT
      LAYER M5 ;
        RECT  124.896 0 124.92 0.084 ;
    END
  END r_data[145]
  PIN r_data[146]
    DIRECTION INPUT ;
    USE SIGNAL ;
    PORT
      LAYER M5 ;
        RECT  124.992 0 125.016 0.084 ;
    END
  END r_data[146]
  PIN r_data[147]
    DIRECTION INPUT ;
    USE SIGNAL ;
    PORT
      LAYER M5 ;
        RECT  125.088 0 125.112 0.084 ;
    END
  END r_data[147]
  PIN r_data[148]
    DIRECTION INPUT ;
    USE SIGNAL ;
    PORT
      LAYER M5 ;
        RECT  125.184 0 125.208 0.084 ;
    END
  END r_data[148]
  PIN r_data[149]
    DIRECTION INPUT ;
    USE SIGNAL ;
    PORT
      LAYER M5 ;
        RECT  125.28 0 125.304 0.084 ;
    END
  END r_data[149]
  PIN r_data[14]
    DIRECTION INPUT ;
    USE SIGNAL ;
    PORT
      LAYER M5 ;
        RECT  112.32 0 112.344 0.084 ;
    END
  END r_data[14]
  PIN r_data[150]
    DIRECTION INPUT ;
    USE SIGNAL ;
    PORT
      LAYER M5 ;
        RECT  125.376 0 125.4 0.084 ;
    END
  END r_data[150]
  PIN r_data[151]
    DIRECTION INPUT ;
    USE SIGNAL ;
    PORT
      LAYER M5 ;
        RECT  125.472 0 125.496 0.084 ;
    END
  END r_data[151]
  PIN r_data[152]
    DIRECTION INPUT ;
    USE SIGNAL ;
    PORT
      LAYER M5 ;
        RECT  125.568 0 125.592 0.084 ;
    END
  END r_data[152]
  PIN r_data[153]
    DIRECTION INPUT ;
    USE SIGNAL ;
    PORT
      LAYER M5 ;
        RECT  125.664 0 125.688 0.084 ;
    END
  END r_data[153]
  PIN r_data[154]
    DIRECTION INPUT ;
    USE SIGNAL ;
    PORT
      LAYER M5 ;
        RECT  125.76 0 125.784 0.084 ;
    END
  END r_data[154]
  PIN r_data[155]
    DIRECTION INPUT ;
    USE SIGNAL ;
    PORT
      LAYER M5 ;
        RECT  125.856 0 125.88 0.084 ;
    END
  END r_data[155]
  PIN r_data[156]
    DIRECTION INPUT ;
    USE SIGNAL ;
    PORT
      LAYER M5 ;
        RECT  125.952 0 125.976 0.084 ;
    END
  END r_data[156]
  PIN r_data[157]
    DIRECTION INPUT ;
    USE SIGNAL ;
    PORT
      LAYER M5 ;
        RECT  126.048 0 126.072 0.084 ;
    END
  END r_data[157]
  PIN r_data[158]
    DIRECTION INPUT ;
    USE SIGNAL ;
    PORT
      LAYER M5 ;
        RECT  126.144 0 126.168 0.084 ;
    END
  END r_data[158]
  PIN r_data[159]
    DIRECTION INPUT ;
    USE SIGNAL ;
    PORT
      LAYER M5 ;
        RECT  126.24 0 126.264 0.084 ;
    END
  END r_data[159]
  PIN r_data[15]
    DIRECTION INPUT ;
    USE SIGNAL ;
    PORT
      LAYER M5 ;
        RECT  112.416 0 112.44 0.084 ;
    END
  END r_data[15]
  PIN r_data[160]
    DIRECTION INPUT ;
    USE SIGNAL ;
    PORT
      LAYER M5 ;
        RECT  126.336 0 126.36 0.084 ;
    END
  END r_data[160]
  PIN r_data[161]
    DIRECTION INPUT ;
    USE SIGNAL ;
    PORT
      LAYER M5 ;
        RECT  126.432 0 126.456 0.084 ;
    END
  END r_data[161]
  PIN r_data[162]
    DIRECTION INPUT ;
    USE SIGNAL ;
    PORT
      LAYER M5 ;
        RECT  126.528 0 126.552 0.084 ;
    END
  END r_data[162]
  PIN r_data[163]
    DIRECTION INPUT ;
    USE SIGNAL ;
    PORT
      LAYER M5 ;
        RECT  126.624 0 126.648 0.084 ;
    END
  END r_data[163]
  PIN r_data[164]
    DIRECTION INPUT ;
    USE SIGNAL ;
    PORT
      LAYER M5 ;
        RECT  126.72 0 126.744 0.084 ;
    END
  END r_data[164]
  PIN r_data[165]
    DIRECTION INPUT ;
    USE SIGNAL ;
    PORT
      LAYER M5 ;
        RECT  126.816 0 126.84 0.084 ;
    END
  END r_data[165]
  PIN r_data[166]
    DIRECTION INPUT ;
    USE SIGNAL ;
    PORT
      LAYER M5 ;
        RECT  126.912 0 126.936 0.084 ;
    END
  END r_data[166]
  PIN r_data[167]
    DIRECTION INPUT ;
    USE SIGNAL ;
    PORT
      LAYER M5 ;
        RECT  127.008 0 127.032 0.084 ;
    END
  END r_data[167]
  PIN r_data[168]
    DIRECTION INPUT ;
    USE SIGNAL ;
    PORT
      LAYER M5 ;
        RECT  127.104 0 127.128 0.084 ;
    END
  END r_data[168]
  PIN r_data[169]
    DIRECTION INPUT ;
    USE SIGNAL ;
    PORT
      LAYER M5 ;
        RECT  127.2 0 127.224 0.084 ;
    END
  END r_data[169]
  PIN r_data[16]
    DIRECTION INPUT ;
    USE SIGNAL ;
    PORT
      LAYER M5 ;
        RECT  112.512 0 112.536 0.084 ;
    END
  END r_data[16]
  PIN r_data[170]
    DIRECTION INPUT ;
    USE SIGNAL ;
    PORT
      LAYER M5 ;
        RECT  127.296 0 127.32 0.084 ;
    END
  END r_data[170]
  PIN r_data[171]
    DIRECTION INPUT ;
    USE SIGNAL ;
    PORT
      LAYER M5 ;
        RECT  127.392 0 127.416 0.084 ;
    END
  END r_data[171]
  PIN r_data[172]
    DIRECTION INPUT ;
    USE SIGNAL ;
    PORT
      LAYER M5 ;
        RECT  127.488 0 127.512 0.084 ;
    END
  END r_data[172]
  PIN r_data[173]
    DIRECTION INPUT ;
    USE SIGNAL ;
    PORT
      LAYER M5 ;
        RECT  127.584 0 127.608 0.084 ;
    END
  END r_data[173]
  PIN r_data[174]
    DIRECTION INPUT ;
    USE SIGNAL ;
    PORT
      LAYER M5 ;
        RECT  127.68 0 127.704 0.084 ;
    END
  END r_data[174]
  PIN r_data[175]
    DIRECTION INPUT ;
    USE SIGNAL ;
    PORT
      LAYER M5 ;
        RECT  127.776 0 127.8 0.084 ;
    END
  END r_data[175]
  PIN r_data[176]
    DIRECTION INPUT ;
    USE SIGNAL ;
    PORT
      LAYER M5 ;
        RECT  127.872 0 127.896 0.084 ;
    END
  END r_data[176]
  PIN r_data[177]
    DIRECTION INPUT ;
    USE SIGNAL ;
    PORT
      LAYER M5 ;
        RECT  127.968 0 127.992 0.084 ;
    END
  END r_data[177]
  PIN r_data[178]
    DIRECTION INPUT ;
    USE SIGNAL ;
    PORT
      LAYER M5 ;
        RECT  128.064 0 128.088 0.084 ;
    END
  END r_data[178]
  PIN r_data[179]
    DIRECTION INPUT ;
    USE SIGNAL ;
    PORT
      LAYER M5 ;
        RECT  128.16 0 128.184 0.084 ;
    END
  END r_data[179]
  PIN r_data[17]
    DIRECTION INPUT ;
    USE SIGNAL ;
    PORT
      LAYER M5 ;
        RECT  112.608 0 112.632 0.084 ;
    END
  END r_data[17]
  PIN r_data[180]
    DIRECTION INPUT ;
    USE SIGNAL ;
    PORT
      LAYER M5 ;
        RECT  128.256 0 128.28 0.084 ;
    END
  END r_data[180]
  PIN r_data[181]
    DIRECTION INPUT ;
    USE SIGNAL ;
    PORT
      LAYER M5 ;
        RECT  128.352 0 128.376 0.084 ;
    END
  END r_data[181]
  PIN r_data[182]
    DIRECTION INPUT ;
    USE SIGNAL ;
    PORT
      LAYER M5 ;
        RECT  128.448 0 128.472 0.084 ;
    END
  END r_data[182]
  PIN r_data[183]
    DIRECTION INPUT ;
    USE SIGNAL ;
    PORT
      LAYER M5 ;
        RECT  128.544 0 128.568 0.084 ;
    END
  END r_data[183]
  PIN r_data[184]
    DIRECTION INPUT ;
    USE SIGNAL ;
    PORT
      LAYER M5 ;
        RECT  128.64 0 128.664 0.084 ;
    END
  END r_data[184]
  PIN r_data[185]
    DIRECTION INPUT ;
    USE SIGNAL ;
    PORT
      LAYER M5 ;
        RECT  128.736 0 128.76 0.084 ;
    END
  END r_data[185]
  PIN r_data[186]
    DIRECTION INPUT ;
    USE SIGNAL ;
    PORT
      LAYER M5 ;
        RECT  128.832 0 128.856 0.084 ;
    END
  END r_data[186]
  PIN r_data[187]
    DIRECTION INPUT ;
    USE SIGNAL ;
    PORT
      LAYER M5 ;
        RECT  128.928 0 128.952 0.084 ;
    END
  END r_data[187]
  PIN r_data[188]
    DIRECTION INPUT ;
    USE SIGNAL ;
    PORT
      LAYER M5 ;
        RECT  129.024 0 129.048 0.084 ;
    END
  END r_data[188]
  PIN r_data[189]
    DIRECTION INPUT ;
    USE SIGNAL ;
    PORT
      LAYER M5 ;
        RECT  129.12 0 129.144 0.084 ;
    END
  END r_data[189]
  PIN r_data[18]
    DIRECTION INPUT ;
    USE SIGNAL ;
    PORT
      LAYER M5 ;
        RECT  112.704 0 112.728 0.084 ;
    END
  END r_data[18]
  PIN r_data[190]
    DIRECTION INPUT ;
    USE SIGNAL ;
    PORT
      LAYER M5 ;
        RECT  129.216 0 129.24 0.084 ;
    END
  END r_data[190]
  PIN r_data[191]
    DIRECTION INPUT ;
    USE SIGNAL ;
    PORT
      LAYER M5 ;
        RECT  129.312 0 129.336 0.084 ;
    END
  END r_data[191]
  PIN r_data[192]
    DIRECTION INPUT ;
    USE SIGNAL ;
    PORT
      LAYER M5 ;
        RECT  129.408 0 129.432 0.084 ;
    END
  END r_data[192]
  PIN r_data[193]
    DIRECTION INPUT ;
    USE SIGNAL ;
    PORT
      LAYER M5 ;
        RECT  129.504 0 129.528 0.084 ;
    END
  END r_data[193]
  PIN r_data[194]
    DIRECTION INPUT ;
    USE SIGNAL ;
    PORT
      LAYER M5 ;
        RECT  129.6 0 129.624 0.084 ;
    END
  END r_data[194]
  PIN r_data[195]
    DIRECTION INPUT ;
    USE SIGNAL ;
    PORT
      LAYER M5 ;
        RECT  129.696 0 129.72 0.084 ;
    END
  END r_data[195]
  PIN r_data[196]
    DIRECTION INPUT ;
    USE SIGNAL ;
    PORT
      LAYER M5 ;
        RECT  129.792 0 129.816 0.084 ;
    END
  END r_data[196]
  PIN r_data[197]
    DIRECTION INPUT ;
    USE SIGNAL ;
    PORT
      LAYER M5 ;
        RECT  129.888 0 129.912 0.084 ;
    END
  END r_data[197]
  PIN r_data[198]
    DIRECTION INPUT ;
    USE SIGNAL ;
    PORT
      LAYER M5 ;
        RECT  129.984 0 130.008 0.084 ;
    END
  END r_data[198]
  PIN r_data[199]
    DIRECTION INPUT ;
    USE SIGNAL ;
    PORT
      LAYER M5 ;
        RECT  130.08 0 130.104 0.084 ;
    END
  END r_data[199]
  PIN r_data[19]
    DIRECTION INPUT ;
    USE SIGNAL ;
    PORT
      LAYER M5 ;
        RECT  112.8 0 112.824 0.084 ;
    END
  END r_data[19]
  PIN r_data[1]
    DIRECTION INPUT ;
    USE SIGNAL ;
    PORT
      LAYER M5 ;
        RECT  111.072 0 111.096 0.084 ;
    END
  END r_data[1]
  PIN r_data[200]
    DIRECTION INPUT ;
    USE SIGNAL ;
    PORT
      LAYER M5 ;
        RECT  130.176 0 130.2 0.084 ;
    END
  END r_data[200]
  PIN r_data[201]
    DIRECTION INPUT ;
    USE SIGNAL ;
    PORT
      LAYER M5 ;
        RECT  130.272 0 130.296 0.084 ;
    END
  END r_data[201]
  PIN r_data[202]
    DIRECTION INPUT ;
    USE SIGNAL ;
    PORT
      LAYER M5 ;
        RECT  130.368 0 130.392 0.084 ;
    END
  END r_data[202]
  PIN r_data[203]
    DIRECTION INPUT ;
    USE SIGNAL ;
    PORT
      LAYER M5 ;
        RECT  130.464 0 130.488 0.084 ;
    END
  END r_data[203]
  PIN r_data[204]
    DIRECTION INPUT ;
    USE SIGNAL ;
    PORT
      LAYER M5 ;
        RECT  130.56 0 130.584 0.084 ;
    END
  END r_data[204]
  PIN r_data[205]
    DIRECTION INPUT ;
    USE SIGNAL ;
    PORT
      LAYER M5 ;
        RECT  130.656 0 130.68 0.084 ;
    END
  END r_data[205]
  PIN r_data[206]
    DIRECTION INPUT ;
    USE SIGNAL ;
    PORT
      LAYER M5 ;
        RECT  130.752 0 130.776 0.084 ;
    END
  END r_data[206]
  PIN r_data[207]
    DIRECTION INPUT ;
    USE SIGNAL ;
    PORT
      LAYER M5 ;
        RECT  130.848 0 130.872 0.084 ;
    END
  END r_data[207]
  PIN r_data[208]
    DIRECTION INPUT ;
    USE SIGNAL ;
    PORT
      LAYER M5 ;
        RECT  130.944 0 130.968 0.084 ;
    END
  END r_data[208]
  PIN r_data[209]
    DIRECTION INPUT ;
    USE SIGNAL ;
    PORT
      LAYER M5 ;
        RECT  131.04 0 131.064 0.084 ;
    END
  END r_data[209]
  PIN r_data[20]
    DIRECTION INPUT ;
    USE SIGNAL ;
    PORT
      LAYER M5 ;
        RECT  112.896 0 112.92 0.084 ;
    END
  END r_data[20]
  PIN r_data[210]
    DIRECTION INPUT ;
    USE SIGNAL ;
    PORT
      LAYER M5 ;
        RECT  131.136 0 131.16 0.084 ;
    END
  END r_data[210]
  PIN r_data[211]
    DIRECTION INPUT ;
    USE SIGNAL ;
    PORT
      LAYER M5 ;
        RECT  131.232 0 131.256 0.084 ;
    END
  END r_data[211]
  PIN r_data[212]
    DIRECTION INPUT ;
    USE SIGNAL ;
    PORT
      LAYER M5 ;
        RECT  131.328 0 131.352 0.084 ;
    END
  END r_data[212]
  PIN r_data[213]
    DIRECTION INPUT ;
    USE SIGNAL ;
    PORT
      LAYER M5 ;
        RECT  131.424 0 131.448 0.084 ;
    END
  END r_data[213]
  PIN r_data[214]
    DIRECTION INPUT ;
    USE SIGNAL ;
    PORT
      LAYER M5 ;
        RECT  131.52 0 131.544 0.084 ;
    END
  END r_data[214]
  PIN r_data[215]
    DIRECTION INPUT ;
    USE SIGNAL ;
    PORT
      LAYER M5 ;
        RECT  131.616 0 131.64 0.084 ;
    END
  END r_data[215]
  PIN r_data[216]
    DIRECTION INPUT ;
    USE SIGNAL ;
    PORT
      LAYER M5 ;
        RECT  131.712 0 131.736 0.084 ;
    END
  END r_data[216]
  PIN r_data[217]
    DIRECTION INPUT ;
    USE SIGNAL ;
    PORT
      LAYER M5 ;
        RECT  131.808 0 131.832 0.084 ;
    END
  END r_data[217]
  PIN r_data[218]
    DIRECTION INPUT ;
    USE SIGNAL ;
    PORT
      LAYER M5 ;
        RECT  131.904 0 131.928 0.084 ;
    END
  END r_data[218]
  PIN r_data[219]
    DIRECTION INPUT ;
    USE SIGNAL ;
    PORT
      LAYER M5 ;
        RECT  132 0 132.024 0.084 ;
    END
  END r_data[219]
  PIN r_data[21]
    DIRECTION INPUT ;
    USE SIGNAL ;
    PORT
      LAYER M5 ;
        RECT  112.992 0 113.016 0.084 ;
    END
  END r_data[21]
  PIN r_data[220]
    DIRECTION INPUT ;
    USE SIGNAL ;
    PORT
      LAYER M5 ;
        RECT  132.096 0 132.12 0.084 ;
    END
  END r_data[220]
  PIN r_data[221]
    DIRECTION INPUT ;
    USE SIGNAL ;
    PORT
      LAYER M5 ;
        RECT  132.192 0 132.216 0.084 ;
    END
  END r_data[221]
  PIN r_data[222]
    DIRECTION INPUT ;
    USE SIGNAL ;
    PORT
      LAYER M5 ;
        RECT  132.288 0 132.312 0.084 ;
    END
  END r_data[222]
  PIN r_data[223]
    DIRECTION INPUT ;
    USE SIGNAL ;
    PORT
      LAYER M5 ;
        RECT  132.384 0 132.408 0.084 ;
    END
  END r_data[223]
  PIN r_data[224]
    DIRECTION INPUT ;
    USE SIGNAL ;
    PORT
      LAYER M5 ;
        RECT  132.48 0 132.504 0.084 ;
    END
  END r_data[224]
  PIN r_data[225]
    DIRECTION INPUT ;
    USE SIGNAL ;
    PORT
      LAYER M5 ;
        RECT  132.576 0 132.6 0.084 ;
    END
  END r_data[225]
  PIN r_data[226]
    DIRECTION INPUT ;
    USE SIGNAL ;
    PORT
      LAYER M5 ;
        RECT  132.672 0 132.696 0.084 ;
    END
  END r_data[226]
  PIN r_data[227]
    DIRECTION INPUT ;
    USE SIGNAL ;
    PORT
      LAYER M5 ;
        RECT  132.768 0 132.792 0.084 ;
    END
  END r_data[227]
  PIN r_data[228]
    DIRECTION INPUT ;
    USE SIGNAL ;
    PORT
      LAYER M5 ;
        RECT  132.864 0 132.888 0.084 ;
    END
  END r_data[228]
  PIN r_data[229]
    DIRECTION INPUT ;
    USE SIGNAL ;
    PORT
      LAYER M5 ;
        RECT  132.96 0 132.984 0.084 ;
    END
  END r_data[229]
  PIN r_data[22]
    DIRECTION INPUT ;
    USE SIGNAL ;
    PORT
      LAYER M5 ;
        RECT  113.088 0 113.112 0.084 ;
    END
  END r_data[22]
  PIN r_data[230]
    DIRECTION INPUT ;
    USE SIGNAL ;
    PORT
      LAYER M5 ;
        RECT  133.056 0 133.08 0.084 ;
    END
  END r_data[230]
  PIN r_data[231]
    DIRECTION INPUT ;
    USE SIGNAL ;
    PORT
      LAYER M5 ;
        RECT  133.152 0 133.176 0.084 ;
    END
  END r_data[231]
  PIN r_data[232]
    DIRECTION INPUT ;
    USE SIGNAL ;
    PORT
      LAYER M5 ;
        RECT  133.248 0 133.272 0.084 ;
    END
  END r_data[232]
  PIN r_data[233]
    DIRECTION INPUT ;
    USE SIGNAL ;
    PORT
      LAYER M5 ;
        RECT  133.344 0 133.368 0.084 ;
    END
  END r_data[233]
  PIN r_data[234]
    DIRECTION INPUT ;
    USE SIGNAL ;
    PORT
      LAYER M5 ;
        RECT  133.44 0 133.464 0.084 ;
    END
  END r_data[234]
  PIN r_data[235]
    DIRECTION INPUT ;
    USE SIGNAL ;
    PORT
      LAYER M5 ;
        RECT  133.536 0 133.56 0.084 ;
    END
  END r_data[235]
  PIN r_data[236]
    DIRECTION INPUT ;
    USE SIGNAL ;
    PORT
      LAYER M5 ;
        RECT  133.632 0 133.656 0.084 ;
    END
  END r_data[236]
  PIN r_data[237]
    DIRECTION INPUT ;
    USE SIGNAL ;
    PORT
      LAYER M5 ;
        RECT  133.728 0 133.752 0.084 ;
    END
  END r_data[237]
  PIN r_data[238]
    DIRECTION INPUT ;
    USE SIGNAL ;
    PORT
      LAYER M5 ;
        RECT  133.824 0 133.848 0.084 ;
    END
  END r_data[238]
  PIN r_data[239]
    DIRECTION INPUT ;
    USE SIGNAL ;
    PORT
      LAYER M5 ;
        RECT  133.92 0 133.944 0.084 ;
    END
  END r_data[239]
  PIN r_data[23]
    DIRECTION INPUT ;
    USE SIGNAL ;
    PORT
      LAYER M5 ;
        RECT  113.184 0 113.208 0.084 ;
    END
  END r_data[23]
  PIN r_data[240]
    DIRECTION INPUT ;
    USE SIGNAL ;
    PORT
      LAYER M5 ;
        RECT  134.016 0 134.04 0.084 ;
    END
  END r_data[240]
  PIN r_data[241]
    DIRECTION INPUT ;
    USE SIGNAL ;
    PORT
      LAYER M5 ;
        RECT  134.112 0 134.136 0.084 ;
    END
  END r_data[241]
  PIN r_data[242]
    DIRECTION INPUT ;
    USE SIGNAL ;
    PORT
      LAYER M5 ;
        RECT  134.208 0 134.232 0.084 ;
    END
  END r_data[242]
  PIN r_data[243]
    DIRECTION INPUT ;
    USE SIGNAL ;
    PORT
      LAYER M5 ;
        RECT  134.304 0 134.328 0.084 ;
    END
  END r_data[243]
  PIN r_data[244]
    DIRECTION INPUT ;
    USE SIGNAL ;
    PORT
      LAYER M5 ;
        RECT  134.4 0 134.424 0.084 ;
    END
  END r_data[244]
  PIN r_data[245]
    DIRECTION INPUT ;
    USE SIGNAL ;
    PORT
      LAYER M5 ;
        RECT  134.496 0 134.52 0.084 ;
    END
  END r_data[245]
  PIN r_data[246]
    DIRECTION INPUT ;
    USE SIGNAL ;
    PORT
      LAYER M5 ;
        RECT  134.592 0 134.616 0.084 ;
    END
  END r_data[246]
  PIN r_data[247]
    DIRECTION INPUT ;
    USE SIGNAL ;
    PORT
      LAYER M5 ;
        RECT  134.688 0 134.712 0.084 ;
    END
  END r_data[247]
  PIN r_data[248]
    DIRECTION INPUT ;
    USE SIGNAL ;
    PORT
      LAYER M5 ;
        RECT  134.784 0 134.808 0.084 ;
    END
  END r_data[248]
  PIN r_data[249]
    DIRECTION INPUT ;
    USE SIGNAL ;
    PORT
      LAYER M5 ;
        RECT  134.88 0 134.904 0.084 ;
    END
  END r_data[249]
  PIN r_data[24]
    DIRECTION INPUT ;
    USE SIGNAL ;
    PORT
      LAYER M5 ;
        RECT  113.28 0 113.304 0.084 ;
    END
  END r_data[24]
  PIN r_data[250]
    DIRECTION INPUT ;
    USE SIGNAL ;
    PORT
      LAYER M5 ;
        RECT  134.976 0 135 0.084 ;
    END
  END r_data[250]
  PIN r_data[251]
    DIRECTION INPUT ;
    USE SIGNAL ;
    PORT
      LAYER M5 ;
        RECT  135.072 0 135.096 0.084 ;
    END
  END r_data[251]
  PIN r_data[252]
    DIRECTION INPUT ;
    USE SIGNAL ;
    PORT
      LAYER M5 ;
        RECT  135.168 0 135.192 0.084 ;
    END
  END r_data[252]
  PIN r_data[253]
    DIRECTION INPUT ;
    USE SIGNAL ;
    PORT
      LAYER M5 ;
        RECT  135.264 0 135.288 0.084 ;
    END
  END r_data[253]
  PIN r_data[254]
    DIRECTION INPUT ;
    USE SIGNAL ;
    PORT
      LAYER M5 ;
        RECT  135.36 0 135.384 0.084 ;
    END
  END r_data[254]
  PIN r_data[255]
    DIRECTION INPUT ;
    USE SIGNAL ;
    PORT
      LAYER M5 ;
        RECT  135.456 0 135.48 0.084 ;
    END
  END r_data[255]
  PIN r_data[25]
    DIRECTION INPUT ;
    USE SIGNAL ;
    PORT
      LAYER M5 ;
        RECT  113.376 0 113.4 0.084 ;
    END
  END r_data[25]
  PIN r_data[26]
    DIRECTION INPUT ;
    USE SIGNAL ;
    PORT
      LAYER M5 ;
        RECT  113.472 0 113.496 0.084 ;
    END
  END r_data[26]
  PIN r_data[27]
    DIRECTION INPUT ;
    USE SIGNAL ;
    PORT
      LAYER M5 ;
        RECT  113.568 0 113.592 0.084 ;
    END
  END r_data[27]
  PIN r_data[28]
    DIRECTION INPUT ;
    USE SIGNAL ;
    PORT
      LAYER M5 ;
        RECT  113.664 0 113.688 0.084 ;
    END
  END r_data[28]
  PIN r_data[29]
    DIRECTION INPUT ;
    USE SIGNAL ;
    PORT
      LAYER M5 ;
        RECT  113.76 0 113.784 0.084 ;
    END
  END r_data[29]
  PIN r_data[2]
    DIRECTION INPUT ;
    USE SIGNAL ;
    PORT
      LAYER M5 ;
        RECT  111.168 0 111.192 0.084 ;
    END
  END r_data[2]
  PIN r_data[30]
    DIRECTION INPUT ;
    USE SIGNAL ;
    PORT
      LAYER M5 ;
        RECT  113.856 0 113.88 0.084 ;
    END
  END r_data[30]
  PIN r_data[31]
    DIRECTION INPUT ;
    USE SIGNAL ;
    PORT
      LAYER M5 ;
        RECT  113.952 0 113.976 0.084 ;
    END
  END r_data[31]
  PIN r_data[32]
    DIRECTION INPUT ;
    USE SIGNAL ;
    PORT
      LAYER M5 ;
        RECT  114.048 0 114.072 0.084 ;
    END
  END r_data[32]
  PIN r_data[33]
    DIRECTION INPUT ;
    USE SIGNAL ;
    PORT
      LAYER M5 ;
        RECT  114.144 0 114.168 0.084 ;
    END
  END r_data[33]
  PIN r_data[34]
    DIRECTION INPUT ;
    USE SIGNAL ;
    PORT
      LAYER M5 ;
        RECT  114.24 0 114.264 0.084 ;
    END
  END r_data[34]
  PIN r_data[35]
    DIRECTION INPUT ;
    USE SIGNAL ;
    PORT
      LAYER M5 ;
        RECT  114.336 0 114.36 0.084 ;
    END
  END r_data[35]
  PIN r_data[36]
    DIRECTION INPUT ;
    USE SIGNAL ;
    PORT
      LAYER M5 ;
        RECT  114.432 0 114.456 0.084 ;
    END
  END r_data[36]
  PIN r_data[37]
    DIRECTION INPUT ;
    USE SIGNAL ;
    PORT
      LAYER M5 ;
        RECT  114.528 0 114.552 0.084 ;
    END
  END r_data[37]
  PIN r_data[38]
    DIRECTION INPUT ;
    USE SIGNAL ;
    PORT
      LAYER M5 ;
        RECT  114.624 0 114.648 0.084 ;
    END
  END r_data[38]
  PIN r_data[39]
    DIRECTION INPUT ;
    USE SIGNAL ;
    PORT
      LAYER M5 ;
        RECT  114.72 0 114.744 0.084 ;
    END
  END r_data[39]
  PIN r_data[3]
    DIRECTION INPUT ;
    USE SIGNAL ;
    PORT
      LAYER M5 ;
        RECT  111.264 0 111.288 0.084 ;
    END
  END r_data[3]
  PIN r_data[40]
    DIRECTION INPUT ;
    USE SIGNAL ;
    PORT
      LAYER M5 ;
        RECT  114.816 0 114.84 0.084 ;
    END
  END r_data[40]
  PIN r_data[41]
    DIRECTION INPUT ;
    USE SIGNAL ;
    PORT
      LAYER M5 ;
        RECT  114.912 0 114.936 0.084 ;
    END
  END r_data[41]
  PIN r_data[42]
    DIRECTION INPUT ;
    USE SIGNAL ;
    PORT
      LAYER M5 ;
        RECT  115.008 0 115.032 0.084 ;
    END
  END r_data[42]
  PIN r_data[43]
    DIRECTION INPUT ;
    USE SIGNAL ;
    PORT
      LAYER M5 ;
        RECT  115.104 0 115.128 0.084 ;
    END
  END r_data[43]
  PIN r_data[44]
    DIRECTION INPUT ;
    USE SIGNAL ;
    PORT
      LAYER M5 ;
        RECT  115.2 0 115.224 0.084 ;
    END
  END r_data[44]
  PIN r_data[45]
    DIRECTION INPUT ;
    USE SIGNAL ;
    PORT
      LAYER M5 ;
        RECT  115.296 0 115.32 0.084 ;
    END
  END r_data[45]
  PIN r_data[46]
    DIRECTION INPUT ;
    USE SIGNAL ;
    PORT
      LAYER M5 ;
        RECT  115.392 0 115.416 0.084 ;
    END
  END r_data[46]
  PIN r_data[47]
    DIRECTION INPUT ;
    USE SIGNAL ;
    PORT
      LAYER M5 ;
        RECT  115.488 0 115.512 0.084 ;
    END
  END r_data[47]
  PIN r_data[48]
    DIRECTION INPUT ;
    USE SIGNAL ;
    PORT
      LAYER M5 ;
        RECT  115.584 0 115.608 0.084 ;
    END
  END r_data[48]
  PIN r_data[49]
    DIRECTION INPUT ;
    USE SIGNAL ;
    PORT
      LAYER M5 ;
        RECT  115.68 0 115.704 0.084 ;
    END
  END r_data[49]
  PIN r_data[4]
    DIRECTION INPUT ;
    USE SIGNAL ;
    PORT
      LAYER M5 ;
        RECT  111.36 0 111.384 0.084 ;
    END
  END r_data[4]
  PIN r_data[50]
    DIRECTION INPUT ;
    USE SIGNAL ;
    PORT
      LAYER M5 ;
        RECT  115.776 0 115.8 0.084 ;
    END
  END r_data[50]
  PIN r_data[51]
    DIRECTION INPUT ;
    USE SIGNAL ;
    PORT
      LAYER M5 ;
        RECT  115.872 0 115.896 0.084 ;
    END
  END r_data[51]
  PIN r_data[52]
    DIRECTION INPUT ;
    USE SIGNAL ;
    PORT
      LAYER M5 ;
        RECT  115.968 0 115.992 0.084 ;
    END
  END r_data[52]
  PIN r_data[53]
    DIRECTION INPUT ;
    USE SIGNAL ;
    PORT
      LAYER M5 ;
        RECT  116.064 0 116.088 0.084 ;
    END
  END r_data[53]
  PIN r_data[54]
    DIRECTION INPUT ;
    USE SIGNAL ;
    PORT
      LAYER M5 ;
        RECT  116.16 0 116.184 0.084 ;
    END
  END r_data[54]
  PIN r_data[55]
    DIRECTION INPUT ;
    USE SIGNAL ;
    PORT
      LAYER M5 ;
        RECT  116.256 0 116.28 0.084 ;
    END
  END r_data[55]
  PIN r_data[56]
    DIRECTION INPUT ;
    USE SIGNAL ;
    PORT
      LAYER M5 ;
        RECT  116.352 0 116.376 0.084 ;
    END
  END r_data[56]
  PIN r_data[57]
    DIRECTION INPUT ;
    USE SIGNAL ;
    PORT
      LAYER M5 ;
        RECT  116.448 0 116.472 0.084 ;
    END
  END r_data[57]
  PIN r_data[58]
    DIRECTION INPUT ;
    USE SIGNAL ;
    PORT
      LAYER M5 ;
        RECT  116.544 0 116.568 0.084 ;
    END
  END r_data[58]
  PIN r_data[59]
    DIRECTION INPUT ;
    USE SIGNAL ;
    PORT
      LAYER M5 ;
        RECT  116.64 0 116.664 0.084 ;
    END
  END r_data[59]
  PIN r_data[5]
    DIRECTION INPUT ;
    USE SIGNAL ;
    PORT
      LAYER M5 ;
        RECT  111.456 0 111.48 0.084 ;
    END
  END r_data[5]
  PIN r_data[60]
    DIRECTION INPUT ;
    USE SIGNAL ;
    PORT
      LAYER M5 ;
        RECT  116.736 0 116.76 0.084 ;
    END
  END r_data[60]
  PIN r_data[61]
    DIRECTION INPUT ;
    USE SIGNAL ;
    PORT
      LAYER M5 ;
        RECT  116.832 0 116.856 0.084 ;
    END
  END r_data[61]
  PIN r_data[62]
    DIRECTION INPUT ;
    USE SIGNAL ;
    PORT
      LAYER M5 ;
        RECT  116.928 0 116.952 0.084 ;
    END
  END r_data[62]
  PIN r_data[63]
    DIRECTION INPUT ;
    USE SIGNAL ;
    PORT
      LAYER M5 ;
        RECT  117.024 0 117.048 0.084 ;
    END
  END r_data[63]
  PIN r_data[64]
    DIRECTION INPUT ;
    USE SIGNAL ;
    PORT
      LAYER M5 ;
        RECT  117.12 0 117.144 0.084 ;
    END
  END r_data[64]
  PIN r_data[65]
    DIRECTION INPUT ;
    USE SIGNAL ;
    PORT
      LAYER M5 ;
        RECT  117.216 0 117.24 0.084 ;
    END
  END r_data[65]
  PIN r_data[66]
    DIRECTION INPUT ;
    USE SIGNAL ;
    PORT
      LAYER M5 ;
        RECT  117.312 0 117.336 0.084 ;
    END
  END r_data[66]
  PIN r_data[67]
    DIRECTION INPUT ;
    USE SIGNAL ;
    PORT
      LAYER M5 ;
        RECT  117.408 0 117.432 0.084 ;
    END
  END r_data[67]
  PIN r_data[68]
    DIRECTION INPUT ;
    USE SIGNAL ;
    PORT
      LAYER M5 ;
        RECT  117.504 0 117.528 0.084 ;
    END
  END r_data[68]
  PIN r_data[69]
    DIRECTION INPUT ;
    USE SIGNAL ;
    PORT
      LAYER M5 ;
        RECT  117.6 0 117.624 0.084 ;
    END
  END r_data[69]
  PIN r_data[6]
    DIRECTION INPUT ;
    USE SIGNAL ;
    PORT
      LAYER M5 ;
        RECT  111.552 0 111.576 0.084 ;
    END
  END r_data[6]
  PIN r_data[70]
    DIRECTION INPUT ;
    USE SIGNAL ;
    PORT
      LAYER M5 ;
        RECT  117.696 0 117.72 0.084 ;
    END
  END r_data[70]
  PIN r_data[71]
    DIRECTION INPUT ;
    USE SIGNAL ;
    PORT
      LAYER M5 ;
        RECT  117.792 0 117.816 0.084 ;
    END
  END r_data[71]
  PIN r_data[72]
    DIRECTION INPUT ;
    USE SIGNAL ;
    PORT
      LAYER M5 ;
        RECT  117.888 0 117.912 0.084 ;
    END
  END r_data[72]
  PIN r_data[73]
    DIRECTION INPUT ;
    USE SIGNAL ;
    PORT
      LAYER M5 ;
        RECT  117.984 0 118.008 0.084 ;
    END
  END r_data[73]
  PIN r_data[74]
    DIRECTION INPUT ;
    USE SIGNAL ;
    PORT
      LAYER M5 ;
        RECT  118.08 0 118.104 0.084 ;
    END
  END r_data[74]
  PIN r_data[75]
    DIRECTION INPUT ;
    USE SIGNAL ;
    PORT
      LAYER M5 ;
        RECT  118.176 0 118.2 0.084 ;
    END
  END r_data[75]
  PIN r_data[76]
    DIRECTION INPUT ;
    USE SIGNAL ;
    PORT
      LAYER M5 ;
        RECT  118.272 0 118.296 0.084 ;
    END
  END r_data[76]
  PIN r_data[77]
    DIRECTION INPUT ;
    USE SIGNAL ;
    PORT
      LAYER M5 ;
        RECT  118.368 0 118.392 0.084 ;
    END
  END r_data[77]
  PIN r_data[78]
    DIRECTION INPUT ;
    USE SIGNAL ;
    PORT
      LAYER M5 ;
        RECT  118.464 0 118.488 0.084 ;
    END
  END r_data[78]
  PIN r_data[79]
    DIRECTION INPUT ;
    USE SIGNAL ;
    PORT
      LAYER M5 ;
        RECT  118.56 0 118.584 0.084 ;
    END
  END r_data[79]
  PIN r_data[7]
    DIRECTION INPUT ;
    USE SIGNAL ;
    PORT
      LAYER M5 ;
        RECT  111.648 0 111.672 0.084 ;
    END
  END r_data[7]
  PIN r_data[80]
    DIRECTION INPUT ;
    USE SIGNAL ;
    PORT
      LAYER M5 ;
        RECT  118.656 0 118.68 0.084 ;
    END
  END r_data[80]
  PIN r_data[81]
    DIRECTION INPUT ;
    USE SIGNAL ;
    PORT
      LAYER M5 ;
        RECT  118.752 0 118.776 0.084 ;
    END
  END r_data[81]
  PIN r_data[82]
    DIRECTION INPUT ;
    USE SIGNAL ;
    PORT
      LAYER M5 ;
        RECT  118.848 0 118.872 0.084 ;
    END
  END r_data[82]
  PIN r_data[83]
    DIRECTION INPUT ;
    USE SIGNAL ;
    PORT
      LAYER M5 ;
        RECT  118.944 0 118.968 0.084 ;
    END
  END r_data[83]
  PIN r_data[84]
    DIRECTION INPUT ;
    USE SIGNAL ;
    PORT
      LAYER M5 ;
        RECT  119.04 0 119.064 0.084 ;
    END
  END r_data[84]
  PIN r_data[85]
    DIRECTION INPUT ;
    USE SIGNAL ;
    PORT
      LAYER M5 ;
        RECT  119.136 0 119.16 0.084 ;
    END
  END r_data[85]
  PIN r_data[86]
    DIRECTION INPUT ;
    USE SIGNAL ;
    PORT
      LAYER M5 ;
        RECT  119.232 0 119.256 0.084 ;
    END
  END r_data[86]
  PIN r_data[87]
    DIRECTION INPUT ;
    USE SIGNAL ;
    PORT
      LAYER M5 ;
        RECT  119.328 0 119.352 0.084 ;
    END
  END r_data[87]
  PIN r_data[88]
    DIRECTION INPUT ;
    USE SIGNAL ;
    PORT
      LAYER M5 ;
        RECT  119.424 0 119.448 0.084 ;
    END
  END r_data[88]
  PIN r_data[89]
    DIRECTION INPUT ;
    USE SIGNAL ;
    PORT
      LAYER M5 ;
        RECT  119.52 0 119.544 0.084 ;
    END
  END r_data[89]
  PIN r_data[8]
    DIRECTION INPUT ;
    USE SIGNAL ;
    PORT
      LAYER M5 ;
        RECT  111.744 0 111.768 0.084 ;
    END
  END r_data[8]
  PIN r_data[90]
    DIRECTION INPUT ;
    USE SIGNAL ;
    PORT
      LAYER M5 ;
        RECT  119.616 0 119.64 0.084 ;
    END
  END r_data[90]
  PIN r_data[91]
    DIRECTION INPUT ;
    USE SIGNAL ;
    PORT
      LAYER M5 ;
        RECT  119.712 0 119.736 0.084 ;
    END
  END r_data[91]
  PIN r_data[92]
    DIRECTION INPUT ;
    USE SIGNAL ;
    PORT
      LAYER M5 ;
        RECT  119.808 0 119.832 0.084 ;
    END
  END r_data[92]
  PIN r_data[93]
    DIRECTION INPUT ;
    USE SIGNAL ;
    PORT
      LAYER M5 ;
        RECT  119.904 0 119.928 0.084 ;
    END
  END r_data[93]
  PIN r_data[94]
    DIRECTION INPUT ;
    USE SIGNAL ;
    PORT
      LAYER M5 ;
        RECT  120 0 120.024 0.084 ;
    END
  END r_data[94]
  PIN r_data[95]
    DIRECTION INPUT ;
    USE SIGNAL ;
    PORT
      LAYER M5 ;
        RECT  120.096 0 120.12 0.084 ;
    END
  END r_data[95]
  PIN r_data[96]
    DIRECTION INPUT ;
    USE SIGNAL ;
    PORT
      LAYER M5 ;
        RECT  120.192 0 120.216 0.084 ;
    END
  END r_data[96]
  PIN r_data[97]
    DIRECTION INPUT ;
    USE SIGNAL ;
    PORT
      LAYER M5 ;
        RECT  120.288 0 120.312 0.084 ;
    END
  END r_data[97]
  PIN r_data[98]
    DIRECTION INPUT ;
    USE SIGNAL ;
    PORT
      LAYER M5 ;
        RECT  120.384 0 120.408 0.084 ;
    END
  END r_data[98]
  PIN r_data[99]
    DIRECTION INPUT ;
    USE SIGNAL ;
    PORT
      LAYER M5 ;
        RECT  120.48 0 120.504 0.084 ;
    END
  END r_data[99]
  PIN r_data[9]
    DIRECTION INPUT ;
    USE SIGNAL ;
    PORT
      LAYER M5 ;
        RECT  111.84 0 111.864 0.084 ;
    END
  END r_data[9]
  PIN r_rdy
    DIRECTION OUTPUT ;
    USE SIGNAL ;
    PORT
      LAYER M5 ;
        RECT  135.552 0 135.576 0.084 ;
    END
  END r_rdy
  PIN r_tag[0]
    DIRECTION INPUT ;
    USE SIGNAL ;
    PORT
      LAYER M5 ;
        RECT  135.648 0 135.672 0.084 ;
    END
  END r_tag[0]
  PIN r_tag[10]
    DIRECTION INPUT ;
    USE SIGNAL ;
    PORT
      LAYER M5 ;
        RECT  136.608 0 136.632 0.084 ;
    END
  END r_tag[10]
  PIN r_tag[11]
    DIRECTION INPUT ;
    USE SIGNAL ;
    PORT
      LAYER M5 ;
        RECT  136.704 0 136.728 0.084 ;
    END
  END r_tag[11]
  PIN r_tag[12]
    DIRECTION INPUT ;
    USE SIGNAL ;
    PORT
      LAYER M5 ;
        RECT  136.8 0 136.824 0.084 ;
    END
  END r_tag[12]
  PIN r_tag[13]
    DIRECTION INPUT ;
    USE SIGNAL ;
    PORT
      LAYER M5 ;
        RECT  136.896 0 136.92 0.084 ;
    END
  END r_tag[13]
  PIN r_tag[14]
    DIRECTION INPUT ;
    USE SIGNAL ;
    PORT
      LAYER M5 ;
        RECT  136.992 0 137.016 0.084 ;
    END
  END r_tag[14]
  PIN r_tag[15]
    DIRECTION INPUT ;
    USE SIGNAL ;
    PORT
      LAYER M5 ;
        RECT  137.088 0 137.112 0.084 ;
    END
  END r_tag[15]
  PIN r_tag[16]
    DIRECTION INPUT ;
    USE SIGNAL ;
    PORT
      LAYER M5 ;
        RECT  137.184 0 137.208 0.084 ;
    END
  END r_tag[16]
  PIN r_tag[1]
    DIRECTION INPUT ;
    USE SIGNAL ;
    PORT
      LAYER M5 ;
        RECT  135.744 0 135.768 0.084 ;
    END
  END r_tag[1]
  PIN r_tag[2]
    DIRECTION INPUT ;
    USE SIGNAL ;
    PORT
      LAYER M5 ;
        RECT  135.84 0 135.864 0.084 ;
    END
  END r_tag[2]
  PIN r_tag[3]
    DIRECTION INPUT ;
    USE SIGNAL ;
    PORT
      LAYER M5 ;
        RECT  135.936 0 135.96 0.084 ;
    END
  END r_tag[3]
  PIN r_tag[4]
    DIRECTION INPUT ;
    USE SIGNAL ;
    PORT
      LAYER M5 ;
        RECT  136.032 0 136.056 0.084 ;
    END
  END r_tag[4]
  PIN r_tag[5]
    DIRECTION INPUT ;
    USE SIGNAL ;
    PORT
      LAYER M5 ;
        RECT  136.128 0 136.152 0.084 ;
    END
  END r_tag[5]
  PIN r_tag[6]
    DIRECTION INPUT ;
    USE SIGNAL ;
    PORT
      LAYER M5 ;
        RECT  136.224 0 136.248 0.084 ;
    END
  END r_tag[6]
  PIN r_tag[7]
    DIRECTION INPUT ;
    USE SIGNAL ;
    PORT
      LAYER M5 ;
        RECT  136.32 0 136.344 0.084 ;
    END
  END r_tag[7]
  PIN r_tag[8]
    DIRECTION INPUT ;
    USE SIGNAL ;
    PORT
      LAYER M5 ;
        RECT  136.416 0 136.44 0.084 ;
    END
  END r_tag[8]
  PIN r_tag[9]
    DIRECTION INPUT ;
    USE SIGNAL ;
    PORT
      LAYER M5 ;
        RECT  136.512 0 136.536 0.084 ;
    END
  END r_tag[9]
  PIN r_v
    DIRECTION INPUT ;
    USE SIGNAL ;
    PORT
      LAYER M5 ;
        RECT  137.28 0 137.304 0.084 ;
    END
  END r_v
  PIN rst_n
    DIRECTION INPUT ;
    USE SIGNAL ;
    PORT
      LAYER M5 ;
        RECT  314.976 63.916 315 64 ;
    END
  END rst_n
  PIN VDD
    DIRECTION INOUT ;
    USE POWER ;
    PORT
      LAYER M6 ;
        RECT  1.08 61.233 373.896 61.521 ;
        RECT  1.08 55.833 373.896 56.121 ;
        RECT  1.08 50.433 373.896 50.721 ;
        RECT  1.08 45.033 373.896 45.321 ;
        RECT  1.08 39.633 373.896 39.921 ;
        RECT  1.08 34.233 373.896 34.521 ;
        RECT  1.08 28.833 373.896 29.121 ;
        RECT  1.08 23.433 373.896 23.721 ;
        RECT  1.08 18.033 373.896 18.321 ;
        RECT  1.08 12.633 373.896 12.921 ;
        RECT  1.08 7.233 373.896 7.521 ;
        RECT  1.08 1.833 373.896 2.121 ;
    END
  END VDD
  PIN VSS
    DIRECTION INOUT ;
    USE GROUND ;
    PORT
      LAYER M6 ;
        RECT  1.08 60.849 373.896 61.137 ;
        RECT  1.08 55.449 373.896 55.737 ;
        RECT  1.08 50.049 373.896 50.337 ;
        RECT  1.08 44.649 373.896 44.937 ;
        RECT  1.08 39.249 373.896 39.537 ;
        RECT  1.08 33.849 373.896 34.137 ;
        RECT  1.08 28.449 373.896 28.737 ;
        RECT  1.08 23.049 373.896 23.337 ;
        RECT  1.08 17.649 373.896 17.937 ;
        RECT  1.08 12.249 373.896 12.537 ;
        RECT  1.08 6.849 373.896 7.137 ;
        RECT  1.08 1.449 373.896 1.737 ;
    END
  END VSS
  OBS
    LAYER RVTN ;
     RECT  1.08 0 373.896 64 ;
    LAYER RVTP ;
     RECT  1.08 0 373.896 64 ;
    LAYER M1 ;
     RECT  1.08 0 373.896 64 ;
    LAYER M2 ;
     RECT  1.08 0 373.896 64 ;
    LAYER M3 ;
     RECT  1.08 0 373.896 64 ;
    LAYER M4 ;
     RECT  1.08 0 373.896 64 ;
    LAYER M5 ;
     RECT  1.08 0 373.896 64 ;
    LAYER M6 ;
     RECT  1.08 0 373.896 64 ;
    LAYER M7 ;
     RECT  1.08 0 373.896 64 ;
  END
END ot_chip_v41x_karb_slice
END LIBRARY
